VERSION 5.8 ;
BUSBITCHARS "[]" ;
DIVIDERCHAR "/" ;
UNITS
    DATABASE MICRONS 1000 ;
END UNITS

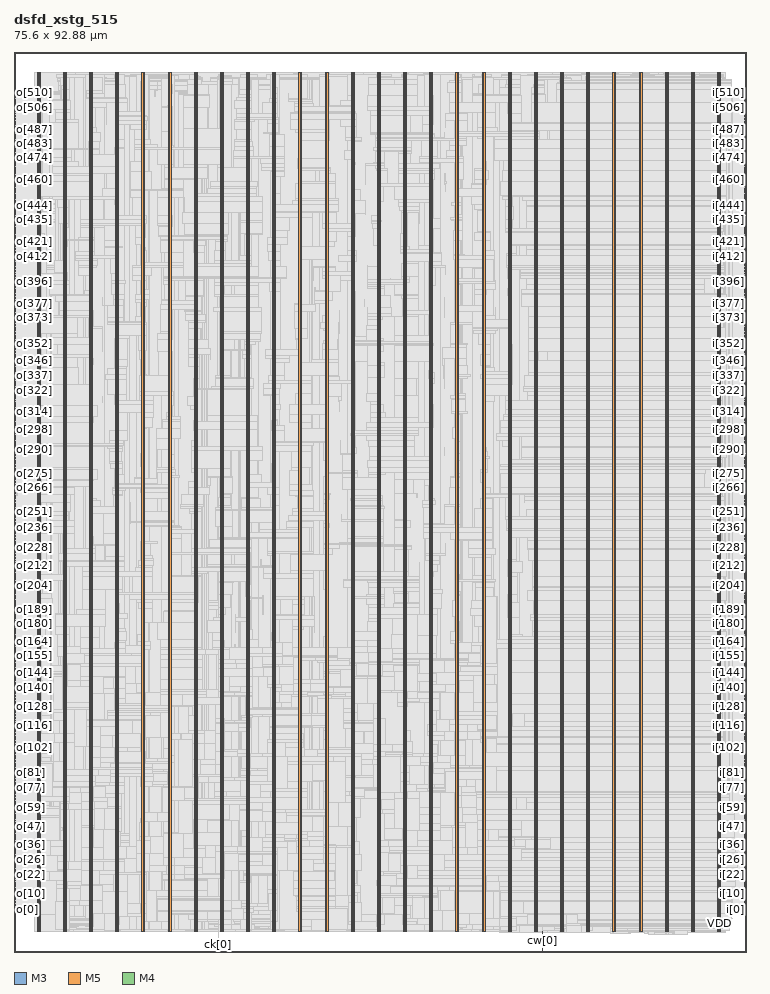
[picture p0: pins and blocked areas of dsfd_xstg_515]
MACRO dsfd_xstg_515
  FOREIGN dsfd_xstg_515 0 0 ;
  CLASS BLOCK ;
  SIZE 75.6 BY 92.88 ;
  PIN ck[0]
    DIRECTION INPUT ;
    USE SIGNAL ;
    PORT
      LAYER M3 ;
        RECT  21.06 0 21.078 0.144 ;
    END
    PORT
      LAYER M3 ;
        RECT  21.06 0.108 21.078 0.173 ;
    END
  END ck[0]
  PIN cw[0]
    DIRECTION INPUT ;
    USE SIGNAL ;
    PORT
      LAYER M5 ;
        RECT  54.528 0 54.552 0.192 ;
    END
    PORT
      LAYER M5 ;
        RECT  54.528 0.144 54.552 2.137 ;
    END
  END cw[0]
  PIN i[0]
    DIRECTION INPUT ;
    USE SIGNAL ;
    PORT
      LAYER M4 ;
        RECT  75.408 4.416 75.6 4.44 ;
    END
  END i[0]
  PIN i[100]
    DIRECTION INPUT ;
    USE SIGNAL ;
    PORT
      LAYER M4 ;
        RECT  75.408 20.784 75.6 20.808 ;
    END
  END i[100]
  PIN i[101]
    DIRECTION INPUT ;
    USE SIGNAL ;
    PORT
      LAYER M4 ;
        RECT  75.408 20.928 75.6 20.952 ;
    END
  END i[101]
  PIN i[102]
    DIRECTION INPUT ;
    USE SIGNAL ;
    PORT
      LAYER M4 ;
        RECT  75.408 21.12 75.6 21.144 ;
    END
  END i[102]
  PIN i[103]
    DIRECTION INPUT ;
    USE SIGNAL ;
    PORT
      LAYER M4 ;
        RECT  75.408 21.264 75.6 21.288 ;
    END
  END i[103]
  PIN i[104]
    DIRECTION INPUT ;
    USE SIGNAL ;
    PORT
      LAYER M4 ;
        RECT  75.408 21.408 75.6 21.432 ;
    END
  END i[104]
  PIN i[105]
    DIRECTION INPUT ;
    USE SIGNAL ;
    PORT
      LAYER M4 ;
        RECT  75.408 21.6 75.6 21.624 ;
    END
  END i[105]
  PIN i[106]
    DIRECTION INPUT ;
    USE SIGNAL ;
    PORT
      LAYER M4 ;
        RECT  75.408 21.744 75.6 21.768 ;
    END
  END i[106]
  PIN i[107]
    DIRECTION INPUT ;
    USE SIGNAL ;
    PORT
      LAYER M4 ;
        RECT  75.408 21.936 75.6 21.96 ;
    END
  END i[107]
  PIN i[108]
    DIRECTION INPUT ;
    USE SIGNAL ;
    PORT
      LAYER M4 ;
        RECT  75.408 22.08 75.6 22.104 ;
    END
  END i[108]
  PIN i[109]
    DIRECTION INPUT ;
    USE SIGNAL ;
    PORT
      LAYER M4 ;
        RECT  75.408 22.224 75.6 22.248 ;
    END
  END i[109]
  PIN i[10]
    DIRECTION INPUT ;
    USE SIGNAL ;
    PORT
      LAYER M4 ;
        RECT  75.408 6.048 75.6 6.072 ;
    END
  END i[10]
  PIN i[110]
    DIRECTION INPUT ;
    USE SIGNAL ;
    PORT
      LAYER M4 ;
        RECT  75.408 22.416 75.6 22.44 ;
    END
  END i[110]
  PIN i[111]
    DIRECTION INPUT ;
    USE SIGNAL ;
    PORT
      LAYER M4 ;
        RECT  75.408 22.56 75.6 22.584 ;
    END
  END i[111]
  PIN i[112]
    DIRECTION INPUT ;
    USE SIGNAL ;
    PORT
      LAYER M4 ;
        RECT  75.408 22.752 75.6 22.776 ;
    END
  END i[112]
  PIN i[113]
    DIRECTION INPUT ;
    USE SIGNAL ;
    PORT
      LAYER M4 ;
        RECT  75.408 22.896 75.6 22.92 ;
    END
  END i[113]
  PIN i[114]
    DIRECTION INPUT ;
    USE SIGNAL ;
    PORT
      LAYER M4 ;
        RECT  75.408 23.04 75.6 23.064 ;
    END
  END i[114]
  PIN i[115]
    DIRECTION INPUT ;
    USE SIGNAL ;
    PORT
      LAYER M4 ;
        RECT  75.408 23.232 75.6 23.256 ;
    END
  END i[115]
  PIN i[116]
    DIRECTION INPUT ;
    USE SIGNAL ;
    PORT
      LAYER M4 ;
        RECT  75.408 23.376 75.6 23.4 ;
    END
  END i[116]
  PIN i[117]
    DIRECTION INPUT ;
    USE SIGNAL ;
    PORT
      LAYER M4 ;
        RECT  75.408 23.568 75.6 23.592 ;
    END
  END i[117]
  PIN i[118]
    DIRECTION INPUT ;
    USE SIGNAL ;
    PORT
      LAYER M4 ;
        RECT  75.408 23.712 75.6 23.736 ;
    END
  END i[118]
  PIN i[119]
    DIRECTION INPUT ;
    USE SIGNAL ;
    PORT
      LAYER M4 ;
        RECT  75.408 23.856 75.6 23.88 ;
    END
  END i[119]
  PIN i[11]
    DIRECTION INPUT ;
    USE SIGNAL ;
    PORT
      LAYER M4 ;
        RECT  75.408 6.192 75.6 6.216 ;
    END
  END i[11]
  PIN i[120]
    DIRECTION INPUT ;
    USE SIGNAL ;
    PORT
      LAYER M4 ;
        RECT  75.408 24.048 75.6 24.072 ;
    END
  END i[120]
  PIN i[121]
    DIRECTION INPUT ;
    USE SIGNAL ;
    PORT
      LAYER M4 ;
        RECT  75.408 24.192 75.6 24.216 ;
    END
  END i[121]
  PIN i[122]
    DIRECTION INPUT ;
    USE SIGNAL ;
    PORT
      LAYER M4 ;
        RECT  75.408 24.384 75.6 24.408 ;
    END
  END i[122]
  PIN i[123]
    DIRECTION INPUT ;
    USE SIGNAL ;
    PORT
      LAYER M4 ;
        RECT  75.408 24.528 75.6 24.552 ;
    END
  END i[123]
  PIN i[124]
    DIRECTION INPUT ;
    USE SIGNAL ;
    PORT
      LAYER M4 ;
        RECT  75.408 24.72 75.6 24.744 ;
    END
  END i[124]
  PIN i[125]
    DIRECTION INPUT ;
    USE SIGNAL ;
    PORT
      LAYER M4 ;
        RECT  75.408 24.864 75.6 24.888 ;
    END
  END i[125]
  PIN i[126]
    DIRECTION INPUT ;
    USE SIGNAL ;
    PORT
      LAYER M4 ;
        RECT  75.408 25.008 75.6 25.032 ;
    END
  END i[126]
  PIN i[127]
    DIRECTION INPUT ;
    USE SIGNAL ;
    PORT
      LAYER M4 ;
        RECT  75.408 25.2 75.6 25.224 ;
    END
  END i[127]
  PIN i[128]
    DIRECTION INPUT ;
    USE SIGNAL ;
    PORT
      LAYER M4 ;
        RECT  75.408 25.344 75.6 25.368 ;
    END
  END i[128]
  PIN i[129]
    DIRECTION INPUT ;
    USE SIGNAL ;
    PORT
      LAYER M4 ;
        RECT  75.408 25.536 75.6 25.56 ;
    END
  END i[129]
  PIN i[12]
    DIRECTION INPUT ;
    USE SIGNAL ;
    PORT
      LAYER M4 ;
        RECT  75.408 6.384 75.6 6.408 ;
    END
  END i[12]
  PIN i[130]
    DIRECTION INPUT ;
    USE SIGNAL ;
    PORT
      LAYER M4 ;
        RECT  75.408 25.68 75.6 25.704 ;
    END
  END i[130]
  PIN i[131]
    DIRECTION INPUT ;
    USE SIGNAL ;
    PORT
      LAYER M4 ;
        RECT  75.408 25.824 75.6 25.848 ;
    END
  END i[131]
  PIN i[132]
    DIRECTION INPUT ;
    USE SIGNAL ;
    PORT
      LAYER M4 ;
        RECT  75.408 26.016 75.6 26.04 ;
    END
  END i[132]
  PIN i[133]
    DIRECTION INPUT ;
    USE SIGNAL ;
    PORT
      LAYER M4 ;
        RECT  75.408 26.16 75.6 26.184 ;
    END
  END i[133]
  PIN i[134]
    DIRECTION INPUT ;
    USE SIGNAL ;
    PORT
      LAYER M4 ;
        RECT  75.408 26.352 75.6 26.376 ;
    END
  END i[134]
  PIN i[135]
    DIRECTION INPUT ;
    USE SIGNAL ;
    PORT
      LAYER M4 ;
        RECT  75.408 26.496 75.6 26.52 ;
    END
  END i[135]
  PIN i[136]
    DIRECTION INPUT ;
    USE SIGNAL ;
    PORT
      LAYER M4 ;
        RECT  75.408 26.64 75.6 26.664 ;
    END
  END i[136]
  PIN i[137]
    DIRECTION INPUT ;
    USE SIGNAL ;
    PORT
      LAYER M4 ;
        RECT  75.408 26.832 75.6 26.856 ;
    END
  END i[137]
  PIN i[138]
    DIRECTION INPUT ;
    USE SIGNAL ;
    PORT
      LAYER M4 ;
        RECT  75.408 26.976 75.6 27 ;
    END
  END i[138]
  PIN i[139]
    DIRECTION INPUT ;
    USE SIGNAL ;
    PORT
      LAYER M4 ;
        RECT  75.408 27.168 75.6 27.192 ;
    END
  END i[139]
  PIN i[13]
    DIRECTION INPUT ;
    USE SIGNAL ;
    PORT
      LAYER M4 ;
        RECT  75.408 6.528 75.6 6.552 ;
    END
  END i[13]
  PIN i[140]
    DIRECTION INPUT ;
    USE SIGNAL ;
    PORT
      LAYER M4 ;
        RECT  75.408 27.312 75.6 27.336 ;
    END
  END i[140]
  PIN i[141]
    DIRECTION INPUT ;
    USE SIGNAL ;
    PORT
      LAYER M4 ;
        RECT  75.408 27.456 75.6 27.48 ;
    END
  END i[141]
  PIN i[142]
    DIRECTION INPUT ;
    USE SIGNAL ;
    PORT
      LAYER M4 ;
        RECT  75.408 27.648 75.6 27.672 ;
    END
  END i[142]
  PIN i[143]
    DIRECTION INPUT ;
    USE SIGNAL ;
    PORT
      LAYER M4 ;
        RECT  75.408 27.792 75.6 27.816 ;
    END
  END i[143]
  PIN i[144]
    DIRECTION INPUT ;
    USE SIGNAL ;
    PORT
      LAYER M4 ;
        RECT  75.408 27.984 75.6 28.008 ;
    END
  END i[144]
  PIN i[145]
    DIRECTION INPUT ;
    USE SIGNAL ;
    PORT
      LAYER M4 ;
        RECT  75.408 28.128 75.6 28.152 ;
    END
  END i[145]
  PIN i[146]
    DIRECTION INPUT ;
    USE SIGNAL ;
    PORT
      LAYER M4 ;
        RECT  75.408 28.272 75.6 28.296 ;
    END
  END i[146]
  PIN i[147]
    DIRECTION INPUT ;
    USE SIGNAL ;
    PORT
      LAYER M4 ;
        RECT  75.408 28.464 75.6 28.488 ;
    END
  END i[147]
  PIN i[148]
    DIRECTION INPUT ;
    USE SIGNAL ;
    PORT
      LAYER M4 ;
        RECT  75.408 28.608 75.6 28.632 ;
    END
  END i[148]
  PIN i[149]
    DIRECTION INPUT ;
    USE SIGNAL ;
    PORT
      LAYER M4 ;
        RECT  75.408 28.8 75.6 28.824 ;
    END
  END i[149]
  PIN i[14]
    DIRECTION INPUT ;
    USE SIGNAL ;
    PORT
      LAYER M4 ;
        RECT  75.408 6.72 75.6 6.744 ;
    END
  END i[14]
  PIN i[150]
    DIRECTION INPUT ;
    USE SIGNAL ;
    PORT
      LAYER M4 ;
        RECT  75.408 28.944 75.6 28.968 ;
    END
  END i[150]
  PIN i[151]
    DIRECTION INPUT ;
    USE SIGNAL ;
    PORT
      LAYER M4 ;
        RECT  75.408 29.136 75.6 29.16 ;
    END
  END i[151]
  PIN i[152]
    DIRECTION INPUT ;
    USE SIGNAL ;
    PORT
      LAYER M4 ;
        RECT  75.408 29.28 75.6 29.304 ;
    END
  END i[152]
  PIN i[153]
    DIRECTION INPUT ;
    USE SIGNAL ;
    PORT
      LAYER M4 ;
        RECT  75.408 29.424 75.6 29.448 ;
    END
  END i[153]
  PIN i[154]
    DIRECTION INPUT ;
    USE SIGNAL ;
    PORT
      LAYER M4 ;
        RECT  75.408 29.616 75.6 29.64 ;
    END
  END i[154]
  PIN i[155]
    DIRECTION INPUT ;
    USE SIGNAL ;
    PORT
      LAYER M4 ;
        RECT  75.408 29.76 75.6 29.784 ;
    END
  END i[155]
  PIN i[156]
    DIRECTION INPUT ;
    USE SIGNAL ;
    PORT
      LAYER M4 ;
        RECT  75.408 29.952 75.6 29.976 ;
    END
  END i[156]
  PIN i[157]
    DIRECTION INPUT ;
    USE SIGNAL ;
    PORT
      LAYER M4 ;
        RECT  75.408 30.096 75.6 30.12 ;
    END
  END i[157]
  PIN i[158]
    DIRECTION INPUT ;
    USE SIGNAL ;
    PORT
      LAYER M4 ;
        RECT  75.408 30.24 75.6 30.264 ;
    END
  END i[158]
  PIN i[159]
    DIRECTION INPUT ;
    USE SIGNAL ;
    PORT
      LAYER M4 ;
        RECT  75.408 30.432 75.6 30.456 ;
    END
  END i[159]
  PIN i[15]
    DIRECTION INPUT ;
    USE SIGNAL ;
    PORT
      LAYER M4 ;
        RECT  75.408 6.864 75.6 6.888 ;
    END
  END i[15]
  PIN i[160]
    DIRECTION INPUT ;
    USE SIGNAL ;
    PORT
      LAYER M4 ;
        RECT  75.408 30.576 75.6 30.6 ;
    END
  END i[160]
  PIN i[161]
    DIRECTION INPUT ;
    USE SIGNAL ;
    PORT
      LAYER M4 ;
        RECT  75.408 30.768 75.6 30.792 ;
    END
  END i[161]
  PIN i[162]
    DIRECTION INPUT ;
    USE SIGNAL ;
    PORT
      LAYER M4 ;
        RECT  75.408 30.912 75.6 30.936 ;
    END
  END i[162]
  PIN i[163]
    DIRECTION INPUT ;
    USE SIGNAL ;
    PORT
      LAYER M4 ;
        RECT  75.408 31.056 75.6 31.08 ;
    END
  END i[163]
  PIN i[164]
    DIRECTION INPUT ;
    USE SIGNAL ;
    PORT
      LAYER M4 ;
        RECT  75.408 31.248 75.6 31.272 ;
    END
  END i[164]
  PIN i[165]
    DIRECTION INPUT ;
    USE SIGNAL ;
    PORT
      LAYER M4 ;
        RECT  75.408 31.392 75.6 31.416 ;
    END
  END i[165]
  PIN i[166]
    DIRECTION INPUT ;
    USE SIGNAL ;
    PORT
      LAYER M4 ;
        RECT  75.408 31.584 75.6 31.608 ;
    END
  END i[166]
  PIN i[167]
    DIRECTION INPUT ;
    USE SIGNAL ;
    PORT
      LAYER M4 ;
        RECT  75.408 31.728 75.6 31.752 ;
    END
  END i[167]
  PIN i[168]
    DIRECTION INPUT ;
    USE SIGNAL ;
    PORT
      LAYER M4 ;
        RECT  75.408 31.872 75.6 31.896 ;
    END
  END i[168]
  PIN i[169]
    DIRECTION INPUT ;
    USE SIGNAL ;
    PORT
      LAYER M4 ;
        RECT  75.408 32.064 75.6 32.088 ;
    END
  END i[169]
  PIN i[16]
    DIRECTION INPUT ;
    USE SIGNAL ;
    PORT
      LAYER M4 ;
        RECT  75.408 7.008 75.6 7.032 ;
    END
  END i[16]
  PIN i[170]
    DIRECTION INPUT ;
    USE SIGNAL ;
    PORT
      LAYER M4 ;
        RECT  75.408 32.208 75.6 32.232 ;
    END
  END i[170]
  PIN i[171]
    DIRECTION INPUT ;
    USE SIGNAL ;
    PORT
      LAYER M4 ;
        RECT  75.408 32.4 75.6 32.424 ;
    END
  END i[171]
  PIN i[172]
    DIRECTION INPUT ;
    USE SIGNAL ;
    PORT
      LAYER M4 ;
        RECT  75.408 32.544 75.6 32.568 ;
    END
  END i[172]
  PIN i[173]
    DIRECTION INPUT ;
    USE SIGNAL ;
    PORT
      LAYER M4 ;
        RECT  75.408 32.688 75.6 32.712 ;
    END
  END i[173]
  PIN i[174]
    DIRECTION INPUT ;
    USE SIGNAL ;
    PORT
      LAYER M4 ;
        RECT  75.408 32.88 75.6 32.904 ;
    END
  END i[174]
  PIN i[175]
    DIRECTION INPUT ;
    USE SIGNAL ;
    PORT
      LAYER M4 ;
        RECT  75.408 33.024 75.6 33.048 ;
    END
  END i[175]
  PIN i[176]
    DIRECTION INPUT ;
    USE SIGNAL ;
    PORT
      LAYER M4 ;
        RECT  75.408 33.216 75.6 33.24 ;
    END
  END i[176]
  PIN i[177]
    DIRECTION INPUT ;
    USE SIGNAL ;
    PORT
      LAYER M4 ;
        RECT  75.408 33.36 75.6 33.384 ;
    END
  END i[177]
  PIN i[178]
    DIRECTION INPUT ;
    USE SIGNAL ;
    PORT
      LAYER M4 ;
        RECT  75.408 33.552 75.6 33.576 ;
    END
  END i[178]
  PIN i[179]
    DIRECTION INPUT ;
    USE SIGNAL ;
    PORT
      LAYER M4 ;
        RECT  75.408 33.696 75.6 33.72 ;
    END
  END i[179]
  PIN i[17]
    DIRECTION INPUT ;
    USE SIGNAL ;
    PORT
      LAYER M4 ;
        RECT  75.408 7.2 75.6 7.224 ;
    END
  END i[17]
  PIN i[180]
    DIRECTION INPUT ;
    USE SIGNAL ;
    PORT
      LAYER M4 ;
        RECT  75.408 33.84 75.6 33.864 ;
    END
  END i[180]
  PIN i[181]
    DIRECTION INPUT ;
    USE SIGNAL ;
    PORT
      LAYER M4 ;
        RECT  75.408 34.032 75.6 34.056 ;
    END
  END i[181]
  PIN i[182]
    DIRECTION INPUT ;
    USE SIGNAL ;
    PORT
      LAYER M4 ;
        RECT  75.408 34.176 75.6 34.2 ;
    END
  END i[182]
  PIN i[183]
    DIRECTION INPUT ;
    USE SIGNAL ;
    PORT
      LAYER M4 ;
        RECT  75.408 34.368 75.6 34.392 ;
    END
  END i[183]
  PIN i[184]
    DIRECTION INPUT ;
    USE SIGNAL ;
    PORT
      LAYER M4 ;
        RECT  75.408 34.512 75.6 34.536 ;
    END
  END i[184]
  PIN i[185]
    DIRECTION INPUT ;
    USE SIGNAL ;
    PORT
      LAYER M4 ;
        RECT  75.408 34.656 75.6 34.68 ;
    END
  END i[185]
  PIN i[186]
    DIRECTION INPUT ;
    USE SIGNAL ;
    PORT
      LAYER M4 ;
        RECT  75.408 34.848 75.6 34.872 ;
    END
  END i[186]
  PIN i[187]
    DIRECTION INPUT ;
    USE SIGNAL ;
    PORT
      LAYER M4 ;
        RECT  75.408 34.992 75.6 35.016 ;
    END
  END i[187]
  PIN i[188]
    DIRECTION INPUT ;
    USE SIGNAL ;
    PORT
      LAYER M4 ;
        RECT  75.408 35.184 75.6 35.208 ;
    END
  END i[188]
  PIN i[189]
    DIRECTION INPUT ;
    USE SIGNAL ;
    PORT
      LAYER M4 ;
        RECT  75.408 35.328 75.6 35.352 ;
    END
  END i[189]
  PIN i[18]
    DIRECTION INPUT ;
    USE SIGNAL ;
    PORT
      LAYER M4 ;
        RECT  75.408 7.344 75.6 7.368 ;
    END
  END i[18]
  PIN i[190]
    DIRECTION INPUT ;
    USE SIGNAL ;
    PORT
      LAYER M4 ;
        RECT  75.408 35.472 75.6 35.496 ;
    END
  END i[190]
  PIN i[191]
    DIRECTION INPUT ;
    USE SIGNAL ;
    PORT
      LAYER M4 ;
        RECT  75.408 35.664 75.6 35.688 ;
    END
  END i[191]
  PIN i[192]
    DIRECTION INPUT ;
    USE SIGNAL ;
    PORT
      LAYER M4 ;
        RECT  75.408 35.808 75.6 35.832 ;
    END
  END i[192]
  PIN i[193]
    DIRECTION INPUT ;
    USE SIGNAL ;
    PORT
      LAYER M4 ;
        RECT  75.408 36 75.6 36.024 ;
    END
  END i[193]
  PIN i[194]
    DIRECTION INPUT ;
    USE SIGNAL ;
    PORT
      LAYER M4 ;
        RECT  75.408 36.144 75.6 36.168 ;
    END
  END i[194]
  PIN i[195]
    DIRECTION INPUT ;
    USE SIGNAL ;
    PORT
      LAYER M4 ;
        RECT  75.408 36.288 75.6 36.312 ;
    END
  END i[195]
  PIN i[196]
    DIRECTION INPUT ;
    USE SIGNAL ;
    PORT
      LAYER M4 ;
        RECT  75.408 36.48 75.6 36.504 ;
    END
  END i[196]
  PIN i[197]
    DIRECTION INPUT ;
    USE SIGNAL ;
    PORT
      LAYER M4 ;
        RECT  75.408 36.624 75.6 36.648 ;
    END
  END i[197]
  PIN i[198]
    DIRECTION INPUT ;
    USE SIGNAL ;
    PORT
      LAYER M4 ;
        RECT  75.408 36.816 75.6 36.84 ;
    END
  END i[198]
  PIN i[199]
    DIRECTION INPUT ;
    USE SIGNAL ;
    PORT
      LAYER M4 ;
        RECT  75.408 36.96 75.6 36.984 ;
    END
  END i[199]
  PIN i[19]
    DIRECTION INPUT ;
    USE SIGNAL ;
    PORT
      LAYER M4 ;
        RECT  75.408 7.536 75.6 7.56 ;
    END
  END i[19]
  PIN i[1]
    DIRECTION INPUT ;
    USE SIGNAL ;
    PORT
      LAYER M4 ;
        RECT  75.408 4.56 75.6 4.584 ;
    END
  END i[1]
  PIN i[200]
    DIRECTION INPUT ;
    USE SIGNAL ;
    PORT
      LAYER M4 ;
        RECT  75.408 37.152 75.6 37.176 ;
    END
  END i[200]
  PIN i[201]
    DIRECTION INPUT ;
    USE SIGNAL ;
    PORT
      LAYER M4 ;
        RECT  75.408 37.296 75.6 37.32 ;
    END
  END i[201]
  PIN i[202]
    DIRECTION INPUT ;
    USE SIGNAL ;
    PORT
      LAYER M4 ;
        RECT  75.408 37.44 75.6 37.464 ;
    END
  END i[202]
  PIN i[203]
    DIRECTION INPUT ;
    USE SIGNAL ;
    PORT
      LAYER M4 ;
        RECT  75.408 37.632 75.6 37.656 ;
    END
  END i[203]
  PIN i[204]
    DIRECTION INPUT ;
    USE SIGNAL ;
    PORT
      LAYER M4 ;
        RECT  75.408 37.776 75.6 37.8 ;
    END
  END i[204]
  PIN i[205]
    DIRECTION INPUT ;
    USE SIGNAL ;
    PORT
      LAYER M4 ;
        RECT  75.408 37.968 75.6 37.992 ;
    END
  END i[205]
  PIN i[206]
    DIRECTION INPUT ;
    USE SIGNAL ;
    PORT
      LAYER M4 ;
        RECT  75.408 38.112 75.6 38.136 ;
    END
  END i[206]
  PIN i[207]
    DIRECTION INPUT ;
    USE SIGNAL ;
    PORT
      LAYER M4 ;
        RECT  75.408 38.256 75.6 38.28 ;
    END
  END i[207]
  PIN i[208]
    DIRECTION INPUT ;
    USE SIGNAL ;
    PORT
      LAYER M4 ;
        RECT  75.408 38.448 75.6 38.472 ;
    END
  END i[208]
  PIN i[209]
    DIRECTION INPUT ;
    USE SIGNAL ;
    PORT
      LAYER M4 ;
        RECT  75.408 38.592 75.6 38.616 ;
    END
  END i[209]
  PIN i[20]
    DIRECTION INPUT ;
    USE SIGNAL ;
    PORT
      LAYER M4 ;
        RECT  75.408 7.68 75.6 7.704 ;
    END
  END i[20]
  PIN i[210]
    DIRECTION INPUT ;
    USE SIGNAL ;
    PORT
      LAYER M4 ;
        RECT  75.408 38.784 75.6 38.808 ;
    END
  END i[210]
  PIN i[211]
    DIRECTION INPUT ;
    USE SIGNAL ;
    PORT
      LAYER M4 ;
        RECT  75.408 38.928 75.6 38.952 ;
    END
  END i[211]
  PIN i[212]
    DIRECTION INPUT ;
    USE SIGNAL ;
    PORT
      LAYER M4 ;
        RECT  75.408 39.072 75.6 39.096 ;
    END
  END i[212]
  PIN i[213]
    DIRECTION INPUT ;
    USE SIGNAL ;
    PORT
      LAYER M4 ;
        RECT  75.408 39.264 75.6 39.288 ;
    END
  END i[213]
  PIN i[214]
    DIRECTION INPUT ;
    USE SIGNAL ;
    PORT
      LAYER M4 ;
        RECT  75.408 39.408 75.6 39.432 ;
    END
  END i[214]
  PIN i[215]
    DIRECTION INPUT ;
    USE SIGNAL ;
    PORT
      LAYER M4 ;
        RECT  75.408 39.6 75.6 39.624 ;
    END
  END i[215]
  PIN i[216]
    DIRECTION INPUT ;
    USE SIGNAL ;
    PORT
      LAYER M4 ;
        RECT  75.408 39.744 75.6 39.768 ;
    END
  END i[216]
  PIN i[217]
    DIRECTION INPUT ;
    USE SIGNAL ;
    PORT
      LAYER M4 ;
        RECT  75.408 39.888 75.6 39.912 ;
    END
  END i[217]
  PIN i[218]
    DIRECTION INPUT ;
    USE SIGNAL ;
    PORT
      LAYER M4 ;
        RECT  75.408 40.08 75.6 40.104 ;
    END
  END i[218]
  PIN i[219]
    DIRECTION INPUT ;
    USE SIGNAL ;
    PORT
      LAYER M4 ;
        RECT  75.408 40.224 75.6 40.248 ;
    END
  END i[219]
  PIN i[21]
    DIRECTION INPUT ;
    USE SIGNAL ;
    PORT
      LAYER M4 ;
        RECT  75.408 7.872 75.6 7.896 ;
    END
  END i[21]
  PIN i[220]
    DIRECTION INPUT ;
    USE SIGNAL ;
    PORT
      LAYER M4 ;
        RECT  75.408 40.416 75.6 40.44 ;
    END
  END i[220]
  PIN i[221]
    DIRECTION INPUT ;
    USE SIGNAL ;
    PORT
      LAYER M4 ;
        RECT  75.408 40.56 75.6 40.584 ;
    END
  END i[221]
  PIN i[222]
    DIRECTION INPUT ;
    USE SIGNAL ;
    PORT
      LAYER M4 ;
        RECT  75.408 40.704 75.6 40.728 ;
    END
  END i[222]
  PIN i[223]
    DIRECTION INPUT ;
    USE SIGNAL ;
    PORT
      LAYER M4 ;
        RECT  75.408 40.896 75.6 40.92 ;
    END
  END i[223]
  PIN i[224]
    DIRECTION INPUT ;
    USE SIGNAL ;
    PORT
      LAYER M4 ;
        RECT  75.408 41.04 75.6 41.064 ;
    END
  END i[224]
  PIN i[225]
    DIRECTION INPUT ;
    USE SIGNAL ;
    PORT
      LAYER M4 ;
        RECT  75.408 41.232 75.6 41.256 ;
    END
  END i[225]
  PIN i[226]
    DIRECTION INPUT ;
    USE SIGNAL ;
    PORT
      LAYER M4 ;
        RECT  75.408 41.376 75.6 41.4 ;
    END
  END i[226]
  PIN i[227]
    DIRECTION INPUT ;
    USE SIGNAL ;
    PORT
      LAYER M4 ;
        RECT  75.408 41.568 75.6 41.592 ;
    END
  END i[227]
  PIN i[228]
    DIRECTION INPUT ;
    USE SIGNAL ;
    PORT
      LAYER M4 ;
        RECT  75.408 41.712 75.6 41.736 ;
    END
  END i[228]
  PIN i[229]
    DIRECTION INPUT ;
    USE SIGNAL ;
    PORT
      LAYER M4 ;
        RECT  75.408 41.856 75.6 41.88 ;
    END
  END i[229]
  PIN i[22]
    DIRECTION INPUT ;
    USE SIGNAL ;
    PORT
      LAYER M4 ;
        RECT  75.408 8.016 75.6 8.04 ;
    END
  END i[22]
  PIN i[230]
    DIRECTION INPUT ;
    USE SIGNAL ;
    PORT
      LAYER M4 ;
        RECT  75.408 42.048 75.6 42.072 ;
    END
  END i[230]
  PIN i[231]
    DIRECTION INPUT ;
    USE SIGNAL ;
    PORT
      LAYER M4 ;
        RECT  75.408 42.192 75.6 42.216 ;
    END
  END i[231]
  PIN i[232]
    DIRECTION INPUT ;
    USE SIGNAL ;
    PORT
      LAYER M4 ;
        RECT  75.408 42.384 75.6 42.408 ;
    END
  END i[232]
  PIN i[233]
    DIRECTION INPUT ;
    USE SIGNAL ;
    PORT
      LAYER M4 ;
        RECT  75.408 42.528 75.6 42.552 ;
    END
  END i[233]
  PIN i[234]
    DIRECTION INPUT ;
    USE SIGNAL ;
    PORT
      LAYER M4 ;
        RECT  75.408 42.672 75.6 42.696 ;
    END
  END i[234]
  PIN i[235]
    DIRECTION INPUT ;
    USE SIGNAL ;
    PORT
      LAYER M4 ;
        RECT  75.408 42.864 75.6 42.888 ;
    END
  END i[235]
  PIN i[236]
    DIRECTION INPUT ;
    USE SIGNAL ;
    PORT
      LAYER M4 ;
        RECT  75.408 43.008 75.6 43.032 ;
    END
  END i[236]
  PIN i[237]
    DIRECTION INPUT ;
    USE SIGNAL ;
    PORT
      LAYER M4 ;
        RECT  75.408 43.2 75.6 43.224 ;
    END
  END i[237]
  PIN i[238]
    DIRECTION INPUT ;
    USE SIGNAL ;
    PORT
      LAYER M4 ;
        RECT  75.408 43.344 75.6 43.368 ;
    END
  END i[238]
  PIN i[239]
    DIRECTION INPUT ;
    USE SIGNAL ;
    PORT
      LAYER M4 ;
        RECT  75.408 43.488 75.6 43.512 ;
    END
  END i[239]
  PIN i[23]
    DIRECTION INPUT ;
    USE SIGNAL ;
    PORT
      LAYER M4 ;
        RECT  75.408 8.16 75.6 8.184 ;
    END
  END i[23]
  PIN i[240]
    DIRECTION INPUT ;
    USE SIGNAL ;
    PORT
      LAYER M4 ;
        RECT  75.408 43.68 75.6 43.704 ;
    END
  END i[240]
  PIN i[241]
    DIRECTION INPUT ;
    USE SIGNAL ;
    PORT
      LAYER M4 ;
        RECT  75.408 43.824 75.6 43.848 ;
    END
  END i[241]
  PIN i[242]
    DIRECTION INPUT ;
    USE SIGNAL ;
    PORT
      LAYER M4 ;
        RECT  75.408 44.016 75.6 44.04 ;
    END
  END i[242]
  PIN i[243]
    DIRECTION INPUT ;
    USE SIGNAL ;
    PORT
      LAYER M4 ;
        RECT  75.408 44.16 75.6 44.184 ;
    END
  END i[243]
  PIN i[244]
    DIRECTION INPUT ;
    USE SIGNAL ;
    PORT
      LAYER M4 ;
        RECT  75.408 44.304 75.6 44.328 ;
    END
  END i[244]
  PIN i[245]
    DIRECTION INPUT ;
    USE SIGNAL ;
    PORT
      LAYER M4 ;
        RECT  75.408 44.496 75.6 44.52 ;
    END
  END i[245]
  PIN i[246]
    DIRECTION INPUT ;
    USE SIGNAL ;
    PORT
      LAYER M4 ;
        RECT  75.408 44.64 75.6 44.664 ;
    END
  END i[246]
  PIN i[247]
    DIRECTION INPUT ;
    USE SIGNAL ;
    PORT
      LAYER M4 ;
        RECT  75.408 44.832 75.6 44.856 ;
    END
  END i[247]
  PIN i[248]
    DIRECTION INPUT ;
    USE SIGNAL ;
    PORT
      LAYER M4 ;
        RECT  75.408 44.976 75.6 45 ;
    END
  END i[248]
  PIN i[249]
    DIRECTION INPUT ;
    USE SIGNAL ;
    PORT
      LAYER M4 ;
        RECT  75.408 45.12 75.6 45.144 ;
    END
  END i[249]
  PIN i[24]
    DIRECTION INPUT ;
    USE SIGNAL ;
    PORT
      LAYER M4 ;
        RECT  75.408 8.352 75.6 8.376 ;
    END
  END i[24]
  PIN i[250]
    DIRECTION INPUT ;
    USE SIGNAL ;
    PORT
      LAYER M4 ;
        RECT  75.408 45.312 75.6 45.336 ;
    END
  END i[250]
  PIN i[251]
    DIRECTION INPUT ;
    USE SIGNAL ;
    PORT
      LAYER M4 ;
        RECT  75.408 45.456 75.6 45.48 ;
    END
  END i[251]
  PIN i[252]
    DIRECTION INPUT ;
    USE SIGNAL ;
    PORT
      LAYER M4 ;
        RECT  75.408 45.648 75.6 45.672 ;
    END
  END i[252]
  PIN i[253]
    DIRECTION INPUT ;
    USE SIGNAL ;
    PORT
      LAYER M4 ;
        RECT  75.408 45.792 75.6 45.816 ;
    END
  END i[253]
  PIN i[254]
    DIRECTION INPUT ;
    USE SIGNAL ;
    PORT
      LAYER M4 ;
        RECT  75.408 45.984 75.6 46.008 ;
    END
  END i[254]
  PIN i[255]
    DIRECTION INPUT ;
    USE SIGNAL ;
    PORT
      LAYER M4 ;
        RECT  75.408 46.128 75.6 46.152 ;
    END
  END i[255]
  PIN i[256]
    DIRECTION INPUT ;
    USE SIGNAL ;
    PORT
      LAYER M4 ;
        RECT  75.408 46.272 75.6 46.296 ;
    END
  END i[256]
  PIN i[257]
    DIRECTION INPUT ;
    USE SIGNAL ;
    PORT
      LAYER M4 ;
        RECT  75.408 46.464 75.6 46.488 ;
    END
  END i[257]
  PIN i[258]
    DIRECTION INPUT ;
    USE SIGNAL ;
    PORT
      LAYER M4 ;
        RECT  75.408 46.608 75.6 46.632 ;
    END
  END i[258]
  PIN i[259]
    DIRECTION INPUT ;
    USE SIGNAL ;
    PORT
      LAYER M4 ;
        RECT  75.408 46.8 75.6 46.824 ;
    END
  END i[259]
  PIN i[25]
    DIRECTION INPUT ;
    USE SIGNAL ;
    PORT
      LAYER M4 ;
        RECT  75.408 8.496 75.6 8.52 ;
    END
  END i[25]
  PIN i[260]
    DIRECTION INPUT ;
    USE SIGNAL ;
    PORT
      LAYER M4 ;
        RECT  75.408 46.944 75.6 46.968 ;
    END
  END i[260]
  PIN i[261]
    DIRECTION INPUT ;
    USE SIGNAL ;
    PORT
      LAYER M4 ;
        RECT  75.408 47.088 75.6 47.112 ;
    END
  END i[261]
  PIN i[262]
    DIRECTION INPUT ;
    USE SIGNAL ;
    PORT
      LAYER M4 ;
        RECT  75.408 47.28 75.6 47.304 ;
    END
  END i[262]
  PIN i[263]
    DIRECTION INPUT ;
    USE SIGNAL ;
    PORT
      LAYER M4 ;
        RECT  75.408 47.424 75.6 47.448 ;
    END
  END i[263]
  PIN i[264]
    DIRECTION INPUT ;
    USE SIGNAL ;
    PORT
      LAYER M4 ;
        RECT  75.408 47.616 75.6 47.64 ;
    END
  END i[264]
  PIN i[265]
    DIRECTION INPUT ;
    USE SIGNAL ;
    PORT
      LAYER M4 ;
        RECT  75.408 47.76 75.6 47.784 ;
    END
  END i[265]
  PIN i[266]
    DIRECTION INPUT ;
    USE SIGNAL ;
    PORT
      LAYER M4 ;
        RECT  75.408 47.904 75.6 47.928 ;
    END
  END i[266]
  PIN i[267]
    DIRECTION INPUT ;
    USE SIGNAL ;
    PORT
      LAYER M4 ;
        RECT  75.408 48.096 75.6 48.12 ;
    END
  END i[267]
  PIN i[268]
    DIRECTION INPUT ;
    USE SIGNAL ;
    PORT
      LAYER M4 ;
        RECT  75.408 48.24 75.6 48.264 ;
    END
  END i[268]
  PIN i[269]
    DIRECTION INPUT ;
    USE SIGNAL ;
    PORT
      LAYER M4 ;
        RECT  75.408 48.432 75.6 48.456 ;
    END
  END i[269]
  PIN i[26]
    DIRECTION INPUT ;
    USE SIGNAL ;
    PORT
      LAYER M4 ;
        RECT  75.408 8.688 75.6 8.712 ;
    END
  END i[26]
  PIN i[270]
    DIRECTION INPUT ;
    USE SIGNAL ;
    PORT
      LAYER M4 ;
        RECT  75.408 48.576 75.6 48.6 ;
    END
  END i[270]
  PIN i[271]
    DIRECTION INPUT ;
    USE SIGNAL ;
    PORT
      LAYER M4 ;
        RECT  75.408 48.72 75.6 48.744 ;
    END
  END i[271]
  PIN i[272]
    DIRECTION INPUT ;
    USE SIGNAL ;
    PORT
      LAYER M4 ;
        RECT  75.408 48.912 75.6 48.936 ;
    END
  END i[272]
  PIN i[273]
    DIRECTION INPUT ;
    USE SIGNAL ;
    PORT
      LAYER M4 ;
        RECT  75.408 49.056 75.6 49.08 ;
    END
  END i[273]
  PIN i[274]
    DIRECTION INPUT ;
    USE SIGNAL ;
    PORT
      LAYER M4 ;
        RECT  75.408 49.248 75.6 49.272 ;
    END
  END i[274]
  PIN i[275]
    DIRECTION INPUT ;
    USE SIGNAL ;
    PORT
      LAYER M4 ;
        RECT  75.408 49.392 75.6 49.416 ;
    END
  END i[275]
  PIN i[276]
    DIRECTION INPUT ;
    USE SIGNAL ;
    PORT
      LAYER M4 ;
        RECT  75.408 49.536 75.6 49.56 ;
    END
  END i[276]
  PIN i[277]
    DIRECTION INPUT ;
    USE SIGNAL ;
    PORT
      LAYER M4 ;
        RECT  75.408 49.728 75.6 49.752 ;
    END
  END i[277]
  PIN i[278]
    DIRECTION INPUT ;
    USE SIGNAL ;
    PORT
      LAYER M4 ;
        RECT  75.408 49.872 75.6 49.896 ;
    END
  END i[278]
  PIN i[279]
    DIRECTION INPUT ;
    USE SIGNAL ;
    PORT
      LAYER M4 ;
        RECT  75.408 50.064 75.6 50.088 ;
    END
  END i[279]
  PIN i[27]
    DIRECTION INPUT ;
    USE SIGNAL ;
    PORT
      LAYER M4 ;
        RECT  75.408 8.832 75.6 8.856 ;
    END
  END i[27]
  PIN i[280]
    DIRECTION INPUT ;
    USE SIGNAL ;
    PORT
      LAYER M4 ;
        RECT  75.408 50.208 75.6 50.232 ;
    END
  END i[280]
  PIN i[281]
    DIRECTION INPUT ;
    USE SIGNAL ;
    PORT
      LAYER M4 ;
        RECT  75.408 50.4 75.6 50.424 ;
    END
  END i[281]
  PIN i[282]
    DIRECTION INPUT ;
    USE SIGNAL ;
    PORT
      LAYER M4 ;
        RECT  75.408 50.544 75.6 50.568 ;
    END
  END i[282]
  PIN i[283]
    DIRECTION INPUT ;
    USE SIGNAL ;
    PORT
      LAYER M4 ;
        RECT  75.408 50.688 75.6 50.712 ;
    END
  END i[283]
  PIN i[284]
    DIRECTION INPUT ;
    USE SIGNAL ;
    PORT
      LAYER M4 ;
        RECT  75.408 50.88 75.6 50.904 ;
    END
  END i[284]
  PIN i[285]
    DIRECTION INPUT ;
    USE SIGNAL ;
    PORT
      LAYER M4 ;
        RECT  75.408 51.024 75.6 51.048 ;
    END
  END i[285]
  PIN i[286]
    DIRECTION INPUT ;
    USE SIGNAL ;
    PORT
      LAYER M4 ;
        RECT  75.408 51.216 75.6 51.24 ;
    END
  END i[286]
  PIN i[287]
    DIRECTION INPUT ;
    USE SIGNAL ;
    PORT
      LAYER M4 ;
        RECT  75.408 51.36 75.6 51.384 ;
    END
  END i[287]
  PIN i[288]
    DIRECTION INPUT ;
    USE SIGNAL ;
    PORT
      LAYER M4 ;
        RECT  75.408 51.504 75.6 51.528 ;
    END
  END i[288]
  PIN i[289]
    DIRECTION INPUT ;
    USE SIGNAL ;
    PORT
      LAYER M4 ;
        RECT  75.408 51.696 75.6 51.72 ;
    END
  END i[289]
  PIN i[28]
    DIRECTION INPUT ;
    USE SIGNAL ;
    PORT
      LAYER M4 ;
        RECT  75.408 8.976 75.6 9 ;
    END
  END i[28]
  PIN i[290]
    DIRECTION INPUT ;
    USE SIGNAL ;
    PORT
      LAYER M4 ;
        RECT  75.408 51.84 75.6 51.864 ;
    END
  END i[290]
  PIN i[291]
    DIRECTION INPUT ;
    USE SIGNAL ;
    PORT
      LAYER M4 ;
        RECT  75.408 52.032 75.6 52.056 ;
    END
  END i[291]
  PIN i[292]
    DIRECTION INPUT ;
    USE SIGNAL ;
    PORT
      LAYER M4 ;
        RECT  75.408 52.176 75.6 52.2 ;
    END
  END i[292]
  PIN i[293]
    DIRECTION INPUT ;
    USE SIGNAL ;
    PORT
      LAYER M4 ;
        RECT  75.408 52.32 75.6 52.344 ;
    END
  END i[293]
  PIN i[294]
    DIRECTION INPUT ;
    USE SIGNAL ;
    PORT
      LAYER M4 ;
        RECT  75.408 52.512 75.6 52.536 ;
    END
  END i[294]
  PIN i[295]
    DIRECTION INPUT ;
    USE SIGNAL ;
    PORT
      LAYER M4 ;
        RECT  75.408 52.656 75.6 52.68 ;
    END
  END i[295]
  PIN i[296]
    DIRECTION INPUT ;
    USE SIGNAL ;
    PORT
      LAYER M4 ;
        RECT  75.408 52.848 75.6 52.872 ;
    END
  END i[296]
  PIN i[297]
    DIRECTION INPUT ;
    USE SIGNAL ;
    PORT
      LAYER M4 ;
        RECT  75.408 52.992 75.6 53.016 ;
    END
  END i[297]
  PIN i[298]
    DIRECTION INPUT ;
    USE SIGNAL ;
    PORT
      LAYER M4 ;
        RECT  75.408 53.136 75.6 53.16 ;
    END
  END i[298]
  PIN i[299]
    DIRECTION INPUT ;
    USE SIGNAL ;
    PORT
      LAYER M4 ;
        RECT  75.408 53.328 75.6 53.352 ;
    END
  END i[299]
  PIN i[29]
    DIRECTION INPUT ;
    USE SIGNAL ;
    PORT
      LAYER M4 ;
        RECT  75.408 9.168 75.6 9.192 ;
    END
  END i[29]
  PIN i[2]
    DIRECTION INPUT ;
    USE SIGNAL ;
    PORT
      LAYER M4 ;
        RECT  75.408 4.752 75.6 4.776 ;
    END
  END i[2]
  PIN i[300]
    DIRECTION INPUT ;
    USE SIGNAL ;
    PORT
      LAYER M4 ;
        RECT  75.408 53.472 75.6 53.496 ;
    END
  END i[300]
  PIN i[301]
    DIRECTION INPUT ;
    USE SIGNAL ;
    PORT
      LAYER M4 ;
        RECT  75.408 53.664 75.6 53.688 ;
    END
  END i[301]
  PIN i[302]
    DIRECTION INPUT ;
    USE SIGNAL ;
    PORT
      LAYER M4 ;
        RECT  75.408 53.808 75.6 53.832 ;
    END
  END i[302]
  PIN i[303]
    DIRECTION INPUT ;
    USE SIGNAL ;
    PORT
      LAYER M4 ;
        RECT  75.408 54 75.6 54.024 ;
    END
  END i[303]
  PIN i[304]
    DIRECTION INPUT ;
    USE SIGNAL ;
    PORT
      LAYER M4 ;
        RECT  75.408 54.144 75.6 54.168 ;
    END
  END i[304]
  PIN i[305]
    DIRECTION INPUT ;
    USE SIGNAL ;
    PORT
      LAYER M4 ;
        RECT  75.408 54.288 75.6 54.312 ;
    END
  END i[305]
  PIN i[306]
    DIRECTION INPUT ;
    USE SIGNAL ;
    PORT
      LAYER M4 ;
        RECT  75.408 54.48 75.6 54.504 ;
    END
  END i[306]
  PIN i[307]
    DIRECTION INPUT ;
    USE SIGNAL ;
    PORT
      LAYER M4 ;
        RECT  75.408 54.624 75.6 54.648 ;
    END
  END i[307]
  PIN i[308]
    DIRECTION INPUT ;
    USE SIGNAL ;
    PORT
      LAYER M4 ;
        RECT  75.408 54.816 75.6 54.84 ;
    END
  END i[308]
  PIN i[309]
    DIRECTION INPUT ;
    USE SIGNAL ;
    PORT
      LAYER M4 ;
        RECT  75.408 54.96 75.6 54.984 ;
    END
  END i[309]
  PIN i[30]
    DIRECTION INPUT ;
    USE SIGNAL ;
    PORT
      LAYER M4 ;
        RECT  75.408 9.312 75.6 9.336 ;
    END
  END i[30]
  PIN i[310]
    DIRECTION INPUT ;
    USE SIGNAL ;
    PORT
      LAYER M4 ;
        RECT  75.408 55.104 75.6 55.128 ;
    END
  END i[310]
  PIN i[311]
    DIRECTION INPUT ;
    USE SIGNAL ;
    PORT
      LAYER M4 ;
        RECT  75.408 55.296 75.6 55.32 ;
    END
  END i[311]
  PIN i[312]
    DIRECTION INPUT ;
    USE SIGNAL ;
    PORT
      LAYER M4 ;
        RECT  75.408 55.44 75.6 55.464 ;
    END
  END i[312]
  PIN i[313]
    DIRECTION INPUT ;
    USE SIGNAL ;
    PORT
      LAYER M4 ;
        RECT  75.408 55.632 75.6 55.656 ;
    END
  END i[313]
  PIN i[314]
    DIRECTION INPUT ;
    USE SIGNAL ;
    PORT
      LAYER M4 ;
        RECT  75.408 55.776 75.6 55.8 ;
    END
  END i[314]
  PIN i[315]
    DIRECTION INPUT ;
    USE SIGNAL ;
    PORT
      LAYER M4 ;
        RECT  75.408 55.92 75.6 55.944 ;
    END
  END i[315]
  PIN i[316]
    DIRECTION INPUT ;
    USE SIGNAL ;
    PORT
      LAYER M4 ;
        RECT  75.408 56.112 75.6 56.136 ;
    END
  END i[316]
  PIN i[317]
    DIRECTION INPUT ;
    USE SIGNAL ;
    PORT
      LAYER M4 ;
        RECT  75.408 56.256 75.6 56.28 ;
    END
  END i[317]
  PIN i[318]
    DIRECTION INPUT ;
    USE SIGNAL ;
    PORT
      LAYER M4 ;
        RECT  75.408 56.448 75.6 56.472 ;
    END
  END i[318]
  PIN i[319]
    DIRECTION INPUT ;
    USE SIGNAL ;
    PORT
      LAYER M4 ;
        RECT  75.408 56.592 75.6 56.616 ;
    END
  END i[319]
  PIN i[31]
    DIRECTION INPUT ;
    USE SIGNAL ;
    PORT
      LAYER M4 ;
        RECT  75.408 9.504 75.6 9.528 ;
    END
  END i[31]
  PIN i[320]
    DIRECTION INPUT ;
    USE SIGNAL ;
    PORT
      LAYER M4 ;
        RECT  75.408 56.736 75.6 56.76 ;
    END
  END i[320]
  PIN i[321]
    DIRECTION INPUT ;
    USE SIGNAL ;
    PORT
      LAYER M4 ;
        RECT  75.408 56.928 75.6 56.952 ;
    END
  END i[321]
  PIN i[322]
    DIRECTION INPUT ;
    USE SIGNAL ;
    PORT
      LAYER M4 ;
        RECT  75.408 57.072 75.6 57.096 ;
    END
  END i[322]
  PIN i[323]
    DIRECTION INPUT ;
    USE SIGNAL ;
    PORT
      LAYER M4 ;
        RECT  75.408 57.264 75.6 57.288 ;
    END
  END i[323]
  PIN i[324]
    DIRECTION INPUT ;
    USE SIGNAL ;
    PORT
      LAYER M4 ;
        RECT  75.408 57.408 75.6 57.432 ;
    END
  END i[324]
  PIN i[325]
    DIRECTION INPUT ;
    USE SIGNAL ;
    PORT
      LAYER M4 ;
        RECT  75.408 57.552 75.6 57.576 ;
    END
  END i[325]
  PIN i[326]
    DIRECTION INPUT ;
    USE SIGNAL ;
    PORT
      LAYER M4 ;
        RECT  75.408 57.744 75.6 57.768 ;
    END
  END i[326]
  PIN i[327]
    DIRECTION INPUT ;
    USE SIGNAL ;
    PORT
      LAYER M4 ;
        RECT  75.408 57.888 75.6 57.912 ;
    END
  END i[327]
  PIN i[328]
    DIRECTION INPUT ;
    USE SIGNAL ;
    PORT
      LAYER M4 ;
        RECT  75.408 58.08 75.6 58.104 ;
    END
  END i[328]
  PIN i[329]
    DIRECTION INPUT ;
    USE SIGNAL ;
    PORT
      LAYER M4 ;
        RECT  75.408 58.224 75.6 58.248 ;
    END
  END i[329]
  PIN i[32]
    DIRECTION INPUT ;
    USE SIGNAL ;
    PORT
      LAYER M4 ;
        RECT  75.408 9.648 75.6 9.672 ;
    END
  END i[32]
  PIN i[330]
    DIRECTION INPUT ;
    USE SIGNAL ;
    PORT
      LAYER M4 ;
        RECT  75.408 58.416 75.6 58.44 ;
    END
  END i[330]
  PIN i[331]
    DIRECTION INPUT ;
    USE SIGNAL ;
    PORT
      LAYER M4 ;
        RECT  75.408 58.56 75.6 58.584 ;
    END
  END i[331]
  PIN i[332]
    DIRECTION INPUT ;
    USE SIGNAL ;
    PORT
      LAYER M4 ;
        RECT  75.408 58.704 75.6 58.728 ;
    END
  END i[332]
  PIN i[333]
    DIRECTION INPUT ;
    USE SIGNAL ;
    PORT
      LAYER M4 ;
        RECT  75.408 58.896 75.6 58.92 ;
    END
  END i[333]
  PIN i[334]
    DIRECTION INPUT ;
    USE SIGNAL ;
    PORT
      LAYER M4 ;
        RECT  75.408 59.04 75.6 59.064 ;
    END
  END i[334]
  PIN i[335]
    DIRECTION INPUT ;
    USE SIGNAL ;
    PORT
      LAYER M4 ;
        RECT  75.408 59.232 75.6 59.256 ;
    END
  END i[335]
  PIN i[336]
    DIRECTION INPUT ;
    USE SIGNAL ;
    PORT
      LAYER M4 ;
        RECT  75.408 59.376 75.6 59.4 ;
    END
  END i[336]
  PIN i[337]
    DIRECTION INPUT ;
    USE SIGNAL ;
    PORT
      LAYER M4 ;
        RECT  75.408 59.52 75.6 59.544 ;
    END
  END i[337]
  PIN i[338]
    DIRECTION INPUT ;
    USE SIGNAL ;
    PORT
      LAYER M4 ;
        RECT  75.408 59.712 75.6 59.736 ;
    END
  END i[338]
  PIN i[339]
    DIRECTION INPUT ;
    USE SIGNAL ;
    PORT
      LAYER M4 ;
        RECT  75.408 59.856 75.6 59.88 ;
    END
  END i[339]
  PIN i[33]
    DIRECTION INPUT ;
    USE SIGNAL ;
    PORT
      LAYER M4 ;
        RECT  75.408 9.792 75.6 9.816 ;
    END
  END i[33]
  PIN i[340]
    DIRECTION INPUT ;
    USE SIGNAL ;
    PORT
      LAYER M4 ;
        RECT  75.408 60.048 75.6 60.072 ;
    END
  END i[340]
  PIN i[341]
    DIRECTION INPUT ;
    USE SIGNAL ;
    PORT
      LAYER M4 ;
        RECT  75.408 60.192 75.6 60.216 ;
    END
  END i[341]
  PIN i[342]
    DIRECTION INPUT ;
    USE SIGNAL ;
    PORT
      LAYER M4 ;
        RECT  75.408 60.336 75.6 60.36 ;
    END
  END i[342]
  PIN i[343]
    DIRECTION INPUT ;
    USE SIGNAL ;
    PORT
      LAYER M4 ;
        RECT  75.408 60.528 75.6 60.552 ;
    END
  END i[343]
  PIN i[344]
    DIRECTION INPUT ;
    USE SIGNAL ;
    PORT
      LAYER M4 ;
        RECT  75.408 60.672 75.6 60.696 ;
    END
  END i[344]
  PIN i[345]
    DIRECTION INPUT ;
    USE SIGNAL ;
    PORT
      LAYER M4 ;
        RECT  75.408 60.864 75.6 60.888 ;
    END
  END i[345]
  PIN i[346]
    DIRECTION INPUT ;
    USE SIGNAL ;
    PORT
      LAYER M4 ;
        RECT  75.408 61.008 75.6 61.032 ;
    END
  END i[346]
  PIN i[347]
    DIRECTION INPUT ;
    USE SIGNAL ;
    PORT
      LAYER M4 ;
        RECT  75.408 61.152 75.6 61.176 ;
    END
  END i[347]
  PIN i[348]
    DIRECTION INPUT ;
    USE SIGNAL ;
    PORT
      LAYER M4 ;
        RECT  75.408 61.344 75.6 61.368 ;
    END
  END i[348]
  PIN i[349]
    DIRECTION INPUT ;
    USE SIGNAL ;
    PORT
      LAYER M4 ;
        RECT  75.408 61.488 75.6 61.512 ;
    END
  END i[349]
  PIN i[34]
    DIRECTION INPUT ;
    USE SIGNAL ;
    PORT
      LAYER M4 ;
        RECT  75.408 9.984 75.6 10.008 ;
    END
  END i[34]
  PIN i[350]
    DIRECTION INPUT ;
    USE SIGNAL ;
    PORT
      LAYER M4 ;
        RECT  75.408 61.68 75.6 61.704 ;
    END
  END i[350]
  PIN i[351]
    DIRECTION INPUT ;
    USE SIGNAL ;
    PORT
      LAYER M4 ;
        RECT  75.408 61.824 75.6 61.848 ;
    END
  END i[351]
  PIN i[352]
    DIRECTION INPUT ;
    USE SIGNAL ;
    PORT
      LAYER M4 ;
        RECT  75.408 61.968 75.6 61.992 ;
    END
  END i[352]
  PIN i[353]
    DIRECTION INPUT ;
    USE SIGNAL ;
    PORT
      LAYER M4 ;
        RECT  75.408 62.16 75.6 62.184 ;
    END
  END i[353]
  PIN i[354]
    DIRECTION INPUT ;
    USE SIGNAL ;
    PORT
      LAYER M4 ;
        RECT  75.408 62.304 75.6 62.328 ;
    END
  END i[354]
  PIN i[355]
    DIRECTION INPUT ;
    USE SIGNAL ;
    PORT
      LAYER M4 ;
        RECT  75.408 62.496 75.6 62.52 ;
    END
  END i[355]
  PIN i[356]
    DIRECTION INPUT ;
    USE SIGNAL ;
    PORT
      LAYER M4 ;
        RECT  75.408 62.64 75.6 62.664 ;
    END
  END i[356]
  PIN i[357]
    DIRECTION INPUT ;
    USE SIGNAL ;
    PORT
      LAYER M4 ;
        RECT  75.408 62.832 75.6 62.856 ;
    END
  END i[357]
  PIN i[358]
    DIRECTION INPUT ;
    USE SIGNAL ;
    PORT
      LAYER M4 ;
        RECT  75.408 62.976 75.6 63 ;
    END
  END i[358]
  PIN i[359]
    DIRECTION INPUT ;
    USE SIGNAL ;
    PORT
      LAYER M4 ;
        RECT  75.408 63.12 75.6 63.144 ;
    END
  END i[359]
  PIN i[35]
    DIRECTION INPUT ;
    USE SIGNAL ;
    PORT
      LAYER M4 ;
        RECT  75.408 10.128 75.6 10.152 ;
    END
  END i[35]
  PIN i[360]
    DIRECTION INPUT ;
    USE SIGNAL ;
    PORT
      LAYER M4 ;
        RECT  75.408 63.312 75.6 63.336 ;
    END
  END i[360]
  PIN i[361]
    DIRECTION INPUT ;
    USE SIGNAL ;
    PORT
      LAYER M4 ;
        RECT  75.408 63.456 75.6 63.48 ;
    END
  END i[361]
  PIN i[362]
    DIRECTION INPUT ;
    USE SIGNAL ;
    PORT
      LAYER M4 ;
        RECT  75.408 63.648 75.6 63.672 ;
    END
  END i[362]
  PIN i[363]
    DIRECTION INPUT ;
    USE SIGNAL ;
    PORT
      LAYER M4 ;
        RECT  75.408 63.792 75.6 63.816 ;
    END
  END i[363]
  PIN i[364]
    DIRECTION INPUT ;
    USE SIGNAL ;
    PORT
      LAYER M4 ;
        RECT  75.408 63.936 75.6 63.96 ;
    END
  END i[364]
  PIN i[365]
    DIRECTION INPUT ;
    USE SIGNAL ;
    PORT
      LAYER M4 ;
        RECT  75.408 64.128 75.6 64.152 ;
    END
  END i[365]
  PIN i[366]
    DIRECTION INPUT ;
    USE SIGNAL ;
    PORT
      LAYER M4 ;
        RECT  75.408 64.272 75.6 64.296 ;
    END
  END i[366]
  PIN i[367]
    DIRECTION INPUT ;
    USE SIGNAL ;
    PORT
      LAYER M4 ;
        RECT  75.408 64.464 75.6 64.488 ;
    END
  END i[367]
  PIN i[368]
    DIRECTION INPUT ;
    USE SIGNAL ;
    PORT
      LAYER M4 ;
        RECT  75.408 64.608 75.6 64.632 ;
    END
  END i[368]
  PIN i[369]
    DIRECTION INPUT ;
    USE SIGNAL ;
    PORT
      LAYER M4 ;
        RECT  75.408 64.752 75.6 64.776 ;
    END
  END i[369]
  PIN i[36]
    DIRECTION INPUT ;
    USE SIGNAL ;
    PORT
      LAYER M4 ;
        RECT  75.408 10.32 75.6 10.344 ;
    END
  END i[36]
  PIN i[370]
    DIRECTION INPUT ;
    USE SIGNAL ;
    PORT
      LAYER M4 ;
        RECT  75.408 64.944 75.6 64.968 ;
    END
  END i[370]
  PIN i[371]
    DIRECTION INPUT ;
    USE SIGNAL ;
    PORT
      LAYER M4 ;
        RECT  75.408 65.088 75.6 65.112 ;
    END
  END i[371]
  PIN i[372]
    DIRECTION INPUT ;
    USE SIGNAL ;
    PORT
      LAYER M4 ;
        RECT  75.408 65.28 75.6 65.304 ;
    END
  END i[372]
  PIN i[373]
    DIRECTION INPUT ;
    USE SIGNAL ;
    PORT
      LAYER M4 ;
        RECT  75.408 65.424 75.6 65.448 ;
    END
  END i[373]
  PIN i[374]
    DIRECTION INPUT ;
    USE SIGNAL ;
    PORT
      LAYER M4 ;
        RECT  75.408 65.568 75.6 65.592 ;
    END
  END i[374]
  PIN i[375]
    DIRECTION INPUT ;
    USE SIGNAL ;
    PORT
      LAYER M4 ;
        RECT  75.408 65.76 75.6 65.784 ;
    END
  END i[375]
  PIN i[376]
    DIRECTION INPUT ;
    USE SIGNAL ;
    PORT
      LAYER M4 ;
        RECT  75.408 65.904 75.6 65.928 ;
    END
  END i[376]
  PIN i[377]
    DIRECTION INPUT ;
    USE SIGNAL ;
    PORT
      LAYER M4 ;
        RECT  75.408 66.096 75.6 66.12 ;
    END
  END i[377]
  PIN i[378]
    DIRECTION INPUT ;
    USE SIGNAL ;
    PORT
      LAYER M4 ;
        RECT  75.408 66.24 75.6 66.264 ;
    END
  END i[378]
  PIN i[379]
    DIRECTION INPUT ;
    USE SIGNAL ;
    PORT
      LAYER M4 ;
        RECT  75.408 66.384 75.6 66.408 ;
    END
  END i[379]
  PIN i[37]
    DIRECTION INPUT ;
    USE SIGNAL ;
    PORT
      LAYER M4 ;
        RECT  75.408 10.464 75.6 10.488 ;
    END
  END i[37]
  PIN i[380]
    DIRECTION INPUT ;
    USE SIGNAL ;
    PORT
      LAYER M4 ;
        RECT  75.408 66.576 75.6 66.6 ;
    END
  END i[380]
  PIN i[381]
    DIRECTION INPUT ;
    USE SIGNAL ;
    PORT
      LAYER M4 ;
        RECT  75.408 66.72 75.6 66.744 ;
    END
  END i[381]
  PIN i[382]
    DIRECTION INPUT ;
    USE SIGNAL ;
    PORT
      LAYER M4 ;
        RECT  75.408 66.912 75.6 66.936 ;
    END
  END i[382]
  PIN i[383]
    DIRECTION INPUT ;
    USE SIGNAL ;
    PORT
      LAYER M4 ;
        RECT  75.408 67.056 75.6 67.08 ;
    END
  END i[383]
  PIN i[384]
    DIRECTION INPUT ;
    USE SIGNAL ;
    PORT
      LAYER M4 ;
        RECT  75.408 67.248 75.6 67.272 ;
    END
  END i[384]
  PIN i[385]
    DIRECTION INPUT ;
    USE SIGNAL ;
    PORT
      LAYER M4 ;
        RECT  75.408 67.392 75.6 67.416 ;
    END
  END i[385]
  PIN i[386]
    DIRECTION INPUT ;
    USE SIGNAL ;
    PORT
      LAYER M4 ;
        RECT  75.408 67.536 75.6 67.56 ;
    END
  END i[386]
  PIN i[387]
    DIRECTION INPUT ;
    USE SIGNAL ;
    PORT
      LAYER M4 ;
        RECT  75.408 67.728 75.6 67.752 ;
    END
  END i[387]
  PIN i[388]
    DIRECTION INPUT ;
    USE SIGNAL ;
    PORT
      LAYER M4 ;
        RECT  75.408 67.872 75.6 67.896 ;
    END
  END i[388]
  PIN i[389]
    DIRECTION INPUT ;
    USE SIGNAL ;
    PORT
      LAYER M4 ;
        RECT  75.408 68.064 75.6 68.088 ;
    END
  END i[389]
  PIN i[38]
    DIRECTION INPUT ;
    USE SIGNAL ;
    PORT
      LAYER M4 ;
        RECT  75.408 10.608 75.6 10.632 ;
    END
  END i[38]
  PIN i[390]
    DIRECTION INPUT ;
    USE SIGNAL ;
    PORT
      LAYER M4 ;
        RECT  75.408 68.208 75.6 68.232 ;
    END
  END i[390]
  PIN i[391]
    DIRECTION INPUT ;
    USE SIGNAL ;
    PORT
      LAYER M4 ;
        RECT  75.408 68.352 75.6 68.376 ;
    END
  END i[391]
  PIN i[392]
    DIRECTION INPUT ;
    USE SIGNAL ;
    PORT
      LAYER M4 ;
        RECT  75.408 68.544 75.6 68.568 ;
    END
  END i[392]
  PIN i[393]
    DIRECTION INPUT ;
    USE SIGNAL ;
    PORT
      LAYER M4 ;
        RECT  75.408 68.688 75.6 68.712 ;
    END
  END i[393]
  PIN i[394]
    DIRECTION INPUT ;
    USE SIGNAL ;
    PORT
      LAYER M4 ;
        RECT  75.408 68.88 75.6 68.904 ;
    END
  END i[394]
  PIN i[395]
    DIRECTION INPUT ;
    USE SIGNAL ;
    PORT
      LAYER M4 ;
        RECT  75.408 69.024 75.6 69.048 ;
    END
  END i[395]
  PIN i[396]
    DIRECTION INPUT ;
    USE SIGNAL ;
    PORT
      LAYER M4 ;
        RECT  75.408 69.168 75.6 69.192 ;
    END
  END i[396]
  PIN i[397]
    DIRECTION INPUT ;
    USE SIGNAL ;
    PORT
      LAYER M4 ;
        RECT  75.408 69.36 75.6 69.384 ;
    END
  END i[397]
  PIN i[398]
    DIRECTION INPUT ;
    USE SIGNAL ;
    PORT
      LAYER M4 ;
        RECT  75.408 69.504 75.6 69.528 ;
    END
  END i[398]
  PIN i[399]
    DIRECTION INPUT ;
    USE SIGNAL ;
    PORT
      LAYER M4 ;
        RECT  75.408 69.696 75.6 69.72 ;
    END
  END i[399]
  PIN i[39]
    DIRECTION INPUT ;
    USE SIGNAL ;
    PORT
      LAYER M4 ;
        RECT  75.408 10.8 75.6 10.824 ;
    END
  END i[39]
  PIN i[3]
    DIRECTION INPUT ;
    USE SIGNAL ;
    PORT
      LAYER M4 ;
        RECT  75.408 4.896 75.6 4.92 ;
    END
  END i[3]
  PIN i[400]
    DIRECTION INPUT ;
    USE SIGNAL ;
    PORT
      LAYER M4 ;
        RECT  75.408 69.84 75.6 69.864 ;
    END
  END i[400]
  PIN i[401]
    DIRECTION INPUT ;
    USE SIGNAL ;
    PORT
      LAYER M4 ;
        RECT  75.408 69.984 75.6 70.008 ;
    END
  END i[401]
  PIN i[402]
    DIRECTION INPUT ;
    USE SIGNAL ;
    PORT
      LAYER M4 ;
        RECT  75.408 70.176 75.6 70.2 ;
    END
  END i[402]
  PIN i[403]
    DIRECTION INPUT ;
    USE SIGNAL ;
    PORT
      LAYER M4 ;
        RECT  75.408 70.32 75.6 70.344 ;
    END
  END i[403]
  PIN i[404]
    DIRECTION INPUT ;
    USE SIGNAL ;
    PORT
      LAYER M4 ;
        RECT  75.408 70.512 75.6 70.536 ;
    END
  END i[404]
  PIN i[405]
    DIRECTION INPUT ;
    USE SIGNAL ;
    PORT
      LAYER M4 ;
        RECT  75.408 70.656 75.6 70.68 ;
    END
  END i[405]
  PIN i[406]
    DIRECTION INPUT ;
    USE SIGNAL ;
    PORT
      LAYER M4 ;
        RECT  75.408 70.848 75.6 70.872 ;
    END
  END i[406]
  PIN i[407]
    DIRECTION INPUT ;
    USE SIGNAL ;
    PORT
      LAYER M4 ;
        RECT  75.408 70.992 75.6 71.016 ;
    END
  END i[407]
  PIN i[408]
    DIRECTION INPUT ;
    USE SIGNAL ;
    PORT
      LAYER M4 ;
        RECT  75.408 71.136 75.6 71.16 ;
    END
  END i[408]
  PIN i[409]
    DIRECTION INPUT ;
    USE SIGNAL ;
    PORT
      LAYER M4 ;
        RECT  75.408 71.328 75.6 71.352 ;
    END
  END i[409]
  PIN i[40]
    DIRECTION INPUT ;
    USE SIGNAL ;
    PORT
      LAYER M4 ;
        RECT  75.408 10.944 75.6 10.968 ;
    END
  END i[40]
  PIN i[410]
    DIRECTION INPUT ;
    USE SIGNAL ;
    PORT
      LAYER M4 ;
        RECT  75.408 71.472 75.6 71.496 ;
    END
  END i[410]
  PIN i[411]
    DIRECTION INPUT ;
    USE SIGNAL ;
    PORT
      LAYER M4 ;
        RECT  75.408 71.664 75.6 71.688 ;
    END
  END i[411]
  PIN i[412]
    DIRECTION INPUT ;
    USE SIGNAL ;
    PORT
      LAYER M4 ;
        RECT  75.408 71.808 75.6 71.832 ;
    END
  END i[412]
  PIN i[413]
    DIRECTION INPUT ;
    USE SIGNAL ;
    PORT
      LAYER M4 ;
        RECT  75.408 71.952 75.6 71.976 ;
    END
  END i[413]
  PIN i[414]
    DIRECTION INPUT ;
    USE SIGNAL ;
    PORT
      LAYER M4 ;
        RECT  75.408 72.144 75.6 72.168 ;
    END
  END i[414]
  PIN i[415]
    DIRECTION INPUT ;
    USE SIGNAL ;
    PORT
      LAYER M4 ;
        RECT  75.408 72.288 75.6 72.312 ;
    END
  END i[415]
  PIN i[416]
    DIRECTION INPUT ;
    USE SIGNAL ;
    PORT
      LAYER M4 ;
        RECT  75.408 72.48 75.6 72.504 ;
    END
  END i[416]
  PIN i[417]
    DIRECTION INPUT ;
    USE SIGNAL ;
    PORT
      LAYER M4 ;
        RECT  75.408 72.624 75.6 72.648 ;
    END
  END i[417]
  PIN i[418]
    DIRECTION INPUT ;
    USE SIGNAL ;
    PORT
      LAYER M4 ;
        RECT  75.408 72.768 75.6 72.792 ;
    END
  END i[418]
  PIN i[419]
    DIRECTION INPUT ;
    USE SIGNAL ;
    PORT
      LAYER M4 ;
        RECT  75.408 72.96 75.6 72.984 ;
    END
  END i[419]
  PIN i[41]
    DIRECTION INPUT ;
    USE SIGNAL ;
    PORT
      LAYER M4 ;
        RECT  75.408 11.136 75.6 11.16 ;
    END
  END i[41]
  PIN i[420]
    DIRECTION INPUT ;
    USE SIGNAL ;
    PORT
      LAYER M4 ;
        RECT  75.408 73.104 75.6 73.128 ;
    END
  END i[420]
  PIN i[421]
    DIRECTION INPUT ;
    USE SIGNAL ;
    PORT
      LAYER M4 ;
        RECT  75.408 73.296 75.6 73.32 ;
    END
  END i[421]
  PIN i[422]
    DIRECTION INPUT ;
    USE SIGNAL ;
    PORT
      LAYER M4 ;
        RECT  75.408 73.44 75.6 73.464 ;
    END
  END i[422]
  PIN i[423]
    DIRECTION INPUT ;
    USE SIGNAL ;
    PORT
      LAYER M4 ;
        RECT  75.408 73.584 75.6 73.608 ;
    END
  END i[423]
  PIN i[424]
    DIRECTION INPUT ;
    USE SIGNAL ;
    PORT
      LAYER M4 ;
        RECT  75.408 73.776 75.6 73.8 ;
    END
  END i[424]
  PIN i[425]
    DIRECTION INPUT ;
    USE SIGNAL ;
    PORT
      LAYER M4 ;
        RECT  75.408 73.92 75.6 73.944 ;
    END
  END i[425]
  PIN i[426]
    DIRECTION INPUT ;
    USE SIGNAL ;
    PORT
      LAYER M4 ;
        RECT  75.408 74.112 75.6 74.136 ;
    END
  END i[426]
  PIN i[427]
    DIRECTION INPUT ;
    USE SIGNAL ;
    PORT
      LAYER M4 ;
        RECT  75.408 74.256 75.6 74.28 ;
    END
  END i[427]
  PIN i[428]
    DIRECTION INPUT ;
    USE SIGNAL ;
    PORT
      LAYER M4 ;
        RECT  75.408 74.4 75.6 74.424 ;
    END
  END i[428]
  PIN i[429]
    DIRECTION INPUT ;
    USE SIGNAL ;
    PORT
      LAYER M4 ;
        RECT  75.408 74.592 75.6 74.616 ;
    END
  END i[429]
  PIN i[42]
    DIRECTION INPUT ;
    USE SIGNAL ;
    PORT
      LAYER M4 ;
        RECT  75.408 11.28 75.6 11.304 ;
    END
  END i[42]
  PIN i[430]
    DIRECTION INPUT ;
    USE SIGNAL ;
    PORT
      LAYER M4 ;
        RECT  75.408 74.736 75.6 74.76 ;
    END
  END i[430]
  PIN i[431]
    DIRECTION INPUT ;
    USE SIGNAL ;
    PORT
      LAYER M4 ;
        RECT  75.408 74.928 75.6 74.952 ;
    END
  END i[431]
  PIN i[432]
    DIRECTION INPUT ;
    USE SIGNAL ;
    PORT
      LAYER M4 ;
        RECT  75.408 75.072 75.6 75.096 ;
    END
  END i[432]
  PIN i[433]
    DIRECTION INPUT ;
    USE SIGNAL ;
    PORT
      LAYER M4 ;
        RECT  75.408 75.264 75.6 75.288 ;
    END
  END i[433]
  PIN i[434]
    DIRECTION INPUT ;
    USE SIGNAL ;
    PORT
      LAYER M4 ;
        RECT  75.408 75.408 75.6 75.432 ;
    END
  END i[434]
  PIN i[435]
    DIRECTION INPUT ;
    USE SIGNAL ;
    PORT
      LAYER M4 ;
        RECT  75.408 75.552 75.6 75.576 ;
    END
  END i[435]
  PIN i[436]
    DIRECTION INPUT ;
    USE SIGNAL ;
    PORT
      LAYER M4 ;
        RECT  75.408 75.744 75.6 75.768 ;
    END
  END i[436]
  PIN i[437]
    DIRECTION INPUT ;
    USE SIGNAL ;
    PORT
      LAYER M4 ;
        RECT  75.408 75.888 75.6 75.912 ;
    END
  END i[437]
  PIN i[438]
    DIRECTION INPUT ;
    USE SIGNAL ;
    PORT
      LAYER M4 ;
        RECT  75.408 76.08 75.6 76.104 ;
    END
  END i[438]
  PIN i[439]
    DIRECTION INPUT ;
    USE SIGNAL ;
    PORT
      LAYER M4 ;
        RECT  75.408 76.224 75.6 76.248 ;
    END
  END i[439]
  PIN i[43]
    DIRECTION INPUT ;
    USE SIGNAL ;
    PORT
      LAYER M4 ;
        RECT  75.408 11.424 75.6 11.448 ;
    END
  END i[43]
  PIN i[440]
    DIRECTION INPUT ;
    USE SIGNAL ;
    PORT
      LAYER M4 ;
        RECT  75.408 76.368 75.6 76.392 ;
    END
  END i[440]
  PIN i[441]
    DIRECTION INPUT ;
    USE SIGNAL ;
    PORT
      LAYER M4 ;
        RECT  75.408 76.56 75.6 76.584 ;
    END
  END i[441]
  PIN i[442]
    DIRECTION INPUT ;
    USE SIGNAL ;
    PORT
      LAYER M4 ;
        RECT  75.408 76.704 75.6 76.728 ;
    END
  END i[442]
  PIN i[443]
    DIRECTION INPUT ;
    USE SIGNAL ;
    PORT
      LAYER M4 ;
        RECT  75.408 76.896 75.6 76.92 ;
    END
  END i[443]
  PIN i[444]
    DIRECTION INPUT ;
    USE SIGNAL ;
    PORT
      LAYER M4 ;
        RECT  75.408 77.04 75.6 77.064 ;
    END
  END i[444]
  PIN i[445]
    DIRECTION INPUT ;
    USE SIGNAL ;
    PORT
      LAYER M4 ;
        RECT  75.408 77.184 75.6 77.208 ;
    END
  END i[445]
  PIN i[446]
    DIRECTION INPUT ;
    USE SIGNAL ;
    PORT
      LAYER M4 ;
        RECT  75.408 77.376 75.6 77.4 ;
    END
  END i[446]
  PIN i[447]
    DIRECTION INPUT ;
    USE SIGNAL ;
    PORT
      LAYER M4 ;
        RECT  75.408 77.52 75.6 77.544 ;
    END
  END i[447]
  PIN i[448]
    DIRECTION INPUT ;
    USE SIGNAL ;
    PORT
      LAYER M4 ;
        RECT  75.408 77.712 75.6 77.736 ;
    END
  END i[448]
  PIN i[449]
    DIRECTION INPUT ;
    USE SIGNAL ;
    PORT
      LAYER M4 ;
        RECT  75.408 77.856 75.6 77.88 ;
    END
  END i[449]
  PIN i[44]
    DIRECTION INPUT ;
    USE SIGNAL ;
    PORT
      LAYER M4 ;
        RECT  75.408 11.616 75.6 11.64 ;
    END
  END i[44]
  PIN i[450]
    DIRECTION INPUT ;
    USE SIGNAL ;
    PORT
      LAYER M4 ;
        RECT  75.408 78 75.6 78.024 ;
    END
  END i[450]
  PIN i[451]
    DIRECTION INPUT ;
    USE SIGNAL ;
    PORT
      LAYER M4 ;
        RECT  75.408 78.192 75.6 78.216 ;
    END
  END i[451]
  PIN i[452]
    DIRECTION INPUT ;
    USE SIGNAL ;
    PORT
      LAYER M4 ;
        RECT  75.408 78.336 75.6 78.36 ;
    END
  END i[452]
  PIN i[453]
    DIRECTION INPUT ;
    USE SIGNAL ;
    PORT
      LAYER M4 ;
        RECT  75.408 78.528 75.6 78.552 ;
    END
  END i[453]
  PIN i[454]
    DIRECTION INPUT ;
    USE SIGNAL ;
    PORT
      LAYER M4 ;
        RECT  75.408 78.672 75.6 78.696 ;
    END
  END i[454]
  PIN i[455]
    DIRECTION INPUT ;
    USE SIGNAL ;
    PORT
      LAYER M4 ;
        RECT  75.408 78.816 75.6 78.84 ;
    END
  END i[455]
  PIN i[456]
    DIRECTION INPUT ;
    USE SIGNAL ;
    PORT
      LAYER M4 ;
        RECT  75.408 79.008 75.6 79.032 ;
    END
  END i[456]
  PIN i[457]
    DIRECTION INPUT ;
    USE SIGNAL ;
    PORT
      LAYER M4 ;
        RECT  75.408 79.152 75.6 79.176 ;
    END
  END i[457]
  PIN i[458]
    DIRECTION INPUT ;
    USE SIGNAL ;
    PORT
      LAYER M4 ;
        RECT  75.408 79.344 75.6 79.368 ;
    END
  END i[458]
  PIN i[459]
    DIRECTION INPUT ;
    USE SIGNAL ;
    PORT
      LAYER M4 ;
        RECT  75.408 79.488 75.6 79.512 ;
    END
  END i[459]
  PIN i[45]
    DIRECTION INPUT ;
    USE SIGNAL ;
    PORT
      LAYER M4 ;
        RECT  75.408 11.76 75.6 11.784 ;
    END
  END i[45]
  PIN i[460]
    DIRECTION INPUT ;
    USE SIGNAL ;
    PORT
      LAYER M4 ;
        RECT  75.408 79.68 75.6 79.704 ;
    END
  END i[460]
  PIN i[461]
    DIRECTION INPUT ;
    USE SIGNAL ;
    PORT
      LAYER M4 ;
        RECT  75.408 79.824 75.6 79.848 ;
    END
  END i[461]
  PIN i[462]
    DIRECTION INPUT ;
    USE SIGNAL ;
    PORT
      LAYER M4 ;
        RECT  75.408 79.968 75.6 79.992 ;
    END
  END i[462]
  PIN i[463]
    DIRECTION INPUT ;
    USE SIGNAL ;
    PORT
      LAYER M4 ;
        RECT  75.408 80.16 75.6 80.184 ;
    END
  END i[463]
  PIN i[464]
    DIRECTION INPUT ;
    USE SIGNAL ;
    PORT
      LAYER M4 ;
        RECT  75.408 80.304 75.6 80.328 ;
    END
  END i[464]
  PIN i[465]
    DIRECTION INPUT ;
    USE SIGNAL ;
    PORT
      LAYER M4 ;
        RECT  75.408 80.496 75.6 80.52 ;
    END
  END i[465]
  PIN i[466]
    DIRECTION INPUT ;
    USE SIGNAL ;
    PORT
      LAYER M4 ;
        RECT  75.408 80.64 75.6 80.664 ;
    END
  END i[466]
  PIN i[467]
    DIRECTION INPUT ;
    USE SIGNAL ;
    PORT
      LAYER M4 ;
        RECT  75.408 80.784 75.6 80.808 ;
    END
  END i[467]
  PIN i[468]
    DIRECTION INPUT ;
    USE SIGNAL ;
    PORT
      LAYER M4 ;
        RECT  75.408 80.976 75.6 81 ;
    END
  END i[468]
  PIN i[469]
    DIRECTION INPUT ;
    USE SIGNAL ;
    PORT
      LAYER M4 ;
        RECT  75.408 81.12 75.6 81.144 ;
    END
  END i[469]
  PIN i[46]
    DIRECTION INPUT ;
    USE SIGNAL ;
    PORT
      LAYER M4 ;
        RECT  75.408 11.952 75.6 11.976 ;
    END
  END i[46]
  PIN i[470]
    DIRECTION INPUT ;
    USE SIGNAL ;
    PORT
      LAYER M4 ;
        RECT  75.408 81.312 75.6 81.336 ;
    END
  END i[470]
  PIN i[471]
    DIRECTION INPUT ;
    USE SIGNAL ;
    PORT
      LAYER M4 ;
        RECT  75.408 81.456 75.6 81.48 ;
    END
  END i[471]
  PIN i[472]
    DIRECTION INPUT ;
    USE SIGNAL ;
    PORT
      LAYER M4 ;
        RECT  75.408 81.6 75.6 81.624 ;
    END
  END i[472]
  PIN i[473]
    DIRECTION INPUT ;
    USE SIGNAL ;
    PORT
      LAYER M4 ;
        RECT  75.408 81.792 75.6 81.816 ;
    END
  END i[473]
  PIN i[474]
    DIRECTION INPUT ;
    USE SIGNAL ;
    PORT
      LAYER M4 ;
        RECT  75.408 81.936 75.6 81.96 ;
    END
  END i[474]
  PIN i[475]
    DIRECTION INPUT ;
    USE SIGNAL ;
    PORT
      LAYER M4 ;
        RECT  75.408 82.128 75.6 82.152 ;
    END
  END i[475]
  PIN i[476]
    DIRECTION INPUT ;
    USE SIGNAL ;
    PORT
      LAYER M4 ;
        RECT  75.408 82.272 75.6 82.296 ;
    END
  END i[476]
  PIN i[477]
    DIRECTION INPUT ;
    USE SIGNAL ;
    PORT
      LAYER M4 ;
        RECT  75.408 82.416 75.6 82.44 ;
    END
  END i[477]
  PIN i[478]
    DIRECTION INPUT ;
    USE SIGNAL ;
    PORT
      LAYER M4 ;
        RECT  75.408 82.608 75.6 82.632 ;
    END
  END i[478]
  PIN i[479]
    DIRECTION INPUT ;
    USE SIGNAL ;
    PORT
      LAYER M4 ;
        RECT  75.408 82.752 75.6 82.776 ;
    END
  END i[479]
  PIN i[47]
    DIRECTION INPUT ;
    USE SIGNAL ;
    PORT
      LAYER M4 ;
        RECT  75.408 12.096 75.6 12.12 ;
    END
  END i[47]
  PIN i[480]
    DIRECTION INPUT ;
    USE SIGNAL ;
    PORT
      LAYER M4 ;
        RECT  75.408 82.944 75.6 82.968 ;
    END
  END i[480]
  PIN i[481]
    DIRECTION INPUT ;
    USE SIGNAL ;
    PORT
      LAYER M4 ;
        RECT  75.408 83.088 75.6 83.112 ;
    END
  END i[481]
  PIN i[482]
    DIRECTION INPUT ;
    USE SIGNAL ;
    PORT
      LAYER M4 ;
        RECT  75.408 83.232 75.6 83.256 ;
    END
  END i[482]
  PIN i[483]
    DIRECTION INPUT ;
    USE SIGNAL ;
    PORT
      LAYER M4 ;
        RECT  75.408 83.424 75.6 83.448 ;
    END
  END i[483]
  PIN i[484]
    DIRECTION INPUT ;
    USE SIGNAL ;
    PORT
      LAYER M4 ;
        RECT  75.408 83.568 75.6 83.592 ;
    END
  END i[484]
  PIN i[485]
    DIRECTION INPUT ;
    USE SIGNAL ;
    PORT
      LAYER M4 ;
        RECT  75.408 83.76 75.6 83.784 ;
    END
  END i[485]
  PIN i[486]
    DIRECTION INPUT ;
    USE SIGNAL ;
    PORT
      LAYER M4 ;
        RECT  75.408 83.904 75.6 83.928 ;
    END
  END i[486]
  PIN i[487]
    DIRECTION INPUT ;
    USE SIGNAL ;
    PORT
      LAYER M4 ;
        RECT  75.408 84.096 75.6 84.12 ;
    END
  END i[487]
  PIN i[488]
    DIRECTION INPUT ;
    USE SIGNAL ;
    PORT
      LAYER M4 ;
        RECT  75.408 84.24 75.6 84.264 ;
    END
  END i[488]
  PIN i[489]
    DIRECTION INPUT ;
    USE SIGNAL ;
    PORT
      LAYER M4 ;
        RECT  75.408 84.384 75.6 84.408 ;
    END
  END i[489]
  PIN i[48]
    DIRECTION INPUT ;
    USE SIGNAL ;
    PORT
      LAYER M4 ;
        RECT  75.408 12.288 75.6 12.312 ;
    END
  END i[48]
  PIN i[490]
    DIRECTION INPUT ;
    USE SIGNAL ;
    PORT
      LAYER M4 ;
        RECT  75.408 84.576 75.6 84.6 ;
    END
  END i[490]
  PIN i[491]
    DIRECTION INPUT ;
    USE SIGNAL ;
    PORT
      LAYER M4 ;
        RECT  75.408 84.72 75.6 84.744 ;
    END
  END i[491]
  PIN i[492]
    DIRECTION INPUT ;
    USE SIGNAL ;
    PORT
      LAYER M4 ;
        RECT  75.408 84.912 75.6 84.936 ;
    END
  END i[492]
  PIN i[493]
    DIRECTION INPUT ;
    USE SIGNAL ;
    PORT
      LAYER M4 ;
        RECT  75.408 85.056 75.6 85.08 ;
    END
  END i[493]
  PIN i[494]
    DIRECTION INPUT ;
    USE SIGNAL ;
    PORT
      LAYER M4 ;
        RECT  75.408 85.2 75.6 85.224 ;
    END
  END i[494]
  PIN i[495]
    DIRECTION INPUT ;
    USE SIGNAL ;
    PORT
      LAYER M4 ;
        RECT  75.408 85.392 75.6 85.416 ;
    END
  END i[495]
  PIN i[496]
    DIRECTION INPUT ;
    USE SIGNAL ;
    PORT
      LAYER M4 ;
        RECT  75.408 85.536 75.6 85.56 ;
    END
  END i[496]
  PIN i[497]
    DIRECTION INPUT ;
    USE SIGNAL ;
    PORT
      LAYER M4 ;
        RECT  75.408 85.728 75.6 85.752 ;
    END
  END i[497]
  PIN i[498]
    DIRECTION INPUT ;
    USE SIGNAL ;
    PORT
      LAYER M4 ;
        RECT  75.408 85.872 75.6 85.896 ;
    END
  END i[498]
  PIN i[499]
    DIRECTION INPUT ;
    USE SIGNAL ;
    PORT
      LAYER M4 ;
        RECT  75.408 86.016 75.6 86.04 ;
    END
  END i[499]
  PIN i[49]
    DIRECTION INPUT ;
    USE SIGNAL ;
    PORT
      LAYER M4 ;
        RECT  75.408 12.432 75.6 12.456 ;
    END
  END i[49]
  PIN i[4]
    DIRECTION INPUT ;
    USE SIGNAL ;
    PORT
      LAYER M4 ;
        RECT  75.408 5.088 75.6 5.112 ;
    END
  END i[4]
  PIN i[500]
    DIRECTION INPUT ;
    USE SIGNAL ;
    PORT
      LAYER M4 ;
        RECT  75.408 86.208 75.6 86.232 ;
    END
  END i[500]
  PIN i[501]
    DIRECTION INPUT ;
    USE SIGNAL ;
    PORT
      LAYER M4 ;
        RECT  75.408 86.352 75.6 86.376 ;
    END
  END i[501]
  PIN i[502]
    DIRECTION INPUT ;
    USE SIGNAL ;
    PORT
      LAYER M4 ;
        RECT  75.408 86.544 75.6 86.568 ;
    END
  END i[502]
  PIN i[503]
    DIRECTION INPUT ;
    USE SIGNAL ;
    PORT
      LAYER M4 ;
        RECT  75.408 86.688 75.6 86.712 ;
    END
  END i[503]
  PIN i[504]
    DIRECTION INPUT ;
    USE SIGNAL ;
    PORT
      LAYER M4 ;
        RECT  75.408 86.832 75.6 86.856 ;
    END
  END i[504]
  PIN i[505]
    DIRECTION INPUT ;
    USE SIGNAL ;
    PORT
      LAYER M4 ;
        RECT  75.408 87.024 75.6 87.048 ;
    END
  END i[505]
  PIN i[506]
    DIRECTION INPUT ;
    USE SIGNAL ;
    PORT
      LAYER M4 ;
        RECT  75.408 87.168 75.6 87.192 ;
    END
  END i[506]
  PIN i[507]
    DIRECTION INPUT ;
    USE SIGNAL ;
    PORT
      LAYER M4 ;
        RECT  75.408 87.36 75.6 87.384 ;
    END
  END i[507]
  PIN i[508]
    DIRECTION INPUT ;
    USE SIGNAL ;
    PORT
      LAYER M4 ;
        RECT  75.408 87.504 75.6 87.528 ;
    END
  END i[508]
  PIN i[509]
    DIRECTION INPUT ;
    USE SIGNAL ;
    PORT
      LAYER M4 ;
        RECT  75.408 87.696 75.6 87.72 ;
    END
  END i[509]
  PIN i[50]
    DIRECTION INPUT ;
    USE SIGNAL ;
    PORT
      LAYER M4 ;
        RECT  75.408 12.576 75.6 12.6 ;
    END
  END i[50]
  PIN i[510]
    DIRECTION INPUT ;
    USE SIGNAL ;
    PORT
      LAYER M4 ;
        RECT  75.408 87.84 75.6 87.864 ;
    END
  END i[510]
  PIN i[511]
    DIRECTION INPUT ;
    USE SIGNAL ;
    PORT
      LAYER M4 ;
        RECT  75.408 87.984 75.6 88.008 ;
    END
  END i[511]
  PIN i[512]
    DIRECTION INPUT ;
    USE SIGNAL ;
    PORT
      LAYER M4 ;
        RECT  75.408 88.176 75.6 88.2 ;
    END
  END i[512]
  PIN i[513]
    DIRECTION INPUT ;
    USE SIGNAL ;
    PORT
      LAYER M4 ;
        RECT  75.408 88.32 75.6 88.344 ;
    END
  END i[513]
  PIN i[514]
    DIRECTION INPUT ;
    USE SIGNAL ;
    PORT
      LAYER M4 ;
        RECT  75.408 88.512 75.6 88.536 ;
    END
  END i[514]
  PIN i[51]
    DIRECTION INPUT ;
    USE SIGNAL ;
    PORT
      LAYER M4 ;
        RECT  75.408 12.768 75.6 12.792 ;
    END
  END i[51]
  PIN i[52]
    DIRECTION INPUT ;
    USE SIGNAL ;
    PORT
      LAYER M4 ;
        RECT  75.408 12.912 75.6 12.936 ;
    END
  END i[52]
  PIN i[53]
    DIRECTION INPUT ;
    USE SIGNAL ;
    PORT
      LAYER M4 ;
        RECT  75.408 13.104 75.6 13.128 ;
    END
  END i[53]
  PIN i[54]
    DIRECTION INPUT ;
    USE SIGNAL ;
    PORT
      LAYER M4 ;
        RECT  75.408 13.248 75.6 13.272 ;
    END
  END i[54]
  PIN i[55]
    DIRECTION INPUT ;
    USE SIGNAL ;
    PORT
      LAYER M4 ;
        RECT  75.408 13.392 75.6 13.416 ;
    END
  END i[55]
  PIN i[56]
    DIRECTION INPUT ;
    USE SIGNAL ;
    PORT
      LAYER M4 ;
        RECT  75.408 13.584 75.6 13.608 ;
    END
  END i[56]
  PIN i[57]
    DIRECTION INPUT ;
    USE SIGNAL ;
    PORT
      LAYER M4 ;
        RECT  75.408 13.728 75.6 13.752 ;
    END
  END i[57]
  PIN i[58]
    DIRECTION INPUT ;
    USE SIGNAL ;
    PORT
      LAYER M4 ;
        RECT  75.408 13.92 75.6 13.944 ;
    END
  END i[58]
  PIN i[59]
    DIRECTION INPUT ;
    USE SIGNAL ;
    PORT
      LAYER M4 ;
        RECT  75.408 14.064 75.6 14.088 ;
    END
  END i[59]
  PIN i[5]
    DIRECTION INPUT ;
    USE SIGNAL ;
    PORT
      LAYER M4 ;
        RECT  75.408 5.232 75.6 5.256 ;
    END
  END i[5]
  PIN i[60]
    DIRECTION INPUT ;
    USE SIGNAL ;
    PORT
      LAYER M4 ;
        RECT  75.408 14.208 75.6 14.232 ;
    END
  END i[60]
  PIN i[61]
    DIRECTION INPUT ;
    USE SIGNAL ;
    PORT
      LAYER M4 ;
        RECT  75.408 14.4 75.6 14.424 ;
    END
  END i[61]
  PIN i[62]
    DIRECTION INPUT ;
    USE SIGNAL ;
    PORT
      LAYER M4 ;
        RECT  75.408 14.544 75.6 14.568 ;
    END
  END i[62]
  PIN i[63]
    DIRECTION INPUT ;
    USE SIGNAL ;
    PORT
      LAYER M4 ;
        RECT  75.408 14.736 75.6 14.76 ;
    END
  END i[63]
  PIN i[64]
    DIRECTION INPUT ;
    USE SIGNAL ;
    PORT
      LAYER M4 ;
        RECT  75.408 14.88 75.6 14.904 ;
    END
  END i[64]
  PIN i[65]
    DIRECTION INPUT ;
    USE SIGNAL ;
    PORT
      LAYER M4 ;
        RECT  75.408 15.024 75.6 15.048 ;
    END
  END i[65]
  PIN i[66]
    DIRECTION INPUT ;
    USE SIGNAL ;
    PORT
      LAYER M4 ;
        RECT  75.408 15.216 75.6 15.24 ;
    END
  END i[66]
  PIN i[67]
    DIRECTION INPUT ;
    USE SIGNAL ;
    PORT
      LAYER M4 ;
        RECT  75.408 15.36 75.6 15.384 ;
    END
  END i[67]
  PIN i[68]
    DIRECTION INPUT ;
    USE SIGNAL ;
    PORT
      LAYER M4 ;
        RECT  75.408 15.552 75.6 15.576 ;
    END
  END i[68]
  PIN i[69]
    DIRECTION INPUT ;
    USE SIGNAL ;
    PORT
      LAYER M4 ;
        RECT  75.408 15.696 75.6 15.72 ;
    END
  END i[69]
  PIN i[6]
    DIRECTION INPUT ;
    USE SIGNAL ;
    PORT
      LAYER M4 ;
        RECT  75.408 5.376 75.6 5.4 ;
    END
  END i[6]
  PIN i[70]
    DIRECTION INPUT ;
    USE SIGNAL ;
    PORT
      LAYER M4 ;
        RECT  75.408 15.84 75.6 15.864 ;
    END
  END i[70]
  PIN i[71]
    DIRECTION INPUT ;
    USE SIGNAL ;
    PORT
      LAYER M4 ;
        RECT  75.408 16.032 75.6 16.056 ;
    END
  END i[71]
  PIN i[72]
    DIRECTION INPUT ;
    USE SIGNAL ;
    PORT
      LAYER M4 ;
        RECT  75.408 16.176 75.6 16.2 ;
    END
  END i[72]
  PIN i[73]
    DIRECTION INPUT ;
    USE SIGNAL ;
    PORT
      LAYER M4 ;
        RECT  75.408 16.368 75.6 16.392 ;
    END
  END i[73]
  PIN i[74]
    DIRECTION INPUT ;
    USE SIGNAL ;
    PORT
      LAYER M4 ;
        RECT  75.408 16.512 75.6 16.536 ;
    END
  END i[74]
  PIN i[75]
    DIRECTION INPUT ;
    USE SIGNAL ;
    PORT
      LAYER M4 ;
        RECT  75.408 16.704 75.6 16.728 ;
    END
  END i[75]
  PIN i[76]
    DIRECTION INPUT ;
    USE SIGNAL ;
    PORT
      LAYER M4 ;
        RECT  75.408 16.848 75.6 16.872 ;
    END
  END i[76]
  PIN i[77]
    DIRECTION INPUT ;
    USE SIGNAL ;
    PORT
      LAYER M4 ;
        RECT  75.408 16.992 75.6 17.016 ;
    END
  END i[77]
  PIN i[78]
    DIRECTION INPUT ;
    USE SIGNAL ;
    PORT
      LAYER M4 ;
        RECT  75.408 17.184 75.6 17.208 ;
    END
  END i[78]
  PIN i[79]
    DIRECTION INPUT ;
    USE SIGNAL ;
    PORT
      LAYER M4 ;
        RECT  75.408 17.328 75.6 17.352 ;
    END
  END i[79]
  PIN i[7]
    DIRECTION INPUT ;
    USE SIGNAL ;
    PORT
      LAYER M4 ;
        RECT  75.408 5.568 75.6 5.592 ;
    END
  END i[7]
  PIN i[80]
    DIRECTION INPUT ;
    USE SIGNAL ;
    PORT
      LAYER M4 ;
        RECT  75.408 17.52 75.6 17.544 ;
    END
  END i[80]
  PIN i[81]
    DIRECTION INPUT ;
    USE SIGNAL ;
    PORT
      LAYER M4 ;
        RECT  75.408 17.664 75.6 17.688 ;
    END
  END i[81]
  PIN i[82]
    DIRECTION INPUT ;
    USE SIGNAL ;
    PORT
      LAYER M4 ;
        RECT  75.408 17.808 75.6 17.832 ;
    END
  END i[82]
  PIN i[83]
    DIRECTION INPUT ;
    USE SIGNAL ;
    PORT
      LAYER M4 ;
        RECT  75.408 18 75.6 18.024 ;
    END
  END i[83]
  PIN i[84]
    DIRECTION INPUT ;
    USE SIGNAL ;
    PORT
      LAYER M4 ;
        RECT  75.408 18.144 75.6 18.168 ;
    END
  END i[84]
  PIN i[85]
    DIRECTION INPUT ;
    USE SIGNAL ;
    PORT
      LAYER M4 ;
        RECT  75.408 18.336 75.6 18.36 ;
    END
  END i[85]
  PIN i[86]
    DIRECTION INPUT ;
    USE SIGNAL ;
    PORT
      LAYER M4 ;
        RECT  75.408 18.48 75.6 18.504 ;
    END
  END i[86]
  PIN i[87]
    DIRECTION INPUT ;
    USE SIGNAL ;
    PORT
      LAYER M4 ;
        RECT  75.408 18.624 75.6 18.648 ;
    END
  END i[87]
  PIN i[88]
    DIRECTION INPUT ;
    USE SIGNAL ;
    PORT
      LAYER M4 ;
        RECT  75.408 18.816 75.6 18.84 ;
    END
  END i[88]
  PIN i[89]
    DIRECTION INPUT ;
    USE SIGNAL ;
    PORT
      LAYER M4 ;
        RECT  75.408 18.96 75.6 18.984 ;
    END
  END i[89]
  PIN i[8]
    DIRECTION INPUT ;
    USE SIGNAL ;
    PORT
      LAYER M4 ;
        RECT  75.408 5.712 75.6 5.736 ;
    END
  END i[8]
  PIN i[90]
    DIRECTION INPUT ;
    USE SIGNAL ;
    PORT
      LAYER M4 ;
        RECT  75.408 19.152 75.6 19.176 ;
    END
  END i[90]
  PIN i[91]
    DIRECTION INPUT ;
    USE SIGNAL ;
    PORT
      LAYER M4 ;
        RECT  75.408 19.296 75.6 19.32 ;
    END
  END i[91]
  PIN i[92]
    DIRECTION INPUT ;
    USE SIGNAL ;
    PORT
      LAYER M4 ;
        RECT  75.408 19.44 75.6 19.464 ;
    END
  END i[92]
  PIN i[93]
    DIRECTION INPUT ;
    USE SIGNAL ;
    PORT
      LAYER M4 ;
        RECT  75.408 19.632 75.6 19.656 ;
    END
  END i[93]
  PIN i[94]
    DIRECTION INPUT ;
    USE SIGNAL ;
    PORT
      LAYER M4 ;
        RECT  75.408 19.776 75.6 19.8 ;
    END
  END i[94]
  PIN i[95]
    DIRECTION INPUT ;
    USE SIGNAL ;
    PORT
      LAYER M4 ;
        RECT  75.408 19.968 75.6 19.992 ;
    END
  END i[95]
  PIN i[96]
    DIRECTION INPUT ;
    USE SIGNAL ;
    PORT
      LAYER M4 ;
        RECT  75.408 20.112 75.6 20.136 ;
    END
  END i[96]
  PIN i[97]
    DIRECTION INPUT ;
    USE SIGNAL ;
    PORT
      LAYER M4 ;
        RECT  75.408 20.304 75.6 20.328 ;
    END
  END i[97]
  PIN i[98]
    DIRECTION INPUT ;
    USE SIGNAL ;
    PORT
      LAYER M4 ;
        RECT  75.408 20.448 75.6 20.472 ;
    END
  END i[98]
  PIN i[99]
    DIRECTION INPUT ;
    USE SIGNAL ;
    PORT
      LAYER M4 ;
        RECT  75.408 20.592 75.6 20.616 ;
    END
  END i[99]
  PIN i[9]
    DIRECTION INPUT ;
    USE SIGNAL ;
    PORT
      LAYER M4 ;
        RECT  75.408 5.904 75.6 5.928 ;
    END
  END i[9]
  PIN o[0]
    DIRECTION OUTPUT ;
    USE SIGNAL ;
    PORT
      LAYER M4 ;
        RECT  0 4.416 0.192 4.44 ;
    END
  END o[0]
  PIN o[100]
    DIRECTION OUTPUT ;
    USE SIGNAL ;
    PORT
      LAYER M4 ;
        RECT  0 20.784 0.192 20.808 ;
    END
  END o[100]
  PIN o[101]
    DIRECTION OUTPUT ;
    USE SIGNAL ;
    PORT
      LAYER M4 ;
        RECT  0 20.928 0.192 20.952 ;
    END
  END o[101]
  PIN o[102]
    DIRECTION OUTPUT ;
    USE SIGNAL ;
    PORT
      LAYER M4 ;
        RECT  0 21.12 0.192 21.144 ;
    END
  END o[102]
  PIN o[103]
    DIRECTION OUTPUT ;
    USE SIGNAL ;
    PORT
      LAYER M4 ;
        RECT  0 21.264 0.192 21.288 ;
    END
  END o[103]
  PIN o[104]
    DIRECTION OUTPUT ;
    USE SIGNAL ;
    PORT
      LAYER M4 ;
        RECT  0 21.408 0.192 21.432 ;
    END
  END o[104]
  PIN o[105]
    DIRECTION OUTPUT ;
    USE SIGNAL ;
    PORT
      LAYER M4 ;
        RECT  0 21.6 0.192 21.624 ;
    END
  END o[105]
  PIN o[106]
    DIRECTION OUTPUT ;
    USE SIGNAL ;
    PORT
      LAYER M4 ;
        RECT  0 21.744 0.192 21.768 ;
    END
  END o[106]
  PIN o[107]
    DIRECTION OUTPUT ;
    USE SIGNAL ;
    PORT
      LAYER M4 ;
        RECT  0 21.936 0.192 21.96 ;
    END
  END o[107]
  PIN o[108]
    DIRECTION OUTPUT ;
    USE SIGNAL ;
    PORT
      LAYER M4 ;
        RECT  0 22.08 0.192 22.104 ;
    END
  END o[108]
  PIN o[109]
    DIRECTION OUTPUT ;
    USE SIGNAL ;
    PORT
      LAYER M4 ;
        RECT  0 22.224 0.192 22.248 ;
    END
  END o[109]
  PIN o[10]
    DIRECTION OUTPUT ;
    USE SIGNAL ;
    PORT
      LAYER M4 ;
        RECT  0 6.048 0.192 6.072 ;
    END
  END o[10]
  PIN o[110]
    DIRECTION OUTPUT ;
    USE SIGNAL ;
    PORT
      LAYER M4 ;
        RECT  0 22.416 0.192 22.44 ;
    END
  END o[110]
  PIN o[111]
    DIRECTION OUTPUT ;
    USE SIGNAL ;
    PORT
      LAYER M4 ;
        RECT  0 22.56 0.192 22.584 ;
    END
  END o[111]
  PIN o[112]
    DIRECTION OUTPUT ;
    USE SIGNAL ;
    PORT
      LAYER M4 ;
        RECT  0 22.752 0.192 22.776 ;
    END
  END o[112]
  PIN o[113]
    DIRECTION OUTPUT ;
    USE SIGNAL ;
    PORT
      LAYER M4 ;
        RECT  0 22.896 0.192 22.92 ;
    END
  END o[113]
  PIN o[114]
    DIRECTION OUTPUT ;
    USE SIGNAL ;
    PORT
      LAYER M4 ;
        RECT  0 23.04 0.192 23.064 ;
    END
  END o[114]
  PIN o[115]
    DIRECTION OUTPUT ;
    USE SIGNAL ;
    PORT
      LAYER M4 ;
        RECT  0 23.232 0.192 23.256 ;
    END
  END o[115]
  PIN o[116]
    DIRECTION OUTPUT ;
    USE SIGNAL ;
    PORT
      LAYER M4 ;
        RECT  0 23.376 0.192 23.4 ;
    END
  END o[116]
  PIN o[117]
    DIRECTION OUTPUT ;
    USE SIGNAL ;
    PORT
      LAYER M4 ;
        RECT  0 23.568 0.192 23.592 ;
    END
  END o[117]
  PIN o[118]
    DIRECTION OUTPUT ;
    USE SIGNAL ;
    PORT
      LAYER M4 ;
        RECT  0 23.712 0.192 23.736 ;
    END
  END o[118]
  PIN o[119]
    DIRECTION OUTPUT ;
    USE SIGNAL ;
    PORT
      LAYER M4 ;
        RECT  0 23.856 0.192 23.88 ;
    END
  END o[119]
  PIN o[11]
    DIRECTION OUTPUT ;
    USE SIGNAL ;
    PORT
      LAYER M4 ;
        RECT  0 6.192 0.192 6.216 ;
    END
  END o[11]
  PIN o[120]
    DIRECTION OUTPUT ;
    USE SIGNAL ;
    PORT
      LAYER M4 ;
        RECT  0 24.048 0.192 24.072 ;
    END
  END o[120]
  PIN o[121]
    DIRECTION OUTPUT ;
    USE SIGNAL ;
    PORT
      LAYER M4 ;
        RECT  0 24.192 0.192 24.216 ;
    END
  END o[121]
  PIN o[122]
    DIRECTION OUTPUT ;
    USE SIGNAL ;
    PORT
      LAYER M4 ;
        RECT  0 24.384 0.192 24.408 ;
    END
  END o[122]
  PIN o[123]
    DIRECTION OUTPUT ;
    USE SIGNAL ;
    PORT
      LAYER M4 ;
        RECT  0 24.528 0.192 24.552 ;
    END
  END o[123]
  PIN o[124]
    DIRECTION OUTPUT ;
    USE SIGNAL ;
    PORT
      LAYER M4 ;
        RECT  0 24.72 0.192 24.744 ;
    END
  END o[124]
  PIN o[125]
    DIRECTION OUTPUT ;
    USE SIGNAL ;
    PORT
      LAYER M4 ;
        RECT  0 24.864 0.192 24.888 ;
    END
  END o[125]
  PIN o[126]
    DIRECTION OUTPUT ;
    USE SIGNAL ;
    PORT
      LAYER M4 ;
        RECT  0 25.008 0.192 25.032 ;
    END
  END o[126]
  PIN o[127]
    DIRECTION OUTPUT ;
    USE SIGNAL ;
    PORT
      LAYER M4 ;
        RECT  0 25.2 0.192 25.224 ;
    END
  END o[127]
  PIN o[128]
    DIRECTION OUTPUT ;
    USE SIGNAL ;
    PORT
      LAYER M4 ;
        RECT  0 25.344 0.192 25.368 ;
    END
  END o[128]
  PIN o[129]
    DIRECTION OUTPUT ;
    USE SIGNAL ;
    PORT
      LAYER M4 ;
        RECT  0 25.536 0.192 25.56 ;
    END
  END o[129]
  PIN o[12]
    DIRECTION OUTPUT ;
    USE SIGNAL ;
    PORT
      LAYER M4 ;
        RECT  0 6.384 0.192 6.408 ;
    END
  END o[12]
  PIN o[130]
    DIRECTION OUTPUT ;
    USE SIGNAL ;
    PORT
      LAYER M4 ;
        RECT  0 25.68 0.192 25.704 ;
    END
  END o[130]
  PIN o[131]
    DIRECTION OUTPUT ;
    USE SIGNAL ;
    PORT
      LAYER M4 ;
        RECT  0 25.824 0.192 25.848 ;
    END
  END o[131]
  PIN o[132]
    DIRECTION OUTPUT ;
    USE SIGNAL ;
    PORT
      LAYER M4 ;
        RECT  0 26.016 0.192 26.04 ;
    END
  END o[132]
  PIN o[133]
    DIRECTION OUTPUT ;
    USE SIGNAL ;
    PORT
      LAYER M4 ;
        RECT  0 26.16 0.192 26.184 ;
    END
  END o[133]
  PIN o[134]
    DIRECTION OUTPUT ;
    USE SIGNAL ;
    PORT
      LAYER M4 ;
        RECT  0 26.352 0.192 26.376 ;
    END
  END o[134]
  PIN o[135]
    DIRECTION OUTPUT ;
    USE SIGNAL ;
    PORT
      LAYER M4 ;
        RECT  0 26.496 0.192 26.52 ;
    END
  END o[135]
  PIN o[136]
    DIRECTION OUTPUT ;
    USE SIGNAL ;
    PORT
      LAYER M4 ;
        RECT  0 26.64 0.192 26.664 ;
    END
  END o[136]
  PIN o[137]
    DIRECTION OUTPUT ;
    USE SIGNAL ;
    PORT
      LAYER M4 ;
        RECT  0 26.832 0.192 26.856 ;
    END
  END o[137]
  PIN o[138]
    DIRECTION OUTPUT ;
    USE SIGNAL ;
    PORT
      LAYER M4 ;
        RECT  0 26.976 0.192 27 ;
    END
  END o[138]
  PIN o[139]
    DIRECTION OUTPUT ;
    USE SIGNAL ;
    PORT
      LAYER M4 ;
        RECT  0 27.168 0.192 27.192 ;
    END
  END o[139]
  PIN o[13]
    DIRECTION OUTPUT ;
    USE SIGNAL ;
    PORT
      LAYER M4 ;
        RECT  0 6.528 0.192 6.552 ;
    END
  END o[13]
  PIN o[140]
    DIRECTION OUTPUT ;
    USE SIGNAL ;
    PORT
      LAYER M4 ;
        RECT  0 27.312 0.192 27.336 ;
    END
  END o[140]
  PIN o[141]
    DIRECTION OUTPUT ;
    USE SIGNAL ;
    PORT
      LAYER M4 ;
        RECT  0 27.456 0.192 27.48 ;
    END
  END o[141]
  PIN o[142]
    DIRECTION OUTPUT ;
    USE SIGNAL ;
    PORT
      LAYER M4 ;
        RECT  0 27.648 0.192 27.672 ;
    END
  END o[142]
  PIN o[143]
    DIRECTION OUTPUT ;
    USE SIGNAL ;
    PORT
      LAYER M4 ;
        RECT  0 27.792 0.192 27.816 ;
    END
  END o[143]
  PIN o[144]
    DIRECTION OUTPUT ;
    USE SIGNAL ;
    PORT
      LAYER M4 ;
        RECT  0 27.984 0.192 28.008 ;
    END
  END o[144]
  PIN o[145]
    DIRECTION OUTPUT ;
    USE SIGNAL ;
    PORT
      LAYER M4 ;
        RECT  0 28.128 0.192 28.152 ;
    END
  END o[145]
  PIN o[146]
    DIRECTION OUTPUT ;
    USE SIGNAL ;
    PORT
      LAYER M4 ;
        RECT  0 28.272 0.192 28.296 ;
    END
  END o[146]
  PIN o[147]
    DIRECTION OUTPUT ;
    USE SIGNAL ;
    PORT
      LAYER M4 ;
        RECT  0 28.464 0.192 28.488 ;
    END
  END o[147]
  PIN o[148]
    DIRECTION OUTPUT ;
    USE SIGNAL ;
    PORT
      LAYER M4 ;
        RECT  0 28.608 0.192 28.632 ;
    END
  END o[148]
  PIN o[149]
    DIRECTION OUTPUT ;
    USE SIGNAL ;
    PORT
      LAYER M4 ;
        RECT  0 28.8 0.192 28.824 ;
    END
  END o[149]
  PIN o[14]
    DIRECTION OUTPUT ;
    USE SIGNAL ;
    PORT
      LAYER M4 ;
        RECT  0 6.72 0.192 6.744 ;
    END
  END o[14]
  PIN o[150]
    DIRECTION OUTPUT ;
    USE SIGNAL ;
    PORT
      LAYER M4 ;
        RECT  0 28.944 0.192 28.968 ;
    END
  END o[150]
  PIN o[151]
    DIRECTION OUTPUT ;
    USE SIGNAL ;
    PORT
      LAYER M4 ;
        RECT  0 29.136 0.192 29.16 ;
    END
  END o[151]
  PIN o[152]
    DIRECTION OUTPUT ;
    USE SIGNAL ;
    PORT
      LAYER M4 ;
        RECT  0 29.28 0.192 29.304 ;
    END
  END o[152]
  PIN o[153]
    DIRECTION OUTPUT ;
    USE SIGNAL ;
    PORT
      LAYER M4 ;
        RECT  0 29.424 0.192 29.448 ;
    END
  END o[153]
  PIN o[154]
    DIRECTION OUTPUT ;
    USE SIGNAL ;
    PORT
      LAYER M4 ;
        RECT  0 29.616 0.192 29.64 ;
    END
  END o[154]
  PIN o[155]
    DIRECTION OUTPUT ;
    USE SIGNAL ;
    PORT
      LAYER M4 ;
        RECT  0 29.76 0.192 29.784 ;
    END
  END o[155]
  PIN o[156]
    DIRECTION OUTPUT ;
    USE SIGNAL ;
    PORT
      LAYER M4 ;
        RECT  0 29.952 0.192 29.976 ;
    END
  END o[156]
  PIN o[157]
    DIRECTION OUTPUT ;
    USE SIGNAL ;
    PORT
      LAYER M4 ;
        RECT  0 30.096 0.192 30.12 ;
    END
  END o[157]
  PIN o[158]
    DIRECTION OUTPUT ;
    USE SIGNAL ;
    PORT
      LAYER M4 ;
        RECT  0 30.24 0.192 30.264 ;
    END
  END o[158]
  PIN o[159]
    DIRECTION OUTPUT ;
    USE SIGNAL ;
    PORT
      LAYER M4 ;
        RECT  0 30.432 0.192 30.456 ;
    END
  END o[159]
  PIN o[15]
    DIRECTION OUTPUT ;
    USE SIGNAL ;
    PORT
      LAYER M4 ;
        RECT  0 6.864 0.192 6.888 ;
    END
  END o[15]
  PIN o[160]
    DIRECTION OUTPUT ;
    USE SIGNAL ;
    PORT
      LAYER M4 ;
        RECT  0 30.576 0.192 30.6 ;
    END
  END o[160]
  PIN o[161]
    DIRECTION OUTPUT ;
    USE SIGNAL ;
    PORT
      LAYER M4 ;
        RECT  0 30.768 0.192 30.792 ;
    END
  END o[161]
  PIN o[162]
    DIRECTION OUTPUT ;
    USE SIGNAL ;
    PORT
      LAYER M4 ;
        RECT  0 30.912 0.192 30.936 ;
    END
  END o[162]
  PIN o[163]
    DIRECTION OUTPUT ;
    USE SIGNAL ;
    PORT
      LAYER M4 ;
        RECT  0 31.056 0.192 31.08 ;
    END
  END o[163]
  PIN o[164]
    DIRECTION OUTPUT ;
    USE SIGNAL ;
    PORT
      LAYER M4 ;
        RECT  0 31.248 0.192 31.272 ;
    END
  END o[164]
  PIN o[165]
    DIRECTION OUTPUT ;
    USE SIGNAL ;
    PORT
      LAYER M4 ;
        RECT  0 31.392 0.192 31.416 ;
    END
  END o[165]
  PIN o[166]
    DIRECTION OUTPUT ;
    USE SIGNAL ;
    PORT
      LAYER M4 ;
        RECT  0 31.584 0.192 31.608 ;
    END
  END o[166]
  PIN o[167]
    DIRECTION OUTPUT ;
    USE SIGNAL ;
    PORT
      LAYER M4 ;
        RECT  0 31.728 0.192 31.752 ;
    END
  END o[167]
  PIN o[168]
    DIRECTION OUTPUT ;
    USE SIGNAL ;
    PORT
      LAYER M4 ;
        RECT  0 31.872 0.192 31.896 ;
    END
  END o[168]
  PIN o[169]
    DIRECTION OUTPUT ;
    USE SIGNAL ;
    PORT
      LAYER M4 ;
        RECT  0 32.064 0.192 32.088 ;
    END
  END o[169]
  PIN o[16]
    DIRECTION OUTPUT ;
    USE SIGNAL ;
    PORT
      LAYER M4 ;
        RECT  0 7.008 0.192 7.032 ;
    END
  END o[16]
  PIN o[170]
    DIRECTION OUTPUT ;
    USE SIGNAL ;
    PORT
      LAYER M4 ;
        RECT  0 32.208 0.192 32.232 ;
    END
  END o[170]
  PIN o[171]
    DIRECTION OUTPUT ;
    USE SIGNAL ;
    PORT
      LAYER M4 ;
        RECT  0 32.4 0.192 32.424 ;
    END
  END o[171]
  PIN o[172]
    DIRECTION OUTPUT ;
    USE SIGNAL ;
    PORT
      LAYER M4 ;
        RECT  0 32.544 0.192 32.568 ;
    END
  END o[172]
  PIN o[173]
    DIRECTION OUTPUT ;
    USE SIGNAL ;
    PORT
      LAYER M4 ;
        RECT  0 32.688 0.192 32.712 ;
    END
  END o[173]
  PIN o[174]
    DIRECTION OUTPUT ;
    USE SIGNAL ;
    PORT
      LAYER M4 ;
        RECT  0 32.88 0.192 32.904 ;
    END
  END o[174]
  PIN o[175]
    DIRECTION OUTPUT ;
    USE SIGNAL ;
    PORT
      LAYER M4 ;
        RECT  0 33.024 0.192 33.048 ;
    END
  END o[175]
  PIN o[176]
    DIRECTION OUTPUT ;
    USE SIGNAL ;
    PORT
      LAYER M4 ;
        RECT  0 33.216 0.192 33.24 ;
    END
  END o[176]
  PIN o[177]
    DIRECTION OUTPUT ;
    USE SIGNAL ;
    PORT
      LAYER M4 ;
        RECT  0 33.36 0.192 33.384 ;
    END
  END o[177]
  PIN o[178]
    DIRECTION OUTPUT ;
    USE SIGNAL ;
    PORT
      LAYER M4 ;
        RECT  0 33.552 0.192 33.576 ;
    END
  END o[178]
  PIN o[179]
    DIRECTION OUTPUT ;
    USE SIGNAL ;
    PORT
      LAYER M4 ;
        RECT  0 33.696 0.192 33.72 ;
    END
  END o[179]
  PIN o[17]
    DIRECTION OUTPUT ;
    USE SIGNAL ;
    PORT
      LAYER M4 ;
        RECT  0 7.2 0.192 7.224 ;
    END
  END o[17]
  PIN o[180]
    DIRECTION OUTPUT ;
    USE SIGNAL ;
    PORT
      LAYER M4 ;
        RECT  0 33.84 0.192 33.864 ;
    END
  END o[180]
  PIN o[181]
    DIRECTION OUTPUT ;
    USE SIGNAL ;
    PORT
      LAYER M4 ;
        RECT  0 34.032 0.192 34.056 ;
    END
  END o[181]
  PIN o[182]
    DIRECTION OUTPUT ;
    USE SIGNAL ;
    PORT
      LAYER M4 ;
        RECT  0 34.176 0.192 34.2 ;
    END
  END o[182]
  PIN o[183]
    DIRECTION OUTPUT ;
    USE SIGNAL ;
    PORT
      LAYER M4 ;
        RECT  0 34.368 0.192 34.392 ;
    END
  END o[183]
  PIN o[184]
    DIRECTION OUTPUT ;
    USE SIGNAL ;
    PORT
      LAYER M4 ;
        RECT  0 34.512 0.192 34.536 ;
    END
  END o[184]
  PIN o[185]
    DIRECTION OUTPUT ;
    USE SIGNAL ;
    PORT
      LAYER M4 ;
        RECT  0 34.656 0.192 34.68 ;
    END
  END o[185]
  PIN o[186]
    DIRECTION OUTPUT ;
    USE SIGNAL ;
    PORT
      LAYER M4 ;
        RECT  0 34.848 0.192 34.872 ;
    END
  END o[186]
  PIN o[187]
    DIRECTION OUTPUT ;
    USE SIGNAL ;
    PORT
      LAYER M4 ;
        RECT  0 34.992 0.192 35.016 ;
    END
  END o[187]
  PIN o[188]
    DIRECTION OUTPUT ;
    USE SIGNAL ;
    PORT
      LAYER M4 ;
        RECT  0 35.184 0.192 35.208 ;
    END
  END o[188]
  PIN o[189]
    DIRECTION OUTPUT ;
    USE SIGNAL ;
    PORT
      LAYER M4 ;
        RECT  0 35.328 0.192 35.352 ;
    END
  END o[189]
  PIN o[18]
    DIRECTION OUTPUT ;
    USE SIGNAL ;
    PORT
      LAYER M4 ;
        RECT  0 7.344 0.192 7.368 ;
    END
  END o[18]
  PIN o[190]
    DIRECTION OUTPUT ;
    USE SIGNAL ;
    PORT
      LAYER M4 ;
        RECT  0 35.472 0.192 35.496 ;
    END
  END o[190]
  PIN o[191]
    DIRECTION OUTPUT ;
    USE SIGNAL ;
    PORT
      LAYER M4 ;
        RECT  0 35.664 0.192 35.688 ;
    END
  END o[191]
  PIN o[192]
    DIRECTION OUTPUT ;
    USE SIGNAL ;
    PORT
      LAYER M4 ;
        RECT  0 35.808 0.192 35.832 ;
    END
  END o[192]
  PIN o[193]
    DIRECTION OUTPUT ;
    USE SIGNAL ;
    PORT
      LAYER M4 ;
        RECT  0 36 0.192 36.024 ;
    END
  END o[193]
  PIN o[194]
    DIRECTION OUTPUT ;
    USE SIGNAL ;
    PORT
      LAYER M4 ;
        RECT  0 36.144 0.192 36.168 ;
    END
  END o[194]
  PIN o[195]
    DIRECTION OUTPUT ;
    USE SIGNAL ;
    PORT
      LAYER M4 ;
        RECT  0 36.288 0.192 36.312 ;
    END
  END o[195]
  PIN o[196]
    DIRECTION OUTPUT ;
    USE SIGNAL ;
    PORT
      LAYER M4 ;
        RECT  0 36.48 0.192 36.504 ;
    END
  END o[196]
  PIN o[197]
    DIRECTION OUTPUT ;
    USE SIGNAL ;
    PORT
      LAYER M4 ;
        RECT  0 36.624 0.192 36.648 ;
    END
  END o[197]
  PIN o[198]
    DIRECTION OUTPUT ;
    USE SIGNAL ;
    PORT
      LAYER M4 ;
        RECT  0 36.816 0.192 36.84 ;
    END
  END o[198]
  PIN o[199]
    DIRECTION OUTPUT ;
    USE SIGNAL ;
    PORT
      LAYER M4 ;
        RECT  0 36.96 0.192 36.984 ;
    END
  END o[199]
  PIN o[19]
    DIRECTION OUTPUT ;
    USE SIGNAL ;
    PORT
      LAYER M4 ;
        RECT  0 7.536 0.192 7.56 ;
    END
  END o[19]
  PIN o[1]
    DIRECTION OUTPUT ;
    USE SIGNAL ;
    PORT
      LAYER M4 ;
        RECT  0 4.56 0.192 4.584 ;
    END
  END o[1]
  PIN o[200]
    DIRECTION OUTPUT ;
    USE SIGNAL ;
    PORT
      LAYER M4 ;
        RECT  0 37.152 0.192 37.176 ;
    END
  END o[200]
  PIN o[201]
    DIRECTION OUTPUT ;
    USE SIGNAL ;
    PORT
      LAYER M4 ;
        RECT  0 37.296 0.192 37.32 ;
    END
  END o[201]
  PIN o[202]
    DIRECTION OUTPUT ;
    USE SIGNAL ;
    PORT
      LAYER M4 ;
        RECT  0 37.44 0.192 37.464 ;
    END
  END o[202]
  PIN o[203]
    DIRECTION OUTPUT ;
    USE SIGNAL ;
    PORT
      LAYER M4 ;
        RECT  0 37.632 0.192 37.656 ;
    END
  END o[203]
  PIN o[204]
    DIRECTION OUTPUT ;
    USE SIGNAL ;
    PORT
      LAYER M4 ;
        RECT  0 37.776 0.192 37.8 ;
    END
  END o[204]
  PIN o[205]
    DIRECTION OUTPUT ;
    USE SIGNAL ;
    PORT
      LAYER M4 ;
        RECT  0 37.968 0.192 37.992 ;
    END
  END o[205]
  PIN o[206]
    DIRECTION OUTPUT ;
    USE SIGNAL ;
    PORT
      LAYER M4 ;
        RECT  0 38.112 0.192 38.136 ;
    END
  END o[206]
  PIN o[207]
    DIRECTION OUTPUT ;
    USE SIGNAL ;
    PORT
      LAYER M4 ;
        RECT  0 38.256 0.192 38.28 ;
    END
  END o[207]
  PIN o[208]
    DIRECTION OUTPUT ;
    USE SIGNAL ;
    PORT
      LAYER M4 ;
        RECT  0 38.448 0.192 38.472 ;
    END
  END o[208]
  PIN o[209]
    DIRECTION OUTPUT ;
    USE SIGNAL ;
    PORT
      LAYER M4 ;
        RECT  0 38.592 0.192 38.616 ;
    END
  END o[209]
  PIN o[20]
    DIRECTION OUTPUT ;
    USE SIGNAL ;
    PORT
      LAYER M4 ;
        RECT  0 7.68 0.192 7.704 ;
    END
  END o[20]
  PIN o[210]
    DIRECTION OUTPUT ;
    USE SIGNAL ;
    PORT
      LAYER M4 ;
        RECT  0 38.784 0.192 38.808 ;
    END
  END o[210]
  PIN o[211]
    DIRECTION OUTPUT ;
    USE SIGNAL ;
    PORT
      LAYER M4 ;
        RECT  0 38.928 0.192 38.952 ;
    END
  END o[211]
  PIN o[212]
    DIRECTION OUTPUT ;
    USE SIGNAL ;
    PORT
      LAYER M4 ;
        RECT  0 39.072 0.192 39.096 ;
    END
  END o[212]
  PIN o[213]
    DIRECTION OUTPUT ;
    USE SIGNAL ;
    PORT
      LAYER M4 ;
        RECT  0 39.264 0.192 39.288 ;
    END
  END o[213]
  PIN o[214]
    DIRECTION OUTPUT ;
    USE SIGNAL ;
    PORT
      LAYER M4 ;
        RECT  0 39.408 0.192 39.432 ;
    END
  END o[214]
  PIN o[215]
    DIRECTION OUTPUT ;
    USE SIGNAL ;
    PORT
      LAYER M4 ;
        RECT  0 39.6 0.192 39.624 ;
    END
  END o[215]
  PIN o[216]
    DIRECTION OUTPUT ;
    USE SIGNAL ;
    PORT
      LAYER M4 ;
        RECT  0 39.744 0.192 39.768 ;
    END
  END o[216]
  PIN o[217]
    DIRECTION OUTPUT ;
    USE SIGNAL ;
    PORT
      LAYER M4 ;
        RECT  0 39.888 0.192 39.912 ;
    END
  END o[217]
  PIN o[218]
    DIRECTION OUTPUT ;
    USE SIGNAL ;
    PORT
      LAYER M4 ;
        RECT  0 40.08 0.192 40.104 ;
    END
  END o[218]
  PIN o[219]
    DIRECTION OUTPUT ;
    USE SIGNAL ;
    PORT
      LAYER M4 ;
        RECT  0 40.224 0.192 40.248 ;
    END
  END o[219]
  PIN o[21]
    DIRECTION OUTPUT ;
    USE SIGNAL ;
    PORT
      LAYER M4 ;
        RECT  0 7.872 0.192 7.896 ;
    END
  END o[21]
  PIN o[220]
    DIRECTION OUTPUT ;
    USE SIGNAL ;
    PORT
      LAYER M4 ;
        RECT  0 40.416 0.192 40.44 ;
    END
  END o[220]
  PIN o[221]
    DIRECTION OUTPUT ;
    USE SIGNAL ;
    PORT
      LAYER M4 ;
        RECT  0 40.56 0.192 40.584 ;
    END
  END o[221]
  PIN o[222]
    DIRECTION OUTPUT ;
    USE SIGNAL ;
    PORT
      LAYER M4 ;
        RECT  0 40.704 0.192 40.728 ;
    END
  END o[222]
  PIN o[223]
    DIRECTION OUTPUT ;
    USE SIGNAL ;
    PORT
      LAYER M4 ;
        RECT  0 40.896 0.192 40.92 ;
    END
  END o[223]
  PIN o[224]
    DIRECTION OUTPUT ;
    USE SIGNAL ;
    PORT
      LAYER M4 ;
        RECT  0 41.04 0.192 41.064 ;
    END
  END o[224]
  PIN o[225]
    DIRECTION OUTPUT ;
    USE SIGNAL ;
    PORT
      LAYER M4 ;
        RECT  0 41.232 0.192 41.256 ;
    END
  END o[225]
  PIN o[226]
    DIRECTION OUTPUT ;
    USE SIGNAL ;
    PORT
      LAYER M4 ;
        RECT  0 41.376 0.192 41.4 ;
    END
  END o[226]
  PIN o[227]
    DIRECTION OUTPUT ;
    USE SIGNAL ;
    PORT
      LAYER M4 ;
        RECT  0 41.568 0.192 41.592 ;
    END
  END o[227]
  PIN o[228]
    DIRECTION OUTPUT ;
    USE SIGNAL ;
    PORT
      LAYER M4 ;
        RECT  0 41.712 0.192 41.736 ;
    END
  END o[228]
  PIN o[229]
    DIRECTION OUTPUT ;
    USE SIGNAL ;
    PORT
      LAYER M4 ;
        RECT  0 41.856 0.192 41.88 ;
    END
  END o[229]
  PIN o[22]
    DIRECTION OUTPUT ;
    USE SIGNAL ;
    PORT
      LAYER M4 ;
        RECT  0 8.016 0.192 8.04 ;
    END
  END o[22]
  PIN o[230]
    DIRECTION OUTPUT ;
    USE SIGNAL ;
    PORT
      LAYER M4 ;
        RECT  0 42.048 0.192 42.072 ;
    END
  END o[230]
  PIN o[231]
    DIRECTION OUTPUT ;
    USE SIGNAL ;
    PORT
      LAYER M4 ;
        RECT  0 42.192 0.192 42.216 ;
    END
  END o[231]
  PIN o[232]
    DIRECTION OUTPUT ;
    USE SIGNAL ;
    PORT
      LAYER M4 ;
        RECT  0 42.384 0.192 42.408 ;
    END
  END o[232]
  PIN o[233]
    DIRECTION OUTPUT ;
    USE SIGNAL ;
    PORT
      LAYER M4 ;
        RECT  0 42.528 0.192 42.552 ;
    END
  END o[233]
  PIN o[234]
    DIRECTION OUTPUT ;
    USE SIGNAL ;
    PORT
      LAYER M4 ;
        RECT  0 42.672 0.192 42.696 ;
    END
  END o[234]
  PIN o[235]
    DIRECTION OUTPUT ;
    USE SIGNAL ;
    PORT
      LAYER M4 ;
        RECT  0 42.864 0.192 42.888 ;
    END
  END o[235]
  PIN o[236]
    DIRECTION OUTPUT ;
    USE SIGNAL ;
    PORT
      LAYER M4 ;
        RECT  0 43.008 0.192 43.032 ;
    END
  END o[236]
  PIN o[237]
    DIRECTION OUTPUT ;
    USE SIGNAL ;
    PORT
      LAYER M4 ;
        RECT  0 43.2 0.192 43.224 ;
    END
  END o[237]
  PIN o[238]
    DIRECTION OUTPUT ;
    USE SIGNAL ;
    PORT
      LAYER M4 ;
        RECT  0 43.344 0.192 43.368 ;
    END
  END o[238]
  PIN o[239]
    DIRECTION OUTPUT ;
    USE SIGNAL ;
    PORT
      LAYER M4 ;
        RECT  0 43.488 0.192 43.512 ;
    END
  END o[239]
  PIN o[23]
    DIRECTION OUTPUT ;
    USE SIGNAL ;
    PORT
      LAYER M4 ;
        RECT  0 8.16 0.192 8.184 ;
    END
  END o[23]
  PIN o[240]
    DIRECTION OUTPUT ;
    USE SIGNAL ;
    PORT
      LAYER M4 ;
        RECT  0 43.68 0.192 43.704 ;
    END
  END o[240]
  PIN o[241]
    DIRECTION OUTPUT ;
    USE SIGNAL ;
    PORT
      LAYER M4 ;
        RECT  0 43.824 0.192 43.848 ;
    END
  END o[241]
  PIN o[242]
    DIRECTION OUTPUT ;
    USE SIGNAL ;
    PORT
      LAYER M4 ;
        RECT  0 44.016 0.192 44.04 ;
    END
  END o[242]
  PIN o[243]
    DIRECTION OUTPUT ;
    USE SIGNAL ;
    PORT
      LAYER M4 ;
        RECT  0 44.16 0.192 44.184 ;
    END
  END o[243]
  PIN o[244]
    DIRECTION OUTPUT ;
    USE SIGNAL ;
    PORT
      LAYER M4 ;
        RECT  0 44.304 0.192 44.328 ;
    END
  END o[244]
  PIN o[245]
    DIRECTION OUTPUT ;
    USE SIGNAL ;
    PORT
      LAYER M4 ;
        RECT  0 44.496 0.192 44.52 ;
    END
  END o[245]
  PIN o[246]
    DIRECTION OUTPUT ;
    USE SIGNAL ;
    PORT
      LAYER M4 ;
        RECT  0 44.64 0.192 44.664 ;
    END
  END o[246]
  PIN o[247]
    DIRECTION OUTPUT ;
    USE SIGNAL ;
    PORT
      LAYER M4 ;
        RECT  0 44.832 0.192 44.856 ;
    END
  END o[247]
  PIN o[248]
    DIRECTION OUTPUT ;
    USE SIGNAL ;
    PORT
      LAYER M4 ;
        RECT  0 44.976 0.192 45 ;
    END
  END o[248]
  PIN o[249]
    DIRECTION OUTPUT ;
    USE SIGNAL ;
    PORT
      LAYER M4 ;
        RECT  0 45.12 0.192 45.144 ;
    END
  END o[249]
  PIN o[24]
    DIRECTION OUTPUT ;
    USE SIGNAL ;
    PORT
      LAYER M4 ;
        RECT  0 8.352 0.192 8.376 ;
    END
  END o[24]
  PIN o[250]
    DIRECTION OUTPUT ;
    USE SIGNAL ;
    PORT
      LAYER M4 ;
        RECT  0 45.312 0.192 45.336 ;
    END
  END o[250]
  PIN o[251]
    DIRECTION OUTPUT ;
    USE SIGNAL ;
    PORT
      LAYER M4 ;
        RECT  0 45.456 0.192 45.48 ;
    END
  END o[251]
  PIN o[252]
    DIRECTION OUTPUT ;
    USE SIGNAL ;
    PORT
      LAYER M4 ;
        RECT  0 45.648 0.192 45.672 ;
    END
  END o[252]
  PIN o[253]
    DIRECTION OUTPUT ;
    USE SIGNAL ;
    PORT
      LAYER M4 ;
        RECT  0 45.792 0.192 45.816 ;
    END
  END o[253]
  PIN o[254]
    DIRECTION OUTPUT ;
    USE SIGNAL ;
    PORT
      LAYER M4 ;
        RECT  0 45.984 0.192 46.008 ;
    END
  END o[254]
  PIN o[255]
    DIRECTION OUTPUT ;
    USE SIGNAL ;
    PORT
      LAYER M4 ;
        RECT  0 46.128 0.192 46.152 ;
    END
  END o[255]
  PIN o[256]
    DIRECTION OUTPUT ;
    USE SIGNAL ;
    PORT
      LAYER M4 ;
        RECT  0 46.272 0.192 46.296 ;
    END
  END o[256]
  PIN o[257]
    DIRECTION OUTPUT ;
    USE SIGNAL ;
    PORT
      LAYER M4 ;
        RECT  0 46.464 0.192 46.488 ;
    END
  END o[257]
  PIN o[258]
    DIRECTION OUTPUT ;
    USE SIGNAL ;
    PORT
      LAYER M4 ;
        RECT  0 46.608 0.192 46.632 ;
    END
  END o[258]
  PIN o[259]
    DIRECTION OUTPUT ;
    USE SIGNAL ;
    PORT
      LAYER M4 ;
        RECT  0 46.8 0.192 46.824 ;
    END
  END o[259]
  PIN o[25]
    DIRECTION OUTPUT ;
    USE SIGNAL ;
    PORT
      LAYER M4 ;
        RECT  0 8.496 0.192 8.52 ;
    END
  END o[25]
  PIN o[260]
    DIRECTION OUTPUT ;
    USE SIGNAL ;
    PORT
      LAYER M4 ;
        RECT  0 46.944 0.192 46.968 ;
    END
  END o[260]
  PIN o[261]
    DIRECTION OUTPUT ;
    USE SIGNAL ;
    PORT
      LAYER M4 ;
        RECT  0 47.088 0.192 47.112 ;
    END
  END o[261]
  PIN o[262]
    DIRECTION OUTPUT ;
    USE SIGNAL ;
    PORT
      LAYER M4 ;
        RECT  0 47.28 0.192 47.304 ;
    END
  END o[262]
  PIN o[263]
    DIRECTION OUTPUT ;
    USE SIGNAL ;
    PORT
      LAYER M4 ;
        RECT  0 47.424 0.192 47.448 ;
    END
  END o[263]
  PIN o[264]
    DIRECTION OUTPUT ;
    USE SIGNAL ;
    PORT
      LAYER M4 ;
        RECT  0 47.616 0.192 47.64 ;
    END
  END o[264]
  PIN o[265]
    DIRECTION OUTPUT ;
    USE SIGNAL ;
    PORT
      LAYER M4 ;
        RECT  0 47.76 0.192 47.784 ;
    END
  END o[265]
  PIN o[266]
    DIRECTION OUTPUT ;
    USE SIGNAL ;
    PORT
      LAYER M4 ;
        RECT  0 47.904 0.192 47.928 ;
    END
  END o[266]
  PIN o[267]
    DIRECTION OUTPUT ;
    USE SIGNAL ;
    PORT
      LAYER M4 ;
        RECT  0 48.096 0.192 48.12 ;
    END
  END o[267]
  PIN o[268]
    DIRECTION OUTPUT ;
    USE SIGNAL ;
    PORT
      LAYER M4 ;
        RECT  0 48.24 0.192 48.264 ;
    END
  END o[268]
  PIN o[269]
    DIRECTION OUTPUT ;
    USE SIGNAL ;
    PORT
      LAYER M4 ;
        RECT  0 48.432 0.192 48.456 ;
    END
  END o[269]
  PIN o[26]
    DIRECTION OUTPUT ;
    USE SIGNAL ;
    PORT
      LAYER M4 ;
        RECT  0 8.688 0.192 8.712 ;
    END
  END o[26]
  PIN o[270]
    DIRECTION OUTPUT ;
    USE SIGNAL ;
    PORT
      LAYER M4 ;
        RECT  0 48.576 0.192 48.6 ;
    END
  END o[270]
  PIN o[271]
    DIRECTION OUTPUT ;
    USE SIGNAL ;
    PORT
      LAYER M4 ;
        RECT  0 48.72 0.192 48.744 ;
    END
  END o[271]
  PIN o[272]
    DIRECTION OUTPUT ;
    USE SIGNAL ;
    PORT
      LAYER M4 ;
        RECT  0 48.912 0.192 48.936 ;
    END
  END o[272]
  PIN o[273]
    DIRECTION OUTPUT ;
    USE SIGNAL ;
    PORT
      LAYER M4 ;
        RECT  0 49.056 0.192 49.08 ;
    END
  END o[273]
  PIN o[274]
    DIRECTION OUTPUT ;
    USE SIGNAL ;
    PORT
      LAYER M4 ;
        RECT  0 49.248 0.192 49.272 ;
    END
  END o[274]
  PIN o[275]
    DIRECTION OUTPUT ;
    USE SIGNAL ;
    PORT
      LAYER M4 ;
        RECT  0 49.392 0.192 49.416 ;
    END
  END o[275]
  PIN o[276]
    DIRECTION OUTPUT ;
    USE SIGNAL ;
    PORT
      LAYER M4 ;
        RECT  0 49.536 0.192 49.56 ;
    END
  END o[276]
  PIN o[277]
    DIRECTION OUTPUT ;
    USE SIGNAL ;
    PORT
      LAYER M4 ;
        RECT  0 49.728 0.192 49.752 ;
    END
  END o[277]
  PIN o[278]
    DIRECTION OUTPUT ;
    USE SIGNAL ;
    PORT
      LAYER M4 ;
        RECT  0 49.872 0.192 49.896 ;
    END
  END o[278]
  PIN o[279]
    DIRECTION OUTPUT ;
    USE SIGNAL ;
    PORT
      LAYER M4 ;
        RECT  0 50.064 0.192 50.088 ;
    END
  END o[279]
  PIN o[27]
    DIRECTION OUTPUT ;
    USE SIGNAL ;
    PORT
      LAYER M4 ;
        RECT  0 8.832 0.192 8.856 ;
    END
  END o[27]
  PIN o[280]
    DIRECTION OUTPUT ;
    USE SIGNAL ;
    PORT
      LAYER M4 ;
        RECT  0 50.208 0.192 50.232 ;
    END
  END o[280]
  PIN o[281]
    DIRECTION OUTPUT ;
    USE SIGNAL ;
    PORT
      LAYER M4 ;
        RECT  0 50.4 0.192 50.424 ;
    END
  END o[281]
  PIN o[282]
    DIRECTION OUTPUT ;
    USE SIGNAL ;
    PORT
      LAYER M4 ;
        RECT  0 50.544 0.192 50.568 ;
    END
  END o[282]
  PIN o[283]
    DIRECTION OUTPUT ;
    USE SIGNAL ;
    PORT
      LAYER M4 ;
        RECT  0 50.688 0.192 50.712 ;
    END
  END o[283]
  PIN o[284]
    DIRECTION OUTPUT ;
    USE SIGNAL ;
    PORT
      LAYER M4 ;
        RECT  0 50.88 0.192 50.904 ;
    END
  END o[284]
  PIN o[285]
    DIRECTION OUTPUT ;
    USE SIGNAL ;
    PORT
      LAYER M4 ;
        RECT  0 51.024 0.192 51.048 ;
    END
  END o[285]
  PIN o[286]
    DIRECTION OUTPUT ;
    USE SIGNAL ;
    PORT
      LAYER M4 ;
        RECT  0 51.216 0.192 51.24 ;
    END
  END o[286]
  PIN o[287]
    DIRECTION OUTPUT ;
    USE SIGNAL ;
    PORT
      LAYER M4 ;
        RECT  0 51.36 0.192 51.384 ;
    END
  END o[287]
  PIN o[288]
    DIRECTION OUTPUT ;
    USE SIGNAL ;
    PORT
      LAYER M4 ;
        RECT  0 51.504 0.192 51.528 ;
    END
  END o[288]
  PIN o[289]
    DIRECTION OUTPUT ;
    USE SIGNAL ;
    PORT
      LAYER M4 ;
        RECT  0 51.696 0.192 51.72 ;
    END
  END o[289]
  PIN o[28]
    DIRECTION OUTPUT ;
    USE SIGNAL ;
    PORT
      LAYER M4 ;
        RECT  0 8.976 0.192 9 ;
    END
  END o[28]
  PIN o[290]
    DIRECTION OUTPUT ;
    USE SIGNAL ;
    PORT
      LAYER M4 ;
        RECT  0 51.84 0.192 51.864 ;
    END
  END o[290]
  PIN o[291]
    DIRECTION OUTPUT ;
    USE SIGNAL ;
    PORT
      LAYER M4 ;
        RECT  0 52.032 0.192 52.056 ;
    END
  END o[291]
  PIN o[292]
    DIRECTION OUTPUT ;
    USE SIGNAL ;
    PORT
      LAYER M4 ;
        RECT  0 52.176 0.192 52.2 ;
    END
  END o[292]
  PIN o[293]
    DIRECTION OUTPUT ;
    USE SIGNAL ;
    PORT
      LAYER M4 ;
        RECT  0 52.32 0.192 52.344 ;
    END
  END o[293]
  PIN o[294]
    DIRECTION OUTPUT ;
    USE SIGNAL ;
    PORT
      LAYER M4 ;
        RECT  0 52.512 0.192 52.536 ;
    END
  END o[294]
  PIN o[295]
    DIRECTION OUTPUT ;
    USE SIGNAL ;
    PORT
      LAYER M4 ;
        RECT  0 52.656 0.192 52.68 ;
    END
  END o[295]
  PIN o[296]
    DIRECTION OUTPUT ;
    USE SIGNAL ;
    PORT
      LAYER M4 ;
        RECT  0 52.848 0.192 52.872 ;
    END
  END o[296]
  PIN o[297]
    DIRECTION OUTPUT ;
    USE SIGNAL ;
    PORT
      LAYER M4 ;
        RECT  0 52.992 0.192 53.016 ;
    END
  END o[297]
  PIN o[298]
    DIRECTION OUTPUT ;
    USE SIGNAL ;
    PORT
      LAYER M4 ;
        RECT  0 53.136 0.192 53.16 ;
    END
  END o[298]
  PIN o[299]
    DIRECTION OUTPUT ;
    USE SIGNAL ;
    PORT
      LAYER M4 ;
        RECT  0 53.328 0.192 53.352 ;
    END
  END o[299]
  PIN o[29]
    DIRECTION OUTPUT ;
    USE SIGNAL ;
    PORT
      LAYER M4 ;
        RECT  0 9.168 0.192 9.192 ;
    END
  END o[29]
  PIN o[2]
    DIRECTION OUTPUT ;
    USE SIGNAL ;
    PORT
      LAYER M4 ;
        RECT  0 4.752 0.192 4.776 ;
    END
  END o[2]
  PIN o[300]
    DIRECTION OUTPUT ;
    USE SIGNAL ;
    PORT
      LAYER M4 ;
        RECT  0 53.472 0.192 53.496 ;
    END
  END o[300]
  PIN o[301]
    DIRECTION OUTPUT ;
    USE SIGNAL ;
    PORT
      LAYER M4 ;
        RECT  0 53.664 0.192 53.688 ;
    END
  END o[301]
  PIN o[302]
    DIRECTION OUTPUT ;
    USE SIGNAL ;
    PORT
      LAYER M4 ;
        RECT  0 53.808 0.192 53.832 ;
    END
  END o[302]
  PIN o[303]
    DIRECTION OUTPUT ;
    USE SIGNAL ;
    PORT
      LAYER M4 ;
        RECT  0 54 0.192 54.024 ;
    END
  END o[303]
  PIN o[304]
    DIRECTION OUTPUT ;
    USE SIGNAL ;
    PORT
      LAYER M4 ;
        RECT  0 54.144 0.192 54.168 ;
    END
  END o[304]
  PIN o[305]
    DIRECTION OUTPUT ;
    USE SIGNAL ;
    PORT
      LAYER M4 ;
        RECT  0 54.288 0.192 54.312 ;
    END
  END o[305]
  PIN o[306]
    DIRECTION OUTPUT ;
    USE SIGNAL ;
    PORT
      LAYER M4 ;
        RECT  0 54.48 0.192 54.504 ;
    END
  END o[306]
  PIN o[307]
    DIRECTION OUTPUT ;
    USE SIGNAL ;
    PORT
      LAYER M4 ;
        RECT  0 54.624 0.192 54.648 ;
    END
  END o[307]
  PIN o[308]
    DIRECTION OUTPUT ;
    USE SIGNAL ;
    PORT
      LAYER M4 ;
        RECT  0 54.816 0.192 54.84 ;
    END
  END o[308]
  PIN o[309]
    DIRECTION OUTPUT ;
    USE SIGNAL ;
    PORT
      LAYER M4 ;
        RECT  0 54.96 0.192 54.984 ;
    END
  END o[309]
  PIN o[30]
    DIRECTION OUTPUT ;
    USE SIGNAL ;
    PORT
      LAYER M4 ;
        RECT  0 9.312 0.192 9.336 ;
    END
  END o[30]
  PIN o[310]
    DIRECTION OUTPUT ;
    USE SIGNAL ;
    PORT
      LAYER M4 ;
        RECT  0 55.104 0.192 55.128 ;
    END
  END o[310]
  PIN o[311]
    DIRECTION OUTPUT ;
    USE SIGNAL ;
    PORT
      LAYER M4 ;
        RECT  0 55.296 0.192 55.32 ;
    END
  END o[311]
  PIN o[312]
    DIRECTION OUTPUT ;
    USE SIGNAL ;
    PORT
      LAYER M4 ;
        RECT  0 55.44 0.192 55.464 ;
    END
  END o[312]
  PIN o[313]
    DIRECTION OUTPUT ;
    USE SIGNAL ;
    PORT
      LAYER M4 ;
        RECT  0 55.632 0.192 55.656 ;
    END
  END o[313]
  PIN o[314]
    DIRECTION OUTPUT ;
    USE SIGNAL ;
    PORT
      LAYER M4 ;
        RECT  0 55.776 0.192 55.8 ;
    END
  END o[314]
  PIN o[315]
    DIRECTION OUTPUT ;
    USE SIGNAL ;
    PORT
      LAYER M4 ;
        RECT  0 55.92 0.192 55.944 ;
    END
  END o[315]
  PIN o[316]
    DIRECTION OUTPUT ;
    USE SIGNAL ;
    PORT
      LAYER M4 ;
        RECT  0 56.112 0.192 56.136 ;
    END
  END o[316]
  PIN o[317]
    DIRECTION OUTPUT ;
    USE SIGNAL ;
    PORT
      LAYER M4 ;
        RECT  0 56.256 0.192 56.28 ;
    END
  END o[317]
  PIN o[318]
    DIRECTION OUTPUT ;
    USE SIGNAL ;
    PORT
      LAYER M4 ;
        RECT  0 56.448 0.192 56.472 ;
    END
  END o[318]
  PIN o[319]
    DIRECTION OUTPUT ;
    USE SIGNAL ;
    PORT
      LAYER M4 ;
        RECT  0 56.592 0.192 56.616 ;
    END
  END o[319]
  PIN o[31]
    DIRECTION OUTPUT ;
    USE SIGNAL ;
    PORT
      LAYER M4 ;
        RECT  0 9.504 0.192 9.528 ;
    END
  END o[31]
  PIN o[320]
    DIRECTION OUTPUT ;
    USE SIGNAL ;
    PORT
      LAYER M4 ;
        RECT  0 56.736 0.192 56.76 ;
    END
  END o[320]
  PIN o[321]
    DIRECTION OUTPUT ;
    USE SIGNAL ;
    PORT
      LAYER M4 ;
        RECT  0 56.928 0.192 56.952 ;
    END
  END o[321]
  PIN o[322]
    DIRECTION OUTPUT ;
    USE SIGNAL ;
    PORT
      LAYER M4 ;
        RECT  0 57.072 0.192 57.096 ;
    END
  END o[322]
  PIN o[323]
    DIRECTION OUTPUT ;
    USE SIGNAL ;
    PORT
      LAYER M4 ;
        RECT  0 57.264 0.192 57.288 ;
    END
  END o[323]
  PIN o[324]
    DIRECTION OUTPUT ;
    USE SIGNAL ;
    PORT
      LAYER M4 ;
        RECT  0 57.408 0.192 57.432 ;
    END
  END o[324]
  PIN o[325]
    DIRECTION OUTPUT ;
    USE SIGNAL ;
    PORT
      LAYER M4 ;
        RECT  0 57.552 0.192 57.576 ;
    END
  END o[325]
  PIN o[326]
    DIRECTION OUTPUT ;
    USE SIGNAL ;
    PORT
      LAYER M4 ;
        RECT  0 57.744 0.192 57.768 ;
    END
  END o[326]
  PIN o[327]
    DIRECTION OUTPUT ;
    USE SIGNAL ;
    PORT
      LAYER M4 ;
        RECT  0 57.888 0.192 57.912 ;
    END
  END o[327]
  PIN o[328]
    DIRECTION OUTPUT ;
    USE SIGNAL ;
    PORT
      LAYER M4 ;
        RECT  0 58.08 0.192 58.104 ;
    END
  END o[328]
  PIN o[329]
    DIRECTION OUTPUT ;
    USE SIGNAL ;
    PORT
      LAYER M4 ;
        RECT  0 58.224 0.192 58.248 ;
    END
  END o[329]
  PIN o[32]
    DIRECTION OUTPUT ;
    USE SIGNAL ;
    PORT
      LAYER M4 ;
        RECT  0 9.648 0.192 9.672 ;
    END
  END o[32]
  PIN o[330]
    DIRECTION OUTPUT ;
    USE SIGNAL ;
    PORT
      LAYER M4 ;
        RECT  0 58.416 0.192 58.44 ;
    END
  END o[330]
  PIN o[331]
    DIRECTION OUTPUT ;
    USE SIGNAL ;
    PORT
      LAYER M4 ;
        RECT  0 58.56 0.192 58.584 ;
    END
  END o[331]
  PIN o[332]
    DIRECTION OUTPUT ;
    USE SIGNAL ;
    PORT
      LAYER M4 ;
        RECT  0 58.704 0.192 58.728 ;
    END
  END o[332]
  PIN o[333]
    DIRECTION OUTPUT ;
    USE SIGNAL ;
    PORT
      LAYER M4 ;
        RECT  0 58.896 0.192 58.92 ;
    END
  END o[333]
  PIN o[334]
    DIRECTION OUTPUT ;
    USE SIGNAL ;
    PORT
      LAYER M4 ;
        RECT  0 59.04 0.192 59.064 ;
    END
  END o[334]
  PIN o[335]
    DIRECTION OUTPUT ;
    USE SIGNAL ;
    PORT
      LAYER M4 ;
        RECT  0 59.232 0.192 59.256 ;
    END
  END o[335]
  PIN o[336]
    DIRECTION OUTPUT ;
    USE SIGNAL ;
    PORT
      LAYER M4 ;
        RECT  0 59.376 0.192 59.4 ;
    END
  END o[336]
  PIN o[337]
    DIRECTION OUTPUT ;
    USE SIGNAL ;
    PORT
      LAYER M4 ;
        RECT  0 59.52 0.192 59.544 ;
    END
  END o[337]
  PIN o[338]
    DIRECTION OUTPUT ;
    USE SIGNAL ;
    PORT
      LAYER M4 ;
        RECT  0 59.712 0.192 59.736 ;
    END
  END o[338]
  PIN o[339]
    DIRECTION OUTPUT ;
    USE SIGNAL ;
    PORT
      LAYER M4 ;
        RECT  0 59.856 0.192 59.88 ;
    END
  END o[339]
  PIN o[33]
    DIRECTION OUTPUT ;
    USE SIGNAL ;
    PORT
      LAYER M4 ;
        RECT  0 9.792 0.192 9.816 ;
    END
  END o[33]
  PIN o[340]
    DIRECTION OUTPUT ;
    USE SIGNAL ;
    PORT
      LAYER M4 ;
        RECT  0 60.048 0.192 60.072 ;
    END
  END o[340]
  PIN o[341]
    DIRECTION OUTPUT ;
    USE SIGNAL ;
    PORT
      LAYER M4 ;
        RECT  0 60.192 0.192 60.216 ;
    END
  END o[341]
  PIN o[342]
    DIRECTION OUTPUT ;
    USE SIGNAL ;
    PORT
      LAYER M4 ;
        RECT  0 60.336 0.192 60.36 ;
    END
  END o[342]
  PIN o[343]
    DIRECTION OUTPUT ;
    USE SIGNAL ;
    PORT
      LAYER M4 ;
        RECT  0 60.528 0.192 60.552 ;
    END
  END o[343]
  PIN o[344]
    DIRECTION OUTPUT ;
    USE SIGNAL ;
    PORT
      LAYER M4 ;
        RECT  0 60.672 0.192 60.696 ;
    END
  END o[344]
  PIN o[345]
    DIRECTION OUTPUT ;
    USE SIGNAL ;
    PORT
      LAYER M4 ;
        RECT  0 60.864 0.192 60.888 ;
    END
  END o[345]
  PIN o[346]
    DIRECTION OUTPUT ;
    USE SIGNAL ;
    PORT
      LAYER M4 ;
        RECT  0 61.008 0.192 61.032 ;
    END
  END o[346]
  PIN o[347]
    DIRECTION OUTPUT ;
    USE SIGNAL ;
    PORT
      LAYER M4 ;
        RECT  0 61.152 0.192 61.176 ;
    END
  END o[347]
  PIN o[348]
    DIRECTION OUTPUT ;
    USE SIGNAL ;
    PORT
      LAYER M4 ;
        RECT  0 61.344 0.192 61.368 ;
    END
  END o[348]
  PIN o[349]
    DIRECTION OUTPUT ;
    USE SIGNAL ;
    PORT
      LAYER M4 ;
        RECT  0 61.488 0.192 61.512 ;
    END
  END o[349]
  PIN o[34]
    DIRECTION OUTPUT ;
    USE SIGNAL ;
    PORT
      LAYER M4 ;
        RECT  0 9.984 0.192 10.008 ;
    END
  END o[34]
  PIN o[350]
    DIRECTION OUTPUT ;
    USE SIGNAL ;
    PORT
      LAYER M4 ;
        RECT  0 61.68 0.192 61.704 ;
    END
  END o[350]
  PIN o[351]
    DIRECTION OUTPUT ;
    USE SIGNAL ;
    PORT
      LAYER M4 ;
        RECT  0 61.824 0.192 61.848 ;
    END
  END o[351]
  PIN o[352]
    DIRECTION OUTPUT ;
    USE SIGNAL ;
    PORT
      LAYER M4 ;
        RECT  0 61.968 0.192 61.992 ;
    END
  END o[352]
  PIN o[353]
    DIRECTION OUTPUT ;
    USE SIGNAL ;
    PORT
      LAYER M4 ;
        RECT  0 62.16 0.192 62.184 ;
    END
  END o[353]
  PIN o[354]
    DIRECTION OUTPUT ;
    USE SIGNAL ;
    PORT
      LAYER M4 ;
        RECT  0 62.304 0.192 62.328 ;
    END
  END o[354]
  PIN o[355]
    DIRECTION OUTPUT ;
    USE SIGNAL ;
    PORT
      LAYER M4 ;
        RECT  0 62.496 0.192 62.52 ;
    END
  END o[355]
  PIN o[356]
    DIRECTION OUTPUT ;
    USE SIGNAL ;
    PORT
      LAYER M4 ;
        RECT  0 62.64 0.192 62.664 ;
    END
  END o[356]
  PIN o[357]
    DIRECTION OUTPUT ;
    USE SIGNAL ;
    PORT
      LAYER M4 ;
        RECT  0 62.832 0.192 62.856 ;
    END
  END o[357]
  PIN o[358]
    DIRECTION OUTPUT ;
    USE SIGNAL ;
    PORT
      LAYER M4 ;
        RECT  0 62.976 0.192 63 ;
    END
  END o[358]
  PIN o[359]
    DIRECTION OUTPUT ;
    USE SIGNAL ;
    PORT
      LAYER M4 ;
        RECT  0 63.12 0.192 63.144 ;
    END
  END o[359]
  PIN o[35]
    DIRECTION OUTPUT ;
    USE SIGNAL ;
    PORT
      LAYER M4 ;
        RECT  0 10.128 0.192 10.152 ;
    END
  END o[35]
  PIN o[360]
    DIRECTION OUTPUT ;
    USE SIGNAL ;
    PORT
      LAYER M4 ;
        RECT  0 63.312 0.192 63.336 ;
    END
  END o[360]
  PIN o[361]
    DIRECTION OUTPUT ;
    USE SIGNAL ;
    PORT
      LAYER M4 ;
        RECT  0 63.456 0.192 63.48 ;
    END
  END o[361]
  PIN o[362]
    DIRECTION OUTPUT ;
    USE SIGNAL ;
    PORT
      LAYER M4 ;
        RECT  0 63.648 0.192 63.672 ;
    END
  END o[362]
  PIN o[363]
    DIRECTION OUTPUT ;
    USE SIGNAL ;
    PORT
      LAYER M4 ;
        RECT  0 63.792 0.192 63.816 ;
    END
  END o[363]
  PIN o[364]
    DIRECTION OUTPUT ;
    USE SIGNAL ;
    PORT
      LAYER M4 ;
        RECT  0 63.936 0.192 63.96 ;
    END
  END o[364]
  PIN o[365]
    DIRECTION OUTPUT ;
    USE SIGNAL ;
    PORT
      LAYER M4 ;
        RECT  0 64.128 0.192 64.152 ;
    END
  END o[365]
  PIN o[366]
    DIRECTION OUTPUT ;
    USE SIGNAL ;
    PORT
      LAYER M4 ;
        RECT  0 64.272 0.192 64.296 ;
    END
  END o[366]
  PIN o[367]
    DIRECTION OUTPUT ;
    USE SIGNAL ;
    PORT
      LAYER M4 ;
        RECT  0 64.464 0.192 64.488 ;
    END
  END o[367]
  PIN o[368]
    DIRECTION OUTPUT ;
    USE SIGNAL ;
    PORT
      LAYER M4 ;
        RECT  0 64.608 0.192 64.632 ;
    END
  END o[368]
  PIN o[369]
    DIRECTION OUTPUT ;
    USE SIGNAL ;
    PORT
      LAYER M4 ;
        RECT  0 64.752 0.192 64.776 ;
    END
  END o[369]
  PIN o[36]
    DIRECTION OUTPUT ;
    USE SIGNAL ;
    PORT
      LAYER M4 ;
        RECT  0 10.32 0.192 10.344 ;
    END
  END o[36]
  PIN o[370]
    DIRECTION OUTPUT ;
    USE SIGNAL ;
    PORT
      LAYER M4 ;
        RECT  0 64.944 0.192 64.968 ;
    END
  END o[370]
  PIN o[371]
    DIRECTION OUTPUT ;
    USE SIGNAL ;
    PORT
      LAYER M4 ;
        RECT  0 65.088 0.192 65.112 ;
    END
  END o[371]
  PIN o[372]
    DIRECTION OUTPUT ;
    USE SIGNAL ;
    PORT
      LAYER M4 ;
        RECT  0 65.28 0.192 65.304 ;
    END
  END o[372]
  PIN o[373]
    DIRECTION OUTPUT ;
    USE SIGNAL ;
    PORT
      LAYER M4 ;
        RECT  0 65.424 0.192 65.448 ;
    END
  END o[373]
  PIN o[374]
    DIRECTION OUTPUT ;
    USE SIGNAL ;
    PORT
      LAYER M4 ;
        RECT  0 65.568 0.192 65.592 ;
    END
  END o[374]
  PIN o[375]
    DIRECTION OUTPUT ;
    USE SIGNAL ;
    PORT
      LAYER M4 ;
        RECT  0 65.76 0.192 65.784 ;
    END
  END o[375]
  PIN o[376]
    DIRECTION OUTPUT ;
    USE SIGNAL ;
    PORT
      LAYER M4 ;
        RECT  0 65.904 0.192 65.928 ;
    END
  END o[376]
  PIN o[377]
    DIRECTION OUTPUT ;
    USE SIGNAL ;
    PORT
      LAYER M4 ;
        RECT  0 66.096 0.192 66.12 ;
    END
  END o[377]
  PIN o[378]
    DIRECTION OUTPUT ;
    USE SIGNAL ;
    PORT
      LAYER M4 ;
        RECT  0 66.24 0.192 66.264 ;
    END
  END o[378]
  PIN o[379]
    DIRECTION OUTPUT ;
    USE SIGNAL ;
    PORT
      LAYER M4 ;
        RECT  0 66.384 0.192 66.408 ;
    END
  END o[379]
  PIN o[37]
    DIRECTION OUTPUT ;
    USE SIGNAL ;
    PORT
      LAYER M4 ;
        RECT  0 10.464 0.192 10.488 ;
    END
  END o[37]
  PIN o[380]
    DIRECTION OUTPUT ;
    USE SIGNAL ;
    PORT
      LAYER M4 ;
        RECT  0 66.576 0.192 66.6 ;
    END
  END o[380]
  PIN o[381]
    DIRECTION OUTPUT ;
    USE SIGNAL ;
    PORT
      LAYER M4 ;
        RECT  0 66.72 0.192 66.744 ;
    END
  END o[381]
  PIN o[382]
    DIRECTION OUTPUT ;
    USE SIGNAL ;
    PORT
      LAYER M4 ;
        RECT  0 66.912 0.192 66.936 ;
    END
  END o[382]
  PIN o[383]
    DIRECTION OUTPUT ;
    USE SIGNAL ;
    PORT
      LAYER M4 ;
        RECT  0 67.056 0.192 67.08 ;
    END
  END o[383]
  PIN o[384]
    DIRECTION OUTPUT ;
    USE SIGNAL ;
    PORT
      LAYER M4 ;
        RECT  0 67.248 0.192 67.272 ;
    END
  END o[384]
  PIN o[385]
    DIRECTION OUTPUT ;
    USE SIGNAL ;
    PORT
      LAYER M4 ;
        RECT  0 67.392 0.192 67.416 ;
    END
  END o[385]
  PIN o[386]
    DIRECTION OUTPUT ;
    USE SIGNAL ;
    PORT
      LAYER M4 ;
        RECT  0 67.536 0.192 67.56 ;
    END
  END o[386]
  PIN o[387]
    DIRECTION OUTPUT ;
    USE SIGNAL ;
    PORT
      LAYER M4 ;
        RECT  0 67.728 0.192 67.752 ;
    END
  END o[387]
  PIN o[388]
    DIRECTION OUTPUT ;
    USE SIGNAL ;
    PORT
      LAYER M4 ;
        RECT  0 67.872 0.192 67.896 ;
    END
  END o[388]
  PIN o[389]
    DIRECTION OUTPUT ;
    USE SIGNAL ;
    PORT
      LAYER M4 ;
        RECT  0 68.064 0.192 68.088 ;
    END
  END o[389]
  PIN o[38]
    DIRECTION OUTPUT ;
    USE SIGNAL ;
    PORT
      LAYER M4 ;
        RECT  0 10.608 0.192 10.632 ;
    END
  END o[38]
  PIN o[390]
    DIRECTION OUTPUT ;
    USE SIGNAL ;
    PORT
      LAYER M4 ;
        RECT  0 68.208 0.192 68.232 ;
    END
  END o[390]
  PIN o[391]
    DIRECTION OUTPUT ;
    USE SIGNAL ;
    PORT
      LAYER M4 ;
        RECT  0 68.352 0.192 68.376 ;
    END
  END o[391]
  PIN o[392]
    DIRECTION OUTPUT ;
    USE SIGNAL ;
    PORT
      LAYER M4 ;
        RECT  0 68.544 0.192 68.568 ;
    END
  END o[392]
  PIN o[393]
    DIRECTION OUTPUT ;
    USE SIGNAL ;
    PORT
      LAYER M4 ;
        RECT  0 68.688 0.192 68.712 ;
    END
  END o[393]
  PIN o[394]
    DIRECTION OUTPUT ;
    USE SIGNAL ;
    PORT
      LAYER M4 ;
        RECT  0 68.88 0.192 68.904 ;
    END
  END o[394]
  PIN o[395]
    DIRECTION OUTPUT ;
    USE SIGNAL ;
    PORT
      LAYER M4 ;
        RECT  0 69.024 0.192 69.048 ;
    END
  END o[395]
  PIN o[396]
    DIRECTION OUTPUT ;
    USE SIGNAL ;
    PORT
      LAYER M4 ;
        RECT  0 69.168 0.192 69.192 ;
    END
  END o[396]
  PIN o[397]
    DIRECTION OUTPUT ;
    USE SIGNAL ;
    PORT
      LAYER M4 ;
        RECT  0 69.36 0.192 69.384 ;
    END
  END o[397]
  PIN o[398]
    DIRECTION OUTPUT ;
    USE SIGNAL ;
    PORT
      LAYER M4 ;
        RECT  0 69.504 0.192 69.528 ;
    END
  END o[398]
  PIN o[399]
    DIRECTION OUTPUT ;
    USE SIGNAL ;
    PORT
      LAYER M4 ;
        RECT  0 69.696 0.192 69.72 ;
    END
  END o[399]
  PIN o[39]
    DIRECTION OUTPUT ;
    USE SIGNAL ;
    PORT
      LAYER M4 ;
        RECT  0 10.8 0.192 10.824 ;
    END
  END o[39]
  PIN o[3]
    DIRECTION OUTPUT ;
    USE SIGNAL ;
    PORT
      LAYER M4 ;
        RECT  0 4.896 0.192 4.92 ;
    END
  END o[3]
  PIN o[400]
    DIRECTION OUTPUT ;
    USE SIGNAL ;
    PORT
      LAYER M4 ;
        RECT  0 69.84 0.192 69.864 ;
    END
  END o[400]
  PIN o[401]
    DIRECTION OUTPUT ;
    USE SIGNAL ;
    PORT
      LAYER M4 ;
        RECT  0 69.984 0.192 70.008 ;
    END
  END o[401]
  PIN o[402]
    DIRECTION OUTPUT ;
    USE SIGNAL ;
    PORT
      LAYER M4 ;
        RECT  0 70.176 0.192 70.2 ;
    END
  END o[402]
  PIN o[403]
    DIRECTION OUTPUT ;
    USE SIGNAL ;
    PORT
      LAYER M4 ;
        RECT  0 70.32 0.192 70.344 ;
    END
  END o[403]
  PIN o[404]
    DIRECTION OUTPUT ;
    USE SIGNAL ;
    PORT
      LAYER M4 ;
        RECT  0 70.512 0.192 70.536 ;
    END
  END o[404]
  PIN o[405]
    DIRECTION OUTPUT ;
    USE SIGNAL ;
    PORT
      LAYER M4 ;
        RECT  0 70.656 0.192 70.68 ;
    END
  END o[405]
  PIN o[406]
    DIRECTION OUTPUT ;
    USE SIGNAL ;
    PORT
      LAYER M4 ;
        RECT  0 70.848 0.192 70.872 ;
    END
  END o[406]
  PIN o[407]
    DIRECTION OUTPUT ;
    USE SIGNAL ;
    PORT
      LAYER M4 ;
        RECT  0 70.992 0.192 71.016 ;
    END
  END o[407]
  PIN o[408]
    DIRECTION OUTPUT ;
    USE SIGNAL ;
    PORT
      LAYER M4 ;
        RECT  0 71.136 0.192 71.16 ;
    END
  END o[408]
  PIN o[409]
    DIRECTION OUTPUT ;
    USE SIGNAL ;
    PORT
      LAYER M4 ;
        RECT  0 71.328 0.192 71.352 ;
    END
  END o[409]
  PIN o[40]
    DIRECTION OUTPUT ;
    USE SIGNAL ;
    PORT
      LAYER M4 ;
        RECT  0 10.944 0.192 10.968 ;
    END
  END o[40]
  PIN o[410]
    DIRECTION OUTPUT ;
    USE SIGNAL ;
    PORT
      LAYER M4 ;
        RECT  0 71.472 0.192 71.496 ;
    END
  END o[410]
  PIN o[411]
    DIRECTION OUTPUT ;
    USE SIGNAL ;
    PORT
      LAYER M4 ;
        RECT  0 71.664 0.192 71.688 ;
    END
  END o[411]
  PIN o[412]
    DIRECTION OUTPUT ;
    USE SIGNAL ;
    PORT
      LAYER M4 ;
        RECT  0 71.808 0.192 71.832 ;
    END
  END o[412]
  PIN o[413]
    DIRECTION OUTPUT ;
    USE SIGNAL ;
    PORT
      LAYER M4 ;
        RECT  0 71.952 0.192 71.976 ;
    END
  END o[413]
  PIN o[414]
    DIRECTION OUTPUT ;
    USE SIGNAL ;
    PORT
      LAYER M4 ;
        RECT  0 72.144 0.192 72.168 ;
    END
  END o[414]
  PIN o[415]
    DIRECTION OUTPUT ;
    USE SIGNAL ;
    PORT
      LAYER M4 ;
        RECT  0 72.288 0.192 72.312 ;
    END
  END o[415]
  PIN o[416]
    DIRECTION OUTPUT ;
    USE SIGNAL ;
    PORT
      LAYER M4 ;
        RECT  0 72.48 0.192 72.504 ;
    END
  END o[416]
  PIN o[417]
    DIRECTION OUTPUT ;
    USE SIGNAL ;
    PORT
      LAYER M4 ;
        RECT  0 72.624 0.192 72.648 ;
    END
  END o[417]
  PIN o[418]
    DIRECTION OUTPUT ;
    USE SIGNAL ;
    PORT
      LAYER M4 ;
        RECT  0 72.768 0.192 72.792 ;
    END
  END o[418]
  PIN o[419]
    DIRECTION OUTPUT ;
    USE SIGNAL ;
    PORT
      LAYER M4 ;
        RECT  0 72.96 0.192 72.984 ;
    END
  END o[419]
  PIN o[41]
    DIRECTION OUTPUT ;
    USE SIGNAL ;
    PORT
      LAYER M4 ;
        RECT  0 11.136 0.192 11.16 ;
    END
  END o[41]
  PIN o[420]
    DIRECTION OUTPUT ;
    USE SIGNAL ;
    PORT
      LAYER M4 ;
        RECT  0 73.104 0.192 73.128 ;
    END
  END o[420]
  PIN o[421]
    DIRECTION OUTPUT ;
    USE SIGNAL ;
    PORT
      LAYER M4 ;
        RECT  0 73.296 0.192 73.32 ;
    END
  END o[421]
  PIN o[422]
    DIRECTION OUTPUT ;
    USE SIGNAL ;
    PORT
      LAYER M4 ;
        RECT  0 73.44 0.192 73.464 ;
    END
  END o[422]
  PIN o[423]
    DIRECTION OUTPUT ;
    USE SIGNAL ;
    PORT
      LAYER M4 ;
        RECT  0 73.584 0.192 73.608 ;
    END
  END o[423]
  PIN o[424]
    DIRECTION OUTPUT ;
    USE SIGNAL ;
    PORT
      LAYER M4 ;
        RECT  0 73.776 0.192 73.8 ;
    END
  END o[424]
  PIN o[425]
    DIRECTION OUTPUT ;
    USE SIGNAL ;
    PORT
      LAYER M4 ;
        RECT  0 73.92 0.192 73.944 ;
    END
  END o[425]
  PIN o[426]
    DIRECTION OUTPUT ;
    USE SIGNAL ;
    PORT
      LAYER M4 ;
        RECT  0 74.112 0.192 74.136 ;
    END
  END o[426]
  PIN o[427]
    DIRECTION OUTPUT ;
    USE SIGNAL ;
    PORT
      LAYER M4 ;
        RECT  0 74.256 0.192 74.28 ;
    END
  END o[427]
  PIN o[428]
    DIRECTION OUTPUT ;
    USE SIGNAL ;
    PORT
      LAYER M4 ;
        RECT  0 74.4 0.192 74.424 ;
    END
  END o[428]
  PIN o[429]
    DIRECTION OUTPUT ;
    USE SIGNAL ;
    PORT
      LAYER M4 ;
        RECT  0 74.592 0.192 74.616 ;
    END
  END o[429]
  PIN o[42]
    DIRECTION OUTPUT ;
    USE SIGNAL ;
    PORT
      LAYER M4 ;
        RECT  0 11.28 0.192 11.304 ;
    END
  END o[42]
  PIN o[430]
    DIRECTION OUTPUT ;
    USE SIGNAL ;
    PORT
      LAYER M4 ;
        RECT  0 74.736 0.192 74.76 ;
    END
  END o[430]
  PIN o[431]
    DIRECTION OUTPUT ;
    USE SIGNAL ;
    PORT
      LAYER M4 ;
        RECT  0 74.928 0.192 74.952 ;
    END
  END o[431]
  PIN o[432]
    DIRECTION OUTPUT ;
    USE SIGNAL ;
    PORT
      LAYER M4 ;
        RECT  0 75.072 0.192 75.096 ;
    END
  END o[432]
  PIN o[433]
    DIRECTION OUTPUT ;
    USE SIGNAL ;
    PORT
      LAYER M4 ;
        RECT  0 75.264 0.192 75.288 ;
    END
  END o[433]
  PIN o[434]
    DIRECTION OUTPUT ;
    USE SIGNAL ;
    PORT
      LAYER M4 ;
        RECT  0 75.408 0.192 75.432 ;
    END
  END o[434]
  PIN o[435]
    DIRECTION OUTPUT ;
    USE SIGNAL ;
    PORT
      LAYER M4 ;
        RECT  0 75.552 0.192 75.576 ;
    END
  END o[435]
  PIN o[436]
    DIRECTION OUTPUT ;
    USE SIGNAL ;
    PORT
      LAYER M4 ;
        RECT  0 75.744 0.192 75.768 ;
    END
  END o[436]
  PIN o[437]
    DIRECTION OUTPUT ;
    USE SIGNAL ;
    PORT
      LAYER M4 ;
        RECT  0 75.888 0.192 75.912 ;
    END
  END o[437]
  PIN o[438]
    DIRECTION OUTPUT ;
    USE SIGNAL ;
    PORT
      LAYER M4 ;
        RECT  0 76.08 0.192 76.104 ;
    END
  END o[438]
  PIN o[439]
    DIRECTION OUTPUT ;
    USE SIGNAL ;
    PORT
      LAYER M4 ;
        RECT  0 76.224 0.192 76.248 ;
    END
  END o[439]
  PIN o[43]
    DIRECTION OUTPUT ;
    USE SIGNAL ;
    PORT
      LAYER M4 ;
        RECT  0 11.424 0.192 11.448 ;
    END
  END o[43]
  PIN o[440]
    DIRECTION OUTPUT ;
    USE SIGNAL ;
    PORT
      LAYER M4 ;
        RECT  0 76.368 0.192 76.392 ;
    END
  END o[440]
  PIN o[441]
    DIRECTION OUTPUT ;
    USE SIGNAL ;
    PORT
      LAYER M4 ;
        RECT  0 76.56 0.192 76.584 ;
    END
  END o[441]
  PIN o[442]
    DIRECTION OUTPUT ;
    USE SIGNAL ;
    PORT
      LAYER M4 ;
        RECT  0 76.704 0.192 76.728 ;
    END
  END o[442]
  PIN o[443]
    DIRECTION OUTPUT ;
    USE SIGNAL ;
    PORT
      LAYER M4 ;
        RECT  0 76.896 0.192 76.92 ;
    END
  END o[443]
  PIN o[444]
    DIRECTION OUTPUT ;
    USE SIGNAL ;
    PORT
      LAYER M4 ;
        RECT  0 77.04 0.192 77.064 ;
    END
  END o[444]
  PIN o[445]
    DIRECTION OUTPUT ;
    USE SIGNAL ;
    PORT
      LAYER M4 ;
        RECT  0 77.184 0.192 77.208 ;
    END
  END o[445]
  PIN o[446]
    DIRECTION OUTPUT ;
    USE SIGNAL ;
    PORT
      LAYER M4 ;
        RECT  0 77.376 0.192 77.4 ;
    END
  END o[446]
  PIN o[447]
    DIRECTION OUTPUT ;
    USE SIGNAL ;
    PORT
      LAYER M4 ;
        RECT  0 77.52 0.192 77.544 ;
    END
  END o[447]
  PIN o[448]
    DIRECTION OUTPUT ;
    USE SIGNAL ;
    PORT
      LAYER M4 ;
        RECT  0 77.712 0.192 77.736 ;
    END
  END o[448]
  PIN o[449]
    DIRECTION OUTPUT ;
    USE SIGNAL ;
    PORT
      LAYER M4 ;
        RECT  0 77.856 0.192 77.88 ;
    END
  END o[449]
  PIN o[44]
    DIRECTION OUTPUT ;
    USE SIGNAL ;
    PORT
      LAYER M4 ;
        RECT  0 11.616 0.192 11.64 ;
    END
  END o[44]
  PIN o[450]
    DIRECTION OUTPUT ;
    USE SIGNAL ;
    PORT
      LAYER M4 ;
        RECT  0 78 0.192 78.024 ;
    END
  END o[450]
  PIN o[451]
    DIRECTION OUTPUT ;
    USE SIGNAL ;
    PORT
      LAYER M4 ;
        RECT  0 78.192 0.192 78.216 ;
    END
  END o[451]
  PIN o[452]
    DIRECTION OUTPUT ;
    USE SIGNAL ;
    PORT
      LAYER M4 ;
        RECT  0 78.336 0.192 78.36 ;
    END
  END o[452]
  PIN o[453]
    DIRECTION OUTPUT ;
    USE SIGNAL ;
    PORT
      LAYER M4 ;
        RECT  0 78.528 0.192 78.552 ;
    END
  END o[453]
  PIN o[454]
    DIRECTION OUTPUT ;
    USE SIGNAL ;
    PORT
      LAYER M4 ;
        RECT  0 78.672 0.192 78.696 ;
    END
  END o[454]
  PIN o[455]
    DIRECTION OUTPUT ;
    USE SIGNAL ;
    PORT
      LAYER M4 ;
        RECT  0 78.816 0.192 78.84 ;
    END
  END o[455]
  PIN o[456]
    DIRECTION OUTPUT ;
    USE SIGNAL ;
    PORT
      LAYER M4 ;
        RECT  0 79.008 0.192 79.032 ;
    END
  END o[456]
  PIN o[457]
    DIRECTION OUTPUT ;
    USE SIGNAL ;
    PORT
      LAYER M4 ;
        RECT  0 79.152 0.192 79.176 ;
    END
  END o[457]
  PIN o[458]
    DIRECTION OUTPUT ;
    USE SIGNAL ;
    PORT
      LAYER M4 ;
        RECT  0 79.344 0.192 79.368 ;
    END
  END o[458]
  PIN o[459]
    DIRECTION OUTPUT ;
    USE SIGNAL ;
    PORT
      LAYER M4 ;
        RECT  0 79.488 0.192 79.512 ;
    END
  END o[459]
  PIN o[45]
    DIRECTION OUTPUT ;
    USE SIGNAL ;
    PORT
      LAYER M4 ;
        RECT  0 11.76 0.192 11.784 ;
    END
  END o[45]
  PIN o[460]
    DIRECTION OUTPUT ;
    USE SIGNAL ;
    PORT
      LAYER M4 ;
        RECT  0 79.68 0.192 79.704 ;
    END
  END o[460]
  PIN o[461]
    DIRECTION OUTPUT ;
    USE SIGNAL ;
    PORT
      LAYER M4 ;
        RECT  0 79.824 0.192 79.848 ;
    END
  END o[461]
  PIN o[462]
    DIRECTION OUTPUT ;
    USE SIGNAL ;
    PORT
      LAYER M4 ;
        RECT  0 79.968 0.192 79.992 ;
    END
  END o[462]
  PIN o[463]
    DIRECTION OUTPUT ;
    USE SIGNAL ;
    PORT
      LAYER M4 ;
        RECT  0 80.16 0.192 80.184 ;
    END
  END o[463]
  PIN o[464]
    DIRECTION OUTPUT ;
    USE SIGNAL ;
    PORT
      LAYER M4 ;
        RECT  0 80.304 0.192 80.328 ;
    END
  END o[464]
  PIN o[465]
    DIRECTION OUTPUT ;
    USE SIGNAL ;
    PORT
      LAYER M4 ;
        RECT  0 80.496 0.192 80.52 ;
    END
  END o[465]
  PIN o[466]
    DIRECTION OUTPUT ;
    USE SIGNAL ;
    PORT
      LAYER M4 ;
        RECT  0 80.64 0.192 80.664 ;
    END
  END o[466]
  PIN o[467]
    DIRECTION OUTPUT ;
    USE SIGNAL ;
    PORT
      LAYER M4 ;
        RECT  0 80.784 0.192 80.808 ;
    END
  END o[467]
  PIN o[468]
    DIRECTION OUTPUT ;
    USE SIGNAL ;
    PORT
      LAYER M4 ;
        RECT  0 80.976 0.192 81 ;
    END
  END o[468]
  PIN o[469]
    DIRECTION OUTPUT ;
    USE SIGNAL ;
    PORT
      LAYER M4 ;
        RECT  0 81.12 0.192 81.144 ;
    END
  END o[469]
  PIN o[46]
    DIRECTION OUTPUT ;
    USE SIGNAL ;
    PORT
      LAYER M4 ;
        RECT  0 11.952 0.192 11.976 ;
    END
  END o[46]
  PIN o[470]
    DIRECTION OUTPUT ;
    USE SIGNAL ;
    PORT
      LAYER M4 ;
        RECT  0 81.312 0.192 81.336 ;
    END
  END o[470]
  PIN o[471]
    DIRECTION OUTPUT ;
    USE SIGNAL ;
    PORT
      LAYER M4 ;
        RECT  0 81.456 0.192 81.48 ;
    END
  END o[471]
  PIN o[472]
    DIRECTION OUTPUT ;
    USE SIGNAL ;
    PORT
      LAYER M4 ;
        RECT  0 81.6 0.192 81.624 ;
    END
  END o[472]
  PIN o[473]
    DIRECTION OUTPUT ;
    USE SIGNAL ;
    PORT
      LAYER M4 ;
        RECT  0 81.792 0.192 81.816 ;
    END
  END o[473]
  PIN o[474]
    DIRECTION OUTPUT ;
    USE SIGNAL ;
    PORT
      LAYER M4 ;
        RECT  0 81.936 0.192 81.96 ;
    END
  END o[474]
  PIN o[475]
    DIRECTION OUTPUT ;
    USE SIGNAL ;
    PORT
      LAYER M4 ;
        RECT  0 82.128 0.192 82.152 ;
    END
  END o[475]
  PIN o[476]
    DIRECTION OUTPUT ;
    USE SIGNAL ;
    PORT
      LAYER M4 ;
        RECT  0 82.272 0.192 82.296 ;
    END
  END o[476]
  PIN o[477]
    DIRECTION OUTPUT ;
    USE SIGNAL ;
    PORT
      LAYER M4 ;
        RECT  0 82.416 0.192 82.44 ;
    END
  END o[477]
  PIN o[478]
    DIRECTION OUTPUT ;
    USE SIGNAL ;
    PORT
      LAYER M4 ;
        RECT  0 82.608 0.192 82.632 ;
    END
  END o[478]
  PIN o[479]
    DIRECTION OUTPUT ;
    USE SIGNAL ;
    PORT
      LAYER M4 ;
        RECT  0 82.752 0.192 82.776 ;
    END
  END o[479]
  PIN o[47]
    DIRECTION OUTPUT ;
    USE SIGNAL ;
    PORT
      LAYER M4 ;
        RECT  0 12.096 0.192 12.12 ;
    END
  END o[47]
  PIN o[480]
    DIRECTION OUTPUT ;
    USE SIGNAL ;
    PORT
      LAYER M4 ;
        RECT  0 82.944 0.192 82.968 ;
    END
  END o[480]
  PIN o[481]
    DIRECTION OUTPUT ;
    USE SIGNAL ;
    PORT
      LAYER M4 ;
        RECT  0 83.088 0.192 83.112 ;
    END
  END o[481]
  PIN o[482]
    DIRECTION OUTPUT ;
    USE SIGNAL ;
    PORT
      LAYER M4 ;
        RECT  0 83.232 0.192 83.256 ;
    END
  END o[482]
  PIN o[483]
    DIRECTION OUTPUT ;
    USE SIGNAL ;
    PORT
      LAYER M4 ;
        RECT  0 83.424 0.192 83.448 ;
    END
  END o[483]
  PIN o[484]
    DIRECTION OUTPUT ;
    USE SIGNAL ;
    PORT
      LAYER M4 ;
        RECT  0 83.568 0.192 83.592 ;
    END
  END o[484]
  PIN o[485]
    DIRECTION OUTPUT ;
    USE SIGNAL ;
    PORT
      LAYER M4 ;
        RECT  0 83.76 0.192 83.784 ;
    END
  END o[485]
  PIN o[486]
    DIRECTION OUTPUT ;
    USE SIGNAL ;
    PORT
      LAYER M4 ;
        RECT  0 83.904 0.192 83.928 ;
    END
  END o[486]
  PIN o[487]
    DIRECTION OUTPUT ;
    USE SIGNAL ;
    PORT
      LAYER M4 ;
        RECT  0 84.096 0.192 84.12 ;
    END
  END o[487]
  PIN o[488]
    DIRECTION OUTPUT ;
    USE SIGNAL ;
    PORT
      LAYER M4 ;
        RECT  0 84.24 0.192 84.264 ;
    END
  END o[488]
  PIN o[489]
    DIRECTION OUTPUT ;
    USE SIGNAL ;
    PORT
      LAYER M4 ;
        RECT  0 84.384 0.192 84.408 ;
    END
  END o[489]
  PIN o[48]
    DIRECTION OUTPUT ;
    USE SIGNAL ;
    PORT
      LAYER M4 ;
        RECT  0 12.288 0.192 12.312 ;
    END
  END o[48]
  PIN o[490]
    DIRECTION OUTPUT ;
    USE SIGNAL ;
    PORT
      LAYER M4 ;
        RECT  0 84.576 0.192 84.6 ;
    END
  END o[490]
  PIN o[491]
    DIRECTION OUTPUT ;
    USE SIGNAL ;
    PORT
      LAYER M4 ;
        RECT  0 84.72 0.192 84.744 ;
    END
  END o[491]
  PIN o[492]
    DIRECTION OUTPUT ;
    USE SIGNAL ;
    PORT
      LAYER M4 ;
        RECT  0 84.912 0.192 84.936 ;
    END
  END o[492]
  PIN o[493]
    DIRECTION OUTPUT ;
    USE SIGNAL ;
    PORT
      LAYER M4 ;
        RECT  0 85.056 0.192 85.08 ;
    END
  END o[493]
  PIN o[494]
    DIRECTION OUTPUT ;
    USE SIGNAL ;
    PORT
      LAYER M4 ;
        RECT  0 85.2 0.192 85.224 ;
    END
  END o[494]
  PIN o[495]
    DIRECTION OUTPUT ;
    USE SIGNAL ;
    PORT
      LAYER M4 ;
        RECT  0 85.392 0.192 85.416 ;
    END
  END o[495]
  PIN o[496]
    DIRECTION OUTPUT ;
    USE SIGNAL ;
    PORT
      LAYER M4 ;
        RECT  0 85.536 0.192 85.56 ;
    END
  END o[496]
  PIN o[497]
    DIRECTION OUTPUT ;
    USE SIGNAL ;
    PORT
      LAYER M4 ;
        RECT  0 85.728 0.192 85.752 ;
    END
  END o[497]
  PIN o[498]
    DIRECTION OUTPUT ;
    USE SIGNAL ;
    PORT
      LAYER M4 ;
        RECT  0 85.872 0.192 85.896 ;
    END
  END o[498]
  PIN o[499]
    DIRECTION OUTPUT ;
    USE SIGNAL ;
    PORT
      LAYER M4 ;
        RECT  0 86.016 0.192 86.04 ;
    END
  END o[499]
  PIN o[49]
    DIRECTION OUTPUT ;
    USE SIGNAL ;
    PORT
      LAYER M4 ;
        RECT  0 12.432 0.192 12.456 ;
    END
  END o[49]
  PIN o[4]
    DIRECTION OUTPUT ;
    USE SIGNAL ;
    PORT
      LAYER M4 ;
        RECT  0 5.088 0.192 5.112 ;
    END
  END o[4]
  PIN o[500]
    DIRECTION OUTPUT ;
    USE SIGNAL ;
    PORT
      LAYER M4 ;
        RECT  0 86.208 0.192 86.232 ;
    END
  END o[500]
  PIN o[501]
    DIRECTION OUTPUT ;
    USE SIGNAL ;
    PORT
      LAYER M4 ;
        RECT  0 86.352 0.192 86.376 ;
    END
  END o[501]
  PIN o[502]
    DIRECTION OUTPUT ;
    USE SIGNAL ;
    PORT
      LAYER M4 ;
        RECT  0 86.544 0.192 86.568 ;
    END
  END o[502]
  PIN o[503]
    DIRECTION OUTPUT ;
    USE SIGNAL ;
    PORT
      LAYER M4 ;
        RECT  0 86.688 0.192 86.712 ;
    END
  END o[503]
  PIN o[504]
    DIRECTION OUTPUT ;
    USE SIGNAL ;
    PORT
      LAYER M4 ;
        RECT  0 86.832 0.192 86.856 ;
    END
  END o[504]
  PIN o[505]
    DIRECTION OUTPUT ;
    USE SIGNAL ;
    PORT
      LAYER M4 ;
        RECT  0 87.024 0.192 87.048 ;
    END
  END o[505]
  PIN o[506]
    DIRECTION OUTPUT ;
    USE SIGNAL ;
    PORT
      LAYER M4 ;
        RECT  0 87.168 0.192 87.192 ;
    END
  END o[506]
  PIN o[507]
    DIRECTION OUTPUT ;
    USE SIGNAL ;
    PORT
      LAYER M4 ;
        RECT  0 87.36 0.192 87.384 ;
    END
  END o[507]
  PIN o[508]
    DIRECTION OUTPUT ;
    USE SIGNAL ;
    PORT
      LAYER M4 ;
        RECT  0 87.504 0.192 87.528 ;
    END
  END o[508]
  PIN o[509]
    DIRECTION OUTPUT ;
    USE SIGNAL ;
    PORT
      LAYER M4 ;
        RECT  0 87.696 0.192 87.72 ;
    END
  END o[509]
  PIN o[50]
    DIRECTION OUTPUT ;
    USE SIGNAL ;
    PORT
      LAYER M4 ;
        RECT  0 12.576 0.192 12.6 ;
    END
  END o[50]
  PIN o[510]
    DIRECTION OUTPUT ;
    USE SIGNAL ;
    PORT
      LAYER M4 ;
        RECT  0 87.84 0.192 87.864 ;
    END
  END o[510]
  PIN o[511]
    DIRECTION OUTPUT ;
    USE SIGNAL ;
    PORT
      LAYER M4 ;
        RECT  0 87.984 0.192 88.008 ;
    END
  END o[511]
  PIN o[512]
    DIRECTION OUTPUT ;
    USE SIGNAL ;
    PORT
      LAYER M4 ;
        RECT  0 88.176 0.192 88.2 ;
    END
  END o[512]
  PIN o[513]
    DIRECTION OUTPUT ;
    USE SIGNAL ;
    PORT
      LAYER M4 ;
        RECT  0 88.32 0.192 88.344 ;
    END
  END o[513]
  PIN o[514]
    DIRECTION OUTPUT ;
    USE SIGNAL ;
    PORT
      LAYER M4 ;
        RECT  0 88.512 0.192 88.536 ;
    END
  END o[514]
  PIN o[51]
    DIRECTION OUTPUT ;
    USE SIGNAL ;
    PORT
      LAYER M4 ;
        RECT  0 12.768 0.192 12.792 ;
    END
  END o[51]
  PIN o[52]
    DIRECTION OUTPUT ;
    USE SIGNAL ;
    PORT
      LAYER M4 ;
        RECT  0 12.912 0.192 12.936 ;
    END
  END o[52]
  PIN o[53]
    DIRECTION OUTPUT ;
    USE SIGNAL ;
    PORT
      LAYER M4 ;
        RECT  0 13.104 0.192 13.128 ;
    END
  END o[53]
  PIN o[54]
    DIRECTION OUTPUT ;
    USE SIGNAL ;
    PORT
      LAYER M4 ;
        RECT  0 13.248 0.192 13.272 ;
    END
  END o[54]
  PIN o[55]
    DIRECTION OUTPUT ;
    USE SIGNAL ;
    PORT
      LAYER M4 ;
        RECT  0 13.392 0.192 13.416 ;
    END
  END o[55]
  PIN o[56]
    DIRECTION OUTPUT ;
    USE SIGNAL ;
    PORT
      LAYER M4 ;
        RECT  0 13.584 0.192 13.608 ;
    END
  END o[56]
  PIN o[57]
    DIRECTION OUTPUT ;
    USE SIGNAL ;
    PORT
      LAYER M4 ;
        RECT  0 13.728 0.192 13.752 ;
    END
  END o[57]
  PIN o[58]
    DIRECTION OUTPUT ;
    USE SIGNAL ;
    PORT
      LAYER M4 ;
        RECT  0 13.92 0.192 13.944 ;
    END
  END o[58]
  PIN o[59]
    DIRECTION OUTPUT ;
    USE SIGNAL ;
    PORT
      LAYER M4 ;
        RECT  0 14.064 0.192 14.088 ;
    END
  END o[59]
  PIN o[5]
    DIRECTION OUTPUT ;
    USE SIGNAL ;
    PORT
      LAYER M4 ;
        RECT  0 5.232 0.192 5.256 ;
    END
  END o[5]
  PIN o[60]
    DIRECTION OUTPUT ;
    USE SIGNAL ;
    PORT
      LAYER M4 ;
        RECT  0 14.208 0.192 14.232 ;
    END
  END o[60]
  PIN o[61]
    DIRECTION OUTPUT ;
    USE SIGNAL ;
    PORT
      LAYER M4 ;
        RECT  0 14.4 0.192 14.424 ;
    END
  END o[61]
  PIN o[62]
    DIRECTION OUTPUT ;
    USE SIGNAL ;
    PORT
      LAYER M4 ;
        RECT  0 14.544 0.192 14.568 ;
    END
  END o[62]
  PIN o[63]
    DIRECTION OUTPUT ;
    USE SIGNAL ;
    PORT
      LAYER M4 ;
        RECT  0 14.736 0.192 14.76 ;
    END
  END o[63]
  PIN o[64]
    DIRECTION OUTPUT ;
    USE SIGNAL ;
    PORT
      LAYER M4 ;
        RECT  0 14.88 0.192 14.904 ;
    END
  END o[64]
  PIN o[65]
    DIRECTION OUTPUT ;
    USE SIGNAL ;
    PORT
      LAYER M4 ;
        RECT  0 15.024 0.192 15.048 ;
    END
  END o[65]
  PIN o[66]
    DIRECTION OUTPUT ;
    USE SIGNAL ;
    PORT
      LAYER M4 ;
        RECT  0 15.216 0.192 15.24 ;
    END
  END o[66]
  PIN o[67]
    DIRECTION OUTPUT ;
    USE SIGNAL ;
    PORT
      LAYER M4 ;
        RECT  0 15.36 0.192 15.384 ;
    END
  END o[67]
  PIN o[68]
    DIRECTION OUTPUT ;
    USE SIGNAL ;
    PORT
      LAYER M4 ;
        RECT  0 15.552 0.192 15.576 ;
    END
  END o[68]
  PIN o[69]
    DIRECTION OUTPUT ;
    USE SIGNAL ;
    PORT
      LAYER M4 ;
        RECT  0 15.696 0.192 15.72 ;
    END
  END o[69]
  PIN o[6]
    DIRECTION OUTPUT ;
    USE SIGNAL ;
    PORT
      LAYER M4 ;
        RECT  0 5.376 0.192 5.4 ;
    END
  END o[6]
  PIN o[70]
    DIRECTION OUTPUT ;
    USE SIGNAL ;
    PORT
      LAYER M4 ;
        RECT  0 15.84 0.192 15.864 ;
    END
  END o[70]
  PIN o[71]
    DIRECTION OUTPUT ;
    USE SIGNAL ;
    PORT
      LAYER M4 ;
        RECT  0 16.032 0.192 16.056 ;
    END
  END o[71]
  PIN o[72]
    DIRECTION OUTPUT ;
    USE SIGNAL ;
    PORT
      LAYER M4 ;
        RECT  0 16.176 0.192 16.2 ;
    END
  END o[72]
  PIN o[73]
    DIRECTION OUTPUT ;
    USE SIGNAL ;
    PORT
      LAYER M4 ;
        RECT  0 16.368 0.192 16.392 ;
    END
  END o[73]
  PIN o[74]
    DIRECTION OUTPUT ;
    USE SIGNAL ;
    PORT
      LAYER M4 ;
        RECT  0 16.512 0.192 16.536 ;
    END
  END o[74]
  PIN o[75]
    DIRECTION OUTPUT ;
    USE SIGNAL ;
    PORT
      LAYER M4 ;
        RECT  0 16.704 0.192 16.728 ;
    END
  END o[75]
  PIN o[76]
    DIRECTION OUTPUT ;
    USE SIGNAL ;
    PORT
      LAYER M4 ;
        RECT  0 16.848 0.192 16.872 ;
    END
  END o[76]
  PIN o[77]
    DIRECTION OUTPUT ;
    USE SIGNAL ;
    PORT
      LAYER M4 ;
        RECT  0 16.992 0.192 17.016 ;
    END
  END o[77]
  PIN o[78]
    DIRECTION OUTPUT ;
    USE SIGNAL ;
    PORT
      LAYER M4 ;
        RECT  0 17.184 0.192 17.208 ;
    END
  END o[78]
  PIN o[79]
    DIRECTION OUTPUT ;
    USE SIGNAL ;
    PORT
      LAYER M4 ;
        RECT  0 17.328 0.192 17.352 ;
    END
  END o[79]
  PIN o[7]
    DIRECTION OUTPUT ;
    USE SIGNAL ;
    PORT
      LAYER M4 ;
        RECT  0 5.568 0.192 5.592 ;
    END
  END o[7]
  PIN o[80]
    DIRECTION OUTPUT ;
    USE SIGNAL ;
    PORT
      LAYER M4 ;
        RECT  0 17.52 0.192 17.544 ;
    END
  END o[80]
  PIN o[81]
    DIRECTION OUTPUT ;
    USE SIGNAL ;
    PORT
      LAYER M4 ;
        RECT  0 17.664 0.192 17.688 ;
    END
  END o[81]
  PIN o[82]
    DIRECTION OUTPUT ;
    USE SIGNAL ;
    PORT
      LAYER M4 ;
        RECT  0 17.808 0.192 17.832 ;
    END
  END o[82]
  PIN o[83]
    DIRECTION OUTPUT ;
    USE SIGNAL ;
    PORT
      LAYER M4 ;
        RECT  0 18 0.192 18.024 ;
    END
  END o[83]
  PIN o[84]
    DIRECTION OUTPUT ;
    USE SIGNAL ;
    PORT
      LAYER M4 ;
        RECT  0 18.144 0.192 18.168 ;
    END
  END o[84]
  PIN o[85]
    DIRECTION OUTPUT ;
    USE SIGNAL ;
    PORT
      LAYER M4 ;
        RECT  0 18.336 0.192 18.36 ;
    END
  END o[85]
  PIN o[86]
    DIRECTION OUTPUT ;
    USE SIGNAL ;
    PORT
      LAYER M4 ;
        RECT  0 18.48 0.192 18.504 ;
    END
  END o[86]
  PIN o[87]
    DIRECTION OUTPUT ;
    USE SIGNAL ;
    PORT
      LAYER M4 ;
        RECT  0 18.624 0.192 18.648 ;
    END
  END o[87]
  PIN o[88]
    DIRECTION OUTPUT ;
    USE SIGNAL ;
    PORT
      LAYER M4 ;
        RECT  0 18.816 0.192 18.84 ;
    END
  END o[88]
  PIN o[89]
    DIRECTION OUTPUT ;
    USE SIGNAL ;
    PORT
      LAYER M4 ;
        RECT  0 18.96 0.192 18.984 ;
    END
  END o[89]
  PIN o[8]
    DIRECTION OUTPUT ;
    USE SIGNAL ;
    PORT
      LAYER M4 ;
        RECT  0 5.712 0.192 5.736 ;
    END
  END o[8]
  PIN o[90]
    DIRECTION OUTPUT ;
    USE SIGNAL ;
    PORT
      LAYER M4 ;
        RECT  0 19.152 0.192 19.176 ;
    END
  END o[90]
  PIN o[91]
    DIRECTION OUTPUT ;
    USE SIGNAL ;
    PORT
      LAYER M4 ;
        RECT  0 19.296 0.192 19.32 ;
    END
  END o[91]
  PIN o[92]
    DIRECTION OUTPUT ;
    USE SIGNAL ;
    PORT
      LAYER M4 ;
        RECT  0 19.44 0.192 19.464 ;
    END
  END o[92]
  PIN o[93]
    DIRECTION OUTPUT ;
    USE SIGNAL ;
    PORT
      LAYER M4 ;
        RECT  0 19.632 0.192 19.656 ;
    END
  END o[93]
  PIN o[94]
    DIRECTION OUTPUT ;
    USE SIGNAL ;
    PORT
      LAYER M4 ;
        RECT  0 19.776 0.192 19.8 ;
    END
  END o[94]
  PIN o[95]
    DIRECTION OUTPUT ;
    USE SIGNAL ;
    PORT
      LAYER M4 ;
        RECT  0 19.968 0.192 19.992 ;
    END
  END o[95]
  PIN o[96]
    DIRECTION OUTPUT ;
    USE SIGNAL ;
    PORT
      LAYER M4 ;
        RECT  0 20.112 0.192 20.136 ;
    END
  END o[96]
  PIN o[97]
    DIRECTION OUTPUT ;
    USE SIGNAL ;
    PORT
      LAYER M4 ;
        RECT  0 20.304 0.192 20.328 ;
    END
  END o[97]
  PIN o[98]
    DIRECTION OUTPUT ;
    USE SIGNAL ;
    PORT
      LAYER M4 ;
        RECT  0 20.448 0.192 20.472 ;
    END
  END o[98]
  PIN o[99]
    DIRECTION OUTPUT ;
    USE SIGNAL ;
    PORT
      LAYER M4 ;
        RECT  0 20.592 0.192 20.616 ;
    END
  END o[99]
  PIN o[9]
    DIRECTION OUTPUT ;
    USE SIGNAL ;
    PORT
      LAYER M4 ;
        RECT  0 5.904 0.192 5.928 ;
    END
  END o[9]
  PIN VDD
    DIRECTION INOUT ;
    USE POWER ;
    PORT
      LAYER M5 ;
        RECT  72.792 2.151 72.912 90.729 ;
        RECT  70.092 2.151 70.212 90.729 ;
        RECT  67.392 2.151 67.512 90.729 ;
        RECT  64.692 2.151 64.812 90.729 ;
        RECT  61.992 2.151 62.112 90.729 ;
        RECT  59.292 2.151 59.412 90.729 ;
        RECT  56.592 2.151 56.712 90.729 ;
        RECT  53.892 2.151 54.012 90.729 ;
        RECT  51.192 2.151 51.312 90.729 ;
        RECT  48.492 2.151 48.612 90.729 ;
        RECT  45.792 2.151 45.912 90.729 ;
        RECT  43.092 2.151 43.212 90.729 ;
        RECT  40.392 2.151 40.512 90.729 ;
        RECT  37.692 2.151 37.812 90.729 ;
        RECT  34.992 2.151 35.112 90.729 ;
        RECT  32.292 2.151 32.412 90.729 ;
        RECT  29.592 2.151 29.712 90.729 ;
        RECT  26.892 2.151 27.012 90.729 ;
        RECT  24.192 2.151 24.312 90.729 ;
        RECT  21.492 2.151 21.612 90.729 ;
        RECT  18.792 2.151 18.912 90.729 ;
        RECT  16.092 2.151 16.212 90.729 ;
        RECT  13.392 2.151 13.512 90.729 ;
        RECT  10.692 2.151 10.812 90.729 ;
        RECT  7.992 2.151 8.112 90.729 ;
        RECT  5.292 2.151 5.412 90.729 ;
        RECT  2.592 2.151 2.712 90.729 ;
    END
  END VDD
  PIN VSS
    DIRECTION INOUT ;
    USE GROUND ;
    PORT
      LAYER M5 ;
        RECT  72.6 2.137 72.72 90.743 ;
        RECT  69.9 2.137 70.02 90.743 ;
        RECT  67.2 2.137 67.32 90.743 ;
        RECT  64.5 2.137 64.62 90.743 ;
        RECT  61.8 2.137 61.92 90.743 ;
        RECT  59.1 2.137 59.22 90.743 ;
        RECT  56.4 2.137 56.52 90.743 ;
        RECT  53.7 2.137 53.82 90.743 ;
        RECT  51 2.137 51.12 90.743 ;
        RECT  48.3 2.137 48.42 90.743 ;
        RECT  45.6 2.137 45.72 90.743 ;
        RECT  42.9 2.137 43.02 90.743 ;
        RECT  40.2 2.137 40.32 90.743 ;
        RECT  37.5 2.137 37.62 90.743 ;
        RECT  34.8 2.137 34.92 90.743 ;
        RECT  32.1 2.137 32.22 90.743 ;
        RECT  29.4 2.137 29.52 90.743 ;
        RECT  26.7 2.137 26.82 90.743 ;
        RECT  24 2.137 24.12 90.743 ;
        RECT  21.3 2.137 21.42 90.743 ;
        RECT  18.6 2.137 18.72 90.743 ;
        RECT  15.9 2.137 16.02 90.743 ;
        RECT  13.2 2.137 13.32 90.743 ;
        RECT  10.5 2.137 10.62 90.743 ;
        RECT  7.8 2.137 7.92 90.743 ;
        RECT  5.1 2.137 5.22 90.743 ;
        RECT  2.4 2.137 2.52 90.743 ;
    END
  END VSS
  # OT_OBS_CLOSED layer=M5 d_um=1.536 added=1255
  OBS
    LAYER RVTN ;
     RECT  2.16 2.16 73.44 2.295 ;
     RECT  2.16 2.565 73.44 2.835 ;
     RECT  2.16 3.105 73.44 3.375 ;
     RECT  2.16 3.645 73.44 3.915 ;
     RECT  2.16 4.185 73.44 4.455 ;
     RECT  2.16 4.725 73.44 4.995 ;
     RECT  2.16 5.265 73.44 5.535 ;
     RECT  2.16 5.805 73.44 6.075 ;
     RECT  2.16 6.345 73.44 6.615 ;
     RECT  2.16 6.885 73.44 7.155 ;
     RECT  2.16 7.425 73.44 7.695 ;
     RECT  2.16 7.965 73.44 8.235 ;
     RECT  2.16 8.505 73.44 8.775 ;
     RECT  2.16 9.045 73.44 9.315 ;
     RECT  2.16 9.585 73.44 9.855 ;
     RECT  2.16 10.125 73.44 10.395 ;
     RECT  2.16 10.665 73.44 10.935 ;
     RECT  2.16 11.205 73.44 11.475 ;
     RECT  2.16 11.745 73.44 12.015 ;
     RECT  2.16 12.285 73.44 12.555 ;
     RECT  2.16 12.825 73.44 13.095 ;
     RECT  2.16 13.365 73.44 13.635 ;
     RECT  2.16 13.905 73.44 14.175 ;
     RECT  2.16 14.445 73.44 14.715 ;
     RECT  2.16 14.985 73.44 15.255 ;
     RECT  2.16 15.525 73.44 15.795 ;
     RECT  2.16 16.065 73.44 16.335 ;
     RECT  2.16 16.605 73.44 16.875 ;
     RECT  2.16 17.145 73.44 17.415 ;
     RECT  2.16 17.685 73.44 17.955 ;
     RECT  2.16 18.225 73.44 18.495 ;
     RECT  2.16 18.765 73.44 19.035 ;
     RECT  2.16 19.305 73.44 19.575 ;
     RECT  2.16 19.845 73.44 20.115 ;
     RECT  2.16 20.385 73.44 20.655 ;
     RECT  2.16 20.925 73.44 21.195 ;
     RECT  2.16 21.465 73.44 21.735 ;
     RECT  2.16 22.005 73.44 22.275 ;
     RECT  2.16 22.545 73.44 22.815 ;
     RECT  2.16 23.085 73.44 23.355 ;
     RECT  2.16 23.625 73.44 23.895 ;
     RECT  2.16 24.165 73.44 24.435 ;
     RECT  2.16 24.705 73.44 24.975 ;
     RECT  2.16 25.245 73.44 25.515 ;
     RECT  2.16 25.785 73.44 26.055 ;
     RECT  2.16 26.325 73.44 26.595 ;
     RECT  2.16 26.865 73.44 27.135 ;
     RECT  2.16 27.405 73.44 27.675 ;
     RECT  2.16 27.945 73.44 28.215 ;
     RECT  2.16 28.485 73.44 28.755 ;
     RECT  2.16 29.025 73.44 29.295 ;
     RECT  2.16 29.565 73.44 29.835 ;
     RECT  2.16 30.105 73.44 30.375 ;
     RECT  2.16 30.645 73.44 30.915 ;
     RECT  2.16 31.185 73.44 31.455 ;
     RECT  2.16 31.725 73.44 31.995 ;
     RECT  2.16 32.265 73.44 32.535 ;
     RECT  2.16 32.805 73.44 33.075 ;
     RECT  2.16 33.345 73.44 33.615 ;
     RECT  2.16 33.885 73.44 34.155 ;
     RECT  2.16 34.425 73.44 34.695 ;
     RECT  2.16 34.965 73.44 35.235 ;
     RECT  2.16 35.505 73.44 35.775 ;
     RECT  2.16 36.045 73.44 36.315 ;
     RECT  2.16 36.585 73.44 36.855 ;
     RECT  2.16 37.125 73.44 37.395 ;
     RECT  2.16 37.665 73.44 37.935 ;
     RECT  2.16 38.205 73.44 38.475 ;
     RECT  2.16 38.745 73.44 39.015 ;
     RECT  2.16 39.285 73.44 39.555 ;
     RECT  2.16 39.825 73.44 40.095 ;
     RECT  2.16 40.365 73.44 40.635 ;
     RECT  2.16 40.905 73.44 41.175 ;
     RECT  2.16 41.445 73.44 41.715 ;
     RECT  2.16 41.985 73.44 42.255 ;
     RECT  2.16 42.525 73.44 42.795 ;
     RECT  2.16 43.065 73.44 43.335 ;
     RECT  2.16 43.605 73.44 43.875 ;
     RECT  2.16 44.145 73.44 44.415 ;
     RECT  2.16 44.685 73.44 44.955 ;
     RECT  2.16 45.225 73.44 45.495 ;
     RECT  2.16 45.765 73.44 46.035 ;
     RECT  2.16 46.305 73.44 46.575 ;
     RECT  2.16 46.845 73.44 47.115 ;
     RECT  2.16 47.385 73.44 47.655 ;
     RECT  2.16 47.925 73.44 48.195 ;
     RECT  2.16 48.465 73.44 48.735 ;
     RECT  2.16 49.005 73.44 49.275 ;
     RECT  2.16 49.545 73.44 49.815 ;
     RECT  2.16 50.085 73.44 50.355 ;
     RECT  2.16 50.625 73.44 50.895 ;
     RECT  2.16 51.165 73.44 51.435 ;
     RECT  2.16 51.705 73.44 51.975 ;
     RECT  2.16 52.245 73.44 52.515 ;
     RECT  2.16 52.785 73.44 53.055 ;
     RECT  2.16 53.325 73.44 53.595 ;
     RECT  2.16 53.865 73.44 54.135 ;
     RECT  2.16 54.405 73.44 54.675 ;
     RECT  2.16 54.945 73.44 55.215 ;
     RECT  2.16 55.485 73.44 55.755 ;
     RECT  2.16 56.025 73.44 56.295 ;
     RECT  2.16 56.565 73.44 56.835 ;
     RECT  2.16 57.105 73.44 57.375 ;
     RECT  2.16 57.645 73.44 57.915 ;
     RECT  2.16 58.185 73.44 58.455 ;
     RECT  2.16 58.725 73.44 58.995 ;
     RECT  2.16 59.265 73.44 59.535 ;
     RECT  2.16 59.805 73.44 60.075 ;
     RECT  2.16 60.345 73.44 60.615 ;
     RECT  2.16 60.885 73.44 61.155 ;
     RECT  2.16 61.425 73.44 61.695 ;
     RECT  2.16 61.965 73.44 62.235 ;
     RECT  2.16 62.505 73.44 62.775 ;
     RECT  2.16 63.045 73.44 63.315 ;
     RECT  2.16 63.585 73.44 63.855 ;
     RECT  2.16 64.125 73.44 64.395 ;
     RECT  2.16 64.665 73.44 64.935 ;
     RECT  2.16 65.205 73.44 65.475 ;
     RECT  2.16 65.745 73.44 66.015 ;
     RECT  2.16 66.285 73.44 66.555 ;
     RECT  2.16 66.825 73.44 67.095 ;
     RECT  2.16 67.365 73.44 67.635 ;
     RECT  2.16 67.905 73.44 68.175 ;
     RECT  2.16 68.445 73.44 68.715 ;
     RECT  2.16 68.985 73.44 69.255 ;
     RECT  2.16 69.525 73.44 69.795 ;
     RECT  2.16 70.065 73.44 70.335 ;
     RECT  2.16 70.605 73.44 70.875 ;
     RECT  2.16 71.145 73.44 71.415 ;
     RECT  2.16 71.685 73.44 71.955 ;
     RECT  2.16 72.225 73.44 72.495 ;
     RECT  2.16 72.765 73.44 73.035 ;
     RECT  2.16 73.305 73.44 73.575 ;
     RECT  2.16 73.845 73.44 74.115 ;
     RECT  2.16 74.385 73.44 74.655 ;
     RECT  2.16 74.925 73.44 75.195 ;
     RECT  2.16 75.465 73.44 75.735 ;
     RECT  2.16 76.005 73.44 76.275 ;
     RECT  2.16 76.545 73.44 76.815 ;
     RECT  2.16 77.085 73.44 77.355 ;
     RECT  2.16 77.625 73.44 77.895 ;
     RECT  2.16 78.165 73.44 78.435 ;
     RECT  2.16 78.705 73.44 78.975 ;
     RECT  2.16 79.245 73.44 79.515 ;
     RECT  2.16 79.785 73.44 80.055 ;
     RECT  2.16 80.325 73.44 80.595 ;
     RECT  2.16 80.865 73.44 81.135 ;
     RECT  2.16 81.405 73.44 81.675 ;
     RECT  2.16 81.945 73.44 82.215 ;
     RECT  2.16 82.485 73.44 82.755 ;
     RECT  2.16 83.025 73.44 83.295 ;
     RECT  2.16 83.565 73.44 83.835 ;
     RECT  2.16 84.105 73.44 84.375 ;
     RECT  2.16 84.645 73.44 84.915 ;
     RECT  2.16 85.185 73.44 85.455 ;
     RECT  2.16 85.725 73.44 85.995 ;
     RECT  2.16 86.265 73.44 86.535 ;
     RECT  2.16 86.805 73.44 87.075 ;
     RECT  2.16 87.345 73.44 87.615 ;
     RECT  2.16 87.885 73.44 88.155 ;
     RECT  2.16 88.425 73.44 88.695 ;
     RECT  2.16 88.965 73.44 89.235 ;
     RECT  2.16 89.505 73.44 89.775 ;
     RECT  2.16 90.045 73.44 90.315 ;
     RECT  2.16 90.585 73.44 90.72 ;
    LAYER RVTP ;
     RECT  2.16 2.295 73.44 2.565 ;
     RECT  2.16 2.835 73.44 3.105 ;
     RECT  2.16 3.375 73.44 3.645 ;
     RECT  2.16 3.915 73.44 4.185 ;
     RECT  2.16 4.455 73.44 4.725 ;
     RECT  2.16 4.995 73.44 5.265 ;
     RECT  2.16 5.535 73.44 5.805 ;
     RECT  2.16 6.075 73.44 6.345 ;
     RECT  2.16 6.615 73.44 6.885 ;
     RECT  2.16 7.155 73.44 7.425 ;
     RECT  2.16 7.695 73.44 7.965 ;
     RECT  2.16 8.235 73.44 8.505 ;
     RECT  2.16 8.775 73.44 9.045 ;
     RECT  2.16 9.315 73.44 9.585 ;
     RECT  2.16 9.855 73.44 10.125 ;
     RECT  2.16 10.395 73.44 10.665 ;
     RECT  2.16 10.935 73.44 11.205 ;
     RECT  2.16 11.475 73.44 11.745 ;
     RECT  2.16 12.015 73.44 12.285 ;
     RECT  2.16 12.555 73.44 12.825 ;
     RECT  2.16 13.095 73.44 13.365 ;
     RECT  2.16 13.635 73.44 13.905 ;
     RECT  2.16 14.175 73.44 14.445 ;
     RECT  2.16 14.715 73.44 14.985 ;
     RECT  2.16 15.255 73.44 15.525 ;
     RECT  2.16 15.795 73.44 16.065 ;
     RECT  2.16 16.335 73.44 16.605 ;
     RECT  2.16 16.875 73.44 17.145 ;
     RECT  2.16 17.415 73.44 17.685 ;
     RECT  2.16 17.955 73.44 18.225 ;
     RECT  2.16 18.495 73.44 18.765 ;
     RECT  2.16 19.035 73.44 19.305 ;
     RECT  2.16 19.575 73.44 19.845 ;
     RECT  2.16 20.115 73.44 20.385 ;
     RECT  2.16 20.655 73.44 20.925 ;
     RECT  2.16 21.195 73.44 21.465 ;
     RECT  2.16 21.735 73.44 22.005 ;
     RECT  2.16 22.275 73.44 22.545 ;
     RECT  2.16 22.815 73.44 23.085 ;
     RECT  2.16 23.355 73.44 23.625 ;
     RECT  2.16 23.895 73.44 24.165 ;
     RECT  2.16 24.435 73.44 24.705 ;
     RECT  2.16 24.975 73.44 25.245 ;
     RECT  2.16 25.515 73.44 25.785 ;
     RECT  2.16 26.055 73.44 26.325 ;
     RECT  2.16 26.595 73.44 26.865 ;
     RECT  2.16 27.135 73.44 27.405 ;
     RECT  2.16 27.675 73.44 27.945 ;
     RECT  2.16 28.215 73.44 28.485 ;
     RECT  2.16 28.755 73.44 29.025 ;
     RECT  2.16 29.295 73.44 29.565 ;
     RECT  2.16 29.835 73.44 30.105 ;
     RECT  2.16 30.375 73.44 30.645 ;
     RECT  2.16 30.915 73.44 31.185 ;
     RECT  2.16 31.455 73.44 31.725 ;
     RECT  2.16 31.995 73.44 32.265 ;
     RECT  2.16 32.535 73.44 32.805 ;
     RECT  2.16 33.075 73.44 33.345 ;
     RECT  2.16 33.615 73.44 33.885 ;
     RECT  2.16 34.155 73.44 34.425 ;
     RECT  2.16 34.695 73.44 34.965 ;
     RECT  2.16 35.235 73.44 35.505 ;
     RECT  2.16 35.775 73.44 36.045 ;
     RECT  2.16 36.315 73.44 36.585 ;
     RECT  2.16 36.855 73.44 37.125 ;
     RECT  2.16 37.395 73.44 37.665 ;
     RECT  2.16 37.935 73.44 38.205 ;
     RECT  2.16 38.475 73.44 38.745 ;
     RECT  2.16 39.015 73.44 39.285 ;
     RECT  2.16 39.555 73.44 39.825 ;
     RECT  2.16 40.095 73.44 40.365 ;
     RECT  2.16 40.635 73.44 40.905 ;
     RECT  2.16 41.175 73.44 41.445 ;
     RECT  2.16 41.715 73.44 41.985 ;
     RECT  2.16 42.255 73.44 42.525 ;
     RECT  2.16 42.795 73.44 43.065 ;
     RECT  2.16 43.335 73.44 43.605 ;
     RECT  2.16 43.875 73.44 44.145 ;
     RECT  2.16 44.415 73.44 44.685 ;
     RECT  2.16 44.955 73.44 45.225 ;
     RECT  2.16 45.495 73.44 45.765 ;
     RECT  2.16 46.035 73.44 46.305 ;
     RECT  2.16 46.575 73.44 46.845 ;
     RECT  2.16 47.115 73.44 47.385 ;
     RECT  2.16 47.655 73.44 47.925 ;
     RECT  2.16 48.195 73.44 48.465 ;
     RECT  2.16 48.735 73.44 49.005 ;
     RECT  2.16 49.275 73.44 49.545 ;
     RECT  2.16 49.815 73.44 50.085 ;
     RECT  2.16 50.355 73.44 50.625 ;
     RECT  2.16 50.895 73.44 51.165 ;
     RECT  2.16 51.435 73.44 51.705 ;
     RECT  2.16 51.975 73.44 52.245 ;
     RECT  2.16 52.515 73.44 52.785 ;
     RECT  2.16 53.055 73.44 53.325 ;
     RECT  2.16 53.595 73.44 53.865 ;
     RECT  2.16 54.135 73.44 54.405 ;
     RECT  2.16 54.675 73.44 54.945 ;
     RECT  2.16 55.215 73.44 55.485 ;
     RECT  2.16 55.755 73.44 56.025 ;
     RECT  2.16 56.295 73.44 56.565 ;
     RECT  2.16 56.835 73.44 57.105 ;
     RECT  2.16 57.375 73.44 57.645 ;
     RECT  2.16 57.915 73.44 58.185 ;
     RECT  2.16 58.455 73.44 58.725 ;
     RECT  2.16 58.995 73.44 59.265 ;
     RECT  2.16 59.535 73.44 59.805 ;
     RECT  2.16 60.075 73.44 60.345 ;
     RECT  2.16 60.615 73.44 60.885 ;
     RECT  2.16 61.155 73.44 61.425 ;
     RECT  2.16 61.695 73.44 61.965 ;
     RECT  2.16 62.235 73.44 62.505 ;
     RECT  2.16 62.775 73.44 63.045 ;
     RECT  2.16 63.315 73.44 63.585 ;
     RECT  2.16 63.855 73.44 64.125 ;
     RECT  2.16 64.395 73.44 64.665 ;
     RECT  2.16 64.935 73.44 65.205 ;
     RECT  2.16 65.475 73.44 65.745 ;
     RECT  2.16 66.015 73.44 66.285 ;
     RECT  2.16 66.555 73.44 66.825 ;
     RECT  2.16 67.095 73.44 67.365 ;
     RECT  2.16 67.635 73.44 67.905 ;
     RECT  2.16 68.175 73.44 68.445 ;
     RECT  2.16 68.715 73.44 68.985 ;
     RECT  2.16 69.255 73.44 69.525 ;
     RECT  2.16 69.795 73.44 70.065 ;
     RECT  2.16 70.335 73.44 70.605 ;
     RECT  2.16 70.875 73.44 71.145 ;
     RECT  2.16 71.415 73.44 71.685 ;
     RECT  2.16 71.955 73.44 72.225 ;
     RECT  2.16 72.495 73.44 72.765 ;
     RECT  2.16 73.035 73.44 73.305 ;
     RECT  2.16 73.575 73.44 73.845 ;
     RECT  2.16 74.115 73.44 74.385 ;
     RECT  2.16 74.655 73.44 74.925 ;
     RECT  2.16 75.195 73.44 75.465 ;
     RECT  2.16 75.735 73.44 76.005 ;
     RECT  2.16 76.275 73.44 76.545 ;
     RECT  2.16 76.815 73.44 77.085 ;
     RECT  2.16 77.355 73.44 77.625 ;
     RECT  2.16 77.895 73.44 78.165 ;
     RECT  2.16 78.435 73.44 78.705 ;
     RECT  2.16 78.975 73.44 79.245 ;
     RECT  2.16 79.515 73.44 79.785 ;
     RECT  2.16 80.055 73.44 80.325 ;
     RECT  2.16 80.595 73.44 80.865 ;
     RECT  2.16 81.135 73.44 81.405 ;
     RECT  2.16 81.675 73.44 81.945 ;
     RECT  2.16 82.215 73.44 82.485 ;
     RECT  2.16 82.755 73.44 83.025 ;
     RECT  2.16 83.295 73.44 83.565 ;
     RECT  2.16 83.835 73.44 84.105 ;
     RECT  2.16 84.375 73.44 84.645 ;
     RECT  2.16 84.915 73.44 85.185 ;
     RECT  2.16 85.455 73.44 85.725 ;
     RECT  2.16 85.995 73.44 86.265 ;
     RECT  2.16 86.535 73.44 86.805 ;
     RECT  2.16 87.075 73.44 87.345 ;
     RECT  2.16 87.615 73.44 87.885 ;
     RECT  2.16 88.155 73.44 88.425 ;
     RECT  2.16 88.695 73.44 88.965 ;
     RECT  2.16 89.235 73.44 89.505 ;
     RECT  2.16 89.775 73.44 90.045 ;
     RECT  2.16 90.315 73.44 90.585 ;
    LAYER M1 ;
     RECT  2.16 2.151 73.44 90.729 ;
    LAYER M2 ;
     RECT  0.463 47.628 0.499 47.646 ;
     RECT  0.211 8.406 0.535 8.424 ;
     RECT  0.211 12.996 0.535 13.014 ;
     RECT  0.211 18.666 0.535 18.684 ;
     RECT  0.499 47.286 0.535 47.646 ;
     RECT  0.499 53.136 0.535 53.154 ;
     RECT  0.211 57.276 0.535 57.294 ;
     RECT  0.499 72.666 0.535 72.684 ;
     RECT  0.211 83.196 0.535 83.214 ;
     RECT  0.535 32.238 1.147 32.256 ;
     RECT  0.211 80.91 1.147 80.928 ;
     RECT  1.147 32.238 1.175 32.364 ;
     RECT  1.147 80.838 1.175 80.928 ;
     RECT  0.211 6.786 2.16 6.804 ;
     RECT  0.535 7.776 2.16 8.766 ;
     RECT  0.535 12.528 2.16 13.464 ;
     RECT  0.535 17.586 2.16 18.684 ;
     RECT  0.535 22.086 2.16 22.104 ;
     RECT  0.535 23.13 2.16 23.148 ;
     RECT  0.211 24.336 2.16 24.354 ;
     RECT  0.535 26.064 2.16 26.694 ;
     RECT  1.175 32.346 2.16 32.364 ;
     RECT  0.211 37.566 2.16 37.584 ;
     RECT  0.211 42.156 2.16 42.174 ;
     RECT  0.211 43.848 2.16 43.866 ;
     RECT  0.535 47.196 2.16 48.186 ;
     RECT  0.211 48.978 2.16 48.996 ;
     RECT  0.535 53.136 2.16 54.054 ;
     RECT  0.535 57.276 2.16 58.554 ;
     RECT  0.211 59.778 2.16 59.796 ;
     RECT  0.211 62.676 2.16 62.694 ;
     RECT  0.211 66.456 2.16 66.474 ;
     RECT  0.535 68.796 2.16 68.814 ;
     RECT  0.535 71.226 2.16 71.244 ;
     RECT  0.535 72.666 2.16 72.756 ;
     RECT  0.211 74.016 2.16 74.034 ;
     RECT  0.211 78.606 2.16 79.704 ;
     RECT  1.175 80.838 2.16 80.856 ;
     RECT  0.535 83.196 2.16 83.592 ;
     RECT  2.16 2.151 66.559 90.729 ;
     RECT  66.559 2.034 67.019 90.729 ;
     RECT  67.019 2.106 69.683 90.729 ;
     RECT  69.683 2.151 73.44 90.729 ;
     RECT  73.44 7.596 73.499 7.614 ;
     RECT  73.44 68.796 73.499 69.354 ;
     RECT  73.44 10.17 73.535 10.188 ;
     RECT  73.44 77.67 73.535 77.688 ;
     RECT  73.44 85.158 73.535 85.176 ;
     RECT  73.44 11.52 73.571 11.538 ;
     RECT  73.44 22.554 73.571 22.644 ;
     RECT  73.44 27.144 73.571 27.162 ;
     RECT  73.44 30.15 73.571 30.438 ;
     RECT  73.44 36.09 73.571 36.306 ;
     RECT  73.44 46.818 73.571 50.346 ;
     RECT  73.44 52.794 73.571 53.856 ;
     RECT  73.44 55.728 73.571 57.096 ;
     RECT  73.44 60.93 73.571 62.226 ;
     RECT  73.44 72 73.571 72.288 ;
     RECT  73.44 75.744 73.571 76.608 ;
     RECT  73.44 82.494 73.571 83.016 ;
     RECT  73.44 23.634 73.607 23.922 ;
     RECT  73.44 28.296 73.607 28.782 ;
     RECT  73.571 52.794 73.607 53.01 ;
     RECT  73.44 66.6 73.607 67.356 ;
     RECT  73.44 88.704 73.607 88.722 ;
     RECT  73.44 18.036 73.751 18.054 ;
     RECT  73.44 20.43 73.751 20.952 ;
     RECT  73.571 61.2 73.787 62.226 ;
     RECT  73.44 4.23 74.111 4.248 ;
     RECT  73.44 6.66 74.111 6.678 ;
     RECT  73.44 15.03 74.111 15.048 ;
     RECT  73.571 22.626 74.111 22.644 ;
     RECT  73.607 28.296 74.111 28.314 ;
     RECT  73.607 52.866 74.111 53.01 ;
     RECT  73.44 63.558 74.111 64.386 ;
     RECT  73.44 5.04 74.147 5.058 ;
     RECT  73.44 16.344 74.147 16.668 ;
     RECT  73.44 19.278 74.147 19.296 ;
     RECT  73.571 36.288 74.147 36.306 ;
     RECT  73.44 37.17 74.147 37.188 ;
     RECT  73.44 40.608 74.147 41.166 ;
     RECT  73.44 42.264 74.147 43.866 ;
     RECT  73.571 47.628 74.147 50.346 ;
     RECT  73.571 53.838 74.147 53.856 ;
     RECT  73.44 54.648 74.147 54.666 ;
     RECT  73.571 55.728 74.147 55.746 ;
     RECT  73.571 56.538 74.147 57.096 ;
     RECT  73.44 57.888 74.147 59.256 ;
     RECT  73.787 61.74 74.147 62.226 ;
     RECT  74.111 63.558 74.147 63.576 ;
     RECT  73.607 67.068 74.147 67.356 ;
     RECT  73.499 69.3 74.147 69.354 ;
     RECT  73.44 73.278 74.147 73.296 ;
     RECT  73.44 74.088 74.147 74.376 ;
     RECT  73.571 75.978 74.147 76.536 ;
     RECT  73.44 80.838 74.147 81.666 ;
     RECT  73.571 82.998 74.147 83.016 ;
     RECT  74.147 74.358 74.183 74.376 ;
     RECT  73.751 20.898 74.579 20.952 ;
     RECT  73.44 24.714 74.579 25.236 ;
     RECT  73.44 39.258 74.579 39.276 ;
     RECT  74.147 47.628 74.579 49.536 ;
     RECT  74.147 50.328 74.579 50.346 ;
     RECT  73.44 51.678 74.579 51.696 ;
     RECT  74.111 64.368 74.579 64.386 ;
     RECT  73.44 79.488 74.579 80.046 ;
     RECT  74.147 80.838 74.579 81.126 ;
     RECT  73.44 86.508 74.579 87.066 ;
     RECT  74.579 24.714 74.651 24.732 ;
     RECT  74.147 40.608 74.651 40.626 ;
     RECT  73.571 46.818 74.651 46.836 ;
     RECT  74.579 49.518 74.651 49.536 ;
     RECT  74.111 52.992 74.651 53.01 ;
     RECT  74.147 62.208 74.651 62.226 ;
     RECT  74.579 79.488 74.651 79.506 ;
     RECT  74.579 81.108 74.651 81.126 ;
     RECT  74.579 20.934 74.687 20.952 ;
     RECT  73.607 23.904 74.687 23.922 ;
     RECT  74.147 42.264 74.687 42.282 ;
     RECT  73.44 45.27 74.687 45.288 ;
     RECT  74.147 57.078 74.687 57.096 ;
     RECT  74.147 67.338 74.687 67.356 ;
     RECT  74.147 69.336 74.687 69.354 ;
     RECT  75.379 24.174 75.479 24.192 ;
     RECT  75.379 51.408 75.479 51.426 ;
     RECT  75.379 75.906 75.479 76.536 ;
    LAYER M3 ;
     RECT  65.484 1.771 65.502 1.867 ;
     RECT  66.672 1.819 66.69 1.915 ;
     RECT  63.612 1.915 63.63 1.963 ;
     RECT  67.536 1.771 67.554 1.963 ;
     RECT  65.088 1.867 65.502 2.011 ;
     RECT  69.516 1.819 69.534 2.011 ;
     RECT  70.308 1.963 70.326 2.011 ;
     RECT  66.492 1.915 66.69 2.029 ;
     RECT  67.536 1.963 67.77 2.029 ;
     RECT  61.524 2.011 61.542 2.059 ;
     RECT  69.084 2.011 69.534 2.059 ;
     RECT  66.492 2.029 67.77 2.101 ;
     RECT  68.796 2.059 69.534 2.101 ;
     RECT  70.308 2.011 71.01 2.101 ;
     RECT  63.504 1.963 63.63 2.107 ;
     RECT  57.024 1.963 57.042 2.143 ;
     RECT  61.236 2.059 61.542 2.143 ;
     RECT  62.532 2.107 62.55 2.143 ;
     RECT  63.504 2.107 63.81 2.143 ;
     RECT  64.872 2.011 65.502 2.143 ;
     RECT  72.756 2.059 72.774 2.143 ;
     RECT  61.236 2.143 62.55 2.155 ;
     RECT  71.784 2.059 71.802 2.155 ;
     RECT  72.615 2.143 72.774 2.155 ;
     RECT  48.315 2.143 48.405 2.191 ;
     RECT  51.015 2.143 51.105 2.191 ;
     RECT  59.115 2.143 59.205 2.191 ;
     RECT  63.504 2.143 65.502 2.191 ;
     RECT  66.492 2.101 71.01 2.191 ;
     RECT  71.784 2.155 71.874 2.191 ;
     RECT  72.615 2.155 73.026 2.191 ;
     RECT  5.115 2.143 5.205 2.227 ;
     RECT  15.915 2.143 16.005 2.227 ;
     RECT  34.815 2.143 34.905 2.227 ;
     RECT  40.215 2.143 40.305 2.227 ;
     RECT  42.915 2.143 43.005 2.227 ;
     RECT  52.74 2.191 52.758 2.227 ;
     RECT  59.115 2.191 59.67 2.227 ;
     RECT  61.236 2.155 62.622 2.227 ;
     RECT  9.54 2.191 9.558 2.24 ;
     RECT  37.515 2.143 37.605 2.24 ;
     RECT  10.515 2.143 10.605 2.251 ;
     RECT  51.015 2.191 51.462 2.251 ;
     RECT  52.74 2.227 52.902 2.251 ;
     RECT  53.715 2.143 53.805 2.251 ;
     RECT  56.415 2.143 57.042 2.251 ;
     RECT  66.492 2.191 73.242 2.251 ;
     RECT  10.44 2.251 10.605 2.263 ;
     RECT  17.676 2.227 17.694 2.263 ;
     RECT  18.615 2.143 18.705 2.263 ;
     RECT  24.015 2.143 24.105 2.263 ;
     RECT  26.715 2.143 26.805 2.263 ;
     RECT  27.9 2.191 27.918 2.263 ;
     RECT  39.744 2.227 40.305 2.263 ;
     RECT  41.688 2.227 43.005 2.263 ;
     RECT  48.315 2.191 48.474 2.263 ;
     RECT  52.236 2.251 52.902 2.291 ;
     RECT  6.12 2.227 6.138 2.299 ;
     RECT  7.815 2.143 7.905 2.299 ;
     RECT  15.876 2.227 16.005 2.299 ;
     RECT  22.86 2.263 22.878 2.299 ;
     RECT  53.715 2.251 54.414 2.299 ;
     RECT  66.312 2.251 73.242 2.299 ;
     RECT  15.804 2.299 16.83 2.335 ;
     RECT  22.86 2.299 23.058 2.335 ;
     RECT  24.015 2.263 24.462 2.335 ;
     RECT  26.715 2.263 27.918 2.335 ;
     RECT  50.724 2.251 51.462 2.335 ;
     RECT  59.115 2.227 60.03 2.335 ;
     RECT  63.396 2.191 65.502 2.347 ;
     RECT  66.24 2.299 73.242 2.347 ;
     RECT  5.115 2.227 5.346 2.371 ;
     RECT  6.12 2.299 6.318 2.371 ;
     RECT  7.815 2.299 8.334 2.371 ;
     RECT  9.396 2.24 9.558 2.371 ;
     RECT  10.44 2.263 10.962 2.371 ;
     RECT  13.215 2.143 13.305 2.371 ;
     RECT  15.696 2.335 16.83 2.371 ;
     RECT  17.676 2.263 18.705 2.371 ;
     RECT  22.86 2.335 24.462 2.371 ;
     RECT  26.715 2.335 28.602 2.371 ;
     RECT  29.415 2.143 29.505 2.371 ;
     RECT  30.708 2.227 30.726 2.371 ;
     RECT  32.115 2.143 32.205 2.371 ;
     RECT  34.272 2.227 34.905 2.371 ;
     RECT  35.964 2.299 35.982 2.371 ;
     RECT  37.515 2.24 38.25 2.371 ;
     RECT  39.348 2.263 40.554 2.371 ;
     RECT  41.616 2.263 43.005 2.371 ;
     RECT  44.136 2.251 44.154 2.371 ;
     RECT  45.615 2.143 45.705 2.371 ;
     RECT  47.232 2.227 47.25 2.371 ;
     RECT  48.024 2.263 48.474 2.371 ;
     RECT  50.724 2.335 51.498 2.371 ;
     RECT  53.715 2.299 54.522 2.371 ;
     RECT  55.728 2.251 57.042 2.371 ;
     RECT  57.852 2.203 57.87 2.371 ;
     RECT  59.115 2.335 60.318 2.371 ;
     RECT  63.396 2.347 73.242 2.371 ;
     RECT  33.804 2.371 34.905 2.395 ;
     RECT  47.232 2.371 48.87 2.395 ;
     RECT  2.415 2.143 2.505 2.413 ;
     RECT  15.624 2.371 18.705 2.413 ;
     RECT  21.315 2.143 21.405 2.413 ;
     RECT  33.3 2.395 34.905 2.413 ;
     RECT  37.515 2.371 43.074 2.413 ;
     RECT  45.108 2.371 45.705 2.413 ;
     RECT  55.548 2.371 60.318 2.443 ;
     RECT  61.164 2.227 62.622 2.443 ;
     RECT  63.36 2.371 73.242 2.443 ;
     RECT  13.215 2.371 13.698 2.461 ;
     RECT  21.315 2.413 21.597 2.461 ;
     RECT  22.86 2.371 24.606 2.461 ;
     RECT  26.715 2.371 32.454 2.461 ;
     RECT  15.624 2.413 18.897 2.488 ;
     RECT  5.115 2.371 6.39 2.491 ;
     RECT  22.86 2.461 25.29 2.497 ;
     RECT  52.632 2.291 52.902 2.533 ;
     RECT  46.908 2.395 48.87 2.539 ;
     RECT  55.548 2.443 73.242 2.539 ;
     RECT  15.624 2.488 19.17 2.569 ;
     RECT  22.824 2.497 25.29 2.569 ;
     RECT  33.3 2.413 35.097 2.569 ;
     RECT  52.632 2.533 52.938 2.569 ;
     RECT  53.715 2.371 54.666 2.569 ;
     RECT  55.476 2.539 73.242 2.569 ;
     RECT  44.136 2.371 44.334 2.587 ;
     RECT  5.115 2.491 6.462 2.605 ;
     RECT  7.74 2.371 8.334 2.605 ;
     RECT  9.396 2.371 11.79 2.605 ;
     RECT  21.276 2.461 21.69 2.605 ;
     RECT  37.515 2.413 43.197 2.605 ;
     RECT  5.115 2.605 6.57 2.641 ;
     RECT  7.74 2.605 8.586 2.641 ;
     RECT  9.396 2.605 12.366 2.641 ;
     RECT  13.215 2.461 13.842 2.641 ;
     RECT  14.904 2.569 19.17 2.641 ;
     RECT  22.788 2.569 25.29 2.641 ;
     RECT  26.244 2.461 32.454 2.641 ;
     RECT  33.3 2.569 35.154 2.641 ;
     RECT  35.964 2.371 36.126 2.641 ;
     RECT  37.08 2.605 43.197 2.641 ;
     RECT  44.1 2.587 44.334 2.641 ;
     RECT  45.108 2.413 45.897 2.641 ;
     RECT  46.908 2.539 49.302 2.641 ;
     RECT  52.632 2.569 54.666 2.641 ;
     RECT  55.404 2.569 73.242 2.641 ;
     RECT  5.115 2.641 6.642 2.731 ;
     RECT  7.416 2.641 19.746 2.731 ;
     RECT  50.292 2.371 51.498 2.731 ;
     RECT  50.184 2.731 51.498 2.767 ;
     RECT  52.632 2.641 73.242 2.767 ;
     RECT  5.115 2.731 19.746 2.803 ;
     RECT  20.664 2.605 21.726 2.803 ;
     RECT  52.632 2.767 73.314 2.813 ;
     RECT  5.115 2.803 21.726 2.911 ;
     RECT  22.788 2.641 49.302 2.911 ;
     RECT  50.184 2.767 51.678 3.073 ;
     RECT  52.632 2.813 73.242 3.073 ;
     RECT  22.788 2.911 49.374 3.181 ;
     RECT  50.184 3.073 73.242 3.181 ;
     RECT  5.115 2.911 21.906 3.271 ;
     RECT  4.824 3.271 21.906 3.343 ;
     RECT  4.572 3.343 21.906 3.403 ;
     RECT  22.68 3.181 73.242 3.403 ;
     RECT  4.572 3.403 73.242 3.407 ;
     RECT  2.415 2.413 2.697 3.847 ;
     RECT  3.636 3.835 3.654 3.847 ;
     RECT  2.415 3.847 3.654 3.991 ;
     RECT  4.572 3.407 44.622 3.991 ;
     RECT  2.415 3.991 44.622 4.261 ;
     RECT  45.36 3.407 73.242 4.261 ;
     RECT  2.415 4.261 73.242 4.555 ;
     RECT  2.304 4.555 73.242 4.603 ;
     RECT  2.304 4.603 73.314 4.747 ;
     RECT  74.088 4.225 74.106 4.747 ;
     RECT  2.304 4.747 74.106 4.925 ;
     RECT  74.124 5.035 74.142 5.117 ;
     RECT  2.304 4.925 73.314 5.881 ;
     RECT  74.628 5.803 74.646 5.933 ;
     RECT  2.304 5.881 73.35 5.981 ;
     RECT  74.088 6.655 74.106 6.749 ;
     RECT  0.216 6.781 0.234 6.893 ;
     RECT  2.304 5.981 73.314 7.051 ;
     RECT  2.304 7.051 73.494 7.619 ;
     RECT  2.304 7.619 73.314 8.381 ;
     RECT  0.54 7.771 0.558 8.401 ;
     RECT  2.412 8.381 73.314 8.699 ;
     RECT  0.216 8.401 0.558 8.717 ;
     RECT  0.54 8.717 0.558 9.197 ;
     RECT  2.412 8.699 46.998 9.629 ;
     RECT  2.412 9.629 46.386 9.643 ;
     RECT  47.736 8.699 73.314 9.823 ;
     RECT  47.484 9.823 73.314 10.165 ;
     RECT  47.484 10.165 73.53 10.435 ;
     RECT  2.304 9.643 46.386 10.471 ;
     RECT  47.34 10.435 73.53 10.471 ;
     RECT  2.304 10.471 73.53 10.685 ;
     RECT  0.216 10.699 0.234 10.829 ;
     RECT  2.304 10.685 73.35 11.515 ;
     RECT  2.304 11.515 73.566 11.981 ;
     RECT  2.304 11.981 73.314 12.181 ;
     RECT  2.268 12.181 73.314 12.461 ;
     RECT  0.54 12.523 0.558 12.605 ;
     RECT  2.304 12.461 73.314 12.941 ;
     RECT  2.415 12.941 73.314 13.003 ;
     RECT  0.216 12.991 0.234 13.133 ;
     RECT  2.415 13.003 73.494 13.181 ;
     RECT  2.415 13.181 73.314 13.325 ;
     RECT  74.628 13.243 74.646 13.373 ;
     RECT  2.415 13.325 73.242 13.723 ;
     RECT  2.412 13.723 73.242 13.873 ;
     RECT  0.54 13.441 0.558 13.949 ;
     RECT  2.268 13.873 73.242 14.093 ;
     RECT  2.304 14.093 73.242 14.779 ;
     RECT  74.088 15.016 74.106 15.053 ;
     RECT  2.304 14.779 73.314 15.448 ;
     RECT  2.304 15.448 73.386 15.485 ;
     RECT  2.304 15.485 73.278 16.267 ;
     RECT  74.124 16.027 74.142 16.733 ;
     RECT  2.304 16.267 73.314 16.799 ;
     RECT  74.628 16.891 74.646 17.453 ;
     RECT  2.304 16.799 73.206 17.761 ;
     RECT  0.54 17.581 0.558 17.803 ;
     RECT  2.304 17.761 73.242 17.879 ;
     RECT  55.008 17.879 73.242 17.887 ;
     RECT  0.216 17.803 0.558 17.933 ;
     RECT  55.008 17.887 73.314 18.031 ;
     RECT  55.008 18.031 73.746 18.173 ;
     RECT  0.54 17.933 0.558 18.365 ;
     RECT  0.216 18.661 0.234 18.845 ;
     RECT  2.304 17.879 54.27 18.997 ;
     RECT  55.008 18.173 73.242 18.997 ;
     RECT  2.304 18.997 73.242 19.111 ;
     RECT  2.304 19.111 73.314 19.277 ;
     RECT  74.124 18.475 74.142 19.301 ;
     RECT  74.628 19.627 74.646 19.853 ;
     RECT  2.304 19.277 73.206 20.107 ;
     RECT  2.304 20.107 73.746 20.453 ;
     RECT  2.304 20.453 73.314 20.651 ;
     RECT  74.556 20.587 74.574 20.921 ;
     RECT  2.304 20.651 51.498 21.541 ;
     RECT  52.236 20.651 73.314 21.541 ;
     RECT  74.628 20.929 74.682 21.629 ;
     RECT  74.664 21.629 74.682 21.965 ;
     RECT  0.54 22.081 0.558 22.253 ;
     RECT  2.304 21.541 73.314 22.549 ;
     RECT  74.088 22.411 74.106 22.549 ;
     RECT  2.304 22.549 74.106 22.649 ;
     RECT  0.54 23.125 0.558 23.227 ;
     RECT  0.252 23.227 0.558 23.357 ;
     RECT  0.54 23.357 0.558 23.405 ;
     RECT  2.304 22.649 73.602 23.657 ;
     RECT  74.664 22.891 74.682 23.927 ;
     RECT  2.304 23.657 73.314 23.933 ;
     RECT  75.456 24.139 75.474 24.169 ;
     RECT  75.384 24.169 75.474 24.197 ;
     RECT  75.384 24.197 75.402 24.221 ;
     RECT  0.216 24.331 0.234 24.557 ;
     RECT  2.304 23.933 73.242 24.715 ;
     RECT  74.628 24.709 74.646 24.749 ;
     RECT  74.556 24.859 74.574 25.241 ;
     RECT  2.304 24.715 73.314 25.439 ;
     RECT  38.844 25.439 73.314 25.517 ;
     RECT  38.844 25.517 73.242 25.547 ;
     RECT  2.304 25.439 38.07 25.619 ;
     RECT  74.628 26.059 74.646 26.189 ;
     RECT  2.412 25.619 38.07 26.221 ;
     RECT  38.916 25.547 73.242 26.347 ;
     RECT  2.412 26.221 38.106 26.491 ;
     RECT  38.916 26.347 73.566 26.491 ;
     RECT  0.54 26.059 0.558 26.861 ;
     RECT  2.412 26.491 73.566 26.941 ;
     RECT  2.376 26.941 73.566 26.971 ;
     RECT  2.304 26.971 73.566 27.167 ;
     RECT  2.304 27.167 73.314 27.869 ;
     RECT  74.628 26.971 74.646 27.979 ;
     RECT  74.088 27.979 74.646 28.253 ;
     RECT  74.088 28.253 74.106 28.319 ;
     RECT  2.304 27.869 73.242 28.603 ;
     RECT  2.304 28.603 73.602 28.787 ;
     RECT  2.304 28.787 73.314 28.973 ;
     RECT  0.252 29.131 0.27 29.261 ;
     RECT  2.412 28.973 73.314 29.731 ;
     RECT  2.304 29.731 73.314 29.755 ;
     RECT  2.304 29.755 73.566 30.605 ;
     RECT  0.252 30.763 0.27 30.893 ;
     RECT  2.304 30.605 73.314 31.109 ;
     RECT  0.216 31.147 0.234 31.277 ;
     RECT  2.304 31.109 52.254 31.289 ;
     RECT  2.304 31.289 51.966 32.071 ;
     RECT  52.992 31.109 73.314 32.071 ;
     RECT  0.54 32.233 1.17 32.369 ;
     RECT  2.304 32.071 73.314 32.459 ;
     RECT  0.54 32.369 0.558 32.573 ;
     RECT  2.304 32.459 27.054 33.349 ;
     RECT  28.044 32.459 49.446 33.349 ;
     RECT  2.304 33.349 49.446 33.583 ;
     RECT  50.22 32.459 73.314 33.583 ;
     RECT  2.304 33.583 73.314 33.917 ;
     RECT  2.304 33.917 73.242 34.735 ;
     RECT  2.304 34.735 73.314 35.803 ;
     RECT  2.304 35.803 73.566 36.113 ;
     RECT  74.124 36.139 74.142 36.311 ;
     RECT  2.304 36.113 73.314 36.509 ;
     RECT  2.304 36.509 22.014 36.545 ;
     RECT  22.788 36.509 73.314 36.689 ;
     RECT  74.124 37.165 74.142 37.325 ;
     RECT  0.252 37.291 0.27 37.421 ;
     RECT  2.304 36.545 21.942 37.471 ;
     RECT  22.824 36.689 73.314 37.471 ;
     RECT  22.752 37.471 73.314 37.597 ;
     RECT  0.216 37.561 0.234 37.661 ;
     RECT  2.304 37.471 21.978 37.669 ;
     RECT  22.752 37.597 73.35 37.669 ;
     RECT  74.628 37.627 74.646 37.901 ;
     RECT  2.304 37.669 73.35 38.399 ;
     RECT  2.304 38.399 73.314 38.435 ;
     RECT  0.252 38.923 0.27 39.053 ;
     RECT  74.628 38.923 74.646 39.053 ;
     RECT  74.556 39.067 74.574 39.281 ;
     RECT  2.304 38.435 3.078 39.289 ;
     RECT  3.852 38.435 73.314 39.289 ;
     RECT  2.304 39.289 73.314 39.341 ;
     RECT  2.304 39.341 73.206 40.219 ;
     RECT  2.304 40.219 73.386 40.397 ;
     RECT  74.628 40.555 74.646 40.631 ;
     RECT  0.252 40.699 0.27 40.877 ;
     RECT  74.124 41.035 74.142 41.171 ;
     RECT  0.216 42.151 0.234 42.221 ;
     RECT  74.664 42.043 74.682 42.287 ;
     RECT  2.304 40.397 73.314 42.571 ;
     RECT  2.268 42.571 73.314 42.701 ;
     RECT  0.396 42.859 0.414 43.003 ;
     RECT  0.216 43.003 0.414 43.037 ;
     RECT  74.124 42.523 74.142 43.871 ;
     RECT  0.216 43.037 0.234 44.491 ;
     RECT  0.216 44.491 0.414 44.669 ;
     RECT  0.216 44.669 0.234 44.765 ;
     RECT  74.664 44.827 74.682 45.292 ;
     RECT  74.628 45.292 74.682 45.293 ;
     RECT  2.304 42.701 73.314 45.437 ;
     RECT  74.628 45.293 74.646 45.533 ;
     RECT  74.628 46.795 74.646 46.841 ;
     RECT  2.304 45.437 73.242 46.891 ;
     RECT  2.304 46.891 73.35 47.117 ;
     RECT  0.54 47.191 0.558 47.281 ;
     RECT  2.412 47.117 73.35 47.357 ;
     RECT  2.415 47.357 73.35 47.425 ;
     RECT  0.504 47.281 0.558 47.623 ;
     RECT  2.415 47.425 73.566 47.645 ;
     RECT  74.556 47.083 74.574 47.755 ;
     RECT  74.556 47.755 74.646 47.885 ;
     RECT  2.415 47.645 73.314 48.091 ;
     RECT  0.468 47.623 0.558 48.605 ;
     RECT  2.304 48.091 73.314 48.811 ;
     RECT  2.304 48.811 73.566 48.973 ;
     RECT  74.556 47.885 74.574 49.001 ;
     RECT  2.268 48.973 73.566 49.051 ;
     RECT  0.216 48.973 0.234 49.085 ;
     RECT  2.268 49.051 73.602 49.109 ;
     RECT  74.628 49.513 74.646 49.565 ;
     RECT  2.304 49.109 73.602 49.577 ;
     RECT  74.124 49.855 74.574 49.901 ;
     RECT  2.304 49.577 73.314 50.009 ;
     RECT  74.556 49.901 74.574 50.351 ;
     RECT  33.876 50.009 73.314 50.549 ;
     RECT  2.304 50.009 33.138 50.827 ;
     RECT  33.876 50.549 49.014 50.827 ;
     RECT  2.304 50.827 49.014 51.403 ;
     RECT  49.752 50.549 73.134 51.403 ;
     RECT  75.384 51.355 75.402 51.403 ;
     RECT  75.384 51.403 75.474 51.431 ;
     RECT  75.456 51.431 75.474 51.44 ;
     RECT  74.556 51.499 74.574 51.701 ;
     RECT  74.088 52.315 74.106 52.651 ;
     RECT  2.304 51.403 73.314 52.789 ;
     RECT  74.088 52.651 74.646 52.789 ;
     RECT  2.304 52.789 74.646 52.843 ;
     RECT  2.268 52.843 74.646 52.889 ;
     RECT  2.268 52.889 73.566 52.979 ;
     RECT  74.628 52.889 74.646 53.024 ;
     RECT  0.504 53.131 0.522 53.293 ;
     RECT  2.304 52.979 73.566 53.429 ;
     RECT  0.504 53.293 0.558 53.467 ;
     RECT  0.216 53.467 0.558 53.597 ;
     RECT  0.504 53.597 0.558 54.029 ;
     RECT  0.54 54.029 0.558 54.173 ;
     RECT  2.304 53.429 73.314 54.599 ;
     RECT  2.304 54.599 48.87 55.525 ;
     RECT  49.68 54.599 73.314 55.531 ;
     RECT  2.304 55.525 48.906 55.627 ;
     RECT  49.644 55.531 73.314 55.627 ;
     RECT  74.124 53.803 74.142 55.627 ;
     RECT  2.232 55.627 48.906 55.751 ;
     RECT  2.304 55.751 48.906 56.059 ;
     RECT  49.644 55.627 74.142 56.059 ;
     RECT  2.304 56.059 74.142 56.093 ;
     RECT  74.124 56.093 74.142 56.561 ;
     RECT  2.304 56.093 73.314 56.731 ;
     RECT  2.232 56.731 73.314 56.795 ;
     RECT  2.232 56.795 38.862 56.831 ;
     RECT  39.6 56.795 73.314 57.065 ;
     RECT  74.664 56.923 74.682 57.101 ;
     RECT  0.252 57.259 0.27 57.271 ;
     RECT  39.6 57.065 73.098 57.581 ;
     RECT  0.216 57.271 0.27 57.917 ;
     RECT  55.656 57.581 73.098 57.919 ;
     RECT  2.304 56.831 38.862 58.081 ;
     RECT  39.6 57.581 54.882 58.081 ;
     RECT  2.304 58.081 54.882 58.423 ;
     RECT  55.656 57.919 73.314 58.423 ;
     RECT  2.304 58.423 73.314 58.649 ;
     RECT  0.54 57.991 0.558 58.733 ;
     RECT  74.124 57.877 74.142 59.267 ;
     RECT  0.252 59.371 0.27 59.501 ;
     RECT  2.304 58.649 73.242 59.611 ;
     RECT  0.216 59.773 0.234 59.885 ;
     RECT  2.304 59.611 73.314 60.043 ;
     RECT  2.196 60.043 73.314 60.179 ;
     RECT  2.232 60.179 73.314 60.523 ;
     RECT  2.232 60.523 73.566 60.611 ;
     RECT  2.268 60.611 73.566 60.667 ;
     RECT  2.268 60.667 73.782 61.079 ;
     RECT  2.304 61.079 73.782 61.223 ;
     RECT  2.304 61.223 73.314 61.421 ;
     RECT  0.252 61.387 0.27 61.517 ;
     RECT  2.304 61.421 73.098 61.709 ;
     RECT  74.628 61.339 74.646 61.735 ;
     RECT  74.124 61.735 74.646 61.853 ;
     RECT  2.412 61.709 73.098 61.925 ;
     RECT  52.884 61.925 73.098 62.203 ;
     RECT  74.628 61.853 74.646 62.231 ;
     RECT  2.412 61.925 52.146 62.491 ;
     RECT  0.252 62.539 0.27 62.668 ;
     RECT  0.216 62.668 0.27 62.669 ;
     RECT  2.304 62.491 52.146 62.779 ;
     RECT  52.884 62.203 73.314 62.779 ;
     RECT  0.216 62.669 0.234 62.861 ;
     RECT  2.304 62.779 73.314 63.451 ;
     RECT  74.088 63.307 74.106 63.451 ;
     RECT  2.304 63.451 74.106 63.509 ;
     RECT  50.76 63.509 74.106 63.553 ;
     RECT  50.76 63.553 74.142 63.677 ;
     RECT  74.088 63.677 74.142 63.689 ;
     RECT  74.124 63.689 74.142 63.821 ;
     RECT  74.556 63.931 74.646 64.109 ;
     RECT  2.304 63.509 49.986 64.357 ;
     RECT  50.76 63.677 73.314 64.357 ;
     RECT  74.556 64.109 74.574 64.391 ;
     RECT  2.304 64.357 73.314 64.741 ;
     RECT  2.268 64.741 73.314 64.781 ;
     RECT  2.304 64.781 73.314 64.859 ;
     RECT  20.376 64.859 31.158 64.967 ;
     RECT  31.896 64.859 73.314 65.273 ;
     RECT  2.304 64.859 19.53 65.707 ;
     RECT  2.304 65.707 19.71 65.749 ;
     RECT  20.484 64.967 31.158 65.749 ;
     RECT  31.896 65.273 73.242 65.749 ;
     RECT  2.304 65.749 73.242 66.091 ;
     RECT  2.304 66.091 73.602 66.571 ;
     RECT  2.304 66.571 74.142 66.623 ;
     RECT  0.216 65.899 0.234 66.749 ;
     RECT  74.124 66.623 74.142 66.907 ;
     RECT  74.124 66.907 74.682 67.091 ;
     RECT  2.304 66.623 73.314 67.297 ;
     RECT  74.556 67.091 74.682 67.361 ;
     RECT  2.196 67.297 73.314 67.421 ;
     RECT  2.304 67.421 73.314 67.631 ;
     RECT  74.556 67.361 74.646 68.059 ;
     RECT  74.52 68.059 74.646 68.237 ;
     RECT  2.304 67.631 73.242 68.719 ;
     RECT  2.304 68.719 73.314 68.791 ;
     RECT  2.304 68.791 73.494 68.909 ;
     RECT  0.54 68.791 0.558 69.053 ;
     RECT  74.628 68.237 74.646 69.295 ;
     RECT  74.124 69.295 74.646 69.331 ;
     RECT  19.944 68.909 73.314 69.341 ;
     RECT  74.124 69.331 74.682 69.389 ;
     RECT  19.944 69.341 73.242 69.449 ;
     RECT  74.664 69.389 74.682 69.725 ;
     RECT  2.304 68.909 19.17 70.033 ;
     RECT  19.944 69.449 73.098 70.033 ;
     RECT  2.304 70.033 73.098 70.411 ;
     RECT  2.304 70.411 73.242 70.6 ;
     RECT  2.304 70.6 73.314 70.637 ;
     RECT  2.304 70.637 73.098 70.835 ;
     RECT  0.54 71.221 0.558 71.357 ;
     RECT  55.224 70.835 73.098 71.419 ;
     RECT  2.304 70.835 54.342 71.761 ;
     RECT  55.224 71.419 73.314 71.761 ;
     RECT  2.304 71.761 73.314 71.788 ;
     RECT  2.268 71.788 73.314 71.803 ;
     RECT  2.268 71.803 73.566 71.879 ;
     RECT  2.304 71.879 73.566 72.293 ;
     RECT  2.304 72.293 73.314 72.419 ;
     RECT  0.504 72.661 0.522 72.733 ;
     RECT  0.504 72.733 0.558 72.989 ;
     RECT  0.504 72.989 0.522 73.133 ;
     RECT  55.08 72.419 73.314 73.195 ;
     RECT  2.304 72.419 54.162 73.309 ;
     RECT  55.044 73.195 73.314 73.309 ;
     RECT  74.124 72.955 74.142 74.107 ;
     RECT  74.124 74.107 74.178 74.111 ;
     RECT  0.216 74.011 0.234 74.141 ;
     RECT  74.16 74.111 74.178 74.381 ;
     RECT  2.304 73.309 73.314 74.621 ;
     RECT  0.216 75.067 0.234 75.197 ;
     RECT  2.412 74.621 73.314 75.389 ;
     RECT  58.428 75.389 73.314 75.403 ;
     RECT  2.412 75.389 57.654 75.547 ;
     RECT  58.428 75.403 73.566 75.739 ;
     RECT  75.384 75.883 75.402 75.901 ;
     RECT  2.304 75.547 57.654 76.243 ;
     RECT  58.428 75.739 74.142 76.243 ;
     RECT  0.216 76.363 0.234 76.493 ;
     RECT  75.384 75.901 75.474 76.541 ;
     RECT  75.384 76.541 75.402 76.589 ;
     RECT  2.304 76.243 74.142 76.613 ;
     RECT  74.124 76.613 74.142 76.733 ;
     RECT  2.304 76.613 73.314 77.117 ;
     RECT  2.304 77.117 32.706 77.279 ;
     RECT  33.444 77.117 73.314 77.665 ;
     RECT  0.216 77.611 0.234 77.741 ;
     RECT  33.444 77.665 73.53 77.741 ;
     RECT  2.304 77.279 32.634 78.097 ;
     RECT  33.444 77.741 73.314 78.097 ;
     RECT  2.304 78.097 73.314 78.197 ;
     RECT  2.304 78.197 51.894 78.331 ;
     RECT  2.268 78.331 51.894 78.467 ;
     RECT  52.884 78.197 73.314 79.051 ;
     RECT  52.848 79.051 73.314 79.147 ;
     RECT  52.776 79.147 73.746 79.195 ;
     RECT  2.304 78.467 51.894 79.285 ;
     RECT  52.704 79.195 73.746 79.285 ;
     RECT  74.628 78.811 74.646 79.511 ;
     RECT  2.304 79.285 73.746 79.583 ;
     RECT  0.216 78.601 0.234 79.997 ;
     RECT  74.556 79.963 74.574 80.779 ;
     RECT  1.152 80.833 1.17 80.933 ;
     RECT  2.304 79.583 73.314 80.971 ;
     RECT  74.556 80.779 74.646 81.131 ;
     RECT  2.268 80.971 73.314 81.329 ;
     RECT  0.216 80.905 0.234 81.485 ;
     RECT  2.304 81.329 73.314 81.931 ;
     RECT  74.124 81.451 74.142 81.931 ;
     RECT  2.304 81.931 74.142 82.517 ;
     RECT  2.304 82.517 73.314 82.588 ;
     RECT  2.268 82.588 73.314 82.679 ;
     RECT  74.124 82.517 74.142 83.021 ;
     RECT  2.304 82.679 73.314 83.069 ;
     RECT  0.216 83.191 0.234 83.261 ;
     RECT  0.54 83.569 0.558 83.933 ;
     RECT  2.304 83.069 73.242 83.939 ;
     RECT  2.304 83.939 48.654 84.181 ;
     RECT  49.5 83.939 73.242 84.181 ;
     RECT  2.268 84.181 48.654 84.272 ;
     RECT  49.5 84.181 73.314 84.571 ;
     RECT  2.304 84.272 48.654 84.721 ;
     RECT  49.5 84.571 73.53 84.721 ;
     RECT  2.304 84.721 73.53 85.085 ;
     RECT  2.412 85.085 73.53 85.181 ;
     RECT  2.412 85.181 73.242 85.867 ;
     RECT  2.304 85.867 73.242 86.881 ;
     RECT  2.304 86.881 73.314 86.909 ;
     RECT  74.556 86.347 74.574 87.071 ;
     RECT  2.304 86.909 52.434 87.691 ;
     RECT  53.172 86.909 73.314 87.691 ;
     RECT  74.628 87.835 74.646 87.965 ;
     RECT  2.304 87.691 73.314 88.507 ;
     RECT  2.304 88.507 73.602 88.619 ;
     RECT  2.415 88.619 73.602 88.655 ;
     RECT  3.924 88.655 73.602 88.727 ;
     RECT  3.924 88.727 73.314 88.763 ;
     RECT  4.572 88.763 73.314 88.889 ;
     RECT  4.572 88.889 51.462 89.465 ;
     RECT  23.292 89.465 51.462 89.507 ;
     RECT  4.572 89.465 22.518 89.843 ;
     RECT  4.572 89.843 19.494 89.851 ;
     RECT  34.704 89.507 51.462 89.851 ;
     RECT  52.236 88.889 73.314 89.851 ;
     RECT  4.5 89.851 19.494 89.969 ;
     RECT  34.704 89.851 73.314 89.969 ;
     RECT  52.056 89.969 73.314 90.005 ;
     RECT  52.92 90.005 73.314 90.077 ;
     RECT  4.5 89.969 19.422 90.149 ;
     RECT  20.268 89.843 22.518 90.187 ;
     RECT  23.292 89.507 33.93 90.187 ;
     RECT  4.5 90.149 9.558 90.235 ;
     RECT  4.356 90.235 9.558 90.239 ;
     RECT  10.332 90.149 19.422 90.239 ;
     RECT  20.268 90.187 33.93 90.239 ;
     RECT  34.704 89.969 51.297 90.239 ;
     RECT  52.056 90.005 52.074 90.239 ;
     RECT  52.992 90.077 73.314 90.239 ;
     RECT  9.252 90.239 9.378 90.275 ;
     RECT  20.268 90.239 22.446 90.275 ;
     RECT  23.256 90.239 30.438 90.275 ;
     RECT  34.704 90.239 46.17 90.275 ;
     RECT  47.34 90.239 49.518 90.275 ;
     RECT  31.536 90.239 33.93 90.331 ;
     RECT  34.704 90.275 38.97 90.331 ;
     RECT  10.332 90.239 19.242 90.347 ;
     RECT  20.952 90.275 22.446 90.347 ;
     RECT  39.96 90.275 43.197 90.347 ;
     RECT  52.992 90.239 73.242 90.365 ;
     RECT  31.536 90.331 38.97 90.383 ;
     RECT  47.34 90.275 49.266 90.383 ;
     RECT  10.332 90.347 19.062 90.419 ;
     RECT  21.096 90.347 22.446 90.419 ;
     RECT  63.216 90.365 73.242 90.419 ;
     RECT  2.415 88.655 2.697 90.467 ;
     RECT  12.06 90.419 18.897 90.467 ;
     RECT  39.996 90.347 43.197 90.467 ;
     RECT  50.292 90.239 51.297 90.467 ;
     RECT  4.356 90.239 8.334 90.509 ;
     RECT  9.252 90.275 9.342 90.509 ;
     RECT  10.332 90.419 11.322 90.509 ;
     RECT  12.06 90.467 18.774 90.509 ;
     RECT  21.096 90.419 21.654 90.509 ;
     RECT  23.328 90.275 25.11 90.509 ;
     RECT  26.1 90.275 30.294 90.509 ;
     RECT  31.536 90.383 36.702 90.509 ;
     RECT  37.476 90.383 38.97 90.509 ;
     RECT  44.424 90.275 46.17 90.509 ;
     RECT  47.34 90.383 47.502 90.509 ;
     RECT  48.276 90.383 49.266 90.509 ;
     RECT  50.292 90.467 51.105 90.509 ;
     RECT  52.992 90.365 62.478 90.509 ;
     RECT  63.252 90.419 73.242 90.509 ;
     RECT  4.356 90.509 4.374 90.545 ;
     RECT  5.115 90.509 6.318 90.545 ;
     RECT  9.252 90.509 9.27 90.545 ;
     RECT  10.332 90.509 10.962 90.545 ;
     RECT  15.444 90.509 16.005 90.545 ;
     RECT  21.096 90.509 21.474 90.545 ;
     RECT  28.656 90.509 30.222 90.545 ;
     RECT  32.115 90.509 33.57 90.545 ;
     RECT  39.996 90.467 43.005 90.545 ;
     RECT  44.424 90.509 44.442 90.545 ;
     RECT  45.615 90.509 46.17 90.545 ;
     RECT  47.34 90.509 47.358 90.545 ;
     RECT  48.315 90.509 49.05 90.545 ;
     RECT  50.436 90.509 51.105 90.545 ;
     RECT  52.992 90.509 53.805 90.545 ;
     RECT  56.415 90.509 57.402 90.545 ;
     RECT  63.324 90.509 65.754 90.545 ;
     RECT  66.672 90.509 71.838 90.545 ;
     RECT  72.615 90.509 73.17 90.545 ;
     RECT  7.416 90.509 7.905 90.557 ;
     RECT  12.636 90.509 13.914 90.557 ;
     RECT  18.108 90.509 18.705 90.557 ;
     RECT  26.1 90.509 27.414 90.557 ;
     RECT  34.416 90.509 36.558 90.557 ;
     RECT  37.515 90.509 37.674 90.557 ;
     RECT  12.636 90.557 13.305 90.568 ;
     RECT  17.028 90.509 17.046 90.568 ;
     RECT  26.1 90.557 26.805 90.568 ;
     RECT  24.015 90.509 25.074 90.581 ;
     RECT  66.672 90.545 70.758 90.605 ;
     RECT  6.3 90.545 6.318 90.617 ;
     RECT  28.836 90.545 29.505 90.617 ;
     RECT  32.115 90.545 32.562 90.617 ;
     RECT  36.036 90.557 36.054 90.617 ;
     RECT  40.215 90.545 40.662 90.617 ;
     RECT  42.3 90.545 43.005 90.617 ;
     RECT  55.548 90.509 55.566 90.617 ;
     RECT  58.608 90.509 62.406 90.617 ;
     RECT  63.792 90.545 65.538 90.617 ;
     RECT  67.068 90.605 67.842 90.617 ;
     RECT  68.724 90.605 70.005 90.617 ;
     RECT  70.74 90.605 70.758 90.617 ;
     RECT  72.615 90.545 72.774 90.617 ;
     RECT  64.515 90.617 65.358 90.653 ;
     RECT  45.615 90.545 45.774 90.689 ;
     RECT  58.86 90.617 59.205 90.689 ;
     RECT  60.3 90.617 60.318 90.689 ;
     RECT  61.164 90.617 62.406 90.689 ;
     RECT  2.415 90.467 2.505 90.737 ;
     RECT  5.115 90.545 5.205 90.737 ;
     RECT  7.815 90.557 7.905 90.737 ;
     RECT  10.515 90.545 10.605 90.737 ;
     RECT  13.215 90.568 13.305 90.737 ;
     RECT  15.915 90.545 16.005 90.737 ;
     RECT  18.615 90.557 18.705 90.737 ;
     RECT  21.315 90.545 21.405 90.737 ;
     RECT  24.015 90.581 24.105 90.737 ;
     RECT  26.715 90.568 26.805 90.737 ;
     RECT  29.415 90.617 29.505 90.737 ;
     RECT  32.115 90.617 32.205 90.737 ;
     RECT  34.815 90.557 34.905 90.737 ;
     RECT  37.515 90.557 37.605 90.737 ;
     RECT  40.215 90.617 40.305 90.737 ;
     RECT  42.915 90.617 43.005 90.737 ;
     RECT  45.615 90.689 45.705 90.737 ;
     RECT  48.315 90.545 48.405 90.737 ;
     RECT  51.015 90.545 51.105 90.737 ;
     RECT  53.715 90.545 53.805 90.737 ;
     RECT  56.415 90.545 56.505 90.737 ;
     RECT  59.115 90.689 59.205 90.737 ;
     RECT  61.815 90.689 61.905 90.737 ;
     RECT  64.515 90.653 64.605 90.737 ;
     RECT  67.215 90.617 67.305 90.737 ;
     RECT  69.915 90.617 70.005 90.737 ;
     RECT  72.615 90.617 72.705 90.737 ;
    LAYER M4 ;
     RECT  0.156 4.416 2.408 88.536 ;
     RECT  2.408 2.148 2.512 90.732 ;
     RECT  2.512 2.418 2.704 90.462 ;
     RECT  2.704 17.472 2.837 34.248 ;
     RECT  2.704 35.328 2.837 87.24 ;
     RECT  2.837 76.416 2.981 87.24 ;
     RECT  2.837 39.552 3.347 75.24 ;
     RECT  2.704 88.224 3.557 88.248 ;
     RECT  2.704 15.072 3.697 16.2 ;
     RECT  2.981 77.712 3.697 87.24 ;
     RECT  3.697 15.024 3.733 16.2 ;
     RECT  2.837 17.472 3.733 20.04 ;
     RECT  2.837 24.384 3.733 34.248 ;
     RECT  2.837 35.328 3.733 38.424 ;
     RECT  3.733 24.384 3.773 38.424 ;
     RECT  2.837 21.072 3.805 23.16 ;
     RECT  3.773 24.384 3.805 28.44 ;
     RECT  3.347 39.552 3.805 69.768 ;
     RECT  3.733 15.024 3.841 20.04 ;
     RECT  3.805 21.072 3.841 28.44 ;
     RECT  3.773 29.568 3.877 38.424 ;
     RECT  3.805 39.456 3.877 69.768 ;
     RECT  3.841 15.024 4.097 28.44 ;
     RECT  3.347 70.8 4.273 75.24 ;
     RECT  2.981 76.416 4.273 76.728 ;
     RECT  3.697 77.712 4.273 87.96 ;
     RECT  4.309 2.304 4.405 2.328 ;
     RECT  3.877 29.568 4.633 69.768 ;
     RECT  4.273 70.8 4.633 87.96 ;
     RECT  2.704 3.84 4.705 13.896 ;
     RECT  4.097 15.024 4.705 23.928 ;
     RECT  4.345 90.24 4.748 90.264 ;
     RECT  4.748 89.472 4.777 90.264 ;
     RECT  4.633 29.568 4.813 87.96 ;
     RECT  4.777 88.944 4.813 90.264 ;
     RECT  4.097 25.008 4.981 28.44 ;
     RECT  4.813 29.568 4.981 90.264 ;
     RECT  4.405 2.304 5.108 2.376 ;
     RECT  4.705 3.84 5.108 23.928 ;
     RECT  4.981 25.008 5.108 90.264 ;
     RECT  5.108 2.148 5.212 90.732 ;
     RECT  5.212 2.256 5.404 90.462 ;
     RECT  5.404 2.256 5.699 90.264 ;
     RECT  5.699 3.696 6.221 90.264 ;
     RECT  5.699 2.304 6.473 2.52 ;
     RECT  6.221 3.696 7.189 79.032 ;
     RECT  6.221 80.064 7.189 90.264 ;
     RECT  7.189 3.696 7.333 90.264 ;
     RECT  7.333 3.408 7.405 90.264 ;
     RECT  6.473 2.304 7.808 2.376 ;
     RECT  7.405 3.408 7.808 90.552 ;
     RECT  7.808 2.148 7.912 90.732 ;
     RECT  7.912 2.304 9.385 90.552 ;
     RECT  9.385 2.256 9.389 90.552 ;
     RECT  9.389 2.256 10.508 89.496 ;
     RECT  9.389 90.528 10.508 90.552 ;
     RECT  10.508 2.148 10.612 90.732 ;
     RECT  10.612 2.304 10.804 90.552 ;
     RECT  10.804 12.24 11.411 90.552 ;
     RECT  10.804 2.304 11.869 11.256 ;
     RECT  11.411 12.24 11.869 90.36 ;
     RECT  11.869 2.304 12.625 90.36 ;
     RECT  12.625 2.304 13.208 90.552 ;
     RECT  13.208 2.148 13.312 90.732 ;
     RECT  13.312 2.304 13.925 90.552 ;
     RECT  13.925 2.304 14.033 90.168 ;
     RECT  14.033 2.304 15.217 88.968 ;
     RECT  14.033 89.952 15.217 90.168 ;
     RECT  15.217 2.304 15.908 90.168 ;
     RECT  15.908 2.148 16.012 90.732 ;
     RECT  16.012 2.304 16.553 90.462 ;
     RECT  16.553 2.304 16.985 88.776 ;
     RECT  16.553 90.048 17.017 90.462 ;
     RECT  17.017 90.048 18.097 90.552 ;
     RECT  16.985 2.304 18.608 88.536 ;
     RECT  18.097 90 18.608 90.552 ;
     RECT  18.608 2.148 18.712 90.732 ;
     RECT  18.712 2.304 18.904 90.462 ;
     RECT  18.904 2.304 19.389 90.024 ;
     RECT  19.389 2.304 19.433 89.544 ;
     RECT  19.433 2.304 19.685 89.496 ;
     RECT  19.685 21.12 19.829 89.496 ;
     RECT  19.685 2.304 20.045 20.04 ;
     RECT  19.829 21.216 20.081 89.496 ;
     RECT  20.045 3.36 20.869 20.04 ;
     RECT  20.081 21.216 20.869 35.304 ;
     RECT  20.081 36.288 21.013 89.496 ;
     RECT  21.02 0.144 21.107 0.168 ;
     RECT  20.045 2.304 21.157 2.376 ;
     RECT  20.869 3.36 21.157 35.304 ;
     RECT  21.013 36.288 21.157 90.072 ;
     RECT  21.157 2.304 21.308 90.072 ;
     RECT  21.308 2.148 21.412 90.732 ;
     RECT  21.412 2.304 21.604 90.462 ;
     RECT  21.604 2.304 21.629 90.072 ;
     RECT  21.629 2.304 22.451 89.496 ;
     RECT  22.451 3.936 23.137 89.496 ;
     RECT  23.137 3.936 23.245 90.216 ;
     RECT  22.451 2.304 23.425 2.856 ;
     RECT  23.245 3.936 23.425 90.264 ;
     RECT  23.425 2.304 24.008 90.264 ;
     RECT  24.008 2.148 24.112 90.732 ;
     RECT  24.112 2.304 24.304 90.462 ;
     RECT  24.304 2.304 24.467 90.264 ;
     RECT  24.467 2.304 24.473 90.072 ;
     RECT  24.473 2.304 24.869 2.856 ;
     RECT  24.473 3.888 25.193 90.072 ;
     RECT  25.193 90 26.089 90.072 ;
     RECT  24.869 2.304 26.437 2.376 ;
     RECT  25.193 3.888 26.437 89.016 ;
     RECT  26.437 2.304 26.521 89.016 ;
     RECT  26.089 90 26.521 90.552 ;
     RECT  26.521 2.304 26.708 90.552 ;
     RECT  26.708 2.148 26.812 90.732 ;
     RECT  26.812 2.304 27.425 90.552 ;
     RECT  27.425 2.304 29.408 90.024 ;
     RECT  29.408 2.148 29.512 90.732 ;
     RECT  29.512 2.304 29.704 90.462 ;
     RECT  29.704 4.128 30.449 90.072 ;
     RECT  29.704 2.304 30.668 2.664 ;
     RECT  30.449 4.128 30.668 90.024 ;
     RECT  30.668 2.304 30.697 90.024 ;
     RECT  30.697 2.256 30.781 90.024 ;
     RECT  30.781 2.304 31.525 90.024 ;
     RECT  31.525 2.304 32.108 90.36 ;
     RECT  32.108 2.148 32.212 90.732 ;
     RECT  32.212 2.304 32.404 90.462 ;
     RECT  32.404 2.304 34.405 90.36 ;
     RECT  34.405 2.304 34.808 90.552 ;
     RECT  34.808 2.148 34.912 90.732 ;
     RECT  34.912 2.304 37.508 90.552 ;
     RECT  37.508 2.148 37.612 90.732 ;
     RECT  37.612 2.256 37.685 90.552 ;
     RECT  37.685 2.256 37.804 90.462 ;
     RECT  37.804 2.256 40.208 90.072 ;
     RECT  40.208 2.148 40.312 90.732 ;
     RECT  40.312 2.256 42.397 90.504 ;
     RECT  42.397 2.256 42.908 90.552 ;
     RECT  42.908 2.148 43.012 90.732 ;
     RECT  43.012 2.304 43.985 90.552 ;
     RECT  43.985 2.304 44.108 3.144 ;
     RECT  44.108 2.256 44.195 3.144 ;
     RECT  44.195 2.304 45.421 3.144 ;
     RECT  43.985 4.128 45.421 90.552 ;
     RECT  45.421 2.304 45.608 90.552 ;
     RECT  45.608 2.148 45.712 90.732 ;
     RECT  45.712 2.304 46.115 90.552 ;
     RECT  46.115 2.304 46.163 90.264 ;
     RECT  46.163 2.304 46.253 90.072 ;
     RECT  46.253 2.304 47.329 90.024 ;
     RECT  47.329 2.304 48.308 90.264 ;
     RECT  48.308 2.148 48.412 90.732 ;
     RECT  48.412 2.304 48.604 90.462 ;
     RECT  48.604 2.304 49.529 90.264 ;
     RECT  49.529 2.304 50.149 90.072 ;
     RECT  50.149 2.064 51.008 90.072 ;
     RECT  51.008 2.064 51.112 90.732 ;
     RECT  51.112 2.064 52.213 90.462 ;
     RECT  52.213 2.064 53.708 90.504 ;
     RECT  53.708 2.064 53.812 90.732 ;
     RECT  53.812 2.064 54.004 90.462 ;
     RECT  54.004 2.064 55.069 90.024 ;
     RECT  55.069 2.064 56.293 90.072 ;
     RECT  56.293 2.064 56.408 90.312 ;
     RECT  56.408 2.064 56.512 90.732 ;
     RECT  56.512 2.064 56.86 90.504 ;
     RECT  56.86 2.064 57.013 90.408 ;
     RECT  57.013 1.968 58.597 90.408 ;
     RECT  58.597 1.968 59.108 90.6 ;
     RECT  59.108 1.968 59.212 90.732 ;
     RECT  59.212 1.968 61.573 90.6 ;
     RECT  61.573 1.92 61.808 90.6 ;
     RECT  61.808 1.92 61.912 90.732 ;
     RECT  61.912 1.92 63.641 90.6 ;
     RECT  63.641 2.016 64.508 90.6 ;
     RECT  64.508 2.016 64.612 90.732 ;
     RECT  64.612 2.016 65.077 90.648 ;
     RECT  65.077 1.872 65.369 90.648 ;
     RECT  65.369 1.872 65.473 90.6 ;
     RECT  65.473 1.776 67.208 90.6 ;
     RECT  67.208 1.776 67.312 90.732 ;
     RECT  67.312 1.776 67.565 90.648 ;
     RECT  67.565 1.824 68.051 90.648 ;
     RECT  68.051 1.824 69.545 90.6 ;
     RECT  69.545 1.968 69.908 90.6 ;
     RECT  69.908 1.968 70.012 90.732 ;
     RECT  70.012 1.968 70.337 90.6 ;
     RECT  70.337 2.016 70.733 90.6 ;
     RECT  70.733 2.016 72.608 90.408 ;
     RECT  72.608 2.016 72.712 90.732 ;
     RECT  72.712 2.016 72.904 90.462 ;
     RECT  72.904 2.016 73.043 90.36 ;
     RECT  73.043 2.016 73.091 90.264 ;
     RECT  73.091 2.064 73.139 90.264 ;
     RECT  73.139 2.064 73.325 90.12 ;
     RECT  73.325 2.064 73.379 90.072 ;
     RECT  73.379 2.16 73.475 90.072 ;
     RECT  73.475 2.256 73.763 90.072 ;
     RECT  73.763 2.256 73.811 3.432 ;
     RECT  73.763 4.416 73.811 90.072 ;
     RECT  73.811 2.832 74.003 3.432 ;
     RECT  74.003 3.312 74.051 3.432 ;
     RECT  73.811 90.048 74.051 90.072 ;
     RECT  74.051 3.408 74.099 3.432 ;
     RECT  73.811 4.416 74.099 89.016 ;
     RECT  74.099 4.416 75.42 88.536 ;
     RECT  75.42 24.144 75.485 24.168 ;
     RECT  75.42 51.408 75.485 51.432 ;
     RECT  75.42 75.936 75.485 76.536 ;
    LAYER M5 ;
     RECT  68.064 1.861 68.088 1.909 ;
     RECT  67.92 1.909 68.088 1.957 ;
     RECT  66.048 1.957 66.072 2.005 ;
     RECT  64.032 2.005 64.056 2.053 ;
     RECT  66.048 2.005 66.696 2.053 ;
     RECT  67.92 1.957 68.184 2.053 ;
     RECT  73.056 2.005 73.08 2.053 ;
     RECT  21.072 0.133 21.096 2.137 ;
     RECT  50.16 2.053 50.184 2.137 ;
     RECT  61.584 1.909 61.608 2.137 ;
     RECT  63.408 2.053 64.056 2.137 ;
     RECT  73.056 2.053 73.368 2.137 ;
     RECT  66.048 2.053 68.184 2.149 ;
     RECT  72.6 2.137 73.368 2.149 ;
     RECT  2.4 2.137 2.52 2.151 ;
     RECT  5.1 2.137 5.22 2.151 ;
     RECT  7.8 2.137 7.92 2.151 ;
     RECT  10.5 2.137 10.62 2.151 ;
     RECT  13.2 2.137 13.32 2.151 ;
     RECT  15.9 2.137 16.02 2.151 ;
     RECT  18.6 2.137 18.72 2.151 ;
     RECT  21.072 2.137 21.42 2.151 ;
     RECT  24 2.137 24.12 2.151 ;
     RECT  26.7 2.137 26.82 2.151 ;
     RECT  29.4 2.137 29.52 2.151 ;
     RECT  32.1 2.137 32.22 2.151 ;
     RECT  34.8 2.137 34.92 2.151 ;
     RECT  37.5 2.137 37.62 2.151 ;
     RECT  40.2 2.137 40.32 2.151 ;
     RECT  42.9 2.137 43.02 2.151 ;
     RECT  45.6 2.137 45.72 2.151 ;
     RECT  48.3 2.137 48.42 2.151 ;
     RECT  50.16 2.137 51.12 2.151 ;
     RECT  56.4 2.137 56.52 2.151 ;
     RECT  59.1 2.137 59.22 2.151 ;
     RECT  61.584 2.137 61.92 2.151 ;
     RECT  63.408 2.137 64.62 2.151 ;
     RECT  69.9 2.137 70.02 2.151 ;
     RECT  56.4 2.151 56.712 2.197 ;
     RECT  63.408 2.151 64.812 2.197 ;
     RECT  65.904 2.149 68.184 2.197 ;
     RECT  69.9 2.151 70.212 2.197 ;
     RECT  71.184 2.149 71.208 2.197 ;
     RECT  5.1 2.151 5.412 2.245 ;
     RECT  42.9 2.151 43.212 2.245 ;
     RECT  50.16 2.151 51.312 2.245 ;
     RECT  56.4 2.197 56.808 2.245 ;
     RECT  59.1 2.151 59.412 2.245 ;
     RECT  63.312 2.197 71.448 2.245 ;
     RECT  72.6 2.149 73.464 2.245 ;
     RECT  5.1 2.245 5.688 2.293 ;
     RECT  18.6 2.151 18.912 2.293 ;
     RECT  55.728 2.245 56.808 2.389 ;
     RECT  61.584 2.151 62.112 2.437 ;
     RECT  63.312 2.245 73.8 2.437 ;
     RECT  45.6 2.151 45.912 2.533 ;
     RECT  53.7 2.137 54.552 2.581 ;
     RECT  55.728 2.389 57.048 2.581 ;
     RECT  61.584 2.437 73.8 2.581 ;
     RECT  7.8 2.151 8.112 2.629 ;
     RECT  29.4 2.151 29.712 2.629 ;
     RECT  30.72 2.245 30.744 2.629 ;
     RECT  37.5 2.151 37.812 2.629 ;
     RECT  50.16 2.245 51.864 2.629 ;
     RECT  59.1 2.245 59.736 2.629 ;
     RECT  61.536 2.581 73.8 2.629 ;
     RECT  53.7 2.581 57.048 2.773 ;
     RECT  59.1 2.629 73.8 2.773 ;
     RECT  10.5 2.151 10.812 2.821 ;
     RECT  21.072 2.151 21.612 2.821 ;
     RECT  34.8 2.151 35.112 2.821 ;
     RECT  37.392 2.629 37.812 2.821 ;
     RECT  40.2 2.151 40.512 2.821 ;
     RECT  53.328 2.773 57.048 2.821 ;
     RECT  58.512 2.773 73.8 2.821 ;
     RECT  45.6 2.533 46.728 2.869 ;
     RECT  58.512 2.821 73.992 2.965 ;
     RECT  13.2 2.151 13.512 3.157 ;
     RECT  26.7 2.151 27.012 3.157 ;
     RECT  34.56 2.821 35.112 3.157 ;
     RECT  40.08 2.821 40.512 3.157 ;
     RECT  41.568 2.821 41.592 3.157 ;
     RECT  58.128 2.965 73.992 3.301 ;
     RECT  18.24 2.293 18.912 3.397 ;
     RECT  19.968 3.157 19.992 3.397 ;
     RECT  21.072 2.821 22.44 3.397 ;
     RECT  24 2.151 24.312 3.397 ;
     RECT  29.4 2.629 30.744 3.397 ;
     RECT  32.1 2.151 32.412 3.397 ;
     RECT  58.128 3.301 74.04 3.397 ;
     RECT  40.08 3.157 41.592 3.443 ;
     RECT  50.112 2.629 51.864 3.443 ;
     RECT  50.16 3.443 51.864 3.635 ;
     RECT  10.5 2.821 10.92 3.685 ;
     RECT  18 3.397 18.912 3.829 ;
     RECT  37.392 2.821 38.232 3.875 ;
     RECT  40.08 3.443 40.968 3.877 ;
     RECT  53.04 2.821 57.048 3.877 ;
     RECT  7.8 2.629 8.232 3.925 ;
     RECT  45.6 2.869 47.016 3.925 ;
     RECT  48.3 2.151 48.612 3.925 ;
     RECT  53.04 3.877 57.096 3.925 ;
     RECT  58.128 3.397 74.088 3.925 ;
     RECT  37.5 3.875 38.232 3.971 ;
     RECT  13.2 3.157 13.704 3.973 ;
     RECT  15.9 2.151 16.212 3.973 ;
     RECT  17.568 3.829 18.912 3.973 ;
     RECT  23.712 3.397 24.312 4.117 ;
     RECT  14.736 3.157 14.76 4.165 ;
     RECT  15.9 3.973 18.912 4.165 ;
     RECT  14.736 4.165 18.912 4.213 ;
     RECT  19.92 3.397 22.44 4.213 ;
     RECT  29.4 3.397 32.412 4.213 ;
     RECT  26.448 3.157 27.144 4.261 ;
     RECT  14.736 4.213 22.44 4.307 ;
     RECT  42.9 2.245 44.184 4.307 ;
     RECT  23.712 4.117 24.744 4.501 ;
     RECT  29.184 4.213 32.412 4.501 ;
     RECT  29.184 4.501 33.144 4.645 ;
     RECT  23.52 4.501 24.744 4.741 ;
     RECT  39.312 3.877 40.968 4.789 ;
     RECT  23.52 4.741 25.128 4.979 ;
     RECT  13.104 3.973 13.704 4.981 ;
     RECT  23.52 4.979 24.648 5.027 ;
     RECT  34.56 3.157 35.88 5.123 ;
     RECT  4.32 2.293 5.688 5.171 ;
     RECT  52.608 3.925 74.088 5.221 ;
     RECT  15.9 4.307 22.44 5.269 ;
     RECT  23.52 5.027 24.312 5.269 ;
     RECT  15.9 5.269 24.312 5.315 ;
     RECT  6.72 4.837 6.744 5.317 ;
     RECT  7.8 3.925 9.096 5.317 ;
     RECT  6.72 5.317 9.096 5.363 ;
     RECT  29.184 4.645 33.192 5.365 ;
     RECT  50.16 3.635 51.312 5.365 ;
     RECT  52.32 5.221 74.088 5.365 ;
     RECT  15.9 5.315 21.612 5.461 ;
     RECT  14.736 4.307 14.76 5.557 ;
     RECT  15.792 5.461 21.612 5.557 ;
     RECT  37.5 3.971 37.992 5.605 ;
     RECT  39.312 4.789 41.16 5.605 ;
     RECT  42.9 4.307 43.8 5.653 ;
     RECT  14.736 5.557 21.612 5.747 ;
     RECT  42.144 5.653 43.8 5.747 ;
     RECT  29.136 5.365 33.192 5.749 ;
     RECT  34.56 5.123 35.4 5.795 ;
     RECT  29.088 5.749 33.192 5.797 ;
     RECT  37.5 5.605 41.16 5.845 ;
     RECT  42.144 5.747 43.656 5.845 ;
     RECT  26.256 4.261 27.144 5.989 ;
     RECT  37.5 5.845 43.656 6.035 ;
     RECT  34.8 5.795 35.4 6.133 ;
     RECT  50.16 5.365 74.088 6.133 ;
     RECT  10.5 3.685 11.736 6.229 ;
     RECT  45.6 3.925 48.612 6.229 ;
     RECT  14.736 5.747 19.992 6.371 ;
     RECT  45.6 6.229 48.744 6.373 ;
     RECT  50.16 6.133 74.376 6.373 ;
     RECT  26.208 5.989 27.144 6.421 ;
     RECT  4.368 5.171 5.688 6.515 ;
     RECT  28.8 5.797 33.192 6.563 ;
     RECT  50.112 6.373 74.376 6.757 ;
     RECT  38.832 6.035 43.656 6.805 ;
     RECT  44.976 6.373 48.744 6.805 ;
     RECT  38.832 6.805 48.744 6.851 ;
     RECT  6.816 5.363 9.096 6.899 ;
     RECT  34.8 6.133 35.784 6.899 ;
     RECT  39.408 6.851 48.744 6.899 ;
     RECT  37.5 6.035 37.812 6.901 ;
     RECT  4.368 6.515 5.544 6.947 ;
     RECT  6.96 6.899 9.096 6.995 ;
     RECT  34.8 6.899 35.4 7.091 ;
     RECT  23.28 5.315 24.312 7.141 ;
     RECT  5.1 6.947 5.544 7.283 ;
     RECT  50.112 6.757 74.472 7.285 ;
     RECT  15.552 6.371 19.992 7.333 ;
     RECT  23.28 7.141 24.408 7.379 ;
     RECT  37.392 6.901 37.812 7.379 ;
     RECT  2.4 2.151 2.712 7.381 ;
     RECT  28.8 6.563 33.144 7.427 ;
     RECT  15.36 7.333 19.992 7.475 ;
     RECT  39.456 6.899 48.744 7.619 ;
     RECT  17.568 7.475 19.992 7.621 ;
     RECT  21.072 5.747 21.612 7.621 ;
     RECT  23.712 7.379 24.408 7.861 ;
     RECT  26.112 6.421 27.144 7.861 ;
     RECT  37.5 7.379 37.812 7.861 ;
     RECT  41.616 7.619 48.744 7.861 ;
     RECT  50.016 7.285 74.472 7.861 ;
     RECT  15.36 7.475 16.584 7.955 ;
     RECT  17.568 7.621 21.72 7.955 ;
     RECT  23.712 7.861 27.144 7.955 ;
     RECT  10.224 6.229 11.736 7.957 ;
     RECT  12.912 4.981 13.704 7.957 ;
     RECT  10.224 7.957 13.704 8.003 ;
     RECT  15.36 7.955 16.536 8.003 ;
     RECT  39.456 7.619 40.632 8.051 ;
     RECT  20.592 7.955 21.72 8.099 ;
     RECT  23.712 7.955 25.272 8.099 ;
     RECT  10.5 8.003 13.704 8.195 ;
     RECT  2.4 7.381 3.624 8.291 ;
     RECT  28.8 7.427 33.048 8.291 ;
     RECT  12.672 8.195 13.704 8.293 ;
     RECT  37.5 7.861 38.136 8.341 ;
     RECT  5.1 7.283 5.412 8.389 ;
     RECT  6.96 6.995 8.808 8.389 ;
     RECT  23.712 8.099 24.312 8.389 ;
     RECT  41.616 7.861 74.472 8.435 ;
     RECT  28.8 8.291 29.712 8.437 ;
     RECT  30.912 8.291 33.048 8.437 ;
     RECT  34.8 7.091 35.352 8.437 ;
     RECT  4.512 8.389 5.412 8.533 ;
     RECT  44.448 8.435 74.472 8.677 ;
     RECT  17.568 7.955 19.416 8.723 ;
     RECT  17.568 8.723 17.592 8.963 ;
     RECT  15.744 8.003 16.536 8.965 ;
     RECT  39.888 8.051 40.632 8.965 ;
     RECT  41.616 8.435 43.212 8.965 ;
     RECT  30.912 8.437 33.192 9.155 ;
     RECT  6.96 8.389 9.24 9.301 ;
     RECT  10.5 8.195 11.4 9.301 ;
     RECT  4.512 8.533 5.64 9.347 ;
     RECT  23.136 8.389 24.312 9.349 ;
     RECT  25.632 8.965 25.656 9.349 ;
     RECT  44.448 8.677 74.664 9.491 ;
     RECT  6.96 9.301 11.4 9.539 ;
     RECT  30.912 9.155 30.936 9.539 ;
     RECT  10.5 9.539 11.4 9.685 ;
     RECT  52.368 9.491 74.664 9.731 ;
     RECT  15.408 8.965 16.536 9.781 ;
     RECT  18.6 8.723 19.416 9.781 ;
     RECT  4.512 9.347 5.412 9.925 ;
     RECT  34.8 8.437 35.88 10.019 ;
     RECT  44.448 9.491 51.312 10.019 ;
     RECT  44.448 10.019 46.776 10.067 ;
     RECT  23.136 9.349 25.656 10.069 ;
     RECT  26.7 7.955 27.144 10.069 ;
     RECT  28.176 8.437 29.712 10.115 ;
     RECT  39.888 8.965 43.212 10.115 ;
     RECT  12.672 8.293 13.992 10.165 ;
     RECT  31.92 9.155 33.192 10.211 ;
     RECT  23.136 10.069 27.144 10.213 ;
     RECT  52.368 9.731 74.616 10.307 ;
     RECT  37.5 8.341 38.616 10.309 ;
     RECT  20.832 8.099 21.72 10.355 ;
     RECT  23.04 10.213 27.144 10.403 ;
     RECT  40.08 10.115 43.212 10.499 ;
     RECT  52.368 10.307 74.424 10.595 ;
     RECT  18.6 9.781 19.8 10.645 ;
     RECT  52.368 10.595 55.368 10.691 ;
     RECT  25.632 10.403 27.144 10.741 ;
     RECT  28.176 10.115 28.2 10.741 ;
     RECT  31.968 10.211 33.192 10.741 ;
     RECT  45.216 10.067 46.776 10.787 ;
     RECT  6.96 9.539 9.24 10.835 ;
     RECT  3.792 9.925 5.412 10.883 ;
     RECT  10.5 9.685 11.592 10.883 ;
     RECT  29.184 10.115 29.712 10.885 ;
     RECT  23.04 10.403 24.312 10.931 ;
     RECT  37.5 10.309 38.712 10.931 ;
     RECT  40.2 10.499 43.212 10.931 ;
     RECT  47.808 10.019 51.312 10.933 ;
     RECT  31.968 10.741 33.288 10.979 ;
     RECT  18.48 10.645 19.8 10.981 ;
     RECT  20.832 10.355 21.612 10.981 ;
     RECT  31.968 10.979 33.192 11.075 ;
     RECT  56.4 10.595 74.424 11.315 ;
     RECT  25.632 10.741 28.2 11.411 ;
     RECT  34.8 10.019 35.688 11.411 ;
     RECT  29.184 10.885 30.504 11.459 ;
     RECT  37.5 10.931 38.616 11.459 ;
     RECT  47.808 10.933 51.672 11.459 ;
     RECT  29.184 11.459 30.264 11.461 ;
     RECT  3.792 10.883 3.816 11.507 ;
     RECT  41.616 10.931 43.212 11.509 ;
     RECT  12.672 10.165 14.136 11.555 ;
     RECT  52.8 10.691 55.368 11.651 ;
     RECT  40.2 10.931 40.512 11.653 ;
     RECT  29.088 11.461 30.264 11.747 ;
     RECT  25.632 11.411 27.912 11.795 ;
     RECT  53.424 11.651 55.368 11.843 ;
     RECT  50.016 11.459 51.672 11.845 ;
     RECT  53.7 11.843 55.368 11.845 ;
     RECT  56.4 11.315 74.376 11.845 ;
     RECT  50.016 11.845 51.768 11.893 ;
     RECT  12.912 11.555 14.136 11.939 ;
     RECT  24 10.931 24.312 11.941 ;
     RECT  31.968 11.075 32.412 11.941 ;
     RECT  25.92 11.795 27.912 12.083 ;
     RECT  29.184 11.747 30.264 12.083 ;
     RECT  15.408 9.781 17.496 12.227 ;
     RECT  15.408 12.227 16.824 12.371 ;
     RECT  18.48 10.981 21.612 12.371 ;
     RECT  10.5 10.883 11.016 12.469 ;
     RECT  29.4 12.083 30.264 12.469 ;
     RECT  5.1 10.883 5.412 12.517 ;
     RECT  23.52 11.941 24.312 12.517 ;
     RECT  41.616 11.509 44.04 12.563 ;
     RECT  9.216 10.835 9.24 12.611 ;
     RECT  47.808 11.459 48.984 12.661 ;
     RECT  50.016 11.893 52.392 12.661 ;
     RECT  40.08 11.653 40.512 12.709 ;
     RECT  39.936 12.709 40.512 12.757 ;
     RECT  6.96 10.835 8.232 12.805 ;
     RECT  45.216 10.787 46.632 12.805 ;
     RECT  4.992 12.517 5.412 12.853 ;
     RECT  6.96 12.805 8.328 13.091 ;
     RECT  45.12 12.805 46.632 13.091 ;
     RECT  41.856 12.563 44.04 13.235 ;
     RECT  12.912 11.939 13.512 13.331 ;
     RECT  45.6 13.091 46.632 13.379 ;
     RECT  15.408 12.371 16.212 13.477 ;
     RECT  25.92 12.083 27.012 13.477 ;
     RECT  18.48 12.371 18.912 13.573 ;
     RECT  19.968 12.371 21.612 13.573 ;
     RECT  47.808 12.661 52.392 13.573 ;
     RECT  53.7 11.845 74.376 13.573 ;
     RECT  18.384 13.573 18.912 13.717 ;
     RECT  19.968 13.573 22.2 13.717 ;
     RECT  13.056 13.331 13.512 13.763 ;
     RECT  10.5 12.469 11.112 13.811 ;
     RECT  34.8 11.411 35.352 13.861 ;
     RECT  29.4 12.469 30.84 13.957 ;
     RECT  31.92 11.941 32.412 13.957 ;
     RECT  28.08 13.333 28.104 14.101 ;
     RECT  29.4 13.957 32.412 14.101 ;
     RECT  47.808 13.573 74.376 14.149 ;
     RECT  41.856 13.235 43.212 14.197 ;
     RECT  37.5 11.459 38.232 14.243 ;
     RECT  14.784 13.477 16.212 14.435 ;
     RECT  28.08 14.101 32.412 14.437 ;
     RECT  25.632 13.477 27.012 14.531 ;
     RECT  23.28 12.517 24.312 14.581 ;
     RECT  25.632 14.531 25.656 14.581 ;
     RECT  37.5 14.243 37.992 14.675 ;
     RECT  47.712 14.149 74.376 14.675 ;
     RECT  23.28 14.581 25.656 14.723 ;
     RECT  28.032 14.437 32.412 14.723 ;
     RECT  4.848 12.853 5.412 14.725 ;
     RECT  6.96 13.091 8.28 14.725 ;
     RECT  26.7 14.531 27.012 14.725 ;
     RECT  28.032 14.723 30.264 14.725 ;
     RECT  10.5 13.811 11.064 14.773 ;
     RECT  45.6 13.379 46.248 14.867 ;
     RECT  41.856 14.197 43.992 14.963 ;
     RECT  9.696 14.773 11.064 15.059 ;
     RECT  18.384 13.717 22.2 15.205 ;
     RECT  23.28 14.723 24.312 15.205 ;
     RECT  4.848 14.725 5.64 15.301 ;
     RECT  25.632 14.723 25.656 15.395 ;
     RECT  52.896 14.675 74.376 15.395 ;
     RECT  33.504 12.901 33.528 15.443 ;
     RECT  6.96 14.725 8.328 15.491 ;
     RECT  4.848 15.301 5.688 15.493 ;
     RECT  2.4 8.291 2.712 15.541 ;
     RECT  3.984 15.493 5.688 15.541 ;
     RECT  18.384 15.205 24.312 15.589 ;
     RECT  37.5 14.675 37.944 15.731 ;
     RECT  17.568 15.589 24.312 15.875 ;
     RECT  34.8 13.861 35.736 15.877 ;
     RECT  39.264 12.757 40.512 15.877 ;
     RECT  9.696 15.059 10.812 15.925 ;
     RECT  26.7 14.725 30.264 15.973 ;
     RECT  47.712 14.675 51.864 15.973 ;
     RECT  52.896 15.395 73.848 15.973 ;
     RECT  2.4 15.541 5.688 16.019 ;
     RECT  34.8 15.877 36.216 16.019 ;
     RECT  20.736 15.875 24.312 16.067 ;
     RECT  45.6 14.867 46.2 16.115 ;
     RECT  34.8 16.019 35.112 16.117 ;
     RECT  47.712 15.973 73.848 16.211 ;
     RECT  9.456 15.925 10.812 16.357 ;
     RECT  47.712 16.211 73.608 16.453 ;
     RECT  39.264 15.877 40.632 16.499 ;
     RECT  6.96 15.491 8.232 16.501 ;
     RECT  20.736 16.067 21.912 16.547 ;
     RECT  41.856 14.963 43.212 16.547 ;
     RECT  34.656 16.117 35.112 16.549 ;
     RECT  26.496 15.973 30.264 16.595 ;
     RECT  31.92 14.723 32.412 16.595 ;
     RECT  47.664 16.453 73.608 16.595 ;
     RECT  40.2 16.499 40.632 16.597 ;
     RECT  42.72 16.547 43.212 16.597 ;
     RECT  42.72 16.597 43.368 16.645 ;
     RECT  44.496 16.501 44.52 16.645 ;
     RECT  37.5 15.731 37.812 16.693 ;
     RECT  36.192 16.019 36.216 16.741 ;
     RECT  37.2 16.693 37.812 16.741 ;
     RECT  26.7 16.595 30.264 16.835 ;
     RECT  36.192 16.741 37.812 16.835 ;
     RECT  42.72 16.645 44.52 16.883 ;
     RECT  37.056 16.835 37.812 16.931 ;
     RECT  3.936 16.019 5.688 16.933 ;
     RECT  6.864 16.501 8.232 16.933 ;
     RECT  15.36 14.435 16.212 16.933 ;
     RECT  17.568 15.875 19.032 16.933 ;
     RECT  15.36 16.933 19.032 16.979 ;
     RECT  42.768 16.883 44.52 16.979 ;
     RECT  3.936 16.933 8.232 17.029 ;
     RECT  13.2 13.763 13.512 17.077 ;
     RECT  45.6 16.115 46.152 17.077 ;
     RECT  15.36 16.979 17.16 17.123 ;
     RECT  9.456 16.357 11.4 17.171 ;
     RECT  15.456 17.123 16.212 17.267 ;
     RECT  42.768 16.979 43.368 17.267 ;
     RECT  25.44 15.973 25.464 17.315 ;
     RECT  40.2 16.597 41.496 17.315 ;
     RECT  9.84 17.171 11.4 17.507 ;
     RECT  20.736 16.547 21.612 17.509 ;
     RECT  3.936 17.029 8.424 17.603 ;
     RECT  13.056 17.077 14.28 17.605 ;
     RECT  26.7 16.835 27.012 17.605 ;
     RECT  28.224 16.835 30.264 17.605 ;
     RECT  40.2 17.315 40.824 17.605 ;
     RECT  31.968 16.595 32.412 17.699 ;
     RECT  23.376 16.067 24.312 17.701 ;
     RECT  45.6 17.077 46.68 17.845 ;
     RECT  47.664 16.595 48.612 17.845 ;
     RECT  42.768 17.267 43.212 17.939 ;
     RECT  22.8 17.701 24.312 17.987 ;
     RECT  34.176 16.549 35.112 17.989 ;
     RECT  9.984 17.507 11.4 18.133 ;
     RECT  13.056 17.605 14.376 18.133 ;
     RECT  18.384 16.979 19.032 18.133 ;
     RECT  20.112 17.509 21.612 18.133 ;
     RECT  5.1 17.603 8.424 18.181 ;
     RECT  23.328 17.987 24.312 18.181 ;
     RECT  34.176 17.989 35.208 18.181 ;
     RECT  18.384 18.133 21.612 18.275 ;
     RECT  9.984 18.133 14.376 18.371 ;
     RECT  42.9 17.939 43.212 18.469 ;
     RECT  39.84 17.605 40.824 18.515 ;
     RECT  15.792 17.267 16.212 18.661 ;
     RECT  44.448 16.979 44.52 18.661 ;
     RECT  45.6 17.845 48.612 18.661 ;
     RECT  23.328 18.181 24.456 18.709 ;
     RECT  49.824 16.595 73.608 18.757 ;
     RECT  15.456 18.661 16.212 18.803 ;
     RECT  5.1 18.181 8.76 18.851 ;
     RECT  15.792 18.803 16.212 18.851 ;
     RECT  7.8 18.851 8.76 18.853 ;
     RECT  9.984 18.371 14.28 18.853 ;
     RECT  23.328 18.709 25.128 18.899 ;
     RECT  44.448 18.661 48.612 18.899 ;
     RECT  23.472 18.899 25.128 18.947 ;
     RECT  7.8 18.853 14.28 19.043 ;
     RECT  45.072 18.899 48.612 19.043 ;
     RECT  48.3 19.043 48.612 19.141 ;
     RECT  49.824 18.757 73.8 19.141 ;
     RECT  45.072 19.043 46.968 19.235 ;
     RECT  42.9 18.469 43.32 19.237 ;
     RECT  28.224 17.605 30.84 19.333 ;
     RECT  32.1 17.699 32.412 19.333 ;
     RECT  37.104 16.931 37.812 19.333 ;
     RECT  20.832 18.275 21.612 19.381 ;
     RECT  3.936 17.603 4.056 19.427 ;
     RECT  9.984 19.043 14.28 19.475 ;
     RECT  9.984 19.475 13.608 19.523 ;
     RECT  42 19.237 43.32 19.525 ;
     RECT  15.9 18.851 16.212 19.573 ;
     RECT  4.032 19.427 4.056 19.619 ;
     RECT  28.224 19.333 32.412 19.621 ;
     RECT  37.008 19.333 37.812 19.907 ;
     RECT  18.384 18.275 19.272 19.909 ;
     RECT  14.784 19.621 14.808 20.003 ;
     RECT  7.8 19.043 8.904 20.053 ;
     RECT  28.224 19.621 33 20.147 ;
     RECT  42 19.525 43.656 20.147 ;
     RECT  23.472 18.947 24.456 20.149 ;
     RECT  26.208 17.605 27.012 20.149 ;
     RECT  28.224 20.147 29.928 20.149 ;
     RECT  37.104 19.907 37.812 20.149 ;
     RECT  39.84 18.515 40.512 20.149 ;
     RECT  31.344 20.147 33 20.197 ;
     RECT  34.176 18.181 35.88 20.197 ;
     RECT  15.9 19.573 16.536 20.291 ;
     RECT  45.072 19.235 46.632 20.291 ;
     RECT  39.84 20.149 41.16 20.339 ;
     RECT  23.088 20.149 24.456 20.435 ;
     RECT  25.68 20.149 27.012 20.435 ;
     RECT  42.288 20.147 43.656 20.435 ;
     RECT  31.344 20.197 35.88 20.531 ;
     RECT  48.3 19.141 73.8 20.579 ;
     RECT  40.08 20.339 41.16 20.627 ;
     RECT  10.368 19.523 13.608 20.677 ;
     RECT  20.784 19.381 21.612 20.677 ;
     RECT  10.368 20.677 13.656 20.723 ;
     RECT  37.104 20.149 38.328 20.725 ;
     RECT  23.088 20.435 24.312 20.915 ;
     RECT  31.344 20.531 35.112 20.915 ;
     RECT  15.9 20.291 16.212 20.965 ;
     RECT  10.368 20.723 11.688 21.061 ;
     RECT  28.032 20.149 29.928 21.107 ;
     RECT  32.1 20.915 35.112 21.107 ;
     RECT  10.176 21.061 11.688 21.155 ;
     RECT  7.8 20.053 8.952 21.253 ;
     RECT  42.9 20.435 43.656 21.397 ;
     RECT  37.104 20.725 39.048 21.443 ;
     RECT  49.824 20.579 73.8 21.443 ;
     RECT  18.384 19.909 19.704 21.491 ;
     RECT  49.824 21.443 73.272 21.491 ;
     RECT  5.1 18.851 6.264 21.637 ;
     RECT  26.208 20.435 27.012 21.637 ;
     RECT  28.032 21.107 29.832 21.637 ;
     RECT  48.3 20.579 48.744 21.637 ;
     RECT  40.2 20.627 41.16 21.683 ;
     RECT  42.9 21.397 43.8 21.877 ;
     RECT  45.6 20.291 46.632 21.877 ;
     RECT  13.104 20.723 13.656 21.923 ;
     RECT  32.1 21.107 32.412 21.925 ;
     RECT  26.208 21.637 29.832 21.971 ;
     RECT  45.456 21.877 46.632 21.973 ;
     RECT  48.192 21.637 48.744 22.021 ;
     RECT  15.408 20.965 16.212 22.165 ;
     RECT  48.192 22.021 48.792 22.165 ;
     RECT  49.824 21.491 73.224 22.165 ;
     RECT  48.192 22.165 73.224 22.259 ;
     RECT  10.176 21.155 10.812 22.307 ;
     RECT  42.9 21.877 44.424 22.309 ;
     RECT  4.176 21.637 6.264 22.499 ;
     RECT  17.232 21.925 17.256 22.499 ;
     RECT  26.352 21.971 29.832 22.549 ;
     RECT  13.104 21.923 13.608 22.597 ;
     RECT  18.384 21.491 19.608 22.597 ;
     RECT  20.784 20.677 21.72 22.597 ;
     RECT  42.72 22.309 44.424 22.739 ;
     RECT  23.472 20.915 24.312 22.741 ;
     RECT  45.456 21.973 46.776 22.741 ;
     RECT  48.192 22.259 49.848 22.741 ;
     RECT  36.096 21.493 36.12 22.787 ;
     RECT  18 22.597 19.608 22.835 ;
     RECT  31.968 21.925 32.412 22.835 ;
     RECT  47.856 22.741 49.848 22.835 ;
     RECT  51 22.259 73.224 22.835 ;
     RECT  40.2 21.683 40.92 22.883 ;
     RECT  47.856 22.835 48.792 22.931 ;
     RECT  34.176 21.107 35.112 23.029 ;
     RECT  23.184 22.741 24.312 23.125 ;
     RECT  26.352 22.549 30.024 23.125 ;
     RECT  10.5 22.307 10.812 23.269 ;
     RECT  26.352 23.125 30.792 23.315 ;
     RECT  51 22.835 73.176 23.315 ;
     RECT  7.488 21.253 8.952 23.317 ;
     RECT  10.368 23.269 10.812 23.317 ;
     RECT  26.7 23.315 30.792 23.363 ;
     RECT  42.72 22.739 43.608 23.459 ;
     RECT  44.976 22.741 46.776 23.509 ;
     RECT  47.856 22.931 48.612 23.509 ;
     RECT  20.784 22.597 21.768 23.557 ;
     RECT  23.184 23.125 24.408 23.557 ;
     RECT  33.984 23.029 35.112 23.557 ;
     RECT  20.784 23.557 24.408 23.699 ;
     RECT  33.984 23.557 35.688 23.699 ;
     RECT  52.656 23.315 73.176 23.747 ;
     RECT  7.488 23.317 10.812 23.845 ;
     RECT  12.24 22.597 13.608 23.845 ;
     RECT  22.8 23.699 24.408 23.891 ;
     RECT  33.984 23.699 35.592 23.939 ;
     RECT  7.488 23.845 13.608 23.987 ;
     RECT  44.976 23.509 48.612 23.987 ;
     RECT  20.784 23.699 21.768 24.131 ;
     RECT  37.104 21.443 38.328 24.131 ;
     RECT  23.472 23.891 24.408 24.229 ;
     RECT  18 22.835 18.912 24.371 ;
     RECT  23.472 24.229 24.648 24.419 ;
     RECT  26.7 23.363 30.744 24.419 ;
     RECT  9.696 23.987 13.608 24.421 ;
     RECT  30.72 24.419 30.744 24.421 ;
     RECT  32.1 22.835 32.412 24.421 ;
     RECT  45.6 23.987 48.612 24.421 ;
     RECT  49.824 22.835 49.848 24.421 ;
     RECT  23.904 24.419 24.648 24.469 ;
     RECT  25.632 24.277 25.656 24.469 ;
     RECT  26.7 24.419 29.712 24.469 ;
     RECT  52.656 23.747 73.08 24.563 ;
     RECT  51 23.315 51.432 24.613 ;
     RECT  52.656 24.563 72.912 24.613 ;
     RECT  30.72 24.421 32.412 24.659 ;
     RECT  33.984 23.939 35.496 24.707 ;
     RECT  9.696 24.421 14.136 24.757 ;
     RECT  15.12 22.165 16.212 24.757 ;
     RECT  45.6 24.421 49.848 24.851 ;
     RECT  9.696 24.757 16.212 24.899 ;
     RECT  42.9 23.459 43.608 24.901 ;
     RECT  23.904 24.469 29.712 24.995 ;
     RECT  5.1 22.499 6.264 24.997 ;
     RECT  7.488 23.987 8.112 24.997 ;
     RECT  10.368 24.899 16.212 25.139 ;
     RECT  24 24.995 29.712 25.139 ;
     RECT  33.984 24.707 35.112 25.139 ;
     RECT  26.7 25.139 29.712 25.187 ;
     RECT  25.632 25.139 25.656 25.235 ;
     RECT  5.1 24.997 8.112 25.237 ;
     RECT  40.2 22.883 40.512 25.285 ;
     RECT  10.5 25.139 16.212 25.429 ;
     RECT  17.328 25.333 17.352 25.429 ;
     RECT  10.5 25.429 17.352 25.475 ;
     RECT  18.384 24.371 18.912 25.475 ;
     RECT  18.6 25.475 18.912 25.525 ;
     RECT  20.784 24.131 21.612 25.525 ;
     RECT  51 24.613 72.912 25.573 ;
     RECT  37.104 24.131 37.812 25.621 ;
     RECT  10.5 25.475 13.608 25.667 ;
     RECT  4.992 25.237 8.112 25.715 ;
     RECT  39.552 25.285 40.632 25.715 ;
     RECT  47.424 24.851 49.848 25.715 ;
     RECT  40.2 25.715 40.632 25.717 ;
     RECT  26.7 25.187 27.624 25.763 ;
     RECT  40.2 25.717 40.824 25.813 ;
     RECT  41.856 25.717 41.88 25.813 ;
     RECT  40.2 25.813 41.88 26.147 ;
     RECT  31.344 24.659 32.412 26.149 ;
     RECT  10.5 25.667 11.544 26.197 ;
     RECT  41.616 26.147 41.88 26.197 ;
     RECT  42.9 24.901 43.896 26.197 ;
     RECT  18.6 25.525 21.612 26.291 ;
     RECT  24 25.139 24.648 26.341 ;
     RECT  28.608 25.187 29.712 26.341 ;
     RECT  34.8 25.139 35.112 26.341 ;
     RECT  23.376 26.341 24.648 26.389 ;
     RECT  31.344 26.149 32.808 26.435 ;
     RECT  23.04 26.389 24.648 26.437 ;
     RECT  28.608 26.341 30.312 26.531 ;
     RECT  15.072 25.475 17.352 26.533 ;
     RECT  18.6 26.291 19.848 26.533 ;
     RECT  31.968 26.435 32.808 26.533 ;
     RECT  13.2 25.667 13.608 26.629 ;
     RECT  51 25.573 73.176 26.677 ;
     RECT  45.6 24.851 45.912 26.773 ;
     RECT  12.672 26.629 13.608 26.819 ;
     RECT  22.8 26.437 24.648 26.819 ;
     RECT  31.968 26.533 32.952 26.819 ;
     RECT  34.176 26.341 35.112 26.819 ;
     RECT  41.616 26.197 43.896 26.821 ;
     RECT  40.2 26.147 40.632 26.867 ;
     RECT  21.072 26.291 21.612 26.869 ;
     RECT  26.7 25.763 27.432 26.869 ;
     RECT  15.072 26.533 19.848 26.915 ;
     RECT  41.616 26.821 44.52 26.915 ;
     RECT  28.8 26.531 30.312 26.917 ;
     RECT  38.928 26.821 38.952 26.965 ;
     RECT  40.2 26.867 40.512 26.965 ;
     RECT  38.928 26.965 40.512 27.011 ;
     RECT  15.12 26.915 19.848 27.059 ;
     RECT  10.368 26.197 11.544 27.205 ;
     RECT  26.7 26.869 27.624 27.253 ;
     RECT  32.1 26.819 32.952 27.299 ;
     RECT  2.4 16.019 2.712 27.301 ;
     RECT  5.1 25.715 8.112 27.395 ;
     RECT  23.376 26.819 24.648 27.395 ;
     RECT  26.208 27.253 27.624 27.587 ;
     RECT  42.9 26.915 44.52 27.587 ;
     RECT  49.824 25.715 49.848 27.637 ;
     RECT  28.8 26.917 30.648 27.683 ;
     RECT  12.672 26.819 13.512 27.733 ;
     RECT  41.616 26.915 41.88 27.877 ;
     RECT  42.9 27.587 43.608 27.877 ;
     RECT  2.4 27.301 2.952 27.971 ;
     RECT  6.864 27.395 8.112 28.019 ;
     RECT  45.6 26.773 46.008 28.019 ;
     RECT  15.12 27.059 19.416 28.163 ;
     RECT  28.8 27.683 30.552 28.163 ;
     RECT  36.528 25.621 37.812 28.261 ;
     RECT  9.216 26.725 9.24 28.309 ;
     RECT  10.272 27.205 11.544 28.309 ;
     RECT  32.1 27.299 32.412 28.405 ;
     RECT  34.8 26.819 35.112 28.405 ;
     RECT  6.912 28.019 8.112 28.453 ;
     RECT  9.216 28.309 11.544 28.453 ;
     RECT  21.072 26.869 22.248 28.453 ;
     RECT  24 27.395 24.648 28.453 ;
     RECT  26.208 27.587 27.012 28.453 ;
     RECT  36.48 28.261 37.812 28.453 ;
     RECT  36.48 28.453 38.04 28.547 ;
     RECT  47.424 25.715 48.612 28.547 ;
     RECT  48.3 28.547 48.612 28.597 ;
     RECT  49.584 27.637 49.848 28.597 ;
     RECT  41.616 27.877 43.608 28.739 ;
     RECT  31.968 28.405 32.412 28.789 ;
     RECT  42.9 28.739 43.608 28.837 ;
     RECT  51 26.677 73.272 28.837 ;
     RECT  31.968 28.789 32.52 28.931 ;
     RECT  5.1 27.395 5.544 28.933 ;
     RECT  39.312 27.011 40.512 28.981 ;
     RECT  45.6 28.019 45.912 28.981 ;
     RECT  33.696 27.349 33.72 29.123 ;
     RECT  21.072 28.453 24.648 29.219 ;
     RECT  15.12 28.163 18.912 29.317 ;
     RECT  25.776 28.453 27.012 29.317 ;
     RECT  6.912 28.453 11.544 29.509 ;
     RECT  12.528 27.733 13.512 29.509 ;
     RECT  25.632 29.317 27.012 29.509 ;
     RECT  48.3 28.597 49.848 29.509 ;
     RECT  34.8 28.405 35.352 29.557 ;
     RECT  39.12 28.981 40.512 29.605 ;
     RECT  41.616 28.739 41.88 29.605 ;
     RECT  45.6 28.981 46.056 29.605 ;
     RECT  4.992 28.933 5.544 29.651 ;
     RECT  25.632 29.509 27.336 29.653 ;
     RECT  36.576 28.547 38.04 29.653 ;
     RECT  39.12 29.605 41.88 29.653 ;
     RECT  6.912 29.509 13.512 29.747 ;
     RECT  21.072 29.219 22.968 29.795 ;
     RECT  34.656 29.557 35.352 29.795 ;
     RECT  48.192 29.509 49.848 29.795 ;
     RECT  34.656 29.795 35.208 29.843 ;
     RECT  31.968 28.931 32.412 29.845 ;
     RECT  36.576 29.653 41.88 29.891 ;
     RECT  45.6 29.605 46.776 29.893 ;
     RECT  36.576 29.891 38.04 29.987 ;
     RECT  31.344 29.845 32.412 30.037 ;
     RECT  42.9 28.837 44.472 30.037 ;
     RECT  45.6 29.893 46.92 30.037 ;
     RECT  51 28.837 73.32 30.131 ;
     RECT  31.344 30.037 33.336 30.133 ;
     RECT  21.072 29.795 22.824 30.179 ;
     RECT  15.12 29.317 19.416 30.229 ;
     RECT  39.072 29.891 41.88 30.229 ;
     RECT  42.9 30.037 46.92 30.229 ;
     RECT  39.072 30.229 46.92 30.275 ;
     RECT  34.656 29.843 35.112 30.323 ;
     RECT  28.8 28.163 29.712 30.373 ;
     RECT  31.152 30.133 33.336 30.373 ;
     RECT  4.992 29.651 5.412 30.469 ;
     RECT  24 29.219 24.648 30.469 ;
     RECT  25.632 29.653 27.672 30.469 ;
     RECT  28.8 30.373 33.336 30.469 ;
     RECT  7.248 29.747 13.512 30.611 ;
     RECT  28.704 30.469 33.336 30.611 ;
     RECT  15.072 30.229 19.416 30.709 ;
     RECT  7.248 30.611 12.168 30.755 ;
     RECT  7.248 30.755 11.544 30.757 ;
     RECT  24 30.469 27.672 30.851 ;
     RECT  39.072 30.275 43.608 30.851 ;
     RECT  45.408 30.275 46.92 30.851 ;
     RECT  36.576 29.987 37.812 30.949 ;
     RECT  15.072 30.709 19.752 31.187 ;
     RECT  13.2 30.611 13.512 31.237 ;
     RECT  21.072 30.179 22.2 31.237 ;
     RECT  39.072 30.851 40.512 31.285 ;
     RECT  49.824 29.795 49.848 31.285 ;
     RECT  51 30.131 73.272 31.285 ;
     RECT  6.864 30.757 11.544 31.331 ;
     RECT  20.448 31.237 22.2 31.379 ;
     RECT  24 30.851 25.656 31.379 ;
     RECT  28.752 30.611 33.336 31.379 ;
     RECT  15.072 31.187 19.32 31.475 ;
     RECT  28.752 31.379 30.264 31.475 ;
     RECT  4.512 30.469 5.412 31.525 ;
     RECT  36.528 30.949 37.812 31.573 ;
     RECT  13.2 31.237 14.04 31.621 ;
     RECT  2.4 27.971 2.712 31.669 ;
     RECT  47.184 30.949 47.208 31.669 ;
     RECT  48.192 29.795 48.612 31.669 ;
     RECT  22.8 31.429 22.824 31.763 ;
     RECT  45.408 30.851 45.912 31.813 ;
     RECT  49.824 31.285 73.272 31.861 ;
     RECT  10.368 31.331 11.544 31.907 ;
     RECT  26.7 30.851 27.672 31.955 ;
     RECT  47.184 31.669 48.612 31.955 ;
     RECT  12.768 31.621 14.04 32.051 ;
     RECT  10.5 31.907 11.544 32.101 ;
     RECT  20.448 31.379 21.72 32.147 ;
     RECT  26.7 31.955 27.012 32.197 ;
     RECT  34.8 30.323 35.112 32.197 ;
     RECT  36.48 31.573 37.812 32.197 ;
     RECT  45.024 31.813 45.912 32.197 ;
     RECT  24 31.379 25.224 32.243 ;
     RECT  15.072 31.475 18.912 32.245 ;
     RECT  49.824 31.861 73.512 32.291 ;
     RECT  6.864 31.331 8.856 32.437 ;
     RECT  31.968 31.379 32.412 32.531 ;
     RECT  2.4 31.669 3.432 32.579 ;
     RECT  51 32.291 73.512 32.579 ;
     RECT  41.616 30.851 43.608 32.629 ;
     RECT  38.976 31.285 40.512 32.723 ;
     RECT  51 32.579 52.44 32.723 ;
     RECT  12.768 32.051 13.512 32.771 ;
     RECT  4.512 31.525 5.736 32.773 ;
     RECT  26.592 32.197 27.012 33.011 ;
     RECT  20.448 32.147 21.612 33.013 ;
     RECT  10.5 32.101 11.592 33.059 ;
     RECT  34.8 32.197 37.812 33.107 ;
     RECT  45.024 32.197 46.008 33.107 ;
     RECT  53.472 32.579 73.512 33.107 ;
     RECT  24 32.243 24.648 33.299 ;
     RECT  28.752 31.475 29.712 33.301 ;
     RECT  10.5 33.059 11.544 33.395 ;
     RECT  4.272 32.773 5.736 33.541 ;
     RECT  6.816 32.437 8.856 33.541 ;
     RECT  28.752 33.301 29.832 33.589 ;
     RECT  31.008 33.013 31.032 33.589 ;
     RECT  47.904 31.955 48.612 33.589 ;
     RECT  13.2 32.771 13.512 33.973 ;
     RECT  14.784 32.245 18.912 33.973 ;
     RECT  13.2 33.973 18.912 34.019 ;
     RECT  36.48 33.107 37.812 34.115 ;
     RECT  45.6 33.107 46.008 34.115 ;
     RECT  22.848 33.013 22.872 34.117 ;
     RECT  24 33.299 24.456 34.117 ;
     RECT  19.968 33.013 21.612 34.163 ;
     RECT  53.472 33.107 73.224 34.213 ;
     RECT  26.7 33.011 27.012 34.357 ;
     RECT  28.752 33.589 31.032 34.357 ;
     RECT  36.576 34.115 37.812 34.405 ;
     RECT  10.5 33.395 11.4 34.453 ;
     RECT  36.576 34.405 37.992 34.453 ;
     RECT  39.072 32.723 40.512 34.453 ;
     RECT  22.848 34.117 24.456 34.499 ;
     RECT  53.28 34.213 73.224 34.501 ;
     RECT  20.544 34.163 21.612 34.547 ;
     RECT  51 32.723 52.2 34.549 ;
     RECT  45.6 34.115 45.912 34.645 ;
     RECT  26.7 34.357 31.032 34.691 ;
     RECT  47.472 33.589 48.612 34.741 ;
     RECT  26.7 34.691 29.928 34.787 ;
     RECT  41.616 32.629 43.656 34.787 ;
     RECT  53.28 34.501 73.272 34.787 ;
     RECT  21.072 34.547 21.612 34.789 ;
     RECT  36.576 34.453 40.512 34.789 ;
     RECT  41.616 34.787 41.88 34.789 ;
     RECT  4.272 33.541 9.48 34.835 ;
     RECT  22.848 34.499 22.872 34.835 ;
     RECT  4.272 34.835 5.412 34.883 ;
     RECT  10.5 34.453 11.688 34.979 ;
     RECT  2.4 32.579 3.288 35.077 ;
     RECT  15.408 34.019 18.912 35.171 ;
     RECT  15.504 35.171 18.912 35.219 ;
     RECT  6.432 34.835 9.48 35.315 ;
     RECT  47.136 34.741 48.612 35.411 ;
     RECT  13.2 34.019 14.28 35.413 ;
     RECT  42.9 34.787 43.656 35.413 ;
     RECT  36.576 34.789 41.88 35.507 ;
     RECT  21.072 34.789 21.816 35.509 ;
     RECT  28.704 34.787 29.928 35.845 ;
     RECT  36.576 35.507 38.184 35.845 ;
     RECT  10.5 34.979 10.92 35.939 ;
     RECT  39.168 35.507 41.88 35.939 ;
     RECT  39.312 35.939 41.88 36.035 ;
     RECT  12.816 35.413 14.28 36.037 ;
     RECT  50.88 34.549 52.2 36.083 ;
     RECT  15.9 35.219 18.912 36.085 ;
     RECT  45.264 34.645 45.912 36.275 ;
     RECT  47.184 35.411 48.612 36.275 ;
     RECT  24 34.499 24.456 36.277 ;
     RECT  53.568 34.787 73.272 36.277 ;
     RECT  47.376 36.275 48.612 36.323 ;
     RECT  12.624 36.037 14.28 36.373 ;
     RECT  15.9 36.085 19.032 36.373 ;
     RECT  12.624 36.373 19.032 36.421 ;
     RECT  26.7 34.787 27.528 36.421 ;
     RECT  28.704 35.845 29.976 36.421 ;
     RECT  24 36.277 24.504 36.469 ;
     RECT  25.68 34.837 25.704 36.469 ;
     RECT  2.4 35.077 3.96 36.515 ;
     RECT  34.8 33.107 35.112 36.517 ;
     RECT  36.336 35.845 38.184 36.517 ;
     RECT  24 36.469 25.704 36.611 ;
     RECT  24 36.611 24.504 36.661 ;
     RECT  26.7 36.421 29.976 36.661 ;
     RECT  31.008 34.691 31.032 36.661 ;
     RECT  49.824 32.291 49.848 36.661 ;
     RECT  26.7 36.661 31.032 36.707 ;
     RECT  34.8 36.517 38.184 36.707 ;
     RECT  49.584 36.661 49.848 36.707 ;
     RECT  25.68 36.611 25.704 36.755 ;
     RECT  45.6 36.275 45.912 36.757 ;
     RECT  50.88 36.083 51.912 36.851 ;
     RECT  21.072 35.509 22.296 36.853 ;
     RECT  45.6 36.757 46.056 36.853 ;
     RECT  36.336 36.707 38.184 36.899 ;
     RECT  10.5 35.939 10.812 36.901 ;
     RECT  11.952 36.421 19.032 36.901 ;
     RECT  42.9 35.413 44.088 36.949 ;
     RECT  2.4 36.515 3.912 36.995 ;
     RECT  39.312 36.035 40.728 36.997 ;
     RECT  10.5 36.901 19.032 37.091 ;
     RECT  12.192 37.091 19.032 37.139 ;
     RECT  39.168 36.997 40.728 37.189 ;
     RECT  41.856 36.035 41.88 37.189 ;
     RECT  45.6 36.853 46.104 37.237 ;
     RECT  52.992 36.277 73.512 37.331 ;
     RECT  42.9 36.949 44.184 37.379 ;
     RECT  7.056 35.315 9.48 37.429 ;
     RECT  10.5 37.091 11.208 37.429 ;
     RECT  32.1 32.531 32.412 37.429 ;
     RECT  36.576 36.899 38.184 37.573 ;
     RECT  39.168 37.189 41.88 37.573 ;
     RECT  34.8 36.707 35.112 37.621 ;
     RECT  47.664 36.323 48.612 37.621 ;
     RECT  49.584 36.707 49.608 37.621 ;
     RECT  53.52 37.331 73.512 37.667 ;
     RECT  53.52 37.667 73.464 37.763 ;
     RECT  23.904 36.661 24.504 37.907 ;
     RECT  21.072 36.853 22.584 38.149 ;
     RECT  36.576 37.573 41.88 38.149 ;
     RECT  47.664 37.621 49.608 38.149 ;
     RECT  45.6 37.237 46.152 38.197 ;
     RECT  47.328 38.149 49.608 38.197 ;
     RECT  21.072 38.149 22.68 38.245 ;
     RECT  23.904 37.907 24.456 38.245 ;
     RECT  2.4 36.995 2.904 38.389 ;
     RECT  3.888 36.995 3.912 38.389 ;
     RECT  4.992 34.883 5.412 38.389 ;
     RECT  33.984 37.621 35.112 38.389 ;
     RECT  36.432 38.149 41.88 38.389 ;
     RECT  33.984 38.389 41.88 38.435 ;
     RECT  45.6 38.197 49.656 38.435 ;
     RECT  26.7 36.707 30.888 38.533 ;
     RECT  7.056 37.429 11.208 38.725 ;
     RECT  12.192 37.139 14.28 38.725 ;
     RECT  42.9 37.379 43.212 38.725 ;
     RECT  51 36.851 51.912 38.725 ;
     RECT  34.8 38.435 41.88 38.771 ;
     RECT  15.9 37.139 19.032 38.773 ;
     RECT  53.52 37.763 73.224 38.773 ;
     RECT  15.9 38.773 19.368 38.819 ;
     RECT  47.328 38.435 49.272 38.867 ;
     RECT  2.4 38.389 5.412 38.915 ;
     RECT  45.6 38.435 46.008 38.915 ;
     RECT  25.728 38.533 30.888 39.107 ;
     RECT  18.288 38.819 19.368 39.109 ;
     RECT  50.88 38.725 51.912 39.205 ;
     RECT  7.056 38.725 14.28 39.251 ;
     RECT  18.288 39.109 19.992 39.253 ;
     RECT  21.072 38.245 24.456 39.253 ;
     RECT  34.8 38.771 40.68 39.299 ;
     RECT  42.9 38.725 43.32 39.301 ;
     RECT  28.56 39.107 30.888 39.397 ;
     RECT  31.968 37.429 32.412 39.397 ;
     RECT  12.528 39.251 14.28 39.635 ;
     RECT  18.288 39.253 24.456 39.635 ;
     RECT  19.968 39.635 24.456 39.637 ;
     RECT  25.728 39.107 27.012 39.637 ;
     RECT  5.1 38.915 5.412 39.733 ;
     RECT  7.056 39.251 11.448 39.733 ;
     RECT  19.968 39.637 27.012 39.779 ;
     RECT  12.816 39.635 14.28 39.877 ;
     RECT  2.4 38.915 3.912 39.923 ;
     RECT  25.488 39.779 27.012 39.923 ;
     RECT  42.9 39.301 43.656 39.973 ;
     RECT  19.968 39.779 24.456 40.019 ;
     RECT  41.856 38.771 41.88 40.163 ;
     RECT  50.88 39.205 52.488 40.259 ;
     RECT  5.1 39.733 11.448 40.309 ;
     RECT  12.816 39.877 14.376 40.355 ;
     RECT  42.9 39.973 43.944 40.405 ;
     RECT  53.52 38.773 73.512 40.405 ;
     RECT  4.56 40.309 11.448 40.451 ;
     RECT  25.488 39.923 25.512 40.499 ;
     RECT  50.88 40.259 51.864 40.499 ;
     RECT  2.4 39.923 3.24 40.547 ;
     RECT  13.056 40.355 14.376 40.595 ;
     RECT  47.568 38.867 49.272 40.693 ;
     RECT  9.456 40.451 11.448 40.835 ;
     RECT  13.056 40.595 14.28 40.883 ;
     RECT  26.7 39.923 27.012 40.885 ;
     RECT  42.48 40.405 43.944 40.933 ;
     RECT  28.56 39.397 32.412 40.979 ;
     RECT  18.288 39.635 18.912 40.981 ;
     RECT  19.968 40.019 21.612 40.981 ;
     RECT  22.752 40.019 24.456 40.981 ;
     RECT  31.968 40.979 32.412 40.981 ;
     RECT  15.9 38.819 17.256 41.029 ;
     RECT  18.288 40.981 24.456 41.029 ;
     RECT  46.944 40.693 49.272 41.029 ;
     RECT  4.56 40.451 8.376 41.075 ;
     RECT  26.208 40.885 27.012 41.125 ;
     RECT  28.56 40.979 30.888 41.125 ;
     RECT  42.48 40.933 44.52 41.171 ;
     RECT  15.9 41.029 24.456 41.221 ;
     RECT  15.9 41.221 24.504 41.267 ;
     RECT  26.208 41.125 30.888 41.363 ;
     RECT  39.312 39.299 40.68 41.509 ;
     RECT  53.088 40.405 73.512 41.509 ;
     RECT  4.992 41.075 8.376 41.651 ;
     RECT  18.288 41.267 24.504 41.651 ;
     RECT  46.944 41.029 49.704 41.651 ;
     RECT  52.992 41.509 73.512 41.651 ;
     RECT  31.968 40.981 32.904 41.653 ;
     RECT  19.968 41.651 24.504 41.795 ;
     RECT  34.8 39.299 38.136 41.845 ;
     RECT  39.312 41.509 41.064 41.845 ;
     RECT  7.8 41.651 8.376 41.941 ;
     RECT  9.456 40.835 10.812 41.941 ;
     RECT  34.8 41.845 41.064 41.987 ;
     RECT  7.8 41.941 10.812 42.035 ;
     RECT  34.8 41.987 40.512 42.035 ;
     RECT  31.968 41.653 33.624 42.085 ;
     RECT  34.8 42.035 38.136 42.085 ;
     RECT  13.056 40.883 14.088 42.131 ;
     RECT  13.104 42.131 14.088 42.133 ;
     RECT  31.968 42.085 38.136 42.179 ;
     RECT  44.496 41.171 44.52 42.179 ;
     RECT  45.6 38.915 45.912 42.181 ;
     RECT  33.6 42.179 38.136 42.227 ;
     RECT  2.4 40.547 2.712 42.277 ;
     RECT  3.792 42.133 3.816 42.277 ;
     RECT  13.104 42.133 14.808 42.323 ;
     RECT  52.992 41.651 73.176 42.419 ;
     RECT  45.504 42.181 45.912 42.469 ;
     RECT  46.944 41.651 49.416 42.469 ;
     RECT  20.208 41.795 24.504 42.563 ;
     RECT  45.504 42.469 49.416 42.565 ;
     RECT  34.416 42.227 38.136 42.707 ;
     RECT  15.9 41.267 17.256 42.709 ;
     RECT  21.072 42.563 24.504 42.709 ;
     RECT  26.208 41.363 29.712 42.709 ;
     RECT  42.48 41.171 43.212 42.709 ;
     RECT  21.072 42.709 29.712 42.803 ;
     RECT  51 40.499 51.864 42.805 ;
     RECT  52.992 42.419 73.032 42.805 ;
     RECT  7.8 42.035 8.232 42.851 ;
     RECT  34.8 42.707 38.136 42.899 ;
     RECT  9.216 42.035 10.812 43.139 ;
     RECT  15.9 42.709 17.304 43.141 ;
     RECT  18.288 41.651 18.912 43.141 ;
     RECT  2.4 42.277 3.816 43.189 ;
     RECT  4.992 41.651 6.264 43.189 ;
     RECT  42.288 42.709 43.212 43.285 ;
     RECT  45.072 42.565 49.416 43.285 ;
     RECT  24 42.803 29.712 43.331 ;
     RECT  51 42.805 73.032 43.477 ;
     RECT  25.344 43.331 29.712 43.571 ;
     RECT  15.9 43.141 18.912 43.619 ;
     RECT  50.832 43.477 73.032 43.717 ;
     RECT  28.128 43.571 29.712 43.765 ;
     RECT  30.72 41.363 30.888 43.765 ;
     RECT  42.288 43.285 49.416 43.811 ;
     RECT  31.968 42.179 32.412 43.813 ;
     RECT  39.216 42.035 40.512 43.813 ;
     RECT  15.9 43.619 17.304 43.859 ;
     RECT  13.2 42.323 13.992 43.861 ;
     RECT  15.9 43.859 17.256 43.861 ;
     RECT  21.072 42.803 22.584 43.861 ;
     RECT  2.4 43.189 6.264 43.955 ;
     RECT  13.2 43.861 17.256 43.955 ;
     RECT  13.2 43.955 17.064 44.051 ;
     RECT  42.288 43.811 46.056 44.099 ;
     RECT  31.968 43.813 32.52 44.195 ;
     RECT  42.288 44.099 44.472 44.195 ;
     RECT  11.952 44.197 11.976 44.293 ;
     RECT  13.2 44.051 16.584 44.293 ;
     RECT  24 43.331 24.312 44.341 ;
     RECT  25.344 43.571 27.012 44.341 ;
     RECT  28.128 43.765 30.888 44.387 ;
     RECT  11.952 44.293 16.584 44.435 ;
     RECT  34.8 42.899 38.088 44.437 ;
     RECT  3.792 43.955 6.264 44.483 ;
     RECT  13.2 44.435 16.584 44.483 ;
     RECT  39.216 43.813 40.872 44.531 ;
     RECT  28.32 44.387 30.888 44.581 ;
     RECT  31.968 44.195 32.412 44.581 ;
     RECT  33.792 44.437 38.088 44.675 ;
     RECT  39.216 44.531 40.512 44.675 ;
     RECT  50.832 43.717 73.224 44.677 ;
     RECT  50.736 44.677 73.224 44.915 ;
     RECT  52.896 44.915 73.224 44.917 ;
     RECT  3.792 44.483 5.64 45.011 ;
     RECT  28.32 44.581 32.412 45.059 ;
     RECT  33.792 44.675 33.816 45.155 ;
     RECT  18.288 43.619 18.912 45.205 ;
     RECT  7.8 42.851 8.112 45.253 ;
     RECT  9.264 43.139 10.812 45.253 ;
     RECT  45.6 44.099 46.056 45.349 ;
     RECT  13.2 44.483 16.212 45.443 ;
     RECT  28.752 45.059 32.412 45.491 ;
     RECT  3.936 45.011 5.64 45.493 ;
     RECT  18.096 45.205 18.912 45.493 ;
     RECT  20.832 43.861 22.584 45.541 ;
     RECT  24 44.341 27.012 45.541 ;
     RECT  20.832 45.541 27.012 45.635 ;
     RECT  52.896 44.917 73.272 45.635 ;
     RECT  28.752 45.491 30.888 45.731 ;
     RECT  47.568 43.811 49.416 45.731 ;
     RECT  34.8 44.675 38.088 45.733 ;
     RECT  18.096 45.493 19.368 45.781 ;
     RECT  23.52 45.635 27.012 45.827 ;
     RECT  42.288 44.195 43.212 45.829 ;
     RECT  20.832 45.635 22.44 45.923 ;
     RECT  7.8 45.253 10.812 45.971 ;
     RECT  44.448 44.195 44.472 45.973 ;
     RECT  45.504 45.349 46.056 45.973 ;
     RECT  34.8 45.733 38.184 46.019 ;
     RECT  17.232 45.781 19.368 46.021 ;
     RECT  21.072 45.923 22.44 46.115 ;
     RECT  34.8 46.019 38.088 46.115 ;
     RECT  26.7 45.827 27.012 46.117 ;
     RECT  44.448 45.973 46.056 46.163 ;
     RECT  17.232 46.021 19.56 46.211 ;
     RECT  42.144 45.829 43.212 46.213 ;
     RECT  31.92 45.491 32.412 46.259 ;
     RECT  2.4 43.955 2.712 46.357 ;
     RECT  3.936 45.493 5.88 46.357 ;
     RECT  11.952 44.435 11.976 46.403 ;
     RECT  42.144 46.213 43.464 46.547 ;
     RECT  7.8 45.971 8.904 46.595 ;
     RECT  34.8 46.115 37.992 46.645 ;
     RECT  52.704 46.357 52.728 46.645 ;
     RECT  53.7 45.635 73.272 46.645 ;
     RECT  31.968 46.259 32.412 46.741 ;
     RECT  7.8 46.595 8.52 46.787 ;
     RECT  23.52 45.827 25.416 46.787 ;
     RECT  34.704 46.645 37.992 46.787 ;
     RECT  48.096 45.731 49.416 46.787 ;
     RECT  13.2 45.443 14.856 46.789 ;
     RECT  15.9 45.443 16.212 46.789 ;
     RECT  42.768 46.547 43.416 46.835 ;
     RECT  21.072 46.115 22.344 46.883 ;
     RECT  23.52 46.787 25.224 46.883 ;
     RECT  48.3 46.787 49.416 46.885 ;
     RECT  50.736 44.915 51.312 46.885 ;
     RECT  52.704 46.645 73.272 46.979 ;
     RECT  29.28 45.731 30.888 46.981 ;
     RECT  10.272 45.971 10.812 47.077 ;
     RECT  34.8 46.787 37.992 47.123 ;
     RECT  29.088 46.981 30.888 47.125 ;
     RECT  17.328 46.211 19.56 47.171 ;
     RECT  18 47.171 19.56 47.173 ;
     RECT  26.7 46.117 27.432 47.173 ;
     RECT  31.968 46.741 32.52 47.173 ;
     RECT  48.3 46.885 51.312 47.173 ;
     RECT  52.704 46.979 73.128 47.173 ;
     RECT  21.168 46.883 22.344 47.219 ;
     RECT  2.4 46.357 5.88 47.221 ;
     RECT  10.272 47.077 11.208 47.221 ;
     RECT  39.312 44.675 40.512 47.269 ;
     RECT  41.568 46.885 41.592 47.269 ;
     RECT  48.3 47.173 73.128 47.315 ;
     RECT  21.3 47.219 22.344 47.317 ;
     RECT  31.968 47.173 32.616 47.363 ;
     RECT  39.312 47.269 41.592 47.363 ;
     RECT  31.968 47.363 32.412 47.365 ;
     RECT  13.2 46.789 16.212 47.461 ;
     RECT  28.464 47.125 30.888 47.603 ;
     RECT  10.128 47.221 11.208 47.605 ;
     RECT  34.8 47.123 37.812 47.749 ;
     RECT  0.288 47.125 0.312 47.795 ;
     RECT  10.128 47.605 11.496 47.845 ;
     RECT  13.008 47.461 16.212 47.845 ;
     RECT  10.128 47.845 16.212 47.891 ;
     RECT  24 46.883 25.224 47.893 ;
     RECT  26.208 47.173 27.432 47.893 ;
     RECT  2.4 47.221 6.264 47.939 ;
     RECT  18 47.173 20.136 47.939 ;
     RECT  24 47.893 27.432 47.939 ;
     RECT  44.976 46.163 46.056 47.939 ;
     RECT  48.3 47.315 49.128 47.939 ;
     RECT  50.16 47.315 73.128 47.939 ;
     RECT  3.936 47.939 6.264 48.085 ;
     RECT  7.8 46.787 8.112 48.085 ;
     RECT  72.384 47.939 73.128 48.085 ;
     RECT  42.768 46.835 43.212 48.133 ;
     RECT  20.016 47.939 20.136 48.181 ;
     RECT  10.368 47.891 16.212 48.227 ;
     RECT  28.464 47.603 30.792 48.227 ;
     RECT  10.368 48.227 14.808 48.371 ;
     RECT  30.72 48.227 30.792 48.419 ;
     RECT  48.3 47.939 48.612 48.421 ;
     RECT  24 47.939 27.012 48.467 ;
     RECT  18 47.939 18.912 48.515 ;
     RECT  3.936 48.085 8.112 48.661 ;
     RECT  39.312 47.363 41.256 48.757 ;
     RECT  42.336 48.133 43.212 48.757 ;
     RECT  3.936 48.661 8.232 48.805 ;
     RECT  12.384 48.371 14.808 48.899 ;
     RECT  12.384 48.899 13.512 48.947 ;
     RECT  33.888 47.749 37.812 48.947 ;
     RECT  15.9 48.227 16.212 48.997 ;
     RECT  20.016 48.181 20.328 48.997 ;
     RECT  21.3 47.317 22.536 48.997 ;
     RECT  45.024 47.939 46.056 48.997 ;
     RECT  45.024 48.997 46.104 49.043 ;
     RECT  72.384 48.085 73.512 49.043 ;
     RECT  20.016 48.997 22.536 49.091 ;
     RECT  31.92 47.365 32.412 49.091 ;
     RECT  15.9 48.997 17.112 49.139 ;
     RECT  24 48.467 25.512 49.235 ;
     RECT  36.576 48.947 37.812 49.237 ;
     RECT  72.384 49.043 73.128 49.237 ;
     RECT  10.368 48.371 11.4 49.283 ;
     RECT  36.576 49.237 37.944 49.285 ;
     RECT  50.16 47.939 71.256 49.333 ;
     RECT  45.6 49.043 46.104 49.379 ;
     RECT  32.1 49.091 32.412 49.381 ;
     RECT  33.888 48.947 35.448 49.381 ;
     RECT  50.16 49.333 71.352 49.381 ;
     RECT  72.336 49.237 73.128 49.427 ;
     RECT  14.688 48.899 14.808 49.477 ;
     RECT  15.9 49.139 16.68 49.477 ;
     RECT  18.6 48.515 18.912 49.477 ;
     RECT  36.576 49.285 38.328 49.477 ;
     RECT  39.312 48.757 43.212 49.477 ;
     RECT  48.192 48.421 48.612 49.477 ;
     RECT  32.1 49.381 35.448 49.523 ;
     RECT  28.464 48.227 29.712 49.667 ;
     RECT  33.888 49.523 35.448 49.667 ;
     RECT  3.936 48.805 8.568 49.763 ;
     RECT  14.688 49.477 16.68 49.811 ;
     RECT  48.192 49.477 48.888 49.811 ;
     RECT  50.112 49.381 71.352 49.813 ;
     RECT  72.336 49.427 72.912 49.813 ;
     RECT  10.368 49.283 11.208 49.861 ;
     RECT  18.336 49.477 18.912 49.861 ;
     RECT  20.016 49.091 22.344 49.861 ;
     RECT  2.4 47.939 2.712 50.005 ;
     RECT  3.936 49.763 8.112 50.005 ;
     RECT  28.656 49.667 29.712 50.005 ;
     RECT  30.72 48.419 30.744 50.005 ;
     RECT  36.576 49.477 43.212 50.005 ;
     RECT  14.688 49.811 16.584 50.051 ;
     RECT  50.112 49.813 72.912 50.099 ;
     RECT  13.2 48.947 13.512 50.101 ;
     RECT  50.16 50.099 72.912 50.291 ;
     RECT  50.88 50.291 72.912 50.339 ;
     RECT  9.936 49.861 11.208 50.389 ;
     RECT  51 50.339 72.912 50.389 ;
     RECT  26.592 48.467 27.012 50.435 ;
     RECT  9.888 50.389 11.208 50.579 ;
     RECT  32.1 49.523 32.412 50.677 ;
     RECT  45.6 49.379 46.056 50.677 ;
     RECT  24 49.235 25.176 50.725 ;
     RECT  36.432 50.005 43.212 50.771 ;
     RECT  51 50.389 73.128 50.819 ;
     RECT  48.3 49.811 48.888 50.965 ;
     RECT  52.368 50.819 73.128 51.013 ;
     RECT  36.672 50.771 43.212 51.107 ;
     RECT  48.3 50.965 49.032 51.155 ;
     RECT  15.9 50.051 16.584 51.299 ;
     RECT  33.888 49.667 35.112 51.349 ;
     RECT  13.056 50.101 13.512 51.395 ;
     RECT  33.648 51.349 35.112 51.395 ;
     RECT  45.504 50.677 46.056 51.395 ;
     RECT  34.8 51.395 35.112 51.445 ;
     RECT  26.7 50.435 27.012 51.637 ;
     RECT  28.656 50.005 30.744 51.637 ;
     RECT  33.648 51.395 33.72 51.683 ;
     RECT  48.3 51.155 48.888 51.683 ;
     RECT  9.888 50.579 11.112 51.685 ;
     RECT  18.336 49.861 22.344 51.733 ;
     RECT  24 50.725 25.656 51.733 ;
     RECT  14.688 50.051 14.856 51.829 ;
     RECT  15.9 51.299 16.212 51.829 ;
     RECT  9.888 51.685 11.16 51.925 ;
     RECT  34.8 51.445 35.352 52.019 ;
     RECT  44.448 51.205 44.472 52.019 ;
     RECT  52.368 51.013 73.512 52.019 ;
     RECT  48.3 51.683 48.744 52.067 ;
     RECT  2.4 50.005 8.112 52.165 ;
     RECT  9.648 51.925 11.16 52.165 ;
     RECT  51 50.819 51.312 52.165 ;
     RECT  18.336 51.733 25.656 52.211 ;
     RECT  52.368 52.019 73.176 52.211 ;
     RECT  36.672 51.107 41.304 52.213 ;
     RECT  2.4 52.165 11.16 52.261 ;
     RECT  26.7 51.637 30.744 52.309 ;
     RECT  2.4 52.261 11.256 52.499 ;
     RECT  26.7 52.309 30.936 52.549 ;
     RECT  31.968 50.677 32.412 52.549 ;
     RECT  45.6 51.395 46.056 52.643 ;
     RECT  26.7 52.549 32.412 52.691 ;
     RECT  9.84 52.499 11.256 52.741 ;
     RECT  50.4 52.165 51.312 52.741 ;
     RECT  18.336 52.211 18.912 52.787 ;
     RECT  9.84 52.741 11.544 52.789 ;
     RECT  36.576 52.213 41.304 52.789 ;
     RECT  33.696 51.683 33.72 52.835 ;
     RECT  45.6 52.643 45.912 52.981 ;
     RECT  14.688 51.829 16.212 53.029 ;
     RECT  49.824 52.741 51.312 53.173 ;
     RECT  52.368 52.211 72.912 53.173 ;
     RECT  36.336 52.789 41.304 53.269 ;
     RECT  34.8 52.019 35.208 53.317 ;
     RECT  36.336 53.269 41.784 53.317 ;
     RECT  34.704 53.317 41.784 53.507 ;
     RECT  49.824 53.173 72.912 53.555 ;
     RECT  34.8 53.507 41.784 53.795 ;
     RECT  18.6 52.787 18.912 53.797 ;
     RECT  26.7 52.691 27.912 53.797 ;
     RECT  9.84 52.789 11.688 53.843 ;
     RECT  18.48 53.797 18.912 53.941 ;
     RECT  19.968 52.211 25.08 53.941 ;
     RECT  29.4 52.691 32.412 53.987 ;
     RECT  13.2 51.395 13.512 53.989 ;
     RECT  14.688 53.029 17.16 54.035 ;
     RECT  45.216 52.981 45.912 54.083 ;
     RECT  13.2 53.989 13.704 54.085 ;
     RECT  36.336 53.795 41.784 54.085 ;
     RECT  42.9 51.107 43.212 54.085 ;
     RECT  50.208 53.555 72.912 54.085 ;
     RECT  26.592 53.797 27.912 54.323 ;
     RECT  36.336 54.085 43.32 54.611 ;
     RECT  29.4 53.987 30.744 54.613 ;
     RECT  36.768 54.611 43.32 54.659 ;
     RECT  2.4 52.499 8.112 54.661 ;
     RECT  18.48 53.941 25.08 54.707 ;
     RECT  15.36 54.035 17.16 54.757 ;
     RECT  26.592 54.323 27.144 54.851 ;
     RECT  18.48 54.707 18.912 54.899 ;
     RECT  50.208 54.085 73.224 54.899 ;
     RECT  15.36 54.757 17.208 54.947 ;
     RECT  26.7 54.851 27.144 54.947 ;
     RECT  15.36 54.947 17.16 54.995 ;
     RECT  36.768 54.659 41.784 55.139 ;
     RECT  13.2 54.085 14.28 55.141 ;
     RECT  50.496 54.899 73.224 55.237 ;
     RECT  15.744 54.995 17.16 55.283 ;
     RECT  2.4 54.661 8.232 55.285 ;
     RECT  19.968 54.707 25.08 55.331 ;
     RECT  50.496 55.237 73.32 55.427 ;
     RECT  28.464 54.613 30.744 55.429 ;
     RECT  32.1 53.987 32.412 55.429 ;
     RECT  45.6 54.083 45.912 55.429 ;
     RECT  45.6 55.429 46.152 55.525 ;
     RECT  10.5 53.843 11.688 55.669 ;
     RECT  13.2 55.141 14.376 55.669 ;
     RECT  15.744 55.283 16.344 55.715 ;
     RECT  36.768 55.139 38.328 55.715 ;
     RECT  45.168 55.525 46.824 55.763 ;
     RECT  50.688 55.427 73.32 55.955 ;
     RECT  26.7 54.947 27.012 55.957 ;
     RECT  18.6 54.899 18.912 56.005 ;
     RECT  2.4 55.285 8.568 56.387 ;
     RECT  15.9 55.715 16.344 56.389 ;
     RECT  18.192 56.005 18.912 56.389 ;
     RECT  28.464 55.429 32.412 56.483 ;
     RECT  10.5 55.669 14.376 56.485 ;
     RECT  26.7 55.957 27.48 56.531 ;
     RECT  36.768 55.715 38.136 56.531 ;
     RECT  42.9 54.659 43.32 56.531 ;
     RECT  36.768 56.531 37.812 56.773 ;
     RECT  33.6 55.813 33.624 56.821 ;
     RECT  48.3 52.067 48.612 56.821 ;
     RECT  10.368 56.485 14.376 56.867 ;
     RECT  50.688 55.955 73.128 56.915 ;
     RECT  33.456 56.821 33.624 56.917 ;
     RECT  45.168 55.763 46.584 57.013 ;
     RECT  45.12 57.013 46.584 57.109 ;
     RECT  17.856 56.389 18.912 57.299 ;
     RECT  32.1 56.483 32.412 57.301 ;
     RECT  33.456 56.917 33.768 57.301 ;
     RECT  9.12 56.677 9.144 57.347 ;
     RECT  39.312 55.139 41.784 57.395 ;
     RECT  45.024 57.109 46.584 57.395 ;
     RECT  12.912 56.867 14.376 57.397 ;
     RECT  15.9 56.389 16.44 57.397 ;
     RECT  26.7 56.531 27.012 57.445 ;
     RECT  48.3 56.821 49.56 57.445 ;
     RECT  50.688 56.915 51.312 57.445 ;
     RECT  52.992 56.915 73.128 57.445 ;
     RECT  10.368 56.867 11.64 57.493 ;
     RECT  25.728 57.445 27.012 57.493 ;
     RECT  29.088 56.483 30.744 57.587 ;
     RECT  36.384 56.773 37.812 57.587 ;
     RECT  45.6 57.395 46.584 57.587 ;
     RECT  12.912 57.397 16.44 57.875 ;
     RECT  52.992 57.445 73.224 57.877 ;
     RECT  18.48 57.299 18.912 58.069 ;
     RECT  19.968 55.331 24.312 58.069 ;
     RECT  18.48 58.069 24.312 58.115 ;
     RECT  52.608 57.877 73.224 58.115 ;
     RECT  20.352 58.115 24.312 58.117 ;
     RECT  25.728 57.493 27.384 58.117 ;
     RECT  20.352 58.117 24.744 58.403 ;
     RECT  52.608 58.115 73.128 58.403 ;
     RECT  2.4 56.387 8.112 58.547 ;
     RECT  48.3 57.445 51.312 58.597 ;
     RECT  25.728 58.117 27.528 58.645 ;
     RECT  29.4 57.587 30.744 58.645 ;
     RECT  32.1 57.301 33.768 58.645 ;
     RECT  34.8 53.795 35.208 58.645 ;
     RECT  42.9 56.531 43.212 58.645 ;
     RECT  25.728 58.645 30.744 58.691 ;
     RECT  26.304 58.691 30.744 59.027 ;
     RECT  32.1 58.645 35.208 59.027 ;
     RECT  9.696 57.493 11.64 59.077 ;
     RECT  44.448 58.117 44.472 59.123 ;
     RECT  18.48 58.115 19.128 59.219 ;
     RECT  20.784 58.403 24.744 59.219 ;
     RECT  39.312 57.395 40.512 59.221 ;
     RECT  41.568 57.395 41.784 59.221 ;
     RECT  42.9 58.645 43.368 59.221 ;
     RECT  45.6 57.587 45.912 59.221 ;
     RECT  48.3 58.597 51.432 59.221 ;
     RECT  20.784 59.219 24.552 59.315 ;
     RECT  36.48 57.587 37.812 59.317 ;
     RECT  32.1 59.027 33.624 59.363 ;
     RECT  45.6 59.221 46.824 59.365 ;
     RECT  12.912 57.875 16.344 59.459 ;
     RECT  20.784 59.315 22.344 59.459 ;
     RECT  52.704 58.403 73.128 59.459 ;
     RECT  29.4 59.027 30.744 59.461 ;
     RECT  32.1 59.363 33.48 59.461 ;
     RECT  12.912 59.459 13.656 59.507 ;
     RECT  26.304 59.027 27.912 59.507 ;
     RECT  13.056 59.507 13.656 59.555 ;
     RECT  45.6 59.365 47.064 59.555 ;
     RECT  9.408 59.077 11.64 59.603 ;
     RECT  48.192 59.221 51.432 59.603 ;
     RECT  42.768 59.221 43.368 59.795 ;
     RECT  53.088 59.459 73.128 59.845 ;
     RECT  48.3 59.603 51.432 59.891 ;
     RECT  42.768 59.795 43.212 59.987 ;
     RECT  9.696 59.603 11.64 60.179 ;
     RECT  2.4 58.547 6.648 60.371 ;
     RECT  48.3 59.891 49.56 60.371 ;
     RECT  10.32 60.179 11.64 60.373 ;
     RECT  18.6 59.219 19.128 60.421 ;
     RECT  48.3 60.371 49.224 60.467 ;
     RECT  45.6 59.555 46.824 60.515 ;
     RECT  36.48 59.317 38.184 60.563 ;
     RECT  44.352 59.221 44.376 60.565 ;
     RECT  48.3 60.467 49.128 60.565 ;
     RECT  7.8 58.547 8.112 60.661 ;
     RECT  29.4 59.461 33.48 60.851 ;
     RECT  37.5 60.563 38.184 60.851 ;
     RECT  26.7 59.507 27.912 60.853 ;
     RECT  34.8 59.027 35.208 60.901 ;
     RECT  36.48 60.563 36.504 60.901 ;
     RECT  39.312 59.221 41.784 60.949 ;
     RECT  42.9 59.987 43.212 60.949 ;
     RECT  53.088 59.845 73.512 60.995 ;
     RECT  10.32 60.373 11.736 61.139 ;
     RECT  30.72 60.851 33.48 61.139 ;
     RECT  13.056 59.555 13.608 61.189 ;
     RECT  7.8 60.661 8.232 61.235 ;
     RECT  23.808 59.315 24.552 61.237 ;
     RECT  26.7 60.853 28.392 61.237 ;
     RECT  44.208 60.565 44.376 61.237 ;
     RECT  45.6 60.515 46.728 61.237 ;
     RECT  2.4 60.371 6.504 61.381 ;
     RECT  7.8 61.235 8.112 61.381 ;
     RECT  18 60.421 19.128 61.381 ;
     RECT  25.92 61.237 28.392 61.525 ;
     RECT  29.4 60.851 29.712 61.525 ;
     RECT  2.4 61.381 8.112 61.619 ;
     RECT  23.616 61.237 24.552 61.619 ;
     RECT  48.144 60.565 49.128 61.619 ;
     RECT  18 61.381 19.176 61.669 ;
     RECT  20.304 61.141 20.328 61.669 ;
     RECT  30.72 61.139 30.744 61.907 ;
     RECT  14.88 59.459 16.344 61.957 ;
     RECT  14.832 61.957 16.344 62.003 ;
     RECT  37.5 60.851 37.812 62.005 ;
     RECT  53.088 60.995 54.12 62.005 ;
     RECT  55.104 60.995 73.512 62.005 ;
     RECT  12.96 61.189 13.608 62.053 ;
     RECT  21.3 59.459 22.344 62.053 ;
     RECT  23.616 61.619 24.408 62.053 ;
     RECT  21.3 62.053 24.408 62.195 ;
     RECT  25.92 61.525 29.712 62.195 ;
     RECT  31.824 61.139 33.48 62.195 ;
     RECT  18 61.669 20.328 62.291 ;
     RECT  44.208 61.237 46.728 62.435 ;
     RECT  39.312 60.949 43.212 62.581 ;
     RECT  34.8 60.901 36.504 62.629 ;
     RECT  37.5 62.005 38.088 62.629 ;
     RECT  4.512 61.619 8.112 62.677 ;
     RECT  23.808 62.195 24.408 62.677 ;
     RECT  34.8 62.629 38.088 62.677 ;
     RECT  39.312 62.581 43.32 62.677 ;
     RECT  45.024 62.435 46.728 62.677 ;
     RECT  51 59.891 51.432 62.723 ;
     RECT  48.3 61.619 49.128 62.725 ;
     RECT  34.8 62.677 43.32 62.771 ;
     RECT  31.824 62.195 32.412 62.819 ;
     RECT  45.024 62.677 46.776 62.819 ;
     RECT  23.808 62.677 24.936 62.965 ;
     RECT  34.8 62.771 43.212 63.011 ;
     RECT  31.968 62.819 32.412 63.107 ;
     RECT  34.8 63.011 38.088 63.107 ;
     RECT  14.832 62.003 16.212 63.205 ;
     RECT  18 62.291 20.04 63.251 ;
     RECT  33.408 62.195 33.48 63.251 ;
     RECT  21.3 62.195 22.728 63.253 ;
     RECT  23.808 62.965 25.464 63.253 ;
     RECT  29.184 62.195 29.712 63.253 ;
     RECT  10.368 61.139 11.736 63.299 ;
     RECT  37.5 63.107 38.088 63.299 ;
     RECT  53.088 62.005 73.512 63.299 ;
     RECT  29.088 63.253 29.712 63.301 ;
     RECT  10.5 63.299 11.736 63.349 ;
     RECT  3.84 62.677 8.112 63.395 ;
     RECT  34.8 63.107 36.408 63.491 ;
     RECT  10.5 63.349 11.88 63.589 ;
     RECT  12.864 62.053 13.656 63.589 ;
     RECT  39.312 63.011 43.212 63.635 ;
     RECT  2.4 61.619 2.712 63.781 ;
     RECT  3.84 63.395 6.504 63.781 ;
     RECT  21.3 63.253 25.464 63.781 ;
     RECT  47.904 62.725 49.128 63.781 ;
     RECT  33.456 63.251 33.48 63.829 ;
     RECT  14.832 63.205 16.344 63.875 ;
     RECT  15.168 63.875 16.344 64.069 ;
     RECT  21.3 63.781 25.512 64.069 ;
     RECT  32.1 63.107 32.412 64.117 ;
     RECT  47.376 63.781 49.704 64.117 ;
     RECT  47.376 64.117 49.896 64.165 ;
     RECT  36.384 63.491 36.408 64.213 ;
     RECT  37.5 63.299 37.812 64.213 ;
     RECT  7.68 63.395 8.112 64.357 ;
     RECT  9.12 62.005 9.144 64.357 ;
     RECT  18 63.251 19.224 64.357 ;
     RECT  29.088 63.301 30.312 64.357 ;
     RECT  31.92 64.117 32.412 64.357 ;
     RECT  47.28 64.165 49.896 64.357 ;
     RECT  51 62.723 51.312 64.357 ;
     RECT  33.456 63.829 33.624 64.403 ;
     RECT  47.28 64.357 51.312 64.451 ;
     RECT  53.088 63.299 73.464 64.451 ;
     RECT  7.68 64.357 9.144 64.547 ;
     RECT  36.384 64.213 37.812 64.643 ;
     RECT  10.5 63.589 13.656 64.741 ;
     RECT  45.024 62.819 46.008 64.789 ;
     RECT  47.28 64.451 47.304 64.789 ;
     RECT  31.584 64.357 32.412 64.931 ;
     RECT  45.024 64.789 47.304 64.931 ;
     RECT  9.648 64.741 13.656 64.979 ;
     RECT  33.456 64.403 33.576 64.979 ;
     RECT  18 64.357 19.416 64.981 ;
     RECT  9.648 64.979 13.608 65.027 ;
     RECT  18 64.981 19.752 65.221 ;
     RECT  48.3 64.451 51.312 65.267 ;
     RECT  36.432 64.643 37.812 65.317 ;
     RECT  2.4 63.781 6.504 65.509 ;
     RECT  7.68 64.547 8.232 65.509 ;
     RECT  9.648 65.027 11.304 65.509 ;
     RECT  12.528 65.027 13.608 65.555 ;
     RECT  36.432 65.317 37.992 65.557 ;
     RECT  39.312 63.635 41.784 65.557 ;
     RECT  53.088 64.451 73.224 65.557 ;
     RECT  36.432 65.557 41.784 65.603 ;
     RECT  2.4 65.509 8.232 65.651 ;
     RECT  31.872 64.931 32.412 65.699 ;
     RECT  48.3 65.267 49.704 65.699 ;
     RECT  17.664 65.221 19.752 65.747 ;
     RECT  40.08 65.603 41.784 65.749 ;
     RECT  42.768 63.635 43.212 65.749 ;
     RECT  17.664 65.747 19.416 65.795 ;
     RECT  36.432 65.603 38.952 65.939 ;
     RECT  17.664 65.795 19.32 66.085 ;
     RECT  21.3 64.069 25.56 66.085 ;
     RECT  28.896 64.357 30.312 66.085 ;
     RECT  45.6 64.931 47.304 66.133 ;
     RECT  48.3 65.699 48.612 66.133 ;
     RECT  17.616 66.085 19.32 66.179 ;
     RECT  33.552 64.979 33.576 66.179 ;
     RECT  2.4 65.651 3.288 66.227 ;
     RECT  4.704 65.651 8.232 66.227 ;
     RECT  40.08 65.749 43.212 66.227 ;
     RECT  15.168 64.069 16.392 66.325 ;
     RECT  17.616 66.179 18.912 66.325 ;
     RECT  20.592 66.085 25.56 66.515 ;
     RECT  37.5 65.939 38.952 66.515 ;
     RECT  49.68 65.699 49.704 66.515 ;
     RECT  20.592 66.515 25.272 66.563 ;
     RECT  36.432 65.939 36.456 66.563 ;
     RECT  13.056 65.555 13.608 66.613 ;
     RECT  53.088 65.557 73.512 66.613 ;
     RECT  9.6 65.509 11.304 66.709 ;
     RECT  9.12 66.709 11.304 66.755 ;
     RECT  45.6 66.133 48.612 66.755 ;
     RECT  15.168 66.325 18.912 66.851 ;
     RECT  28.896 66.085 31.08 66.851 ;
     RECT  28.896 66.851 29.712 66.899 ;
     RECT  31.056 66.851 31.08 66.901 ;
     RECT  32.1 65.699 32.412 66.901 ;
     RECT  13.056 66.613 13.656 67.045 ;
     RECT  4.704 66.227 8.112 67.141 ;
     RECT  15.264 66.851 18.912 67.187 ;
     RECT  31.056 66.901 32.412 67.189 ;
     RECT  15.264 67.187 16.212 67.331 ;
     RECT  36.192 66.613 36.216 67.331 ;
     RECT  10.224 66.755 11.304 67.333 ;
     RECT  12.528 67.045 13.656 67.333 ;
     RECT  40.08 66.227 41.784 67.429 ;
     RECT  9.12 66.755 9.144 67.571 ;
     RECT  44.448 65.509 44.472 67.571 ;
     RECT  17.664 67.187 18.912 67.621 ;
     RECT  21.3 66.563 25.272 67.669 ;
     RECT  37.5 66.515 38.808 67.715 ;
     RECT  4.272 67.141 8.112 67.717 ;
     RECT  51 65.267 51.312 67.717 ;
     RECT  17.664 67.621 19.512 67.765 ;
     RECT  40.032 67.429 41.784 67.765 ;
     RECT  20.736 67.669 25.272 67.811 ;
     RECT  3.696 67.717 8.112 67.859 ;
     RECT  12.528 67.333 13.992 67.859 ;
     RECT  39.312 67.765 41.784 67.859 ;
     RECT  52.368 66.613 73.512 67.859 ;
     RECT  10.224 67.333 11.4 67.861 ;
     RECT  47.472 66.755 48.612 67.861 ;
     RECT  52.368 67.859 73.176 67.955 ;
     RECT  34.8 63.491 35.208 68.147 ;
     RECT  26.7 62.195 27.528 68.149 ;
     RECT  31.056 67.189 32.856 68.149 ;
     RECT  31.056 68.149 33.672 68.195 ;
     RECT  7.248 67.859 8.112 68.243 ;
     RECT  31.056 68.195 32.412 68.243 ;
     RECT  52.368 67.955 71.208 68.339 ;
     RECT  47.472 67.861 48.744 68.341 ;
     RECT  13.056 67.859 13.992 68.387 ;
     RECT  50.88 67.717 51.312 68.435 ;
     RECT  72.336 67.955 73.176 68.483 ;
     RECT  37.5 67.715 38.232 68.485 ;
     RECT  31.056 68.243 31.08 68.627 ;
     RECT  36.528 68.485 38.232 68.725 ;
     RECT  20.736 67.811 21.72 68.773 ;
     RECT  22.704 67.811 25.272 68.773 ;
     RECT  42.768 66.227 43.212 68.773 ;
     RECT  2.4 66.227 2.712 68.869 ;
     RECT  3.696 67.859 5.688 68.869 ;
     RECT  36.432 68.725 38.232 68.869 ;
     RECT  39.312 67.859 40.512 68.869 ;
     RECT  45.6 66.755 45.912 68.869 ;
     RECT  15.504 67.331 16.212 68.917 ;
     RECT  52.848 68.339 71.208 68.917 ;
     RECT  10.032 67.861 11.4 68.965 ;
     RECT  45.6 68.869 46.056 69.013 ;
     RECT  47.472 68.341 49.656 69.013 ;
     RECT  20.736 68.773 25.272 69.061 ;
     RECT  26.352 68.149 27.528 69.061 ;
     RECT  36.432 68.869 40.512 69.061 ;
     RECT  45.6 69.013 49.656 69.203 ;
     RECT  10.032 68.965 11.496 69.251 ;
     RECT  49.584 69.203 49.656 69.251 ;
     RECT  15.408 68.917 16.212 69.253 ;
     RECT  17.664 67.765 19.56 69.253 ;
     RECT  33.648 68.195 33.672 69.253 ;
     RECT  34.8 68.147 35.112 69.253 ;
     RECT  72.336 68.483 72.912 69.253 ;
     RECT  2.4 68.869 5.688 69.299 ;
     RECT  13.056 68.387 13.656 69.349 ;
     RECT  36.432 69.061 40.776 69.443 ;
     RECT  38.88 69.443 38.904 69.491 ;
     RECT  15.408 69.253 19.56 69.493 ;
     RECT  20.736 69.061 27.528 69.493 ;
     RECT  32.1 68.243 32.412 69.493 ;
     RECT  51 68.435 51.312 69.493 ;
     RECT  52.848 68.917 71.256 69.493 ;
     RECT  72.288 69.253 72.912 69.493 ;
     RECT  45.6 69.203 48.612 69.539 ;
     RECT  15.408 69.493 28.152 69.635 ;
     RECT  15.408 69.635 25.272 69.731 ;
     RECT  40.032 69.443 40.776 69.733 ;
     RECT  41.76 67.859 41.784 69.733 ;
     RECT  7.392 68.243 8.112 69.829 ;
     RECT  12.192 69.349 13.656 69.829 ;
     RECT  31.872 69.493 32.412 69.829 ;
     RECT  33.648 69.253 35.112 69.829 ;
     RECT  52.32 69.493 73.128 69.829 ;
     RECT  2.4 69.299 5.544 70.019 ;
     RECT  10.032 69.251 10.812 70.069 ;
     RECT  52.32 69.829 73.176 70.069 ;
     RECT  4.224 70.019 5.544 70.163 ;
     RECT  52.32 70.069 73.224 70.165 ;
     RECT  31.872 69.829 35.112 70.259 ;
     RECT  30.864 69.349 30.888 70.261 ;
     RECT  50.88 69.493 51.312 70.405 ;
     RECT  52.32 70.165 73.272 70.405 ;
     RECT  30.816 70.261 30.888 70.549 ;
     RECT  47.472 69.539 48.612 70.549 ;
     RECT  6.672 69.829 8.112 70.597 ;
     RECT  12.192 69.829 14.232 70.597 ;
     RECT  15.408 69.731 17.448 70.597 ;
     RECT  30.768 70.549 30.888 70.645 ;
     RECT  31.872 70.259 33.144 70.645 ;
     RECT  42.768 68.773 43.512 70.645 ;
     RECT  44.544 69.925 44.568 70.645 ;
     RECT  45.6 69.539 46.2 70.645 ;
     RECT  47.376 70.549 48.612 70.645 ;
     RECT  50.88 70.405 73.272 70.645 ;
     RECT  26.7 69.635 28.152 70.739 ;
     RECT  36.432 69.443 37.812 70.739 ;
     RECT  18.6 69.731 25.272 70.787 ;
     RECT  30.768 70.645 33.144 70.787 ;
     RECT  12.192 70.597 17.448 70.835 ;
     RECT  36.432 70.739 36.456 70.835 ;
     RECT  42.768 70.645 44.568 70.835 ;
     RECT  50.832 70.645 73.272 70.835 ;
     RECT  6.672 70.597 8.52 70.885 ;
     RECT  18.6 70.787 24.504 71.075 ;
     RECT  40.032 69.733 41.784 71.075 ;
     RECT  13.056 70.835 17.448 71.123 ;
     RECT  34.416 70.259 35.112 71.221 ;
     RECT  40.2 71.075 41.784 71.221 ;
     RECT  42.768 70.835 44.136 71.221 ;
     RECT  4.224 70.163 5.412 71.315 ;
     RECT  20.736 71.075 24.504 71.315 ;
     RECT  6.672 70.885 8.616 71.365 ;
     RECT  26.7 70.739 27.528 71.365 ;
     RECT  45.6 70.645 48.612 71.461 ;
     RECT  49.584 69.251 49.608 71.461 ;
     RECT  29.4 66.899 29.712 71.509 ;
     RECT  30.768 70.787 32.412 71.509 ;
     RECT  6.384 71.365 8.616 71.605 ;
     RECT  9.936 70.069 10.812 71.605 ;
     RECT  23.28 71.315 24.504 71.843 ;
     RECT  45.36 71.461 49.608 71.843 ;
     RECT  50.832 70.835 73.224 71.843 ;
     RECT  6.384 71.605 10.812 71.891 ;
     RECT  33.456 71.221 35.352 71.891 ;
     RECT  45.36 71.843 46.488 71.939 ;
     RECT  40.2 71.221 44.136 72.037 ;
     RECT  50.832 71.843 51.864 72.131 ;
     RECT  39.888 72.037 44.136 72.179 ;
     RECT  15.504 71.123 17.448 72.229 ;
     RECT  18.6 71.075 19.656 72.229 ;
     RECT  6.384 71.891 8.28 72.275 ;
     RECT  26.256 71.365 27.528 72.325 ;
     RECT  13.056 71.123 13.704 72.419 ;
     RECT  20.736 71.315 21.864 72.419 ;
     RECT  34.416 71.891 35.352 72.419 ;
     RECT  48.3 71.843 49.608 72.419 ;
     RECT  39.888 72.179 43.32 72.467 ;
     RECT  52.848 71.843 73.224 72.469 ;
     RECT  4.992 71.315 5.412 72.659 ;
     RECT  13.056 72.419 13.608 72.659 ;
     RECT  9.312 71.891 10.812 72.661 ;
     RECT  29.4 71.509 32.412 72.757 ;
     RECT  29.4 72.757 33.048 72.803 ;
     RECT  5.1 72.659 5.412 72.805 ;
     RECT  9.312 72.661 11.208 72.851 ;
     RECT  39.888 72.467 40.776 72.851 ;
     RECT  18.48 72.229 19.656 72.901 ;
     RECT  37.5 70.739 37.812 72.901 ;
     RECT  41.76 72.467 43.32 72.947 ;
     RECT  51 72.131 51.864 72.949 ;
     RECT  52.848 72.469 73.512 72.949 ;
     RECT  51 72.949 73.512 72.995 ;
     RECT  13.056 72.659 13.512 72.997 ;
     RECT  26.208 72.325 27.528 72.997 ;
     RECT  2.4 70.019 2.712 73.333 ;
     RECT  20.784 72.419 21.864 73.333 ;
     RECT  32.1 72.803 33.048 73.333 ;
     RECT  9.312 72.851 10.812 73.379 ;
     RECT  15.072 72.229 17.448 73.429 ;
     RECT  18.48 72.901 19.752 73.429 ;
     RECT  5.1 72.805 5.544 73.477 ;
     RECT  6.624 72.275 8.28 73.477 ;
     RECT  45.36 71.939 46.056 73.477 ;
     RECT  48.3 72.419 49.176 73.477 ;
     RECT  15.072 73.429 19.752 73.525 ;
     RECT  20.784 73.333 22.056 73.525 ;
     RECT  5.1 73.477 8.28 73.571 ;
     RECT  12.528 72.997 13.512 73.717 ;
     RECT  6.672 73.571 8.28 73.763 ;
     RECT  26.208 72.997 28.248 73.763 ;
     RECT  15.072 73.525 22.056 73.861 ;
     RECT  34.416 72.419 35.112 73.861 ;
     RECT  14.88 73.861 22.056 73.907 ;
     RECT  17.616 73.907 22.056 74.053 ;
     RECT  23.808 71.843 24.504 74.053 ;
     RECT  2.4 73.333 3.144 74.147 ;
     RECT  39.888 72.851 40.632 74.147 ;
     RECT  23.808 74.053 25.656 74.197 ;
     RECT  47.472 73.477 49.176 74.243 ;
     RECT  51 72.995 73.128 74.293 ;
     RECT  47.856 74.243 49.176 74.339 ;
     RECT  32.1 73.333 33.24 74.389 ;
     RECT  34.416 73.861 35.208 74.389 ;
     RECT  50.688 74.293 73.128 74.389 ;
     RECT  26.7 73.763 28.248 74.437 ;
     RECT  45.36 73.477 46.248 74.483 ;
     RECT  50.688 74.389 73.176 74.627 ;
     RECT  32.1 74.389 35.208 74.629 ;
     RECT  37.056 72.901 37.812 74.677 ;
     RECT  42.9 72.947 43.32 74.677 ;
     RECT  5.1 73.571 5.688 74.723 ;
     RECT  6.816 73.763 8.28 74.773 ;
     RECT  9.312 73.379 9.336 74.773 ;
     RECT  14.88 73.907 16.212 74.869 ;
     RECT  6.816 74.773 9.336 74.965 ;
     RECT  10.5 73.379 10.812 74.965 ;
     RECT  12.528 73.717 13.608 74.965 ;
     RECT  6.816 74.965 10.812 75.013 ;
     RECT  12.192 74.965 13.608 75.013 ;
     RECT  14.88 74.869 16.344 75.013 ;
     RECT  14.784 75.013 16.344 75.155 ;
     RECT  31.872 74.629 35.208 75.155 ;
     RECT  5.1 74.723 5.592 75.157 ;
     RECT  6.816 75.013 13.608 75.157 ;
     RECT  41.76 72.947 41.784 75.157 ;
     RECT  17.616 74.053 22.104 75.205 ;
     RECT  37.008 74.677 37.812 75.205 ;
     RECT  23.424 74.197 25.656 75.299 ;
     RECT  36.912 75.205 37.812 75.349 ;
     RECT  52.848 74.627 73.176 75.395 ;
     RECT  45.6 74.483 46.248 75.445 ;
     RECT  36.912 75.349 37.944 75.491 ;
     RECT  23.424 75.299 25.608 75.541 ;
     RECT  6.816 75.157 13.656 75.587 ;
     RECT  45.12 75.445 46.248 75.637 ;
     RECT  50.688 74.627 51.432 75.637 ;
     RECT  42.9 74.677 43.992 75.683 ;
     RECT  45.024 75.637 46.248 75.779 ;
     RECT  26.7 74.437 28.392 75.829 ;
     RECT  29.4 72.803 30.84 75.829 ;
     RECT  10.5 75.587 13.656 75.971 ;
     RECT  10.5 75.971 13.512 76.019 ;
     RECT  14.832 75.155 16.344 76.019 ;
     RECT  36.912 75.491 37.812 76.019 ;
     RECT  45.6 75.779 46.248 76.067 ;
     RECT  34.8 75.155 35.208 76.261 ;
     RECT  36.24 76.069 36.264 76.261 ;
     RECT  17.424 75.205 22.104 76.307 ;
     RECT  18.6 76.307 22.104 76.309 ;
     RECT  23.328 75.541 25.608 76.309 ;
     RECT  17.424 76.307 17.544 76.355 ;
     RECT  26.7 75.829 30.84 76.357 ;
     RECT  31.872 75.155 33.24 76.357 ;
     RECT  39.984 74.147 40.632 76.357 ;
     RECT  41.76 75.157 41.88 76.357 ;
     RECT  26.7 76.357 33.24 76.453 ;
     RECT  39.984 76.357 41.88 76.501 ;
     RECT  47.856 74.339 48.612 76.501 ;
     RECT  47.808 76.501 48.612 76.597 ;
     RECT  4.56 75.157 5.592 76.837 ;
     RECT  52.848 75.395 73.08 76.885 ;
     RECT  39.792 76.501 41.88 76.933 ;
     RECT  50.688 75.637 51.528 76.979 ;
     RECT  52.848 76.885 73.416 77.029 ;
     RECT  45.6 76.067 46.2 77.077 ;
     RECT  47.568 76.597 48.612 77.125 ;
     RECT  26.7 76.453 33.48 77.171 ;
     RECT  10.5 76.019 10.812 77.173 ;
     RECT  45.168 77.077 46.2 77.363 ;
     RECT  39.648 76.933 41.88 77.365 ;
     RECT  42.9 75.683 43.32 77.365 ;
     RECT  18.6 76.309 25.608 77.413 ;
     RECT  37.5 76.019 37.812 77.461 ;
     RECT  52.848 77.029 73.512 77.509 ;
     RECT  28.752 77.171 33.48 77.555 ;
     RECT  34.8 76.261 36.264 77.555 ;
     RECT  4.464 76.837 5.592 77.653 ;
     RECT  6.816 75.587 9.192 77.653 ;
     RECT  4.464 77.653 9.192 77.701 ;
     RECT  10.368 77.173 10.812 77.701 ;
     RECT  39.648 77.365 43.32 77.701 ;
     RECT  50.688 76.979 51.48 77.701 ;
     RECT  29.088 77.555 33.48 77.795 ;
     RECT  14.832 76.019 16.212 77.845 ;
     RECT  17.52 76.355 17.544 77.845 ;
     RECT  14.832 77.845 17.544 77.891 ;
     RECT  12.192 76.019 13.512 77.893 ;
     RECT  18.6 77.413 25.656 77.939 ;
     RECT  50.4 77.701 51.48 77.941 ;
     RECT  52.512 77.509 73.512 77.941 ;
     RECT  3.936 77.701 10.812 77.987 ;
     RECT  2.4 74.147 2.712 77.989 ;
     RECT  3.936 77.987 8.112 77.989 ;
     RECT  45.6 77.363 46.2 77.989 ;
     RECT  47.232 77.125 48.612 77.989 ;
     RECT  50.4 77.941 73.512 78.085 ;
     RECT  18.6 77.939 25.032 78.227 ;
     RECT  26.7 77.171 27.528 78.227 ;
     RECT  12 77.893 13.512 78.613 ;
     RECT  14.832 77.891 17.496 78.613 ;
     RECT  34.8 77.555 35.784 78.659 ;
     RECT  12 78.613 17.496 78.707 ;
     RECT  9.168 77.987 10.812 78.755 ;
     RECT  15.312 78.707 17.496 78.755 ;
     RECT  19.968 78.227 25.032 78.755 ;
     RECT  45.6 77.989 48.612 78.755 ;
     RECT  20.256 78.755 25.032 79.045 ;
     RECT  37.5 77.461 38.088 79.045 ;
     RECT  39.216 77.701 43.32 79.045 ;
     RECT  44.496 78.517 44.52 79.189 ;
     RECT  47.232 78.755 48.612 79.189 ;
     RECT  29.088 77.795 33.144 79.283 ;
     RECT  44.448 79.189 44.52 79.285 ;
     RECT  37.5 79.045 43.32 79.331 ;
     RECT  47.232 79.189 48.744 79.331 ;
     RECT  2.4 77.989 8.112 79.475 ;
     RECT  20.256 79.045 25.08 79.475 ;
     RECT  29.4 79.283 33.144 79.475 ;
     RECT  44.448 79.285 44.616 79.475 ;
     RECT  50.16 78.085 73.512 79.475 ;
     RECT  15.504 78.755 17.496 79.765 ;
     RECT  18.6 78.227 18.912 79.765 ;
     RECT  42.9 79.331 43.32 79.765 ;
     RECT  45.6 78.755 45.912 79.765 ;
     RECT  47.568 79.331 48.744 79.765 ;
     RECT  15.504 79.765 18.912 79.813 ;
     RECT  26.7 78.227 27.48 80.053 ;
     RECT  3.888 79.475 8.112 80.147 ;
     RECT  32.1 79.475 33.144 80.291 ;
     RECT  44.448 79.475 44.52 80.291 ;
     RECT  3.936 80.147 8.112 80.293 ;
     RECT  9.552 78.755 10.812 80.293 ;
     RECT  39.648 79.331 41.88 80.293 ;
     RECT  42.9 79.765 43.368 80.293 ;
     RECT  12 78.707 14.232 80.531 ;
     RECT  26.7 80.053 27.912 80.533 ;
     RECT  47.568 79.765 48.984 80.627 ;
     RECT  50.4 79.475 73.512 80.627 ;
     RECT  26.496 80.533 27.912 80.629 ;
     RECT  39.648 80.293 43.368 80.629 ;
     RECT  29.4 79.475 31.128 80.677 ;
     RECT  32.1 80.291 32.712 80.677 ;
     RECT  37.5 79.331 38.52 80.677 ;
     RECT  37.392 80.677 38.52 80.819 ;
     RECT  47.568 80.627 48.792 80.819 ;
     RECT  29.4 80.677 32.712 80.869 ;
     RECT  37.392 80.819 38.28 80.869 ;
     RECT  39.648 80.629 43.416 80.869 ;
     RECT  15.504 79.813 19.992 80.963 ;
     RECT  21.024 79.475 24.312 80.963 ;
     RECT  25.584 80.629 27.912 80.963 ;
     RECT  29.28 80.869 32.712 81.011 ;
     RECT  3.936 80.293 10.812 81.059 ;
     RECT  36.24 79.189 36.264 81.157 ;
     RECT  37.296 80.869 38.28 81.157 ;
     RECT  15.504 80.963 16.488 81.301 ;
     RECT  17.472 80.963 19.992 81.301 ;
     RECT  21.024 80.963 21.612 81.301 ;
     RECT  34.8 78.659 35.112 81.301 ;
     RECT  39.648 80.869 43.896 81.347 ;
     RECT  25.584 80.963 27.864 81.349 ;
     RECT  36.24 81.157 38.28 81.395 ;
     RECT  41.856 81.347 43.896 81.445 ;
     RECT  45.6 79.765 46.344 81.445 ;
     RECT  34.8 81.301 35.208 81.491 ;
     RECT  37.056 81.395 38.28 81.491 ;
     RECT  3.936 81.059 6.696 81.539 ;
     RECT  12 80.531 13.512 81.539 ;
     RECT  48.3 80.819 48.792 81.587 ;
     RECT  50.496 80.627 73.512 81.637 ;
     RECT  34.8 81.491 35.112 81.781 ;
     RECT  41.856 81.445 46.344 81.875 ;
     RECT  22.608 80.963 24.312 81.877 ;
     RECT  25.488 81.349 27.864 81.877 ;
     RECT  29.28 81.011 32.412 81.923 ;
     RECT  3.936 81.539 5.976 82.021 ;
     RECT  22.608 81.877 27.864 82.115 ;
     RECT  41.856 81.875 43.656 82.115 ;
     RECT  44.64 81.875 46.344 82.115 ;
     RECT  7.68 81.059 10.812 82.259 ;
     RECT  39.648 81.347 40.872 82.405 ;
     RECT  37.296 81.491 38.28 82.645 ;
     RECT  39.648 82.405 41.064 82.645 ;
     RECT  22.608 82.115 24.696 82.691 ;
     RECT  34.128 81.781 35.112 82.691 ;
     RECT  44.64 82.115 45.912 82.691 ;
     RECT  37.296 82.645 41.064 82.693 ;
     RECT  3.744 82.021 5.976 82.789 ;
     RECT  7.68 82.259 8.808 82.789 ;
     RECT  12.48 81.539 13.512 82.789 ;
     RECT  14.832 81.301 16.488 82.789 ;
     RECT  17.472 81.301 21.612 82.789 ;
     RECT  3.744 82.789 8.808 82.931 ;
     RECT  10.368 82.259 10.812 82.933 ;
     RECT  49.584 81.637 73.512 82.933 ;
     RECT  10.368 82.933 11.4 82.979 ;
     RECT  12.48 82.789 21.612 83.027 ;
     RECT  15.9 83.027 21.612 83.075 ;
     RECT  37.056 82.693 41.064 83.075 ;
     RECT  26.352 82.115 27.864 83.077 ;
     RECT  22.8 82.691 24.696 83.123 ;
     RECT  15.9 83.075 16.488 83.219 ;
     RECT  44.976 82.691 45.912 83.221 ;
     RECT  12.48 83.027 14.856 83.315 ;
     RECT  22.8 83.123 24.6 83.603 ;
     RECT  7.68 82.931 8.808 83.651 ;
     RECT  7.8 83.651 8.808 83.653 ;
     RECT  34.8 82.691 35.112 83.653 ;
     RECT  29.4 81.923 32.412 83.701 ;
     RECT  34.8 83.653 35.88 83.749 ;
     RECT  37.344 83.075 41.064 83.749 ;
     RECT  42.048 82.115 43.656 83.749 ;
     RECT  44.976 83.221 46.728 83.749 ;
     RECT  10.5 82.979 11.4 83.843 ;
     RECT  12.48 83.315 14.088 83.843 ;
     RECT  22.8 83.603 24.504 83.843 ;
     RECT  49.584 82.933 74.088 83.843 ;
     RECT  37.344 83.749 46.728 83.939 ;
     RECT  48.3 81.587 48.612 83.941 ;
     RECT  34.176 83.749 35.88 84.083 ;
     RECT  37.344 83.939 44.472 84.083 ;
     RECT  47.856 83.941 48.612 84.133 ;
     RECT  49.584 83.843 54.264 84.133 ;
     RECT  45.504 83.939 46.728 84.181 ;
     RECT  47.856 84.133 54.264 84.181 ;
     RECT  37.344 84.083 43.416 84.325 ;
     RECT  26.352 83.077 27.96 84.371 ;
     RECT  36.816 84.325 43.416 84.419 ;
     RECT  45.504 84.181 54.264 84.419 ;
     RECT  26.352 84.371 27.336 84.421 ;
     RECT  25.728 84.421 27.336 84.563 ;
     RECT  7.8 83.653 8.952 84.611 ;
     RECT  36.816 84.419 43.212 84.611 ;
     RECT  44.448 84.083 44.472 84.611 ;
     RECT  29.4 83.701 32.52 84.613 ;
     RECT  45.6 84.419 54.264 84.659 ;
     RECT  45.6 84.659 49.944 84.707 ;
     RECT  15.9 83.219 16.392 84.709 ;
     RECT  51 84.659 54.264 84.805 ;
     RECT  55.248 83.843 74.088 84.805 ;
     RECT  12.48 83.843 13.512 84.853 ;
     RECT  22.992 83.843 24.504 84.853 ;
     RECT  29.088 84.613 32.52 84.853 ;
     RECT  12.48 84.853 13.704 84.901 ;
     RECT  17.472 83.075 21.612 84.995 ;
     RECT  7.8 84.611 8.52 85.139 ;
     RECT  47.856 84.707 49.944 85.139 ;
     RECT  34.176 84.083 35.352 85.237 ;
     RECT  42.144 84.611 43.212 85.381 ;
     RECT  10.5 83.843 10.812 85.429 ;
     RECT  12 84.901 13.704 85.429 ;
     RECT  26.208 84.563 27.336 85.475 ;
     RECT  51 84.805 74.088 85.523 ;
     RECT  3.744 82.931 6.648 85.619 ;
     RECT  51 85.523 74.04 85.619 ;
     RECT  22.8 84.853 24.504 85.717 ;
     RECT  10.5 85.429 13.704 85.765 ;
     RECT  44.544 85.093 44.568 85.813 ;
     RECT  45.6 84.707 46.776 85.813 ;
     RECT  4.272 85.619 6.648 85.907 ;
     RECT  22.8 85.717 24.84 85.955 ;
     RECT  22.992 85.955 24.84 85.957 ;
     RECT  26.208 85.475 27.288 85.957 ;
     RECT  28.512 84.853 32.52 85.957 ;
     RECT  33.696 85.237 35.352 85.957 ;
     RECT  22.992 85.957 27.288 86.099 ;
     RECT  10.5 85.765 13.752 86.243 ;
     RECT  36.816 84.611 40.872 86.293 ;
     RECT  42.144 85.381 43.32 86.293 ;
     RECT  10.5 86.243 13.704 86.339 ;
     RECT  22.992 86.099 27.144 86.483 ;
     RECT  44.544 85.813 46.776 86.483 ;
     RECT  51 85.619 52.392 86.485 ;
     RECT  28.512 85.957 35.352 86.579 ;
     RECT  44.976 86.483 46.776 86.629 ;
     RECT  47.856 85.139 49.704 86.629 ;
     RECT  4.272 85.907 5.88 86.675 ;
     RECT  28.512 86.579 35.208 86.675 ;
     RECT  10.5 86.339 13.512 86.723 ;
     RECT  28.944 86.675 35.208 86.771 ;
     RECT  36.816 86.293 43.32 86.869 ;
     RECT  4.272 86.675 5.832 86.917 ;
     RECT  22.992 86.483 24.504 87.061 ;
     RECT  7.8 85.139 8.376 87.109 ;
     RECT  9.504 85.429 9.528 87.109 ;
     RECT  17.472 84.995 19.992 87.109 ;
     RECT  15.216 84.709 16.392 87.155 ;
     RECT  28.944 86.771 35.112 87.251 ;
     RECT  15.216 87.155 16.344 87.299 ;
     RECT  36.48 86.869 43.32 87.299 ;
     RECT  15.792 87.299 16.212 87.347 ;
     RECT  32.1 87.251 35.112 87.347 ;
     RECT  28.944 87.251 30.936 87.539 ;
     RECT  53.376 85.619 74.04 87.635 ;
     RECT  25.68 86.483 27.144 87.683 ;
     RECT  44.976 86.629 49.704 87.683 ;
     RECT  7.8 87.109 9.528 87.685 ;
     RECT  10.5 86.723 11.688 87.685 ;
     RECT  47.328 87.683 49.704 87.685 ;
     RECT  50.88 86.485 52.392 87.685 ;
     RECT  56.016 87.635 74.04 87.685 ;
     RECT  28.944 87.539 30.792 87.733 ;
     RECT  3.936 86.917 5.832 87.827 ;
     RECT  22.752 87.061 24.504 87.827 ;
     RECT  33.696 87.347 35.112 87.827 ;
     RECT  3.936 87.827 5.688 87.971 ;
     RECT  28.32 87.733 30.792 88.019 ;
     RECT  28.32 88.019 30.264 88.067 ;
     RECT  7.8 87.685 11.688 88.069 ;
     RECT  7.44 88.069 11.688 88.115 ;
     RECT  26.4 87.683 27.144 88.115 ;
     RECT  22.992 87.827 24.504 88.163 ;
     RECT  7.44 88.115 11.592 88.211 ;
     RECT  47.328 87.685 52.392 88.355 ;
     RECT  17.472 87.109 20.184 88.403 ;
     RECT  34.416 87.827 35.112 88.403 ;
     RECT  36.48 87.299 41.592 88.403 ;
     RECT  42.9 87.299 43.32 88.403 ;
     RECT  21.3 84.995 21.612 88.405 ;
     RECT  23.136 88.163 24.504 88.451 ;
     RECT  17.904 88.403 20.184 88.499 ;
     RECT  47.328 88.355 52.296 88.499 ;
     RECT  53.376 87.635 54.888 88.499 ;
     RECT  47.328 88.499 48.612 88.595 ;
     RECT  7.44 88.211 9.288 88.643 ;
     RECT  28.32 88.067 28.344 88.643 ;
     RECT  53.376 88.499 54.792 88.643 ;
     RECT  15.9 87.347 16.212 88.645 ;
     RECT  26.7 88.115 27.144 88.645 ;
     RECT  44.976 87.683 46.152 88.741 ;
     RECT  7.44 88.643 9.096 88.883 ;
     RECT  14.544 88.309 14.568 88.885 ;
     RECT  4.896 87.971 5.688 88.979 ;
     RECT  14.544 88.885 14.808 88.979 ;
     RECT  23.232 88.451 24.504 89.027 ;
     RECT  56.016 87.685 74.088 89.027 ;
     RECT  26.7 88.645 27.24 89.219 ;
     RECT  50.112 88.499 52.296 89.219 ;
     RECT  53.376 88.643 54.744 89.219 ;
     RECT  50.112 89.219 52.248 89.267 ;
     RECT  53.568 89.219 54.744 89.459 ;
     RECT  4.896 88.979 5.412 89.461 ;
     RECT  17.904 88.499 20.04 89.507 ;
     RECT  47.904 88.595 48.612 89.507 ;
     RECT  53.568 89.459 54.696 89.507 ;
     RECT  10.5 88.211 11.496 89.555 ;
     RECT  15.9 88.645 16.344 89.555 ;
     RECT  21.168 88.405 21.612 89.555 ;
     RECT  36.576 88.403 41.592 89.555 ;
     RECT  50.736 89.267 52.248 89.555 ;
     RECT  56.016 89.027 74.04 89.603 ;
     RECT  44.688 88.741 46.152 89.699 ;
     RECT  56.064 89.603 74.04 89.699 ;
     RECT  13.056 86.723 13.512 89.843 ;
     RECT  14.784 88.979 14.808 89.987 ;
     RECT  44.976 89.699 46.152 89.987 ;
     RECT  53.7 89.507 54.696 89.987 ;
     RECT  56.304 89.699 74.04 89.987 ;
     RECT  17.904 89.507 19.368 90.035 ;
     RECT  32.1 87.347 32.52 90.035 ;
     RECT  17.904 90.035 18.912 90.083 ;
     RECT  29.4 88.067 30.264 90.083 ;
     RECT  39.312 89.555 41.592 90.083 ;
     RECT  50.832 89.555 52.248 90.083 ;
     RECT  58.944 89.987 74.04 90.083 ;
     RECT  56.304 89.987 57.576 90.131 ;
     RECT  7.8 88.883 9.096 90.227 ;
     RECT  23.232 89.027 24.456 90.227 ;
     RECT  56.304 90.131 57.48 90.227 ;
     RECT  4.8 89.461 5.412 90.275 ;
     RECT  24 90.227 24.456 90.275 ;
     RECT  36.576 89.555 37.812 90.275 ;
     RECT  45.6 89.987 46.152 90.275 ;
     RECT  58.944 90.083 73.128 90.275 ;
     RECT  56.304 90.227 56.808 90.323 ;
     RECT  58.944 90.275 73.032 90.323 ;
     RECT  58.944 90.323 66.12 90.371 ;
     RECT  67.104 90.323 73.032 90.371 ;
     RECT  71.664 90.371 72.912 90.419 ;
     RECT  63.648 90.371 66.12 90.467 ;
     RECT  40.2 90.083 41.592 90.515 ;
     RECT  51 90.083 52.248 90.515 ;
     RECT  56.4 90.323 56.808 90.515 ;
     RECT  63.648 90.467 65.4 90.515 ;
     RECT  10.5 89.555 11.4 90.563 ;
     RECT  37.392 90.275 37.812 90.563 ;
     RECT  45.6 90.275 46.104 90.563 ;
     RECT  59.1 90.371 62.112 90.563 ;
     RECT  67.104 90.371 70.212 90.563 ;
     RECT  60.96 90.563 62.112 90.611 ;
     RECT  64.272 90.515 64.812 90.611 ;
     RECT  67.104 90.563 68.616 90.611 ;
     RECT  67.2 90.611 68.04 90.659 ;
     RECT  2.4 79.475 2.712 90.729 ;
     RECT  5.1 90.275 5.412 90.729 ;
     RECT  7.8 90.227 8.112 90.729 ;
     RECT  10.5 90.563 10.812 90.729 ;
     RECT  13.2 89.843 13.512 90.729 ;
     RECT  15.9 89.555 16.212 90.729 ;
     RECT  18.6 90.083 18.912 90.729 ;
     RECT  21.3 89.555 21.612 90.729 ;
     RECT  24 90.275 24.312 90.729 ;
     RECT  26.7 89.219 27.012 90.729 ;
     RECT  29.4 90.083 29.712 90.729 ;
     RECT  32.1 90.035 32.412 90.729 ;
     RECT  34.8 88.403 35.112 90.729 ;
     RECT  37.5 90.563 37.812 90.729 ;
     RECT  40.2 90.515 40.512 90.729 ;
     RECT  42.9 88.403 43.212 90.729 ;
     RECT  45.6 90.563 45.912 90.729 ;
     RECT  48.3 89.507 48.612 90.729 ;
     RECT  51 90.515 51.312 90.729 ;
     RECT  53.7 89.987 54.012 90.729 ;
     RECT  56.4 90.515 56.712 90.729 ;
     RECT  59.1 90.563 59.412 90.729 ;
     RECT  61.8 90.611 62.112 90.729 ;
     RECT  64.5 90.611 64.812 90.729 ;
     RECT  67.2 90.659 67.512 90.729 ;
     RECT  69.9 90.563 70.212 90.729 ;
     RECT  72.6 90.419 72.912 90.729 ;
     RECT  2.4 90.729 2.52 90.743 ;
     RECT  5.1 90.729 5.22 90.743 ;
     RECT  7.8 90.729 7.92 90.743 ;
     RECT  10.5 90.729 10.62 90.743 ;
     RECT  13.2 90.729 13.32 90.743 ;
     RECT  15.9 90.729 16.02 90.743 ;
     RECT  18.6 90.729 18.72 90.743 ;
     RECT  21.3 90.729 21.42 90.743 ;
     RECT  24 90.729 24.12 90.743 ;
     RECT  26.7 90.729 26.82 90.743 ;
     RECT  29.4 90.729 29.52 90.743 ;
     RECT  32.1 90.729 32.22 90.743 ;
     RECT  34.8 90.729 34.92 90.743 ;
     RECT  37.5 90.729 37.62 90.743 ;
     RECT  40.2 90.729 40.32 90.743 ;
     RECT  42.9 90.729 43.02 90.743 ;
     RECT  45.6 90.729 45.72 90.743 ;
     RECT  48.3 90.729 48.42 90.743 ;
     RECT  51 90.729 51.12 90.743 ;
     RECT  53.7 90.729 53.82 90.743 ;
     RECT  56.4 90.729 56.52 90.743 ;
     RECT  59.1 90.729 59.22 90.743 ;
     RECT  61.8 90.729 61.92 90.743 ;
     RECT  64.5 90.729 64.62 90.743 ;
     RECT  67.2 90.729 67.32 90.743 ;
     RECT  69.9 90.729 70.02 90.743 ;
     RECT  72.6 90.729 72.72 90.743 ;
     RECT  66.696 2.005 67.92 2.053 ;
     RECT  61.92 2.137 63.408 2.151 ;
     RECT  64.62 2.137 66.048 2.149 ;
     RECT  64.62 2.149 65.904 2.151 ;
     RECT  70.02 2.149 71.184 2.151 ;
     RECT  71.208 2.149 72.6 2.197 ;
     RECT  62.112 2.151 63.408 2.197 ;
     RECT  64.812 2.151 65.904 2.197 ;
     RECT  70.212 2.151 71.184 2.197 ;
     RECT  62.112 2.197 63.312 2.437 ;
     RECT  71.448 2.197 72.6 2.245 ;
     RECT  29.712 2.245 30.72 2.629 ;
     RECT  30.744 2.245 32.1 3.397 ;
     RECT  44.184 2.245 45.6 4.307 ;
     RECT  54.552 2.245 55.728 2.581 ;
     RECT  48.612 2.629 50.112 3.443 ;
     RECT  51.864 2.773 53.328 2.821 ;
     RECT  57.048 2.773 58.512 2.965 ;
     RECT  40.512 2.821 41.568 3.157 ;
     RECT  41.592 2.821 42.9 3.443 ;
     RECT  51.864 2.821 53.04 3.635 ;
     RECT  47.016 2.869 48.3 3.925 ;
     RECT  57.048 2.965 58.128 3.877 ;
     RECT  13.704 3.157 14.736 6.371 ;
     RECT  14.76 3.157 15.9 4.165 ;
     RECT  18.912 3.157 19.968 3.397 ;
     RECT  19.992 3.157 21.072 3.397 ;
     RECT  35.88 3.157 37.392 3.875 ;
     RECT  18.912 3.397 19.92 4.213 ;
     RECT  22.44 3.397 23.712 4.501 ;
     RECT  40.968 3.443 41.16 4.789 ;
     RECT  51.312 3.635 53.04 3.925 ;
     RECT  11.736 3.685 13.2 3.973 ;
     RECT  16.212 3.829 17.568 3.973 ;
     RECT  38.232 3.877 39.312 3.971 ;
     RECT  57.096 3.877 58.128 3.925 ;
     RECT  9.096 3.925 10.5 6.229 ;
     RECT  51.312 3.925 52.608 5.221 ;
     RECT  37.992 3.971 39.312 5.605 ;
     RECT  11.736 3.973 13.104 4.981 ;
     RECT  24.744 4.261 26.256 4.741 ;
     RECT  14.76 4.307 15.9 5.461 ;
     RECT  22.44 4.501 23.52 5.269 ;
     RECT  33.144 4.501 34.56 4.645 ;
     RECT  33.192 4.645 34.56 5.795 ;
     RECT  25.128 4.741 26.256 4.979 ;
     RECT  5.688 4.837 6.72 5.363 ;
     RECT  6.744 4.837 7.8 5.317 ;
     RECT  24.648 4.979 26.256 5.027 ;
     RECT  11.736 4.981 12.912 7.957 ;
     RECT  26.112 5.027 26.256 5.989 ;
     RECT  35.4 5.123 35.784 6.133 ;
     RECT  51.312 5.221 52.32 5.365 ;
     RECT  5.688 5.363 6.816 6.515 ;
     RECT  14.76 5.461 15.792 5.557 ;
     RECT  41.16 5.653 42.144 5.845 ;
     RECT  19.992 5.747 21.072 7.621 ;
     RECT  43.656 5.747 43.8 6.373 ;
     RECT  26.112 5.989 26.208 6.421 ;
     RECT  37.812 6.035 38.832 6.851 ;
     RECT  9.096 6.229 10.224 6.995 ;
     RECT  48.744 6.229 50.16 6.373 ;
     RECT  15.36 6.371 15.552 7.333 ;
     RECT  43.656 6.373 44.976 6.805 ;
     RECT  48.744 6.373 50.112 7.285 ;
     RECT  5.544 6.515 6.816 6.899 ;
     RECT  37.812 6.851 39.408 6.899 ;
     RECT  5.544 6.899 6.96 7.283 ;
     RECT  37.812 6.899 39.456 7.861 ;
     RECT  4.368 6.947 5.1 7.381 ;
     RECT  8.808 6.995 10.224 8.003 ;
     RECT  35.352 7.091 35.4 8.437 ;
     RECT  5.412 7.283 6.96 8.533 ;
     RECT  48.744 7.285 50.016 7.861 ;
     RECT  23.28 7.379 23.712 8.389 ;
     RECT  3.624 7.381 5.1 8.291 ;
     RECT  33.048 7.427 33.144 8.437 ;
     RECT  16.584 7.475 17.568 7.955 ;
     RECT  40.632 7.619 41.616 8.965 ;
     RECT  38.136 7.861 39.456 8.051 ;
     RECT  16.536 7.955 17.568 8.963 ;
     RECT  19.416 7.955 20.592 8.099 ;
     RECT  25.272 7.955 26.7 8.099 ;
     RECT  8.808 8.003 10.5 8.389 ;
     RECT  15.36 8.003 15.744 8.293 ;
     RECT  38.136 8.051 39.888 8.341 ;
     RECT  19.416 8.099 20.832 9.781 ;
     RECT  24.312 8.099 26.7 8.965 ;
     RECT  11.4 8.195 12.672 9.685 ;
     RECT  4.512 8.291 5.1 8.389 ;
     RECT  29.712 8.291 30.912 9.539 ;
     RECT  13.992 8.293 15.744 8.965 ;
     RECT  38.616 8.341 39.888 10.115 ;
     RECT  9.24 8.389 10.5 9.301 ;
     RECT  21.72 8.389 23.136 10.213 ;
     RECT  43.212 8.435 44.448 10.067 ;
     RECT  27.144 8.437 28.176 10.741 ;
     RECT  5.64 8.533 6.96 9.347 ;
     RECT  17.592 8.723 18.6 8.963 ;
     RECT  16.536 8.963 18.6 9.781 ;
     RECT  13.992 8.965 15.408 10.165 ;
     RECT  24.312 8.965 25.632 9.349 ;
     RECT  25.656 8.965 26.7 10.069 ;
     RECT  30.936 9.155 31.92 9.539 ;
     RECT  51.312 9.491 52.368 10.691 ;
     RECT  9.24 9.539 10.5 12.611 ;
     RECT  29.712 9.539 31.92 10.211 ;
     RECT  11.592 9.685 12.672 10.883 ;
     RECT  17.496 9.781 18.6 10.645 ;
     RECT  19.8 9.781 20.832 10.981 ;
     RECT  2.712 9.925 3.792 11.507 ;
     RECT  46.776 10.019 47.808 10.787 ;
     RECT  43.212 10.067 45.216 11.509 ;
     RECT  28.2 10.115 29.184 11.411 ;
     RECT  38.616 10.115 40.08 10.309 ;
     RECT  14.136 10.165 15.408 11.939 ;
     RECT  29.712 10.211 31.968 10.885 ;
     RECT  21.72 10.213 23.04 10.355 ;
     RECT  38.712 10.309 40.08 10.499 ;
     RECT  21.612 10.355 23.04 10.931 ;
     RECT  24.312 10.403 25.632 11.795 ;
     RECT  38.712 10.499 40.2 10.931 ;
     RECT  55.368 10.595 56.4 11.845 ;
     RECT  17.496 10.645 18.48 12.227 ;
     RECT  51.312 10.691 52.8 10.933 ;
     RECT  33.288 10.741 34.8 10.979 ;
     RECT  46.632 10.787 47.808 13.379 ;
     RECT  8.232 10.835 9.216 12.611 ;
     RECT  3.816 10.883 5.1 11.507 ;
     RECT  30.504 10.885 31.968 11.459 ;
     RECT  23.52 10.931 24 11.941 ;
     RECT  38.616 10.931 40.2 11.459 ;
     RECT  40.512 10.931 41.616 12.563 ;
     RECT  51.672 10.933 52.8 11.651 ;
     RECT  27.912 11.411 29.184 11.461 ;
     RECT  30.264 11.459 31.968 11.941 ;
     RECT  38.232 11.459 40.2 11.653 ;
     RECT  48.984 11.459 50.016 12.661 ;
     RECT  27.912 11.461 29.088 11.747 ;
     RECT  4.848 11.507 5.1 12.517 ;
     RECT  44.04 11.509 45.216 12.805 ;
     RECT  51.672 11.651 53.424 11.843 ;
     RECT  38.232 11.653 40.08 12.709 ;
     RECT  27.912 11.747 29.184 12.083 ;
     RECT  51.672 11.843 53.7 11.845 ;
     RECT  51.768 11.845 53.7 11.893 ;
     RECT  52.392 11.893 53.7 13.573 ;
     RECT  30.264 11.941 31.92 12.469 ;
     RECT  27.012 12.083 29.4 13.333 ;
     RECT  18.384 12.227 18.48 13.573 ;
     RECT  18.912 12.371 19.968 13.717 ;
     RECT  30.84 12.469 31.92 13.957 ;
     RECT  4.848 12.517 4.992 12.853 ;
     RECT  40.512 12.563 41.856 15.877 ;
     RECT  8.232 12.611 8.328 12.805 ;
     RECT  38.232 12.709 39.936 12.757 ;
     RECT  38.232 12.757 39.264 14.243 ;
     RECT  44.04 12.805 45.12 13.091 ;
     RECT  32.412 12.901 33.504 15.443 ;
     RECT  33.528 12.901 34.8 15.443 ;
     RECT  43.212 13.235 43.992 14.197 ;
     RECT  27.012 13.333 28.08 14.437 ;
     RECT  28.104 13.333 29.4 14.101 ;
     RECT  46.248 13.379 47.808 14.149 ;
     RECT  13.512 13.477 14.784 14.435 ;
     RECT  24.312 13.477 25.632 14.581 ;
     RECT  22.2 13.573 23.28 15.205 ;
     RECT  46.248 14.149 47.712 14.867 ;
     RECT  37.992 14.243 39.264 14.675 ;
     RECT  27.012 14.437 28.032 14.725 ;
     RECT  25.656 14.531 26.7 15.395 ;
     RECT  37.944 14.675 39.264 15.731 ;
     RECT  51.864 14.675 52.896 15.973 ;
     RECT  24.312 14.723 25.632 15.395 ;
     RECT  5.64 14.725 6.96 15.301 ;
     RECT  8.328 14.773 9.696 15.491 ;
     RECT  46.2 14.867 47.712 16.115 ;
     RECT  10.812 15.059 11.064 16.357 ;
     RECT  5.688 15.301 6.96 16.501 ;
     RECT  24.312 15.395 26.7 15.973 ;
     RECT  34.176 15.443 34.8 16.117 ;
     RECT  8.232 15.491 9.696 15.925 ;
     RECT  2.712 15.493 3.984 15.541 ;
     RECT  16.212 15.589 17.568 16.933 ;
     RECT  37.812 15.731 39.264 16.499 ;
     RECT  36.216 15.877 37.5 16.693 ;
     RECT  40.632 15.877 41.856 16.547 ;
     RECT  8.232 15.925 9.456 17.029 ;
     RECT  24.312 15.973 25.44 17.315 ;
     RECT  25.464 15.973 26.496 16.595 ;
     RECT  2.712 16.019 3.936 19.427 ;
     RECT  35.112 16.019 36.192 16.835 ;
     RECT  21.912 16.067 23.376 16.547 ;
     RECT  46.152 16.115 47.712 16.453 ;
     RECT  34.176 16.117 34.656 16.549 ;
     RECT  46.152 16.453 47.664 17.077 ;
     RECT  39.84 16.499 40.2 17.605 ;
     RECT  5.688 16.501 6.864 16.933 ;
     RECT  43.212 16.501 44.496 16.597 ;
     RECT  44.52 16.501 45.6 18.661 ;
     RECT  21.612 16.547 23.376 17.701 ;
     RECT  40.632 16.547 42.72 16.597 ;
     RECT  25.464 16.595 26.7 17.315 ;
     RECT  31.92 16.595 31.968 17.605 ;
     RECT  48.612 16.595 49.824 19.141 ;
     RECT  41.496 16.597 42.72 16.883 ;
     RECT  43.368 16.597 44.496 16.645 ;
     RECT  36.216 16.693 37.2 16.741 ;
     RECT  27.012 16.835 28.224 20.149 ;
     RECT  35.112 16.835 37.056 16.931 ;
     RECT  41.496 16.883 42.768 17.315 ;
     RECT  35.112 16.931 37.104 17.989 ;
     RECT  17.16 16.979 18.384 17.123 ;
     RECT  43.368 16.979 44.448 17.267 ;
     RECT  8.424 17.029 9.456 17.171 ;
     RECT  14.28 17.077 15.36 17.123 ;
     RECT  46.68 17.077 47.664 17.845 ;
     RECT  14.28 17.123 15.456 17.267 ;
     RECT  8.424 17.171 9.84 17.507 ;
     RECT  14.28 17.267 15.792 17.605 ;
     RECT  43.212 17.267 44.448 18.469 ;
     RECT  24.312 17.315 26.7 17.605 ;
     RECT  8.424 17.507 9.984 18.181 ;
     RECT  19.032 17.509 20.112 18.133 ;
     RECT  4.056 17.603 5.1 19.619 ;
     RECT  14.376 17.605 15.792 18.371 ;
     RECT  24.312 17.605 26.208 18.181 ;
     RECT  30.84 17.605 31.968 17.699 ;
     RECT  30.84 17.699 32.1 19.333 ;
     RECT  21.612 17.701 22.8 17.987 ;
     RECT  42.768 17.939 42.9 19.237 ;
     RECT  35.208 17.989 37.104 18.181 ;
     RECT  8.76 18.181 9.984 18.853 ;
     RECT  24.456 18.181 26.208 18.709 ;
     RECT  35.88 18.181 37.104 19.333 ;
     RECT  19.272 18.275 20.832 19.381 ;
     RECT  14.28 18.371 15.792 18.661 ;
     RECT  43.32 18.469 44.448 18.899 ;
     RECT  40.512 18.515 40.824 19.237 ;
     RECT  14.28 18.661 15.456 18.803 ;
     RECT  25.128 18.709 26.208 18.947 ;
     RECT  14.28 18.803 15.792 18.851 ;
     RECT  14.28 18.851 15.9 19.475 ;
     RECT  23.328 18.899 23.472 20.149 ;
     RECT  43.32 18.899 45.072 19.525 ;
     RECT  24.456 18.947 26.208 20.149 ;
     RECT  8.904 19.043 9.984 19.523 ;
     RECT  46.968 19.043 48.3 19.235 ;
     RECT  40.512 19.237 42 20.147 ;
     RECT  35.88 19.333 37.008 19.907 ;
     RECT  19.272 19.381 20.784 19.909 ;
     RECT  2.712 19.427 4.032 19.619 ;
     RECT  13.608 19.475 15.9 19.621 ;
     RECT  8.904 19.523 10.368 20.053 ;
     RECT  43.656 19.525 45.072 20.291 ;
     RECT  13.608 19.621 14.784 20.003 ;
     RECT  14.808 19.621 15.9 20.003 ;
     RECT  33 19.621 34.176 20.197 ;
     RECT  35.88 19.907 37.104 20.531 ;
     RECT  19.704 19.909 20.784 21.491 ;
     RECT  13.608 20.003 13.656 20.677 ;
     RECT  15.408 20.003 15.9 20.965 ;
     RECT  8.952 20.053 10.368 21.061 ;
     RECT  29.928 20.147 31.344 20.915 ;
     RECT  40.512 20.147 42.288 20.149 ;
     RECT  21.612 20.149 23.088 20.677 ;
     RECT  24.456 20.149 25.68 20.435 ;
     RECT  27.012 20.149 28.032 21.637 ;
     RECT  38.328 20.149 39.84 20.339 ;
     RECT  41.16 20.149 42.288 20.435 ;
     RECT  43.656 20.291 43.8 21.397 ;
     RECT  38.328 20.339 40.08 20.627 ;
     RECT  35.112 20.531 37.104 21.493 ;
     RECT  48.744 20.579 49.824 22.021 ;
     RECT  38.328 20.627 40.2 20.725 ;
     RECT  21.72 20.677 23.088 20.915 ;
     RECT  11.688 20.723 13.104 21.155 ;
     RECT  39.048 20.725 40.2 21.443 ;
     RECT  31.968 20.915 32.1 21.925 ;
     RECT  8.952 21.061 10.176 22.307 ;
     RECT  29.832 21.107 29.928 22.549 ;
     RECT  10.812 21.155 13.104 22.597 ;
     RECT  6.264 21.253 7.488 24.997 ;
     RECT  19.608 21.491 20.784 22.835 ;
     RECT  35.112 21.493 36.096 22.787 ;
     RECT  36.12 21.493 37.104 22.787 ;
     RECT  2.712 21.637 4.176 22.499 ;
     RECT  44.424 21.877 45.456 22.739 ;
     RECT  13.608 21.923 13.656 22.165 ;
     RECT  16.212 21.925 17.232 22.499 ;
     RECT  17.256 21.925 18.384 22.499 ;
     RECT  46.776 21.973 48.192 22.741 ;
     RECT  48.792 22.021 49.824 22.165 ;
     RECT  13.608 22.165 15.12 24.421 ;
     RECT  49.848 22.259 51 31.285 ;
     RECT  8.952 22.307 10.5 23.269 ;
     RECT  18 22.499 18.384 22.597 ;
     RECT  10.812 22.597 12.24 23.845 ;
     RECT  43.608 22.739 45.456 22.741 ;
     RECT  21.768 22.741 23.184 23.557 ;
     RECT  43.608 22.741 44.976 23.987 ;
     RECT  46.776 22.741 47.856 23.509 ;
     RECT  35.112 22.787 37.104 23.557 ;
     RECT  31.968 22.835 32.1 23.125 ;
     RECT  48.792 22.835 49.824 22.931 ;
     RECT  48.612 22.931 49.824 24.421 ;
     RECT  30.792 23.125 32.1 23.363 ;
     RECT  8.952 23.269 10.368 23.317 ;
     RECT  26.352 23.315 26.7 24.277 ;
     RECT  51.432 23.315 52.656 24.613 ;
     RECT  30.744 23.363 32.1 24.421 ;
     RECT  35.688 23.557 37.104 23.699 ;
     RECT  21.768 23.699 22.8 23.891 ;
     RECT  35.592 23.699 37.104 23.939 ;
     RECT  43.608 23.987 43.896 24.901 ;
     RECT  24.648 24.277 25.632 24.469 ;
     RECT  25.656 24.277 26.7 24.469 ;
     RECT  18 24.371 18.384 25.333 ;
     RECT  29.712 24.419 30.72 24.659 ;
     RECT  14.136 24.421 15.12 24.757 ;
     RECT  72.912 24.563 73.08 25.573 ;
     RECT  35.112 24.707 35.496 25.621 ;
     RECT  45.912 24.851 47.424 26.773 ;
     RECT  23.904 24.995 24 26.341 ;
     RECT  10.368 25.139 10.5 26.197 ;
     RECT  24.648 25.139 25.632 25.235 ;
     RECT  25.656 25.139 26.7 25.235 ;
     RECT  33.984 25.139 34.8 26.149 ;
     RECT  27.624 25.187 28.608 25.763 ;
     RECT  16.212 25.333 17.328 25.429 ;
     RECT  17.352 25.333 18.384 25.475 ;
     RECT  13.608 25.475 15.072 26.819 ;
     RECT  17.352 25.475 18.6 26.533 ;
     RECT  35.112 25.621 36.528 28.261 ;
     RECT  11.544 25.667 13.2 26.629 ;
     RECT  39.552 25.715 40.2 26.821 ;
     RECT  48.612 25.715 49.824 27.637 ;
     RECT  40.824 25.717 41.856 25.813 ;
     RECT  41.88 25.717 42.9 26.197 ;
     RECT  27.432 25.763 28.608 26.531 ;
     RECT  40.632 26.147 41.616 26.867 ;
     RECT  32.808 26.149 34.8 26.341 ;
     RECT  19.848 26.291 21.072 27.059 ;
     RECT  30.312 26.341 31.344 26.435 ;
     RECT  32.808 26.341 34.176 26.533 ;
     RECT  21.612 26.389 23.04 26.437 ;
     RECT  30.312 26.435 31.968 26.819 ;
     RECT  21.612 26.437 22.8 26.819 ;
     RECT  27.432 26.531 28.8 26.869 ;
     RECT  32.952 26.533 34.176 26.819 ;
     RECT  11.544 26.629 12.672 27.733 ;
     RECT  8.112 26.725 9.216 28.453 ;
     RECT  9.24 26.725 10.368 27.205 ;
     RECT  46.008 26.773 47.424 28.019 ;
     RECT  21.612 26.819 23.376 26.869 ;
     RECT  30.312 26.819 32.1 26.917 ;
     RECT  32.952 26.819 34.8 27.299 ;
     RECT  37.812 26.821 38.928 27.011 ;
     RECT  38.952 26.821 40.2 26.965 ;
     RECT  44.52 26.821 45.6 27.587 ;
     RECT  40.512 26.867 41.616 29.605 ;
     RECT  22.248 26.869 23.376 27.395 ;
     RECT  27.624 26.869 28.8 27.587 ;
     RECT  41.88 26.915 42.9 27.877 ;
     RECT  30.648 26.917 32.1 27.683 ;
     RECT  37.812 27.011 39.312 28.453 ;
     RECT  9.24 27.205 10.272 28.309 ;
     RECT  32.412 27.299 34.8 27.349 ;
     RECT  32.412 27.349 33.696 28.789 ;
     RECT  33.72 27.349 34.8 29.123 ;
     RECT  5.544 27.395 6.864 28.019 ;
     RECT  22.248 27.395 24 28.453 ;
     RECT  43.608 27.587 45.6 28.837 ;
     RECT  48.612 27.637 49.584 28.597 ;
     RECT  30.552 27.683 32.1 28.163 ;
     RECT  11.544 27.733 12.528 29.509 ;
     RECT  5.544 28.019 6.912 29.651 ;
     RECT  45.912 28.019 47.424 28.547 ;
     RECT  18.912 28.163 19.416 29.317 ;
     RECT  31.968 28.163 32.1 28.405 ;
     RECT  35.112 28.261 36.48 28.405 ;
     RECT  35.352 28.405 36.48 28.547 ;
     RECT  24.648 28.453 25.776 29.317 ;
     RECT  38.04 28.453 39.312 28.981 ;
     RECT  35.352 28.547 36.576 29.795 ;
     RECT  45.912 28.547 48.3 28.981 ;
     RECT  41.88 28.739 42.9 30.229 ;
     RECT  32.52 28.789 33.696 28.931 ;
     RECT  44.472 28.837 45.6 30.037 ;
     RECT  32.412 28.931 33.696 29.123 ;
     RECT  38.04 28.981 39.12 29.653 ;
     RECT  46.056 28.981 48.3 29.509 ;
     RECT  32.412 29.123 34.8 29.557 ;
     RECT  22.968 29.219 24 29.795 ;
     RECT  24.648 29.317 25.632 30.469 ;
     RECT  27.336 29.509 28.8 29.653 ;
     RECT  46.056 29.509 48.192 29.605 ;
     RECT  32.412 29.557 34.656 30.037 ;
     RECT  46.776 29.605 48.192 29.893 ;
     RECT  5.412 29.651 6.912 29.747 ;
     RECT  27.672 29.653 28.8 30.469 ;
     RECT  5.412 29.747 7.248 30.757 ;
     RECT  22.824 29.795 24 30.179 ;
     RECT  35.208 29.795 36.576 29.843 ;
     RECT  48.612 29.795 49.824 36.661 ;
     RECT  35.112 29.843 36.576 30.949 ;
     RECT  38.04 29.891 39.072 29.987 ;
     RECT  46.92 29.893 48.192 30.851 ;
     RECT  37.812 29.987 39.072 31.285 ;
     RECT  33.336 30.037 34.656 30.323 ;
     RECT  29.712 30.133 31.152 30.373 ;
     RECT  22.2 30.179 24 31.379 ;
     RECT  33.336 30.323 34.8 31.379 ;
     RECT  27.672 30.469 28.704 30.611 ;
     RECT  12.168 30.611 13.2 30.755 ;
     RECT  27.672 30.611 28.752 31.955 ;
     RECT  19.752 30.709 21.072 31.187 ;
     RECT  11.544 30.755 13.2 31.621 ;
     RECT  5.412 30.757 6.864 31.525 ;
     RECT  25.656 30.851 26.7 31.379 ;
     RECT  40.512 30.851 41.616 34.789 ;
     RECT  45.912 30.851 48.192 30.949 ;
     RECT  35.112 30.949 36.528 31.573 ;
     RECT  45.912 30.949 47.184 31.955 ;
     RECT  47.208 30.949 48.192 31.669 ;
     RECT  19.32 31.187 21.072 31.237 ;
     RECT  14.04 31.237 15.072 32.051 ;
     RECT  19.32 31.237 20.448 31.475 ;
     RECT  37.812 31.285 38.976 32.723 ;
     RECT  8.856 31.331 10.368 31.907 ;
     RECT  21.72 31.379 24 31.429 ;
     RECT  25.224 31.379 26.7 32.197 ;
     RECT  21.72 31.429 22.8 31.763 ;
     RECT  22.824 31.429 24 31.763 ;
     RECT  5.736 31.525 6.864 32.437 ;
     RECT  35.112 31.573 36.48 32.197 ;
     RECT  11.544 31.621 12.768 32.101 ;
     RECT  3.432 31.669 4.512 32.579 ;
     RECT  21.72 31.763 24 32.147 ;
     RECT  43.608 31.813 45.024 32.629 ;
     RECT  45.912 31.955 46.008 32.197 ;
     RECT  13.512 32.051 15.072 32.245 ;
     RECT  11.592 32.101 12.768 32.771 ;
     RECT  21.612 32.147 24 33.013 ;
     RECT  25.224 32.197 26.592 32.243 ;
     RECT  13.512 32.245 14.784 33.973 ;
     RECT  49.848 32.291 51 34.549 ;
     RECT  5.736 32.437 6.816 33.541 ;
     RECT  31.968 32.531 32.1 33.013 ;
     RECT  3.288 32.579 4.512 32.773 ;
     RECT  52.44 32.579 53.472 32.723 ;
     RECT  43.656 32.629 45.024 33.107 ;
     RECT  37.812 32.723 39.072 34.405 ;
     RECT  52.2 32.723 53.472 34.213 ;
     RECT  3.288 32.773 4.272 34.883 ;
     RECT  18.912 33.013 19.968 34.163 ;
     RECT  21.612 33.013 22.848 34.789 ;
     RECT  22.872 33.013 24 34.117 ;
     RECT  29.712 33.013 31.008 33.301 ;
     RECT  31.032 33.013 32.1 36.707 ;
     RECT  11.544 33.059 11.592 33.395 ;
     RECT  35.112 33.107 36.48 34.115 ;
     RECT  73.224 33.107 73.272 34.501 ;
     RECT  29.832 33.301 31.008 33.589 ;
     RECT  11.4 33.395 11.592 34.453 ;
     RECT  9.48 33.541 10.5 37.429 ;
     RECT  46.008 33.589 47.472 34.115 ;
     RECT  14.28 34.019 15.408 35.171 ;
     RECT  35.112 34.115 36.576 35.845 ;
     RECT  45.912 34.115 47.472 34.741 ;
     RECT  52.2 34.213 53.28 34.787 ;
     RECT  37.992 34.405 39.072 34.453 ;
     RECT  11.688 34.453 13.2 34.979 ;
     RECT  22.872 34.499 24 34.835 ;
     RECT  49.848 34.549 50.88 36.707 ;
     RECT  29.928 34.691 31.008 35.845 ;
     RECT  45.912 34.741 47.136 35.411 ;
     RECT  27.528 34.787 28.704 36.421 ;
     RECT  41.88 34.787 42.9 40.163 ;
     RECT  52.2 34.787 53.568 36.083 ;
     RECT  21.816 34.789 22.848 34.835 ;
     RECT  5.412 34.835 6.432 35.315 ;
     RECT  21.816 34.835 22.296 35.509 ;
     RECT  24.456 34.837 25.68 36.277 ;
     RECT  25.704 34.837 26.7 36.755 ;
     RECT  3.288 34.883 4.992 35.077 ;
     RECT  10.92 34.979 13.2 35.413 ;
     RECT  3.96 35.077 4.992 36.515 ;
     RECT  14.28 35.171 15.504 35.219 ;
     RECT  14.28 35.219 15.9 36.373 ;
     RECT  45.912 35.411 47.184 36.275 ;
     RECT  10.92 35.413 12.816 35.939 ;
     RECT  44.088 35.413 45.264 36.275 ;
     RECT  38.184 35.507 39.168 35.939 ;
     RECT  29.976 35.845 31.008 36.661 ;
     RECT  35.112 35.845 36.336 36.517 ;
     RECT  10.812 35.939 12.816 36.037 ;
     RECT  38.184 35.939 39.312 36.997 ;
     RECT  40.728 36.035 41.856 37.189 ;
     RECT  10.812 36.037 12.624 36.421 ;
     RECT  51.912 36.083 53.568 36.277 ;
     RECT  44.088 36.275 45.6 36.949 ;
     RECT  45.912 36.275 47.376 36.323 ;
     RECT  24.504 36.277 25.68 36.469 ;
     RECT  51.912 36.277 52.992 37.331 ;
     RECT  45.912 36.323 47.664 36.757 ;
     RECT  10.812 36.421 11.952 36.901 ;
     RECT  3.912 36.515 4.992 38.389 ;
     RECT  24.504 36.611 25.68 36.755 ;
     RECT  48.612 36.661 49.584 37.621 ;
     RECT  30.888 36.707 32.1 37.429 ;
     RECT  35.112 36.707 36.336 36.899 ;
     RECT  49.608 36.707 50.88 36.851 ;
     RECT  46.056 36.757 47.664 36.853 ;
     RECT  49.608 36.851 51 38.197 ;
     RECT  22.584 36.853 23.904 38.149 ;
     RECT  46.104 36.853 47.664 37.237 ;
     RECT  35.112 36.899 36.576 38.149 ;
     RECT  44.184 36.949 45.6 37.379 ;
     RECT  2.904 36.995 3.888 38.389 ;
     RECT  38.184 36.997 39.168 37.573 ;
     RECT  11.208 37.091 12.192 38.725 ;
     RECT  46.152 37.237 47.664 38.149 ;
     RECT  43.212 37.379 43.32 38.725 ;
     RECT  30.888 37.429 31.968 39.397 ;
     RECT  73.464 37.667 73.512 37.763 ;
     RECT  73.224 37.763 73.512 38.773 ;
     RECT  24.456 37.907 24.504 38.533 ;
     RECT  22.68 38.149 23.904 38.245 ;
     RECT  35.112 38.149 36.432 38.389 ;
     RECT  46.152 38.149 47.328 38.197 ;
     RECT  49.656 38.197 51 38.435 ;
     RECT  46.008 38.435 47.328 38.867 ;
     RECT  50.88 38.435 51 38.725 ;
     RECT  24.456 38.533 25.728 39.637 ;
     RECT  40.68 38.771 41.856 40.163 ;
     RECT  17.256 38.819 18.288 41.029 ;
     RECT  3.912 38.915 5.1 39.923 ;
     RECT  19.992 39.109 21.072 39.253 ;
     RECT  52.488 39.205 53.52 40.259 ;
     RECT  11.448 39.251 12.528 39.635 ;
     RECT  38.136 39.299 39.312 41.845 ;
     RECT  11.448 39.635 12.816 40.355 ;
     RECT  18.912 39.635 19.968 40.981 ;
     RECT  24.456 39.779 25.488 40.499 ;
     RECT  14.376 39.877 15.9 40.595 ;
     RECT  3.24 39.923 5.1 40.309 ;
     RECT  25.512 39.923 26.7 40.499 ;
     RECT  21.612 40.019 22.752 40.981 ;
     RECT  40.68 40.163 42.9 40.405 ;
     RECT  51.864 40.259 53.52 40.405 ;
     RECT  3.24 40.309 4.56 40.547 ;
     RECT  40.68 40.405 42.48 41.509 ;
     RECT  51.864 40.405 53.088 41.509 ;
     RECT  8.376 40.451 9.456 41.941 ;
     RECT  24.456 40.499 24.504 41.221 ;
     RECT  26.208 40.499 26.7 40.885 ;
     RECT  50.88 40.499 51 41.029 ;
     RECT  45.912 40.693 46.944 42.469 ;
     RECT  14.088 40.883 14.28 42.133 ;
     RECT  44.52 40.933 45.6 42.179 ;
     RECT  30.888 40.979 31.968 44.581 ;
     RECT  49.704 41.029 51 41.651 ;
     RECT  4.56 41.075 4.992 42.133 ;
     RECT  43.212 41.171 44.496 42.179 ;
     RECT  17.256 41.267 18.288 42.709 ;
     RECT  29.712 41.363 30.72 43.765 ;
     RECT  41.064 41.509 42.48 41.987 ;
     RECT  51.864 41.509 52.992 42.805 ;
     RECT  18.912 41.651 19.968 41.795 ;
     RECT  33.624 41.653 34.8 42.085 ;
     RECT  18.912 41.795 20.208 42.563 ;
     RECT  42.288 41.987 42.48 42.709 ;
     RECT  8.232 42.035 9.216 42.851 ;
     RECT  38.136 42.035 39.216 42.899 ;
     RECT  2.712 42.133 3.792 42.277 ;
     RECT  3.816 42.133 4.992 43.189 ;
     RECT  14.808 42.133 15.9 42.323 ;
     RECT  32.412 42.179 33.6 42.227 ;
     RECT  43.212 42.179 45.6 42.181 ;
     RECT  43.212 42.181 45.504 42.565 ;
     RECT  73.032 42.419 73.176 43.717 ;
     RECT  20.832 42.563 21.072 43.861 ;
     RECT  43.212 42.565 45.072 43.285 ;
     RECT  17.304 42.709 18.288 43.141 ;
     RECT  22.584 42.803 24 45.541 ;
     RECT  8.112 42.851 9.216 43.139 ;
     RECT  38.088 42.899 39.216 44.675 ;
     RECT  8.112 43.139 9.264 45.253 ;
     RECT  24.312 43.331 25.344 44.341 ;
     RECT  49.416 43.477 50.832 44.677 ;
     RECT  27.012 43.571 28.128 44.387 ;
     RECT  17.304 43.619 18.288 43.859 ;
     RECT  46.056 43.811 47.568 45.731 ;
     RECT  40.872 43.813 42.288 44.531 ;
     RECT  17.256 43.859 18.288 43.955 ;
     RECT  2.712 43.955 3.792 45.011 ;
     RECT  17.064 43.955 18.288 44.051 ;
     RECT  16.584 44.051 18.288 44.483 ;
     RECT  44.472 44.099 45.6 45.349 ;
     RECT  32.412 44.195 32.52 44.437 ;
     RECT  43.212 44.195 44.448 46.163 ;
     RECT  10.812 44.197 11.952 46.403 ;
     RECT  11.976 44.197 13.2 44.293 ;
     RECT  27.012 44.387 28.32 45.059 ;
     RECT  11.976 44.435 13.2 46.403 ;
     RECT  32.412 44.437 33.792 45.155 ;
     RECT  5.64 44.483 5.88 45.493 ;
     RECT  16.212 44.483 18.288 45.205 ;
     RECT  42.144 44.531 42.288 45.829 ;
     RECT  33.816 44.675 34.8 45.155 ;
     RECT  38.088 44.675 39.312 45.733 ;
     RECT  49.416 44.677 50.736 46.885 ;
     RECT  51.312 44.915 52.896 45.635 ;
     RECT  2.712 45.011 3.936 46.357 ;
     RECT  27.012 45.059 28.752 45.731 ;
     RECT  34.704 45.155 34.8 46.645 ;
     RECT  16.212 45.205 18.096 45.781 ;
     RECT  44.472 45.349 45.504 45.973 ;
     RECT  14.856 45.443 15.9 46.789 ;
     RECT  30.888 45.491 31.92 46.259 ;
     RECT  19.368 45.493 20.832 45.923 ;
     RECT  22.44 45.635 23.52 46.115 ;
     RECT  51.312 45.635 53.7 46.357 ;
     RECT  27.012 45.731 29.28 46.117 ;
     RECT  38.184 45.733 39.312 46.019 ;
     RECT  16.212 45.781 17.232 46.211 ;
     RECT  25.416 45.827 26.7 46.787 ;
     RECT  19.368 45.923 21.072 46.021 ;
     RECT  8.904 45.971 10.272 46.595 ;
     RECT  38.088 46.019 39.312 46.115 ;
     RECT  19.56 46.021 21.072 46.883 ;
     RECT  22.344 46.115 23.52 46.883 ;
     RECT  37.992 46.115 39.312 47.123 ;
     RECT  27.432 46.117 29.28 46.981 ;
     RECT  43.212 46.163 44.976 46.213 ;
     RECT  16.212 46.211 17.328 47.171 ;
     RECT  43.464 46.213 44.976 46.547 ;
     RECT  30.888 46.259 31.968 47.365 ;
     RECT  51.312 46.357 52.704 47.173 ;
     RECT  52.728 46.357 53.7 46.645 ;
     RECT  10.812 46.403 13.2 47.077 ;
     RECT  42.144 46.547 42.768 46.885 ;
     RECT  10.128 46.595 10.272 47.221 ;
     RECT  25.224 46.787 26.7 47.173 ;
     RECT  34.704 46.787 34.8 47.749 ;
     RECT  19.56 46.883 21.168 47.173 ;
     RECT  22.344 46.883 24 47.317 ;
     RECT  40.512 46.885 41.568 47.269 ;
     RECT  41.592 46.885 42.768 47.363 ;
     RECT  73.128 46.979 73.272 48.085 ;
     RECT  27.432 46.981 29.088 47.125 ;
     RECT  11.208 47.077 13.2 47.461 ;
     RECT  37.812 47.123 39.312 49.237 ;
     RECT  27.432 47.125 28.464 47.939 ;
     RECT  20.136 47.173 21.168 47.219 ;
     RECT  25.224 47.173 26.208 47.893 ;
     RECT  20.136 47.219 21.3 48.181 ;
     RECT  49.128 47.315 50.16 47.939 ;
     RECT  22.536 47.317 24 49.091 ;
     RECT  32.412 47.363 32.616 47.749 ;
     RECT  41.256 47.363 42.768 48.133 ;
     RECT  30.888 47.365 31.92 47.603 ;
     RECT  11.208 47.461 13.008 47.605 ;
     RECT  30.792 47.603 31.92 48.419 ;
     RECT  11.496 47.605 13.008 47.845 ;
     RECT  32.412 47.749 33.888 49.381 ;
     RECT  2.712 47.939 3.936 50.005 ;
     RECT  18.912 47.939 20.016 49.861 ;
     RECT  27.012 47.939 28.464 49.667 ;
     RECT  48.612 47.939 50.16 49.381 ;
     RECT  71.256 47.939 72.384 49.237 ;
     RECT  41.256 48.133 42.336 48.757 ;
     RECT  20.328 48.181 21.3 48.997 ;
     RECT  14.808 48.227 15.9 49.477 ;
     RECT  29.712 48.227 30.72 50.005 ;
     RECT  11.4 48.371 12.384 48.947 ;
     RECT  30.744 48.419 31.92 49.091 ;
     RECT  25.512 48.467 26.592 49.235 ;
     RECT  18 48.515 18.6 48.997 ;
     RECT  13.512 48.899 14.688 53.989 ;
     RECT  13.056 48.947 13.2 50.101 ;
     RECT  35.448 48.947 36.576 49.667 ;
     RECT  17.112 48.997 18.6 49.139 ;
     RECT  30.744 49.091 32.1 50.677 ;
     RECT  18.336 49.139 18.6 49.477 ;
     RECT  25.176 49.235 26.592 50.435 ;
     RECT  37.944 49.237 39.312 49.285 ;
     RECT  71.256 49.237 72.336 49.333 ;
     RECT  38.328 49.285 39.312 49.477 ;
     RECT  71.352 49.333 72.336 49.813 ;
     RECT  48.612 49.381 50.112 49.477 ;
     RECT  72.912 49.427 73.128 50.389 ;
     RECT  48.888 49.477 50.112 50.099 ;
     RECT  32.412 49.523 33.888 51.349 ;
     RECT  35.112 49.667 36.576 50.005 ;
     RECT  35.112 50.005 36.432 50.771 ;
     RECT  14.856 50.051 15.9 51.829 ;
     RECT  48.888 50.099 50.16 50.291 ;
     RECT  48.888 50.291 49.032 50.965 ;
     RECT  25.176 50.435 26.7 50.725 ;
     RECT  11.112 50.579 11.16 51.685 ;
     RECT  30.744 50.677 31.968 52.309 ;
     RECT  25.656 50.725 26.7 52.211 ;
     RECT  35.112 50.771 36.672 51.445 ;
     RECT  51.312 50.819 52.368 53.173 ;
     RECT  48.888 51.155 49.032 51.683 ;
     RECT  43.212 51.205 44.448 52.019 ;
     RECT  44.472 51.205 45.504 51.395 ;
     RECT  32.412 51.349 33.648 51.683 ;
     RECT  13.056 51.395 13.2 52.741 ;
     RECT  33.72 51.395 34.8 52.835 ;
     RECT  44.472 51.395 45.6 52.019 ;
     RECT  35.352 51.445 36.672 52.019 ;
     RECT  32.412 51.683 33.696 52.835 ;
     RECT  48.744 51.683 49.032 52.067 ;
     RECT  35.208 52.019 36.672 52.213 ;
     RECT  45.216 52.019 45.6 52.981 ;
     RECT  48.612 52.067 49.032 52.165 ;
     RECT  48.612 52.165 50.4 52.741 ;
     RECT  18.912 52.211 19.968 53.941 ;
     RECT  35.208 52.213 36.576 52.789 ;
     RECT  30.936 52.309 31.968 52.549 ;
     RECT  27.912 52.691 29.4 54.323 ;
     RECT  11.544 52.741 13.2 52.789 ;
     RECT  48.612 52.741 49.824 53.555 ;
     RECT  18.336 52.787 18.6 53.029 ;
     RECT  11.688 52.789 13.2 55.669 ;
     RECT  35.208 52.789 36.336 53.317 ;
     RECT  34.704 52.835 34.8 53.317 ;
     RECT  17.16 53.029 18.6 53.797 ;
     RECT  41.784 53.269 42.9 54.085 ;
     RECT  35.208 53.795 36.336 54.611 ;
     RECT  17.16 53.797 18.48 54.757 ;
     RECT  25.08 53.797 26.592 54.851 ;
     RECT  30.744 53.987 32.1 55.429 ;
     RECT  13.704 53.989 14.688 54.035 ;
     RECT  13.704 54.035 15.36 54.085 ;
     RECT  45.216 54.083 45.6 55.525 ;
     RECT  14.28 54.085 15.36 54.995 ;
     RECT  27.144 54.323 29.4 54.613 ;
     RECT  27.144 54.613 28.464 54.947 ;
     RECT  41.784 54.659 42.9 59.221 ;
     RECT  18.912 54.707 19.968 58.069 ;
     RECT  17.208 54.757 18.48 54.899 ;
     RECT  17.208 54.899 18.6 54.947 ;
     RECT  17.16 54.947 18.6 55.283 ;
     RECT  27.012 54.947 28.464 55.957 ;
     RECT  14.28 54.995 15.744 55.141 ;
     RECT  38.328 55.139 39.312 55.715 ;
     RECT  14.376 55.141 15.744 55.715 ;
     RECT  16.344 55.283 18.6 56.005 ;
     RECT  50.496 55.427 50.688 56.821 ;
     RECT  46.824 55.525 48.3 55.763 ;
     RECT  14.376 55.715 15.9 57.397 ;
     RECT  38.136 55.715 39.312 56.531 ;
     RECT  32.412 55.813 33.6 56.821 ;
     RECT  33.624 55.813 34.8 56.917 ;
     RECT  73.128 55.955 73.224 57.445 ;
     RECT  27.48 55.957 28.464 56.483 ;
     RECT  16.344 56.005 18.192 56.389 ;
     RECT  8.112 56.387 8.568 56.677 ;
     RECT  16.44 56.389 17.856 57.299 ;
     RECT  30.744 56.483 32.1 59.461 ;
     RECT  27.012 56.531 27.384 57.493 ;
     RECT  37.812 56.531 39.312 59.317 ;
     RECT  8.112 56.677 9.12 57.347 ;
     RECT  9.144 56.677 10.368 57.347 ;
     RECT  35.208 56.773 36.384 57.587 ;
     RECT  32.412 56.821 33.456 57.301 ;
     RECT  49.56 56.821 50.688 57.445 ;
     RECT  11.64 56.867 12.912 59.507 ;
     RECT  51.312 56.915 52.992 57.877 ;
     RECT  33.768 56.917 34.8 58.645 ;
     RECT  9.696 57.347 10.368 57.493 ;
     RECT  40.512 57.395 41.568 59.221 ;
     RECT  45.024 57.395 45.6 58.117 ;
     RECT  24.312 57.445 25.728 58.117 ;
     RECT  29.088 57.587 29.4 58.645 ;
     RECT  35.208 57.587 36.48 60.901 ;
     RECT  51.312 57.877 52.608 58.403 ;
     RECT  19.128 58.115 20.352 58.403 ;
     RECT  24.744 58.117 25.728 58.691 ;
     RECT  43.212 58.117 44.448 58.645 ;
     RECT  44.472 58.117 45.6 59.123 ;
     RECT  51.312 58.403 52.704 58.597 ;
     RECT  6.648 58.547 7.8 60.371 ;
     RECT  51.432 58.597 52.704 59.459 ;
     RECT  43.368 58.645 44.448 59.123 ;
     RECT  27.912 59.027 29.4 60.853 ;
     RECT  33.624 59.027 34.8 59.363 ;
     RECT  8.112 59.077 9.408 59.603 ;
     RECT  43.368 59.123 45.6 59.221 ;
     RECT  18.48 59.219 18.6 60.421 ;
     RECT  41.784 59.221 42.768 59.987 ;
     RECT  43.368 59.221 44.352 59.795 ;
     RECT  44.376 59.221 45.6 61.237 ;
     RECT  46.824 59.221 48.192 59.365 ;
     RECT  22.344 59.315 23.808 61.237 ;
     RECT  38.184 59.317 39.312 60.851 ;
     RECT  33.48 59.363 34.8 63.829 ;
     RECT  47.064 59.365 48.192 59.555 ;
     RECT  13.656 59.459 14.88 59.555 ;
     RECT  11.64 59.507 13.056 60.373 ;
     RECT  13.608 59.555 14.88 61.957 ;
     RECT  46.824 59.555 48.192 59.603 ;
     RECT  8.112 59.603 9.696 60.179 ;
     RECT  46.824 59.603 48.3 60.515 ;
     RECT  43.212 59.795 44.352 60.565 ;
     RECT  49.56 59.891 51 60.371 ;
     RECT  41.784 59.987 42.9 60.949 ;
     RECT  8.112 60.179 8.232 60.661 ;
     RECT  6.504 60.371 7.8 61.381 ;
     RECT  11.736 60.373 13.056 61.189 ;
     RECT  46.728 60.515 48.3 60.565 ;
     RECT  36.504 60.563 37.5 62.629 ;
     RECT  43.212 60.565 44.208 62.435 ;
     RECT  46.728 60.565 48.144 61.619 ;
     RECT  29.712 60.851 30.72 61.907 ;
     RECT  37.812 60.851 39.312 62.005 ;
     RECT  28.392 60.853 29.4 61.525 ;
     RECT  54.12 60.995 55.104 62.005 ;
     RECT  10.32 61.139 10.368 62.005 ;
     RECT  30.744 61.139 31.824 61.907 ;
     RECT  19.128 61.141 20.304 61.381 ;
     RECT  20.328 61.141 21.3 62.291 ;
     RECT  11.736 61.189 12.96 62.053 ;
     RECT  8.112 61.235 8.232 62.005 ;
     RECT  22.344 61.237 23.616 62.053 ;
     RECT  24.552 61.237 25.92 61.619 ;
     RECT  19.176 61.381 20.304 61.669 ;
     RECT  2.712 61.619 4.512 62.677 ;
     RECT  24.408 61.619 25.92 62.195 ;
     RECT  46.728 61.619 48.3 62.677 ;
     RECT  29.712 61.907 31.824 62.819 ;
     RECT  13.608 61.957 14.832 62.053 ;
     RECT  16.212 62.003 16.344 63.205 ;
     RECT  8.112 62.005 9.12 64.357 ;
     RECT  9.144 62.005 10.368 63.299 ;
     RECT  38.088 62.005 39.312 62.677 ;
     RECT  11.736 62.053 12.864 63.349 ;
     RECT  13.656 62.053 14.832 63.875 ;
     RECT  22.728 62.195 23.808 63.253 ;
     RECT  24.408 62.195 26.7 62.677 ;
     RECT  29.088 62.195 29.184 63.253 ;
     RECT  32.412 62.195 33.408 63.251 ;
     RECT  20.04 62.291 21.3 63.251 ;
     RECT  43.212 62.435 43.32 62.581 ;
     RECT  2.712 62.677 3.84 63.781 ;
     RECT  24.936 62.677 26.7 62.965 ;
     RECT  46.776 62.677 48.3 62.725 ;
     RECT  46.776 62.725 47.904 62.819 ;
     RECT  29.712 62.819 30.312 63.301 ;
     RECT  31.92 62.819 31.968 63.107 ;
     RECT  46.008 62.819 47.904 63.781 ;
     RECT  25.464 62.965 26.7 63.781 ;
     RECT  38.088 63.011 39.312 63.299 ;
     RECT  31.92 63.107 32.1 64.117 ;
     RECT  36.408 63.107 37.5 64.213 ;
     RECT  19.224 63.251 19.416 64.357 ;
     RECT  32.412 63.251 33.456 64.979 ;
     RECT  9.144 63.299 10.5 64.547 ;
     RECT  37.812 63.299 39.312 65.317 ;
     RECT  11.88 63.349 12.864 63.589 ;
     RECT  6.504 63.395 7.68 65.509 ;
     RECT  35.208 63.491 36.384 64.643 ;
     RECT  41.784 63.635 42.768 65.749 ;
     RECT  25.512 63.781 26.7 64.069 ;
     RECT  46.008 63.781 47.376 64.165 ;
     RECT  49.704 63.781 51 64.117 ;
     RECT  33.624 63.829 34.8 64.403 ;
     RECT  13.656 63.875 15.168 64.979 ;
     RECT  25.56 64.069 26.7 66.515 ;
     RECT  49.896 64.117 51 64.357 ;
     RECT  46.008 64.165 47.28 64.789 ;
     RECT  27.528 64.357 28.896 66.899 ;
     RECT  30.312 64.357 31.584 64.931 ;
     RECT  33.576 64.403 34.8 66.179 ;
     RECT  47.304 64.451 48.3 66.133 ;
     RECT  73.224 64.451 73.464 65.557 ;
     RECT  8.232 64.547 10.5 64.741 ;
     RECT  35.208 64.643 36.432 66.563 ;
     RECT  8.232 64.741 9.648 65.509 ;
     RECT  30.312 64.931 31.872 65.699 ;
     RECT  45.024 64.931 45.6 65.509 ;
     RECT  32.412 64.979 33.552 66.179 ;
     RECT  11.304 65.027 12.528 65.555 ;
     RECT  16.392 65.221 17.664 66.085 ;
     RECT  49.704 65.267 51 66.515 ;
     RECT  37.992 65.317 39.312 65.557 ;
     RECT  8.232 65.509 9.6 66.227 ;
     RECT  43.212 65.509 44.448 67.571 ;
     RECT  44.472 65.509 45.6 67.571 ;
     RECT  11.304 65.555 13.056 67.045 ;
     RECT  38.952 65.603 40.08 66.515 ;
     RECT  3.288 65.651 4.704 66.227 ;
     RECT  30.312 65.699 32.1 66.085 ;
     RECT  48.612 65.699 49.68 66.515 ;
     RECT  19.416 65.747 19.752 65.795 ;
     RECT  19.32 65.795 19.752 66.085 ;
     RECT  36.456 65.939 37.5 66.563 ;
     RECT  16.392 66.085 17.616 66.325 ;
     RECT  19.32 66.085 20.592 66.179 ;
     RECT  31.08 66.085 32.1 66.901 ;
     RECT  18.912 66.179 20.592 66.563 ;
     RECT  32.412 66.179 32.856 67.189 ;
     RECT  2.712 66.227 4.704 67.141 ;
     RECT  8.112 66.227 9.6 66.709 ;
     RECT  41.784 66.227 42.768 71.221 ;
     RECT  25.272 66.515 26.7 68.149 ;
     RECT  38.808 66.515 40.08 67.429 ;
     RECT  48.612 66.515 48.744 67.861 ;
     RECT  50.88 66.515 51 67.717 ;
     RECT  18.912 66.563 21.3 67.621 ;
     RECT  35.208 66.563 37.5 66.613 ;
     RECT  13.656 66.613 15.168 66.851 ;
     RECT  35.208 66.613 36.192 67.331 ;
     RECT  36.216 66.613 37.5 67.331 ;
     RECT  51.312 66.613 52.368 68.339 ;
     RECT  8.112 66.709 9.12 67.571 ;
     RECT  9.144 66.755 10.224 67.571 ;
     RECT  13.656 66.851 15.264 67.331 ;
     RECT  29.712 66.851 31.056 68.627 ;
     RECT  11.304 67.045 12.528 67.333 ;
     RECT  2.712 67.141 4.272 67.717 ;
     RECT  16.212 67.187 17.664 69.253 ;
     RECT  13.656 67.331 15.504 67.333 ;
     RECT  35.208 67.331 37.5 68.147 ;
     RECT  11.4 67.333 12.528 67.859 ;
     RECT  13.992 67.333 15.504 68.387 ;
     RECT  38.808 67.429 40.032 67.715 ;
     RECT  10.032 67.571 10.224 67.861 ;
     RECT  43.212 67.571 43.512 68.773 ;
     RECT  19.512 67.621 21.3 67.669 ;
     RECT  19.512 67.669 20.736 67.765 ;
     RECT  38.232 67.715 40.032 67.765 ;
     RECT  2.712 67.717 3.696 68.869 ;
     RECT  19.56 67.765 20.736 69.493 ;
     RECT  38.232 67.765 39.312 68.869 ;
     RECT  21.72 67.811 22.704 68.773 ;
     RECT  11.4 67.859 13.056 68.965 ;
     RECT  40.512 67.859 41.76 69.061 ;
     RECT  71.208 67.955 72.336 68.917 ;
     RECT  35.112 68.147 37.5 68.485 ;
     RECT  25.272 68.149 26.352 69.061 ;
     RECT  33.672 68.149 34.8 69.253 ;
     RECT  32.412 68.195 33.648 69.829 ;
     RECT  31.08 68.243 32.1 68.627 ;
     RECT  51.312 68.339 52.848 69.493 ;
     RECT  49.656 68.341 50.88 68.435 ;
     RECT  13.656 68.387 15.504 68.917 ;
     RECT  49.656 68.435 51 69.251 ;
     RECT  72.912 68.483 73.176 69.493 ;
     RECT  35.112 68.485 36.528 68.725 ;
     RECT  29.712 68.627 32.1 69.349 ;
     RECT  35.112 68.725 36.432 70.835 ;
     RECT  46.056 68.869 47.472 69.013 ;
     RECT  13.656 68.917 15.408 69.829 ;
     RECT  71.256 68.917 72.336 69.253 ;
     RECT  11.496 68.965 13.056 69.251 ;
     RECT  40.776 69.061 41.76 69.733 ;
     RECT  48.612 69.203 49.584 71.461 ;
     RECT  10.812 69.251 13.056 69.349 ;
     RECT  49.608 69.251 51 69.493 ;
     RECT  71.256 69.253 72.288 69.493 ;
     RECT  5.544 69.299 5.688 69.829 ;
     RECT  10.812 69.349 12.192 70.835 ;
     RECT  29.712 69.349 30.864 70.261 ;
     RECT  30.888 69.349 32.1 69.493 ;
     RECT  37.812 69.443 38.88 69.491 ;
     RECT  38.904 69.443 40.032 69.491 ;
     RECT  28.152 69.493 29.4 70.739 ;
     RECT  30.888 69.493 31.872 70.645 ;
     RECT  49.608 69.493 50.88 70.645 ;
     RECT  51.312 69.493 52.32 70.405 ;
     RECT  73.128 69.493 73.176 69.829 ;
     RECT  46.2 69.539 47.472 70.549 ;
     RECT  25.272 69.635 26.7 70.787 ;
     RECT  17.448 69.731 18.6 72.229 ;
     RECT  5.544 69.829 6.672 70.163 ;
     RECT  14.232 69.829 15.408 70.597 ;
     RECT  43.512 69.925 44.544 70.645 ;
     RECT  44.568 69.925 45.6 70.835 ;
     RECT  2.712 70.019 4.224 71.315 ;
     RECT  5.412 70.163 6.672 71.365 ;
     RECT  33.144 70.259 34.416 70.787 ;
     RECT  29.712 70.261 30.816 70.549 ;
     RECT  29.712 70.549 30.768 71.509 ;
     RECT  46.2 70.549 47.376 70.645 ;
     RECT  8.52 70.597 9.936 70.885 ;
     RECT  49.608 70.645 50.832 72.131 ;
     RECT  36.456 70.739 37.5 70.835 ;
     RECT  26.256 70.787 26.7 71.365 ;
     RECT  32.412 70.787 34.416 71.221 ;
     RECT  35.112 70.835 35.352 71.221 ;
     RECT  44.136 70.835 45.6 71.461 ;
     RECT  8.616 70.885 9.936 71.605 ;
     RECT  19.656 71.075 20.736 72.419 ;
     RECT  40.032 71.075 40.2 72.037 ;
     RECT  13.704 71.123 15.504 72.229 ;
     RECT  32.412 71.221 33.456 71.891 ;
     RECT  21.864 71.315 23.28 71.843 ;
     RECT  5.412 71.365 6.384 72.275 ;
     RECT  44.136 71.461 45.36 72.179 ;
     RECT  21.864 71.843 22.056 73.333 ;
     RECT  51.864 71.843 52.848 72.949 ;
     RECT  8.28 71.891 9.312 74.773 ;
     RECT  32.412 71.891 34.416 72.757 ;
     RECT  49.608 72.131 51 72.419 ;
     RECT  13.704 72.229 15.072 72.419 ;
     RECT  17.448 72.229 18.48 73.429 ;
     RECT  5.412 72.275 6.624 72.805 ;
     RECT  13.608 72.419 15.072 72.659 ;
     RECT  19.656 72.419 20.784 72.901 ;
     RECT  35.112 72.419 35.208 73.861 ;
     RECT  40.776 72.467 41.76 72.851 ;
     RECT  13.512 72.659 15.072 73.717 ;
     RECT  33.048 72.757 34.416 73.333 ;
     RECT  30.84 72.803 32.1 74.629 ;
     RECT  5.544 72.805 6.624 73.477 ;
     RECT  40.632 72.851 41.76 76.357 ;
     RECT  19.752 72.901 20.784 73.525 ;
     RECT  41.784 72.947 42.9 75.157 ;
     RECT  73.128 72.995 73.176 74.389 ;
     RECT  28.248 72.997 29.4 74.437 ;
     RECT  33.24 73.333 34.416 74.389 ;
     RECT  9.336 73.379 10.5 74.965 ;
     RECT  46.248 73.477 47.472 74.243 ;
     RECT  5.688 73.571 6.672 73.763 ;
     RECT  13.608 73.717 15.072 73.861 ;
     RECT  5.688 73.763 6.816 74.723 ;
     RECT  26.208 73.763 26.7 74.053 ;
     RECT  13.608 73.861 14.88 75.013 ;
     RECT  16.212 73.907 17.616 74.869 ;
     RECT  25.656 74.053 26.7 75.299 ;
     RECT  22.104 74.197 23.424 75.541 ;
     RECT  49.176 74.293 50.688 74.339 ;
     RECT  28.392 74.437 29.4 75.829 ;
     RECT  45.36 74.483 45.6 74.677 ;
     RECT  51.432 74.627 52.848 75.637 ;
     RECT  30.84 74.629 31.872 76.357 ;
     RECT  43.992 74.677 45.6 75.445 ;
     RECT  5.592 74.723 6.816 77.653 ;
     RECT  16.344 74.869 17.616 75.205 ;
     RECT  10.812 74.965 12.192 75.013 ;
     RECT  13.608 75.013 14.784 75.155 ;
     RECT  13.608 75.155 14.832 75.157 ;
     RECT  33.24 75.155 34.8 76.453 ;
     RECT  13.656 75.157 14.832 75.971 ;
     RECT  41.88 75.157 42.9 77.365 ;
     RECT  16.344 75.205 17.424 76.019 ;
     RECT  25.608 75.299 26.7 77.413 ;
     RECT  73.08 75.395 73.176 76.885 ;
     RECT  43.992 75.445 45.12 75.637 ;
     RECT  22.104 75.541 23.328 76.309 ;
     RECT  9.192 75.587 10.5 77.173 ;
     RECT  43.992 75.637 45.024 75.683 ;
     RECT  51.528 75.637 52.848 76.979 ;
     RECT  45.168 75.779 45.6 77.077 ;
     RECT  13.512 75.971 14.832 78.613 ;
     RECT  10.812 76.019 12.192 77.893 ;
     RECT  16.212 76.019 17.424 76.355 ;
     RECT  36.912 76.019 37.5 76.069 ;
     RECT  46.2 76.067 46.248 76.597 ;
     RECT  35.208 76.069 36.24 76.261 ;
     RECT  36.264 76.069 37.5 77.555 ;
     RECT  17.544 76.307 18.6 77.891 ;
     RECT  16.212 76.355 17.52 77.845 ;
     RECT  33.48 76.453 34.8 77.795 ;
     RECT  46.2 76.597 47.568 77.125 ;
     RECT  51.48 76.979 52.848 77.509 ;
     RECT  46.2 77.125 47.232 77.989 ;
     RECT  27.528 77.171 28.752 77.555 ;
     RECT  9.192 77.173 10.368 77.701 ;
     RECT  45.168 77.363 45.6 78.517 ;
     RECT  25.656 77.413 26.7 77.939 ;
     RECT  51.48 77.509 52.512 77.941 ;
     RECT  2.712 77.701 3.936 77.989 ;
     RECT  38.088 77.701 39.216 79.045 ;
     RECT  17.496 77.891 18.6 79.765 ;
     RECT  10.812 77.893 12 81.539 ;
     RECT  25.032 77.939 25.08 79.045 ;
     RECT  8.112 77.987 9.168 78.755 ;
     RECT  18.912 78.227 19.968 78.755 ;
     RECT  43.32 78.517 44.496 79.189 ;
     RECT  44.52 78.517 45.6 79.285 ;
     RECT  35.112 78.659 35.784 79.189 ;
     RECT  14.232 78.707 15.312 78.755 ;
     RECT  8.112 78.755 9.552 80.293 ;
     RECT  14.232 78.755 15.504 80.531 ;
     RECT  18.912 78.755 20.256 79.475 ;
     RECT  45.912 78.755 47.232 79.331 ;
     RECT  35.112 79.189 36.24 81.301 ;
     RECT  36.264 79.189 37.5 80.677 ;
     RECT  43.32 79.189 44.448 79.765 ;
     RECT  48.744 79.189 50.16 79.475 ;
     RECT  29.088 79.283 29.4 80.053 ;
     RECT  44.616 79.285 45.6 79.475 ;
     RECT  38.52 79.331 39.648 80.819 ;
     RECT  41.88 79.331 42.9 80.293 ;
     RECT  45.912 79.331 47.568 79.765 ;
     RECT  2.712 79.475 3.888 80.147 ;
     RECT  18.912 79.475 21.024 79.813 ;
     RECT  24.312 79.475 25.08 80.533 ;
     RECT  31.128 79.475 32.1 80.677 ;
     RECT  44.52 79.475 45.6 80.291 ;
     RECT  48.744 79.475 50.4 79.765 ;
     RECT  43.368 79.765 44.448 80.291 ;
     RECT  46.344 79.765 47.568 80.819 ;
     RECT  48.984 79.765 50.4 80.627 ;
     RECT  19.992 79.813 21.024 81.301 ;
     RECT  27.912 80.053 29.4 80.869 ;
     RECT  2.712 80.147 3.936 82.021 ;
     RECT  43.368 80.291 45.6 80.629 ;
     RECT  13.512 80.531 15.504 81.301 ;
     RECT  24.312 80.533 26.496 80.629 ;
     RECT  48.792 80.627 50.496 81.587 ;
     RECT  24.312 80.629 25.584 81.349 ;
     RECT  43.416 80.629 45.6 80.869 ;
     RECT  36.264 80.677 37.392 80.869 ;
     RECT  38.28 80.819 39.648 82.645 ;
     RECT  27.912 80.869 29.28 80.963 ;
     RECT  36.264 80.869 37.296 81.157 ;
     RECT  43.896 80.869 45.6 81.445 ;
     RECT  16.488 80.963 17.472 82.789 ;
     RECT  21.612 80.963 22.608 82.691 ;
     RECT  27.864 80.963 29.28 81.923 ;
     RECT  6.696 81.059 7.68 81.539 ;
     RECT  13.512 81.301 14.832 82.789 ;
     RECT  35.208 81.301 36.24 81.395 ;
     RECT  40.872 81.347 41.856 82.115 ;
     RECT  24.312 81.349 25.488 81.877 ;
     RECT  37.056 81.491 37.296 82.693 ;
     RECT  5.976 81.539 7.68 82.789 ;
     RECT  10.812 81.539 12.48 82.933 ;
     RECT  48.612 81.587 50.496 81.637 ;
     RECT  48.612 81.637 49.584 84.133 ;
     RECT  43.656 81.875 44.64 82.691 ;
     RECT  27.864 81.923 29.4 83.077 ;
     RECT  2.712 82.021 3.744 85.619 ;
     RECT  40.872 82.115 42.048 82.405 ;
     RECT  45.912 82.115 46.344 83.221 ;
     RECT  8.808 82.259 10.368 82.979 ;
     RECT  41.064 82.405 42.048 83.749 ;
     RECT  21.612 82.691 22.8 83.843 ;
     RECT  34.176 82.691 34.8 83.749 ;
     RECT  43.656 82.691 44.976 83.749 ;
     RECT  6.648 82.931 7.68 83.651 ;
     RECT  11.4 82.933 12.48 83.843 ;
     RECT  8.808 82.979 8.952 83.653 ;
     RECT  14.856 83.027 15.9 83.315 ;
     RECT  16.488 83.075 17.472 83.219 ;
     RECT  37.056 83.075 37.344 83.653 ;
     RECT  27.96 83.077 29.4 84.371 ;
     RECT  24.6 83.123 24.696 83.603 ;
     RECT  16.392 83.219 17.472 87.155 ;
     RECT  14.088 83.315 15.9 83.843 ;
     RECT  24.504 83.603 24.696 84.421 ;
     RECT  6.648 83.651 7.8 85.907 ;
     RECT  35.88 83.653 37.344 84.083 ;
     RECT  10.812 83.843 12.48 84.901 ;
     RECT  13.512 83.843 15.9 84.709 ;
     RECT  21.612 83.843 22.992 84.853 ;
     RECT  54.264 83.843 55.248 84.805 ;
     RECT  44.472 83.939 45.504 84.419 ;
     RECT  46.728 83.941 47.856 84.181 ;
     RECT  35.352 84.083 37.344 84.325 ;
     RECT  43.416 84.083 44.448 84.419 ;
     RECT  35.352 84.325 36.816 86.579 ;
     RECT  27.336 84.371 29.4 84.613 ;
     RECT  43.212 84.419 44.448 84.611 ;
     RECT  44.472 84.419 45.6 84.611 ;
     RECT  24.504 84.421 25.728 84.563 ;
     RECT  24.504 84.563 26.208 85.717 ;
     RECT  8.52 84.611 8.952 85.139 ;
     RECT  40.872 84.611 42.144 86.293 ;
     RECT  43.212 84.611 45.6 85.093 ;
     RECT  27.336 84.613 29.088 84.853 ;
     RECT  49.944 84.659 51 85.139 ;
     RECT  46.776 84.707 47.856 86.629 ;
     RECT  13.512 84.709 15.216 84.853 ;
     RECT  13.704 84.853 15.216 85.765 ;
     RECT  21.612 84.853 22.8 85.955 ;
     RECT  27.336 84.853 28.512 85.475 ;
     RECT  10.812 84.901 12 85.429 ;
     RECT  19.992 84.995 21.3 87.109 ;
     RECT  43.212 85.093 44.544 85.381 ;
     RECT  44.568 85.093 45.6 85.813 ;
     RECT  8.376 85.139 8.952 85.429 ;
     RECT  49.704 85.139 51 86.485 ;
     RECT  32.52 85.237 33.696 85.957 ;
     RECT  43.32 85.381 44.544 86.483 ;
     RECT  8.376 85.429 9.504 87.109 ;
     RECT  9.528 85.429 10.5 87.685 ;
     RECT  27.288 85.475 28.512 86.099 ;
     RECT  2.712 85.619 4.272 86.917 ;
     RECT  52.392 85.619 53.376 88.355 ;
     RECT  24.84 85.717 26.208 85.957 ;
     RECT  13.752 85.765 15.216 86.243 ;
     RECT  21.612 85.955 22.992 87.061 ;
     RECT  27.144 86.099 28.512 86.675 ;
     RECT  13.704 86.243 15.216 86.339 ;
     RECT  24.504 86.483 25.68 87.683 ;
     RECT  49.704 86.485 50.88 87.685 ;
     RECT  35.208 86.579 36.816 86.771 ;
     RECT  27.144 86.675 28.944 87.733 ;
     RECT  11.688 86.723 13.056 88.115 ;
     RECT  35.112 86.771 36.816 86.869 ;
     RECT  35.112 86.869 36.48 88.403 ;
     RECT  2.712 86.917 3.936 87.971 ;
     RECT  21.612 87.061 22.752 87.827 ;
     RECT  20.184 87.109 21.3 88.405 ;
     RECT  16.344 87.155 17.472 87.299 ;
     RECT  30.936 87.251 32.1 87.539 ;
     RECT  15.216 87.299 15.792 87.347 ;
     RECT  16.212 87.299 17.472 88.403 ;
     RECT  41.592 87.299 42.9 90.515 ;
     RECT  15.216 87.347 15.9 88.309 ;
     RECT  32.52 87.347 33.696 87.827 ;
     RECT  30.792 87.539 32.1 88.019 ;
     RECT  54.888 87.635 56.016 88.499 ;
     RECT  46.152 87.683 47.328 88.595 ;
     RECT  27.144 87.733 28.32 88.643 ;
     RECT  21.612 87.827 22.992 88.163 ;
     RECT  4.8 87.971 4.896 89.461 ;
     RECT  28.344 88.067 29.4 88.643 ;
     RECT  11.592 88.115 13.056 88.211 ;
     RECT  21.612 88.163 23.136 88.451 ;
     RECT  9.288 88.211 10.5 88.643 ;
     RECT  13.512 88.309 14.544 88.979 ;
     RECT  14.568 88.309 15.9 88.885 ;
     RECT  52.296 88.355 53.376 89.219 ;
     RECT  16.212 88.403 16.344 88.645 ;
     RECT  35.112 88.403 36.576 90.275 ;
     RECT  43.212 88.403 43.32 88.741 ;
     RECT  20.184 88.405 21.168 88.499 ;
     RECT  20.04 88.499 21.168 89.507 ;
     RECT  48.612 88.499 50.112 89.267 ;
     RECT  54.792 88.499 56.016 88.643 ;
     RECT  9.096 88.643 10.5 90.227 ;
     RECT  27.144 88.643 27.24 88.645 ;
     RECT  54.744 88.643 56.016 89.459 ;
     RECT  43.212 88.741 44.688 89.699 ;
     RECT  14.808 88.885 15.9 89.987 ;
     RECT  13.512 88.979 14.784 89.987 ;
     RECT  52.248 89.219 53.568 89.507 ;
     RECT  54.696 89.459 56.016 89.603 ;
     RECT  52.248 89.507 53.7 90.515 ;
     RECT  37.812 89.555 39.312 90.083 ;
     RECT  54.696 89.603 56.064 89.699 ;
     RECT  57.576 89.987 58.944 90.131 ;
     RECT  57.48 90.131 58.944 90.227 ;
     RECT  66.12 90.323 67.104 90.467 ;
     RECT  70.212 90.371 71.664 90.419 ;
     RECT  68.616 90.563 69.9 90.611 ;
  END
END dsfd_xstg_515
END LIBRARY
